VERSION 5.8 ;
BUSBITCHARS "[]" ;
DIVIDERCHAR "/" ;
UNITS
    DATABASE MICRONS 1000 ;
END UNITS

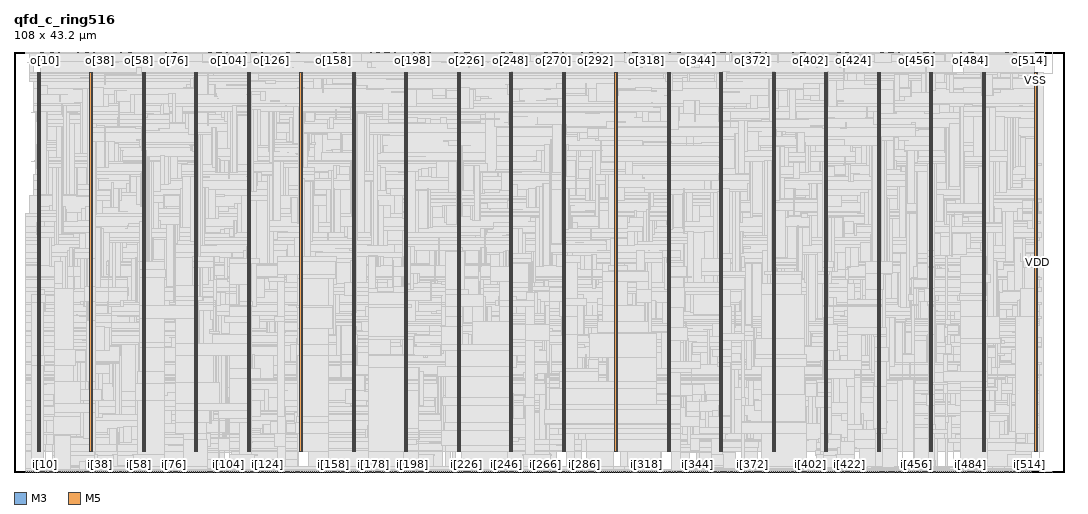
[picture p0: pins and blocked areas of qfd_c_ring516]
MACRO qfd_c_ring516
  FOREIGN qfd_c_ring516 0 0 ;
  CLASS BLOCK ;
  SIZE 108 BY 43.2 ;
  PIN ck_r
    DIRECTION INPUT ;
    USE SIGNAL ;
    PORT
      LAYER M3 ;
        RECT  105.984 43.162 106.002 43.2 ;
    END
  END ck_r
  PIN ck_w
    DIRECTION INPUT ;
    USE SIGNAL ;
    PORT
      LAYER M3 ;
        RECT  105.984 0 106.002 0.038 ;
    END
  END ck_w
  PIN i[0]
    DIRECTION INPUT ;
    USE SIGNAL ;
    PORT
      LAYER M3 ;
        RECT  1.188 0 1.206 0.038 ;
    END
  END i[0]
  PIN i[100]
    DIRECTION INPUT ;
    USE SIGNAL ;
    PORT
      LAYER M3 ;
        RECT  21.276 0 21.294 0.038 ;
    END
  END i[100]
  PIN i[101]
    DIRECTION INPUT ;
    USE SIGNAL ;
    PORT
      LAYER M5 ;
        RECT  21.456 0 21.48 0.084 ;
    END
  END i[101]
  PIN i[102]
    DIRECTION INPUT ;
    USE SIGNAL ;
    PORT
      LAYER M3 ;
        RECT  21.672 0 21.69 0.038 ;
    END
  END i[102]
  PIN i[103]
    DIRECTION INPUT ;
    USE SIGNAL ;
    PORT
      LAYER M5 ;
        RECT  21.888 0 21.912 0.084 ;
    END
  END i[103]
  PIN i[104]
    DIRECTION INPUT ;
    USE SIGNAL ;
    PORT
      LAYER M3 ;
        RECT  22.068 0 22.086 0.038 ;
    END
  END i[104]
  PIN i[105]
    DIRECTION INPUT ;
    USE SIGNAL ;
    PORT
      LAYER M5 ;
        RECT  22.272 0 22.296 0.084 ;
    END
  END i[105]
  PIN i[106]
    DIRECTION INPUT ;
    USE SIGNAL ;
    PORT
      LAYER M3 ;
        RECT  22.464 0 22.482 0.038 ;
    END
  END i[106]
  PIN i[107]
    DIRECTION INPUT ;
    USE SIGNAL ;
    PORT
      LAYER M5 ;
        RECT  22.656 0 22.68 0.084 ;
    END
  END i[107]
  PIN i[108]
    DIRECTION INPUT ;
    USE SIGNAL ;
    PORT
      LAYER M3 ;
        RECT  22.86 0 22.878 0.038 ;
    END
  END i[108]
  PIN i[109]
    DIRECTION INPUT ;
    USE SIGNAL ;
    PORT
      LAYER M5 ;
        RECT  23.088 0 23.112 0.084 ;
    END
  END i[109]
  PIN i[10]
    DIRECTION INPUT ;
    USE SIGNAL ;
    PORT
      LAYER M3 ;
        RECT  3.168 0 3.186 0.038 ;
    END
  END i[10]
  PIN i[110]
    DIRECTION INPUT ;
    USE SIGNAL ;
    PORT
      LAYER M3 ;
        RECT  23.292 0 23.31 0.038 ;
    END
  END i[110]
  PIN i[111]
    DIRECTION INPUT ;
    USE SIGNAL ;
    PORT
      LAYER M5 ;
        RECT  23.472 0 23.496 0.084 ;
    END
  END i[111]
  PIN i[112]
    DIRECTION INPUT ;
    USE SIGNAL ;
    PORT
      LAYER M3 ;
        RECT  23.688 0 23.706 0.038 ;
    END
  END i[112]
  PIN i[113]
    DIRECTION INPUT ;
    USE SIGNAL ;
    PORT
      LAYER M5 ;
        RECT  23.856 0 23.88 0.084 ;
    END
  END i[113]
  PIN i[114]
    DIRECTION INPUT ;
    USE SIGNAL ;
    PORT
      LAYER M3 ;
        RECT  24.084 0 24.102 0.038 ;
    END
  END i[114]
  PIN i[115]
    DIRECTION INPUT ;
    USE SIGNAL ;
    PORT
      LAYER M5 ;
        RECT  24.288 0 24.312 0.084 ;
    END
  END i[115]
  PIN i[116]
    DIRECTION INPUT ;
    USE SIGNAL ;
    PORT
      LAYER M3 ;
        RECT  24.48 0 24.498 0.038 ;
    END
  END i[116]
  PIN i[117]
    DIRECTION INPUT ;
    USE SIGNAL ;
    PORT
      LAYER M5 ;
        RECT  24.672 0 24.696 0.084 ;
    END
  END i[117]
  PIN i[118]
    DIRECTION INPUT ;
    USE SIGNAL ;
    PORT
      LAYER M3 ;
        RECT  24.876 0 24.894 0.038 ;
    END
  END i[118]
  PIN i[119]
    DIRECTION INPUT ;
    USE SIGNAL ;
    PORT
      LAYER M5 ;
        RECT  25.056 0 25.08 0.084 ;
    END
  END i[119]
  PIN i[11]
    DIRECTION INPUT ;
    USE SIGNAL ;
    PORT
      LAYER M5 ;
        RECT  3.36 0 3.384 0.084 ;
    END
  END i[11]
  PIN i[120]
    DIRECTION INPUT ;
    USE SIGNAL ;
    PORT
      LAYER M3 ;
        RECT  25.272 0 25.29 0.038 ;
    END
  END i[120]
  PIN i[121]
    DIRECTION INPUT ;
    USE SIGNAL ;
    PORT
      LAYER M5 ;
        RECT  25.488 0 25.512 0.084 ;
    END
  END i[121]
  PIN i[122]
    DIRECTION INPUT ;
    USE SIGNAL ;
    PORT
      LAYER M3 ;
        RECT  25.668 0 25.686 0.038 ;
    END
  END i[122]
  PIN i[123]
    DIRECTION INPUT ;
    USE SIGNAL ;
    PORT
      LAYER M5 ;
        RECT  25.872 0 25.896 0.084 ;
    END
  END i[123]
  PIN i[124]
    DIRECTION INPUT ;
    USE SIGNAL ;
    PORT
      LAYER M3 ;
        RECT  26.1 0 26.118 0.038 ;
    END
  END i[124]
  PIN i[125]
    DIRECTION INPUT ;
    USE SIGNAL ;
    PORT
      LAYER M5 ;
        RECT  26.304 0 26.328 0.084 ;
    END
  END i[125]
  PIN i[126]
    DIRECTION INPUT ;
    USE SIGNAL ;
    PORT
      LAYER M3 ;
        RECT  26.496 0 26.514 0.038 ;
    END
  END i[126]
  PIN i[127]
    DIRECTION INPUT ;
    USE SIGNAL ;
    PORT
      LAYER M5 ;
        RECT  26.688 0 26.712 0.084 ;
    END
  END i[127]
  PIN i[128]
    DIRECTION INPUT ;
    USE SIGNAL ;
    PORT
      LAYER M3 ;
        RECT  26.892 0 26.91 0.038 ;
    END
  END i[128]
  PIN i[129]
    DIRECTION INPUT ;
    USE SIGNAL ;
    PORT
      LAYER M5 ;
        RECT  27.072 0 27.096 0.084 ;
    END
  END i[129]
  PIN i[12]
    DIRECTION INPUT ;
    USE SIGNAL ;
    PORT
      LAYER M3 ;
        RECT  3.6 0 3.618 0.038 ;
    END
  END i[12]
  PIN i[130]
    DIRECTION INPUT ;
    USE SIGNAL ;
    PORT
      LAYER M3 ;
        RECT  27.288 0 27.306 0.038 ;
    END
  END i[130]
  PIN i[131]
    DIRECTION INPUT ;
    USE SIGNAL ;
    PORT
      LAYER M5 ;
        RECT  27.504 0 27.528 0.084 ;
    END
  END i[131]
  PIN i[132]
    DIRECTION INPUT ;
    USE SIGNAL ;
    PORT
      LAYER M3 ;
        RECT  27.684 0 27.702 0.038 ;
    END
  END i[132]
  PIN i[133]
    DIRECTION INPUT ;
    USE SIGNAL ;
    PORT
      LAYER M5 ;
        RECT  27.888 0 27.912 0.084 ;
    END
  END i[133]
  PIN i[134]
    DIRECTION INPUT ;
    USE SIGNAL ;
    PORT
      LAYER M3 ;
        RECT  28.08 0 28.098 0.038 ;
    END
  END i[134]
  PIN i[135]
    DIRECTION INPUT ;
    USE SIGNAL ;
    PORT
      LAYER M5 ;
        RECT  28.272 0 28.296 0.084 ;
    END
  END i[135]
  PIN i[136]
    DIRECTION INPUT ;
    USE SIGNAL ;
    PORT
      LAYER M3 ;
        RECT  28.512 0 28.53 0.038 ;
    END
  END i[136]
  PIN i[137]
    DIRECTION INPUT ;
    USE SIGNAL ;
    PORT
      LAYER M5 ;
        RECT  28.704 0 28.728 0.084 ;
    END
  END i[137]
  PIN i[138]
    DIRECTION INPUT ;
    USE SIGNAL ;
    PORT
      LAYER M3 ;
        RECT  28.908 0 28.926 0.038 ;
    END
  END i[138]
  PIN i[139]
    DIRECTION INPUT ;
    USE SIGNAL ;
    PORT
      LAYER M5 ;
        RECT  29.088 0 29.112 0.084 ;
    END
  END i[139]
  PIN i[13]
    DIRECTION INPUT ;
    USE SIGNAL ;
    PORT
      LAYER M5 ;
        RECT  3.792 0 3.816 0.084 ;
    END
  END i[13]
  PIN i[140]
    DIRECTION INPUT ;
    USE SIGNAL ;
    PORT
      LAYER M3 ;
        RECT  29.304 0 29.322 0.038 ;
    END
  END i[140]
  PIN i[141]
    DIRECTION INPUT ;
    USE SIGNAL ;
    PORT
      LAYER M5 ;
        RECT  29.52 0 29.544 0.084 ;
    END
  END i[141]
  PIN i[142]
    DIRECTION INPUT ;
    USE SIGNAL ;
    PORT
      LAYER M3 ;
        RECT  29.7 0 29.718 0.038 ;
    END
  END i[142]
  PIN i[143]
    DIRECTION INPUT ;
    USE SIGNAL ;
    PORT
      LAYER M5 ;
        RECT  29.904 0 29.928 0.084 ;
    END
  END i[143]
  PIN i[144]
    DIRECTION INPUT ;
    USE SIGNAL ;
    PORT
      LAYER M3 ;
        RECT  30.096 0 30.114 0.038 ;
    END
  END i[144]
  PIN i[145]
    DIRECTION INPUT ;
    USE SIGNAL ;
    PORT
      LAYER M5 ;
        RECT  30.288 0 30.312 0.084 ;
    END
  END i[145]
  PIN i[146]
    DIRECTION INPUT ;
    USE SIGNAL ;
    PORT
      LAYER M3 ;
        RECT  30.492 0 30.51 0.038 ;
    END
  END i[146]
  PIN i[147]
    DIRECTION INPUT ;
    USE SIGNAL ;
    PORT
      LAYER M5 ;
        RECT  30.72 0 30.744 0.084 ;
    END
  END i[147]
  PIN i[148]
    DIRECTION INPUT ;
    USE SIGNAL ;
    PORT
      LAYER M3 ;
        RECT  30.924 0 30.942 0.038 ;
    END
  END i[148]
  PIN i[149]
    DIRECTION INPUT ;
    USE SIGNAL ;
    PORT
      LAYER M5 ;
        RECT  31.104 0 31.128 0.084 ;
    END
  END i[149]
  PIN i[14]
    DIRECTION INPUT ;
    USE SIGNAL ;
    PORT
      LAYER M3 ;
        RECT  3.996 0 4.014 0.038 ;
    END
  END i[14]
  PIN i[150]
    DIRECTION INPUT ;
    USE SIGNAL ;
    PORT
      LAYER M3 ;
        RECT  31.32 0 31.338 0.038 ;
    END
  END i[150]
  PIN i[151]
    DIRECTION INPUT ;
    USE SIGNAL ;
    PORT
      LAYER M5 ;
        RECT  31.488 0 31.512 0.084 ;
    END
  END i[151]
  PIN i[152]
    DIRECTION INPUT ;
    USE SIGNAL ;
    PORT
      LAYER M3 ;
        RECT  31.716 0 31.734 0.038 ;
    END
  END i[152]
  PIN i[153]
    DIRECTION INPUT ;
    USE SIGNAL ;
    PORT
      LAYER M5 ;
        RECT  31.92 0 31.944 0.084 ;
    END
  END i[153]
  PIN i[154]
    DIRECTION INPUT ;
    USE SIGNAL ;
    PORT
      LAYER M3 ;
        RECT  32.112 0 32.13 0.038 ;
    END
  END i[154]
  PIN i[155]
    DIRECTION INPUT ;
    USE SIGNAL ;
    PORT
      LAYER M5 ;
        RECT  32.304 0 32.328 0.084 ;
    END
  END i[155]
  PIN i[156]
    DIRECTION INPUT ;
    USE SIGNAL ;
    PORT
      LAYER M3 ;
        RECT  32.508 0 32.526 0.038 ;
    END
  END i[156]
  PIN i[157]
    DIRECTION INPUT ;
    USE SIGNAL ;
    PORT
      LAYER M5 ;
        RECT  32.736 0 32.76 0.084 ;
    END
  END i[157]
  PIN i[158]
    DIRECTION INPUT ;
    USE SIGNAL ;
    PORT
      LAYER M3 ;
        RECT  32.904 0 32.922 0.038 ;
    END
  END i[158]
  PIN i[159]
    DIRECTION INPUT ;
    USE SIGNAL ;
    PORT
      LAYER M5 ;
        RECT  33.12 0 33.144 0.084 ;
    END
  END i[159]
  PIN i[15]
    DIRECTION INPUT ;
    USE SIGNAL ;
    PORT
      LAYER M5 ;
        RECT  4.176 0 4.2 0.084 ;
    END
  END i[15]
  PIN i[160]
    DIRECTION INPUT ;
    USE SIGNAL ;
    PORT
      LAYER M3 ;
        RECT  33.336 0 33.354 0.038 ;
    END
  END i[160]
  PIN i[161]
    DIRECTION INPUT ;
    USE SIGNAL ;
    PORT
      LAYER M5 ;
        RECT  33.504 0 33.528 0.084 ;
    END
  END i[161]
  PIN i[162]
    DIRECTION INPUT ;
    USE SIGNAL ;
    PORT
      LAYER M3 ;
        RECT  33.732 0 33.75 0.038 ;
    END
  END i[162]
  PIN i[163]
    DIRECTION INPUT ;
    USE SIGNAL ;
    PORT
      LAYER M5 ;
        RECT  33.936 0 33.96 0.084 ;
    END
  END i[163]
  PIN i[164]
    DIRECTION INPUT ;
    USE SIGNAL ;
    PORT
      LAYER M3 ;
        RECT  34.128 0 34.146 0.038 ;
    END
  END i[164]
  PIN i[165]
    DIRECTION INPUT ;
    USE SIGNAL ;
    PORT
      LAYER M5 ;
        RECT  34.32 0 34.344 0.084 ;
    END
  END i[165]
  PIN i[166]
    DIRECTION INPUT ;
    USE SIGNAL ;
    PORT
      LAYER M3 ;
        RECT  34.524 0 34.542 0.038 ;
    END
  END i[166]
  PIN i[167]
    DIRECTION INPUT ;
    USE SIGNAL ;
    PORT
      LAYER M5 ;
        RECT  34.704 0 34.728 0.084 ;
    END
  END i[167]
  PIN i[168]
    DIRECTION INPUT ;
    USE SIGNAL ;
    PORT
      LAYER M3 ;
        RECT  34.92 0 34.938 0.038 ;
    END
  END i[168]
  PIN i[169]
    DIRECTION INPUT ;
    USE SIGNAL ;
    PORT
      LAYER M5 ;
        RECT  35.136 0 35.16 0.084 ;
    END
  END i[169]
  PIN i[16]
    DIRECTION INPUT ;
    USE SIGNAL ;
    PORT
      LAYER M3 ;
        RECT  4.392 0 4.41 0.038 ;
    END
  END i[16]
  PIN i[170]
    DIRECTION INPUT ;
    USE SIGNAL ;
    PORT
      LAYER M3 ;
        RECT  35.316 0 35.334 0.038 ;
    END
  END i[170]
  PIN i[171]
    DIRECTION INPUT ;
    USE SIGNAL ;
    PORT
      LAYER M5 ;
        RECT  35.52 0 35.544 0.084 ;
    END
  END i[171]
  PIN i[172]
    DIRECTION INPUT ;
    USE SIGNAL ;
    PORT
      LAYER M3 ;
        RECT  35.748 0 35.766 0.038 ;
    END
  END i[172]
  PIN i[173]
    DIRECTION INPUT ;
    USE SIGNAL ;
    PORT
      LAYER M5 ;
        RECT  35.952 0 35.976 0.084 ;
    END
  END i[173]
  PIN i[174]
    DIRECTION INPUT ;
    USE SIGNAL ;
    PORT
      LAYER M3 ;
        RECT  36.144 0 36.162 0.038 ;
    END
  END i[174]
  PIN i[175]
    DIRECTION INPUT ;
    USE SIGNAL ;
    PORT
      LAYER M5 ;
        RECT  36.336 0 36.36 0.084 ;
    END
  END i[175]
  PIN i[176]
    DIRECTION INPUT ;
    USE SIGNAL ;
    PORT
      LAYER M3 ;
        RECT  36.54 0 36.558 0.038 ;
    END
  END i[176]
  PIN i[177]
    DIRECTION INPUT ;
    USE SIGNAL ;
    PORT
      LAYER M5 ;
        RECT  36.72 0 36.744 0.084 ;
    END
  END i[177]
  PIN i[178]
    DIRECTION INPUT ;
    USE SIGNAL ;
    PORT
      LAYER M3 ;
        RECT  36.936 0 36.954 0.038 ;
    END
  END i[178]
  PIN i[179]
    DIRECTION INPUT ;
    USE SIGNAL ;
    PORT
      LAYER M5 ;
        RECT  37.152 0 37.176 0.084 ;
    END
  END i[179]
  PIN i[17]
    DIRECTION INPUT ;
    USE SIGNAL ;
    PORT
      LAYER M5 ;
        RECT  4.608 0 4.632 0.084 ;
    END
  END i[17]
  PIN i[180]
    DIRECTION INPUT ;
    USE SIGNAL ;
    PORT
      LAYER M3 ;
        RECT  37.332 0 37.35 0.038 ;
    END
  END i[180]
  PIN i[181]
    DIRECTION INPUT ;
    USE SIGNAL ;
    PORT
      LAYER M5 ;
        RECT  37.536 0 37.56 0.084 ;
    END
  END i[181]
  PIN i[182]
    DIRECTION INPUT ;
    USE SIGNAL ;
    PORT
      LAYER M3 ;
        RECT  37.728 0 37.746 0.038 ;
    END
  END i[182]
  PIN i[183]
    DIRECTION INPUT ;
    USE SIGNAL ;
    PORT
      LAYER M5 ;
        RECT  37.92 0 37.944 0.084 ;
    END
  END i[183]
  PIN i[184]
    DIRECTION INPUT ;
    USE SIGNAL ;
    PORT
      LAYER M3 ;
        RECT  38.16 0 38.178 0.038 ;
    END
  END i[184]
  PIN i[185]
    DIRECTION INPUT ;
    USE SIGNAL ;
    PORT
      LAYER M5 ;
        RECT  38.352 0 38.376 0.084 ;
    END
  END i[185]
  PIN i[186]
    DIRECTION INPUT ;
    USE SIGNAL ;
    PORT
      LAYER M3 ;
        RECT  38.556 0 38.574 0.038 ;
    END
  END i[186]
  PIN i[187]
    DIRECTION INPUT ;
    USE SIGNAL ;
    PORT
      LAYER M5 ;
        RECT  38.736 0 38.76 0.084 ;
    END
  END i[187]
  PIN i[188]
    DIRECTION INPUT ;
    USE SIGNAL ;
    PORT
      LAYER M3 ;
        RECT  38.952 0 38.97 0.038 ;
    END
  END i[188]
  PIN i[189]
    DIRECTION INPUT ;
    USE SIGNAL ;
    PORT
      LAYER M5 ;
        RECT  39.168 0 39.192 0.084 ;
    END
  END i[189]
  PIN i[18]
    DIRECTION INPUT ;
    USE SIGNAL ;
    PORT
      LAYER M3 ;
        RECT  4.788 0 4.806 0.038 ;
    END
  END i[18]
  PIN i[190]
    DIRECTION INPUT ;
    USE SIGNAL ;
    PORT
      LAYER M3 ;
        RECT  39.348 0 39.366 0.038 ;
    END
  END i[190]
  PIN i[191]
    DIRECTION INPUT ;
    USE SIGNAL ;
    PORT
      LAYER M5 ;
        RECT  39.552 0 39.576 0.084 ;
    END
  END i[191]
  PIN i[192]
    DIRECTION INPUT ;
    USE SIGNAL ;
    PORT
      LAYER M3 ;
        RECT  39.744 0 39.762 0.038 ;
    END
  END i[192]
  PIN i[193]
    DIRECTION INPUT ;
    USE SIGNAL ;
    PORT
      LAYER M5 ;
        RECT  39.936 0 39.96 0.084 ;
    END
  END i[193]
  PIN i[194]
    DIRECTION INPUT ;
    USE SIGNAL ;
    PORT
      LAYER M3 ;
        RECT  40.14 0 40.158 0.038 ;
    END
  END i[194]
  PIN i[195]
    DIRECTION INPUT ;
    USE SIGNAL ;
    PORT
      LAYER M5 ;
        RECT  40.368 0 40.392 0.084 ;
    END
  END i[195]
  PIN i[196]
    DIRECTION INPUT ;
    USE SIGNAL ;
    PORT
      LAYER M3 ;
        RECT  40.572 0 40.59 0.038 ;
    END
  END i[196]
  PIN i[197]
    DIRECTION INPUT ;
    USE SIGNAL ;
    PORT
      LAYER M5 ;
        RECT  40.752 0 40.776 0.084 ;
    END
  END i[197]
  PIN i[198]
    DIRECTION INPUT ;
    USE SIGNAL ;
    PORT
      LAYER M3 ;
        RECT  40.968 0 40.986 0.038 ;
    END
  END i[198]
  PIN i[199]
    DIRECTION INPUT ;
    USE SIGNAL ;
    PORT
      LAYER M5 ;
        RECT  41.136 0 41.16 0.084 ;
    END
  END i[199]
  PIN i[19]
    DIRECTION INPUT ;
    USE SIGNAL ;
    PORT
      LAYER M5 ;
        RECT  4.992 0 5.016 0.084 ;
    END
  END i[19]
  PIN i[1]
    DIRECTION INPUT ;
    USE SIGNAL ;
    PORT
      LAYER M5 ;
        RECT  1.392 0 1.416 0.084 ;
    END
  END i[1]
  PIN i[200]
    DIRECTION INPUT ;
    USE SIGNAL ;
    PORT
      LAYER M3 ;
        RECT  41.364 0 41.382 0.038 ;
    END
  END i[200]
  PIN i[201]
    DIRECTION INPUT ;
    USE SIGNAL ;
    PORT
      LAYER M5 ;
        RECT  41.568 0 41.592 0.084 ;
    END
  END i[201]
  PIN i[202]
    DIRECTION INPUT ;
    USE SIGNAL ;
    PORT
      LAYER M3 ;
        RECT  41.76 0 41.778 0.038 ;
    END
  END i[202]
  PIN i[203]
    DIRECTION INPUT ;
    USE SIGNAL ;
    PORT
      LAYER M5 ;
        RECT  41.952 0 41.976 0.084 ;
    END
  END i[203]
  PIN i[204]
    DIRECTION INPUT ;
    USE SIGNAL ;
    PORT
      LAYER M3 ;
        RECT  42.156 0 42.174 0.038 ;
    END
  END i[204]
  PIN i[205]
    DIRECTION INPUT ;
    USE SIGNAL ;
    PORT
      LAYER M5 ;
        RECT  42.336 0 42.36 0.084 ;
    END
  END i[205]
  PIN i[206]
    DIRECTION INPUT ;
    USE SIGNAL ;
    PORT
      LAYER M3 ;
        RECT  42.552 0 42.57 0.038 ;
    END
  END i[206]
  PIN i[207]
    DIRECTION INPUT ;
    USE SIGNAL ;
    PORT
      LAYER M5 ;
        RECT  42.768 0 42.792 0.084 ;
    END
  END i[207]
  PIN i[208]
    DIRECTION INPUT ;
    USE SIGNAL ;
    PORT
      LAYER M3 ;
        RECT  42.948 0 42.966 0.038 ;
    END
  END i[208]
  PIN i[209]
    DIRECTION INPUT ;
    USE SIGNAL ;
    PORT
      LAYER M5 ;
        RECT  43.152 0 43.176 0.084 ;
    END
  END i[209]
  PIN i[20]
    DIRECTION INPUT ;
    USE SIGNAL ;
    PORT
      LAYER M3 ;
        RECT  5.184 0 5.202 0.038 ;
    END
  END i[20]
  PIN i[210]
    DIRECTION INPUT ;
    USE SIGNAL ;
    PORT
      LAYER M3 ;
        RECT  43.38 0 43.398 0.038 ;
    END
  END i[210]
  PIN i[211]
    DIRECTION INPUT ;
    USE SIGNAL ;
    PORT
      LAYER M5 ;
        RECT  43.584 0 43.608 0.084 ;
    END
  END i[211]
  PIN i[212]
    DIRECTION INPUT ;
    USE SIGNAL ;
    PORT
      LAYER M3 ;
        RECT  43.776 0 43.794 0.038 ;
    END
  END i[212]
  PIN i[213]
    DIRECTION INPUT ;
    USE SIGNAL ;
    PORT
      LAYER M5 ;
        RECT  43.968 0 43.992 0.084 ;
    END
  END i[213]
  PIN i[214]
    DIRECTION INPUT ;
    USE SIGNAL ;
    PORT
      LAYER M3 ;
        RECT  44.172 0 44.19 0.038 ;
    END
  END i[214]
  PIN i[215]
    DIRECTION INPUT ;
    USE SIGNAL ;
    PORT
      LAYER M5 ;
        RECT  44.352 0 44.376 0.084 ;
    END
  END i[215]
  PIN i[216]
    DIRECTION INPUT ;
    USE SIGNAL ;
    PORT
      LAYER M3 ;
        RECT  44.568 0 44.586 0.038 ;
    END
  END i[216]
  PIN i[217]
    DIRECTION INPUT ;
    USE SIGNAL ;
    PORT
      LAYER M5 ;
        RECT  44.784 0 44.808 0.084 ;
    END
  END i[217]
  PIN i[218]
    DIRECTION INPUT ;
    USE SIGNAL ;
    PORT
      LAYER M3 ;
        RECT  44.964 0 44.982 0.038 ;
    END
  END i[218]
  PIN i[219]
    DIRECTION INPUT ;
    USE SIGNAL ;
    PORT
      LAYER M5 ;
        RECT  45.168 0 45.192 0.084 ;
    END
  END i[219]
  PIN i[21]
    DIRECTION INPUT ;
    USE SIGNAL ;
    PORT
      LAYER M5 ;
        RECT  5.376 0 5.4 0.084 ;
    END
  END i[21]
  PIN i[220]
    DIRECTION INPUT ;
    USE SIGNAL ;
    PORT
      LAYER M3 ;
        RECT  45.36 0 45.378 0.038 ;
    END
  END i[220]
  PIN i[221]
    DIRECTION INPUT ;
    USE SIGNAL ;
    PORT
      LAYER M5 ;
        RECT  45.552 0 45.576 0.084 ;
    END
  END i[221]
  PIN i[222]
    DIRECTION INPUT ;
    USE SIGNAL ;
    PORT
      LAYER M3 ;
        RECT  45.792 0 45.81 0.038 ;
    END
  END i[222]
  PIN i[223]
    DIRECTION INPUT ;
    USE SIGNAL ;
    PORT
      LAYER M5 ;
        RECT  45.984 0 46.008 0.084 ;
    END
  END i[223]
  PIN i[224]
    DIRECTION INPUT ;
    USE SIGNAL ;
    PORT
      LAYER M3 ;
        RECT  46.188 0 46.206 0.038 ;
    END
  END i[224]
  PIN i[225]
    DIRECTION INPUT ;
    USE SIGNAL ;
    PORT
      LAYER M5 ;
        RECT  46.368 0 46.392 0.084 ;
    END
  END i[225]
  PIN i[226]
    DIRECTION INPUT ;
    USE SIGNAL ;
    PORT
      LAYER M3 ;
        RECT  46.584 0 46.602 0.038 ;
    END
  END i[226]
  PIN i[227]
    DIRECTION INPUT ;
    USE SIGNAL ;
    PORT
      LAYER M5 ;
        RECT  46.8 0 46.824 0.084 ;
    END
  END i[227]
  PIN i[228]
    DIRECTION INPUT ;
    USE SIGNAL ;
    PORT
      LAYER M3 ;
        RECT  46.98 0 46.998 0.038 ;
    END
  END i[228]
  PIN i[229]
    DIRECTION INPUT ;
    USE SIGNAL ;
    PORT
      LAYER M5 ;
        RECT  47.184 0 47.208 0.084 ;
    END
  END i[229]
  PIN i[22]
    DIRECTION INPUT ;
    USE SIGNAL ;
    PORT
      LAYER M3 ;
        RECT  5.58 0 5.598 0.038 ;
    END
  END i[22]
  PIN i[230]
    DIRECTION INPUT ;
    USE SIGNAL ;
    PORT
      LAYER M3 ;
        RECT  47.376 0 47.394 0.038 ;
    END
  END i[230]
  PIN i[231]
    DIRECTION INPUT ;
    USE SIGNAL ;
    PORT
      LAYER M5 ;
        RECT  47.568 0 47.592 0.084 ;
    END
  END i[231]
  PIN i[232]
    DIRECTION INPUT ;
    USE SIGNAL ;
    PORT
      LAYER M3 ;
        RECT  47.772 0 47.79 0.038 ;
    END
  END i[232]
  PIN i[233]
    DIRECTION INPUT ;
    USE SIGNAL ;
    PORT
      LAYER M5 ;
        RECT  48 0 48.024 0.084 ;
    END
  END i[233]
  PIN i[234]
    DIRECTION INPUT ;
    USE SIGNAL ;
    PORT
      LAYER M3 ;
        RECT  48.204 0 48.222 0.038 ;
    END
  END i[234]
  PIN i[235]
    DIRECTION INPUT ;
    USE SIGNAL ;
    PORT
      LAYER M5 ;
        RECT  48.384 0 48.408 0.084 ;
    END
  END i[235]
  PIN i[236]
    DIRECTION INPUT ;
    USE SIGNAL ;
    PORT
      LAYER M3 ;
        RECT  48.6 0 48.618 0.038 ;
    END
  END i[236]
  PIN i[237]
    DIRECTION INPUT ;
    USE SIGNAL ;
    PORT
      LAYER M5 ;
        RECT  48.768 0 48.792 0.084 ;
    END
  END i[237]
  PIN i[238]
    DIRECTION INPUT ;
    USE SIGNAL ;
    PORT
      LAYER M3 ;
        RECT  48.996 0 49.014 0.038 ;
    END
  END i[238]
  PIN i[239]
    DIRECTION INPUT ;
    USE SIGNAL ;
    PORT
      LAYER M5 ;
        RECT  49.2 0 49.224 0.084 ;
    END
  END i[239]
  PIN i[23]
    DIRECTION INPUT ;
    USE SIGNAL ;
    PORT
      LAYER M5 ;
        RECT  5.808 0 5.832 0.084 ;
    END
  END i[23]
  PIN i[240]
    DIRECTION INPUT ;
    USE SIGNAL ;
    PORT
      LAYER M3 ;
        RECT  49.392 0 49.41 0.038 ;
    END
  END i[240]
  PIN i[241]
    DIRECTION INPUT ;
    USE SIGNAL ;
    PORT
      LAYER M5 ;
        RECT  49.584 0 49.608 0.084 ;
    END
  END i[241]
  PIN i[242]
    DIRECTION INPUT ;
    USE SIGNAL ;
    PORT
      LAYER M3 ;
        RECT  49.788 0 49.806 0.038 ;
    END
  END i[242]
  PIN i[243]
    DIRECTION INPUT ;
    USE SIGNAL ;
    PORT
      LAYER M5 ;
        RECT  50.016 0 50.04 0.084 ;
    END
  END i[243]
  PIN i[244]
    DIRECTION INPUT ;
    USE SIGNAL ;
    PORT
      LAYER M3 ;
        RECT  50.184 0 50.202 0.038 ;
    END
  END i[244]
  PIN i[245]
    DIRECTION INPUT ;
    USE SIGNAL ;
    PORT
      LAYER M5 ;
        RECT  50.4 0 50.424 0.084 ;
    END
  END i[245]
  PIN i[246]
    DIRECTION INPUT ;
    USE SIGNAL ;
    PORT
      LAYER M3 ;
        RECT  50.616 0 50.634 0.038 ;
    END
  END i[246]
  PIN i[247]
    DIRECTION INPUT ;
    USE SIGNAL ;
    PORT
      LAYER M5 ;
        RECT  50.784 0 50.808 0.084 ;
    END
  END i[247]
  PIN i[248]
    DIRECTION INPUT ;
    USE SIGNAL ;
    PORT
      LAYER M3 ;
        RECT  51.012 0 51.03 0.038 ;
    END
  END i[248]
  PIN i[249]
    DIRECTION INPUT ;
    USE SIGNAL ;
    PORT
      LAYER M5 ;
        RECT  51.216 0 51.24 0.084 ;
    END
  END i[249]
  PIN i[24]
    DIRECTION INPUT ;
    USE SIGNAL ;
    PORT
      LAYER M3 ;
        RECT  6.012 0 6.03 0.038 ;
    END
  END i[24]
  PIN i[250]
    DIRECTION INPUT ;
    USE SIGNAL ;
    PORT
      LAYER M3 ;
        RECT  51.408 0 51.426 0.038 ;
    END
  END i[250]
  PIN i[251]
    DIRECTION INPUT ;
    USE SIGNAL ;
    PORT
      LAYER M5 ;
        RECT  51.6 0 51.624 0.084 ;
    END
  END i[251]
  PIN i[252]
    DIRECTION INPUT ;
    USE SIGNAL ;
    PORT
      LAYER M3 ;
        RECT  51.804 0 51.822 0.038 ;
    END
  END i[252]
  PIN i[253]
    DIRECTION INPUT ;
    USE SIGNAL ;
    PORT
      LAYER M5 ;
        RECT  51.984 0 52.008 0.084 ;
    END
  END i[253]
  PIN i[254]
    DIRECTION INPUT ;
    USE SIGNAL ;
    PORT
      LAYER M3 ;
        RECT  52.2 0 52.218 0.038 ;
    END
  END i[254]
  PIN i[255]
    DIRECTION INPUT ;
    USE SIGNAL ;
    PORT
      LAYER M5 ;
        RECT  52.416 0 52.44 0.084 ;
    END
  END i[255]
  PIN i[256]
    DIRECTION INPUT ;
    USE SIGNAL ;
    PORT
      LAYER M3 ;
        RECT  52.596 0 52.614 0.038 ;
    END
  END i[256]
  PIN i[257]
    DIRECTION INPUT ;
    USE SIGNAL ;
    PORT
      LAYER M5 ;
        RECT  52.8 0 52.824 0.084 ;
    END
  END i[257]
  PIN i[258]
    DIRECTION INPUT ;
    USE SIGNAL ;
    PORT
      LAYER M3 ;
        RECT  53.028 0 53.046 0.038 ;
    END
  END i[258]
  PIN i[259]
    DIRECTION INPUT ;
    USE SIGNAL ;
    PORT
      LAYER M5 ;
        RECT  53.232 0 53.256 0.084 ;
    END
  END i[259]
  PIN i[25]
    DIRECTION INPUT ;
    USE SIGNAL ;
    PORT
      LAYER M5 ;
        RECT  6.192 0 6.216 0.084 ;
    END
  END i[25]
  PIN i[260]
    DIRECTION INPUT ;
    USE SIGNAL ;
    PORT
      LAYER M3 ;
        RECT  53.424 0 53.442 0.038 ;
    END
  END i[260]
  PIN i[261]
    DIRECTION INPUT ;
    USE SIGNAL ;
    PORT
      LAYER M5 ;
        RECT  53.616 0 53.64 0.084 ;
    END
  END i[261]
  PIN i[262]
    DIRECTION INPUT ;
    USE SIGNAL ;
    PORT
      LAYER M3 ;
        RECT  53.82 0 53.838 0.038 ;
    END
  END i[262]
  PIN i[263]
    DIRECTION INPUT ;
    USE SIGNAL ;
    PORT
      LAYER M5 ;
        RECT  54 0 54.024 0.084 ;
    END
  END i[263]
  PIN i[264]
    DIRECTION INPUT ;
    USE SIGNAL ;
    PORT
      LAYER M3 ;
        RECT  54.216 0 54.234 0.038 ;
    END
  END i[264]
  PIN i[265]
    DIRECTION INPUT ;
    USE SIGNAL ;
    PORT
      LAYER M5 ;
        RECT  54.432 0 54.456 0.084 ;
    END
  END i[265]
  PIN i[266]
    DIRECTION INPUT ;
    USE SIGNAL ;
    PORT
      LAYER M3 ;
        RECT  54.612 0 54.63 0.038 ;
    END
  END i[266]
  PIN i[267]
    DIRECTION INPUT ;
    USE SIGNAL ;
    PORT
      LAYER M5 ;
        RECT  54.816 0 54.84 0.084 ;
    END
  END i[267]
  PIN i[268]
    DIRECTION INPUT ;
    USE SIGNAL ;
    PORT
      LAYER M3 ;
        RECT  55.008 0 55.026 0.038 ;
    END
  END i[268]
  PIN i[269]
    DIRECTION INPUT ;
    USE SIGNAL ;
    PORT
      LAYER M5 ;
        RECT  55.2 0 55.224 0.084 ;
    END
  END i[269]
  PIN i[26]
    DIRECTION INPUT ;
    USE SIGNAL ;
    PORT
      LAYER M3 ;
        RECT  6.408 0 6.426 0.038 ;
    END
  END i[26]
  PIN i[270]
    DIRECTION INPUT ;
    USE SIGNAL ;
    PORT
      LAYER M3 ;
        RECT  55.44 0 55.458 0.038 ;
    END
  END i[270]
  PIN i[271]
    DIRECTION INPUT ;
    USE SIGNAL ;
    PORT
      LAYER M5 ;
        RECT  55.632 0 55.656 0.084 ;
    END
  END i[271]
  PIN i[272]
    DIRECTION INPUT ;
    USE SIGNAL ;
    PORT
      LAYER M3 ;
        RECT  55.836 0 55.854 0.038 ;
    END
  END i[272]
  PIN i[273]
    DIRECTION INPUT ;
    USE SIGNAL ;
    PORT
      LAYER M5 ;
        RECT  56.016 0 56.04 0.084 ;
    END
  END i[273]
  PIN i[274]
    DIRECTION INPUT ;
    USE SIGNAL ;
    PORT
      LAYER M3 ;
        RECT  56.232 0 56.25 0.038 ;
    END
  END i[274]
  PIN i[275]
    DIRECTION INPUT ;
    USE SIGNAL ;
    PORT
      LAYER M5 ;
        RECT  56.448 0 56.472 0.084 ;
    END
  END i[275]
  PIN i[276]
    DIRECTION INPUT ;
    USE SIGNAL ;
    PORT
      LAYER M3 ;
        RECT  56.628 0 56.646 0.038 ;
    END
  END i[276]
  PIN i[277]
    DIRECTION INPUT ;
    USE SIGNAL ;
    PORT
      LAYER M5 ;
        RECT  56.832 0 56.856 0.084 ;
    END
  END i[277]
  PIN i[278]
    DIRECTION INPUT ;
    USE SIGNAL ;
    PORT
      LAYER M3 ;
        RECT  57.024 0 57.042 0.038 ;
    END
  END i[278]
  PIN i[279]
    DIRECTION INPUT ;
    USE SIGNAL ;
    PORT
      LAYER M5 ;
        RECT  57.216 0 57.24 0.084 ;
    END
  END i[279]
  PIN i[27]
    DIRECTION INPUT ;
    USE SIGNAL ;
    PORT
      LAYER M5 ;
        RECT  6.576 0 6.6 0.084 ;
    END
  END i[27]
  PIN i[280]
    DIRECTION INPUT ;
    USE SIGNAL ;
    PORT
      LAYER M3 ;
        RECT  57.42 0 57.438 0.038 ;
    END
  END i[280]
  PIN i[281]
    DIRECTION INPUT ;
    USE SIGNAL ;
    PORT
      LAYER M5 ;
        RECT  57.648 0 57.672 0.084 ;
    END
  END i[281]
  PIN i[282]
    DIRECTION INPUT ;
    USE SIGNAL ;
    PORT
      LAYER M3 ;
        RECT  57.852 0 57.87 0.038 ;
    END
  END i[282]
  PIN i[283]
    DIRECTION INPUT ;
    USE SIGNAL ;
    PORT
      LAYER M5 ;
        RECT  58.032 0 58.056 0.084 ;
    END
  END i[283]
  PIN i[284]
    DIRECTION INPUT ;
    USE SIGNAL ;
    PORT
      LAYER M3 ;
        RECT  58.248 0 58.266 0.038 ;
    END
  END i[284]
  PIN i[285]
    DIRECTION INPUT ;
    USE SIGNAL ;
    PORT
      LAYER M5 ;
        RECT  58.416 0 58.44 0.084 ;
    END
  END i[285]
  PIN i[286]
    DIRECTION INPUT ;
    USE SIGNAL ;
    PORT
      LAYER M3 ;
        RECT  58.644 0 58.662 0.038 ;
    END
  END i[286]
  PIN i[287]
    DIRECTION INPUT ;
    USE SIGNAL ;
    PORT
      LAYER M5 ;
        RECT  58.848 0 58.872 0.084 ;
    END
  END i[287]
  PIN i[288]
    DIRECTION INPUT ;
    USE SIGNAL ;
    PORT
      LAYER M3 ;
        RECT  59.04 0 59.058 0.038 ;
    END
  END i[288]
  PIN i[289]
    DIRECTION INPUT ;
    USE SIGNAL ;
    PORT
      LAYER M5 ;
        RECT  59.232 0 59.256 0.084 ;
    END
  END i[289]
  PIN i[28]
    DIRECTION INPUT ;
    USE SIGNAL ;
    PORT
      LAYER M3 ;
        RECT  6.804 0 6.822 0.038 ;
    END
  END i[28]
  PIN i[290]
    DIRECTION INPUT ;
    USE SIGNAL ;
    PORT
      LAYER M3 ;
        RECT  59.436 0 59.454 0.038 ;
    END
  END i[290]
  PIN i[291]
    DIRECTION INPUT ;
    USE SIGNAL ;
    PORT
      LAYER M5 ;
        RECT  59.616 0 59.64 0.084 ;
    END
  END i[291]
  PIN i[292]
    DIRECTION INPUT ;
    USE SIGNAL ;
    PORT
      LAYER M3 ;
        RECT  59.832 0 59.85 0.038 ;
    END
  END i[292]
  PIN i[293]
    DIRECTION INPUT ;
    USE SIGNAL ;
    PORT
      LAYER M5 ;
        RECT  60.048 0 60.072 0.084 ;
    END
  END i[293]
  PIN i[294]
    DIRECTION INPUT ;
    USE SIGNAL ;
    PORT
      LAYER M3 ;
        RECT  60.228 0 60.246 0.038 ;
    END
  END i[294]
  PIN i[295]
    DIRECTION INPUT ;
    USE SIGNAL ;
    PORT
      LAYER M5 ;
        RECT  60.432 0 60.456 0.084 ;
    END
  END i[295]
  PIN i[296]
    DIRECTION INPUT ;
    USE SIGNAL ;
    PORT
      LAYER M3 ;
        RECT  60.66 0 60.678 0.038 ;
    END
  END i[296]
  PIN i[297]
    DIRECTION INPUT ;
    USE SIGNAL ;
    PORT
      LAYER M5 ;
        RECT  60.864 0 60.888 0.084 ;
    END
  END i[297]
  PIN i[298]
    DIRECTION INPUT ;
    USE SIGNAL ;
    PORT
      LAYER M3 ;
        RECT  61.056 0 61.074 0.038 ;
    END
  END i[298]
  PIN i[299]
    DIRECTION INPUT ;
    USE SIGNAL ;
    PORT
      LAYER M5 ;
        RECT  61.248 0 61.272 0.084 ;
    END
  END i[299]
  PIN i[29]
    DIRECTION INPUT ;
    USE SIGNAL ;
    PORT
      LAYER M5 ;
        RECT  7.008 0 7.032 0.084 ;
    END
  END i[29]
  PIN i[2]
    DIRECTION INPUT ;
    USE SIGNAL ;
    PORT
      LAYER M3 ;
        RECT  1.584 0 1.602 0.038 ;
    END
  END i[2]
  PIN i[300]
    DIRECTION INPUT ;
    USE SIGNAL ;
    PORT
      LAYER M3 ;
        RECT  61.452 0 61.47 0.038 ;
    END
  END i[300]
  PIN i[301]
    DIRECTION INPUT ;
    USE SIGNAL ;
    PORT
      LAYER M5 ;
        RECT  61.632 0 61.656 0.084 ;
    END
  END i[301]
  PIN i[302]
    DIRECTION INPUT ;
    USE SIGNAL ;
    PORT
      LAYER M3 ;
        RECT  61.848 0 61.866 0.038 ;
    END
  END i[302]
  PIN i[303]
    DIRECTION INPUT ;
    USE SIGNAL ;
    PORT
      LAYER M5 ;
        RECT  62.064 0 62.088 0.084 ;
    END
  END i[303]
  PIN i[304]
    DIRECTION INPUT ;
    USE SIGNAL ;
    PORT
      LAYER M3 ;
        RECT  62.244 0 62.262 0.038 ;
    END
  END i[304]
  PIN i[305]
    DIRECTION INPUT ;
    USE SIGNAL ;
    PORT
      LAYER M5 ;
        RECT  62.448 0 62.472 0.084 ;
    END
  END i[305]
  PIN i[306]
    DIRECTION INPUT ;
    USE SIGNAL ;
    PORT
      LAYER M3 ;
        RECT  62.64 0 62.658 0.038 ;
    END
  END i[306]
  PIN i[307]
    DIRECTION INPUT ;
    USE SIGNAL ;
    PORT
      LAYER M5 ;
        RECT  62.832 0 62.856 0.084 ;
    END
  END i[307]
  PIN i[308]
    DIRECTION INPUT ;
    USE SIGNAL ;
    PORT
      LAYER M3 ;
        RECT  63.072 0 63.09 0.038 ;
    END
  END i[308]
  PIN i[309]
    DIRECTION INPUT ;
    USE SIGNAL ;
    PORT
      LAYER M5 ;
        RECT  63.264 0 63.288 0.084 ;
    END
  END i[309]
  PIN i[30]
    DIRECTION INPUT ;
    USE SIGNAL ;
    PORT
      LAYER M3 ;
        RECT  7.2 0 7.218 0.038 ;
    END
  END i[30]
  PIN i[310]
    DIRECTION INPUT ;
    USE SIGNAL ;
    PORT
      LAYER M3 ;
        RECT  63.468 0 63.486 0.038 ;
    END
  END i[310]
  PIN i[311]
    DIRECTION INPUT ;
    USE SIGNAL ;
    PORT
      LAYER M5 ;
        RECT  63.648 0 63.672 0.084 ;
    END
  END i[311]
  PIN i[312]
    DIRECTION INPUT ;
    USE SIGNAL ;
    PORT
      LAYER M3 ;
        RECT  63.864 0 63.882 0.038 ;
    END
  END i[312]
  PIN i[313]
    DIRECTION INPUT ;
    USE SIGNAL ;
    PORT
      LAYER M5 ;
        RECT  64.08 0 64.104 0.084 ;
    END
  END i[313]
  PIN i[314]
    DIRECTION INPUT ;
    USE SIGNAL ;
    PORT
      LAYER M3 ;
        RECT  64.26 0 64.278 0.038 ;
    END
  END i[314]
  PIN i[315]
    DIRECTION INPUT ;
    USE SIGNAL ;
    PORT
      LAYER M5 ;
        RECT  64.464 0 64.488 0.084 ;
    END
  END i[315]
  PIN i[316]
    DIRECTION INPUT ;
    USE SIGNAL ;
    PORT
      LAYER M3 ;
        RECT  64.656 0 64.674 0.038 ;
    END
  END i[316]
  PIN i[317]
    DIRECTION INPUT ;
    USE SIGNAL ;
    PORT
      LAYER M5 ;
        RECT  64.848 0 64.872 0.084 ;
    END
  END i[317]
  PIN i[318]
    DIRECTION INPUT ;
    USE SIGNAL ;
    PORT
      LAYER M3 ;
        RECT  65.052 0 65.07 0.038 ;
    END
  END i[318]
  PIN i[319]
    DIRECTION INPUT ;
    USE SIGNAL ;
    PORT
      LAYER M5 ;
        RECT  65.28 0 65.304 0.084 ;
    END
  END i[319]
  PIN i[31]
    DIRECTION INPUT ;
    USE SIGNAL ;
    PORT
      LAYER M5 ;
        RECT  7.392 0 7.416 0.084 ;
    END
  END i[31]
  PIN i[320]
    DIRECTION INPUT ;
    USE SIGNAL ;
    PORT
      LAYER M3 ;
        RECT  65.484 0 65.502 0.038 ;
    END
  END i[320]
  PIN i[321]
    DIRECTION INPUT ;
    USE SIGNAL ;
    PORT
      LAYER M5 ;
        RECT  65.664 0 65.688 0.084 ;
    END
  END i[321]
  PIN i[322]
    DIRECTION INPUT ;
    USE SIGNAL ;
    PORT
      LAYER M3 ;
        RECT  65.88 0 65.898 0.038 ;
    END
  END i[322]
  PIN i[323]
    DIRECTION INPUT ;
    USE SIGNAL ;
    PORT
      LAYER M5 ;
        RECT  66.048 0 66.072 0.084 ;
    END
  END i[323]
  PIN i[324]
    DIRECTION INPUT ;
    USE SIGNAL ;
    PORT
      LAYER M3 ;
        RECT  66.276 0 66.294 0.038 ;
    END
  END i[324]
  PIN i[325]
    DIRECTION INPUT ;
    USE SIGNAL ;
    PORT
      LAYER M5 ;
        RECT  66.48 0 66.504 0.084 ;
    END
  END i[325]
  PIN i[326]
    DIRECTION INPUT ;
    USE SIGNAL ;
    PORT
      LAYER M3 ;
        RECT  66.672 0 66.69 0.038 ;
    END
  END i[326]
  PIN i[327]
    DIRECTION INPUT ;
    USE SIGNAL ;
    PORT
      LAYER M5 ;
        RECT  66.864 0 66.888 0.084 ;
    END
  END i[327]
  PIN i[328]
    DIRECTION INPUT ;
    USE SIGNAL ;
    PORT
      LAYER M3 ;
        RECT  67.068 0 67.086 0.038 ;
    END
  END i[328]
  PIN i[329]
    DIRECTION INPUT ;
    USE SIGNAL ;
    PORT
      LAYER M5 ;
        RECT  67.296 0 67.32 0.084 ;
    END
  END i[329]
  PIN i[32]
    DIRECTION INPUT ;
    USE SIGNAL ;
    PORT
      LAYER M3 ;
        RECT  7.596 0 7.614 0.038 ;
    END
  END i[32]
  PIN i[330]
    DIRECTION INPUT ;
    USE SIGNAL ;
    PORT
      LAYER M3 ;
        RECT  67.464 0 67.482 0.038 ;
    END
  END i[330]
  PIN i[331]
    DIRECTION INPUT ;
    USE SIGNAL ;
    PORT
      LAYER M5 ;
        RECT  67.68 0 67.704 0.084 ;
    END
  END i[331]
  PIN i[332]
    DIRECTION INPUT ;
    USE SIGNAL ;
    PORT
      LAYER M3 ;
        RECT  67.896 0 67.914 0.038 ;
    END
  END i[332]
  PIN i[333]
    DIRECTION INPUT ;
    USE SIGNAL ;
    PORT
      LAYER M5 ;
        RECT  68.064 0 68.088 0.084 ;
    END
  END i[333]
  PIN i[334]
    DIRECTION INPUT ;
    USE SIGNAL ;
    PORT
      LAYER M3 ;
        RECT  68.292 0 68.31 0.038 ;
    END
  END i[334]
  PIN i[335]
    DIRECTION INPUT ;
    USE SIGNAL ;
    PORT
      LAYER M5 ;
        RECT  68.496 0 68.52 0.084 ;
    END
  END i[335]
  PIN i[336]
    DIRECTION INPUT ;
    USE SIGNAL ;
    PORT
      LAYER M3 ;
        RECT  68.688 0 68.706 0.038 ;
    END
  END i[336]
  PIN i[337]
    DIRECTION INPUT ;
    USE SIGNAL ;
    PORT
      LAYER M5 ;
        RECT  68.88 0 68.904 0.084 ;
    END
  END i[337]
  PIN i[338]
    DIRECTION INPUT ;
    USE SIGNAL ;
    PORT
      LAYER M3 ;
        RECT  69.084 0 69.102 0.038 ;
    END
  END i[338]
  PIN i[339]
    DIRECTION INPUT ;
    USE SIGNAL ;
    PORT
      LAYER M5 ;
        RECT  69.264 0 69.288 0.084 ;
    END
  END i[339]
  PIN i[33]
    DIRECTION INPUT ;
    USE SIGNAL ;
    PORT
      LAYER M5 ;
        RECT  7.776 0 7.8 0.084 ;
    END
  END i[33]
  PIN i[340]
    DIRECTION INPUT ;
    USE SIGNAL ;
    PORT
      LAYER M3 ;
        RECT  69.48 0 69.498 0.038 ;
    END
  END i[340]
  PIN i[341]
    DIRECTION INPUT ;
    USE SIGNAL ;
    PORT
      LAYER M5 ;
        RECT  69.696 0 69.72 0.084 ;
    END
  END i[341]
  PIN i[342]
    DIRECTION INPUT ;
    USE SIGNAL ;
    PORT
      LAYER M3 ;
        RECT  69.876 0 69.894 0.038 ;
    END
  END i[342]
  PIN i[343]
    DIRECTION INPUT ;
    USE SIGNAL ;
    PORT
      LAYER M5 ;
        RECT  70.08 0 70.104 0.084 ;
    END
  END i[343]
  PIN i[344]
    DIRECTION INPUT ;
    USE SIGNAL ;
    PORT
      LAYER M3 ;
        RECT  70.308 0 70.326 0.038 ;
    END
  END i[344]
  PIN i[345]
    DIRECTION INPUT ;
    USE SIGNAL ;
    PORT
      LAYER M5 ;
        RECT  70.512 0 70.536 0.084 ;
    END
  END i[345]
  PIN i[346]
    DIRECTION INPUT ;
    USE SIGNAL ;
    PORT
      LAYER M3 ;
        RECT  70.704 0 70.722 0.038 ;
    END
  END i[346]
  PIN i[347]
    DIRECTION INPUT ;
    USE SIGNAL ;
    PORT
      LAYER M5 ;
        RECT  70.896 0 70.92 0.084 ;
    END
  END i[347]
  PIN i[348]
    DIRECTION INPUT ;
    USE SIGNAL ;
    PORT
      LAYER M3 ;
        RECT  71.1 0 71.118 0.038 ;
    END
  END i[348]
  PIN i[349]
    DIRECTION INPUT ;
    USE SIGNAL ;
    PORT
      LAYER M5 ;
        RECT  71.28 0 71.304 0.084 ;
    END
  END i[349]
  PIN i[34]
    DIRECTION INPUT ;
    USE SIGNAL ;
    PORT
      LAYER M3 ;
        RECT  7.992 0 8.01 0.038 ;
    END
  END i[34]
  PIN i[350]
    DIRECTION INPUT ;
    USE SIGNAL ;
    PORT
      LAYER M3 ;
        RECT  71.496 0 71.514 0.038 ;
    END
  END i[350]
  PIN i[351]
    DIRECTION INPUT ;
    USE SIGNAL ;
    PORT
      LAYER M5 ;
        RECT  71.712 0 71.736 0.084 ;
    END
  END i[351]
  PIN i[352]
    DIRECTION INPUT ;
    USE SIGNAL ;
    PORT
      LAYER M3 ;
        RECT  71.892 0 71.91 0.038 ;
    END
  END i[352]
  PIN i[353]
    DIRECTION INPUT ;
    USE SIGNAL ;
    PORT
      LAYER M5 ;
        RECT  72.096 0 72.12 0.084 ;
    END
  END i[353]
  PIN i[354]
    DIRECTION INPUT ;
    USE SIGNAL ;
    PORT
      LAYER M3 ;
        RECT  72.288 0 72.306 0.038 ;
    END
  END i[354]
  PIN i[355]
    DIRECTION INPUT ;
    USE SIGNAL ;
    PORT
      LAYER M5 ;
        RECT  72.48 0 72.504 0.084 ;
    END
  END i[355]
  PIN i[356]
    DIRECTION INPUT ;
    USE SIGNAL ;
    PORT
      LAYER M3 ;
        RECT  72.72 0 72.738 0.038 ;
    END
  END i[356]
  PIN i[357]
    DIRECTION INPUT ;
    USE SIGNAL ;
    PORT
      LAYER M5 ;
        RECT  72.912 0 72.936 0.084 ;
    END
  END i[357]
  PIN i[358]
    DIRECTION INPUT ;
    USE SIGNAL ;
    PORT
      LAYER M3 ;
        RECT  73.116 0 73.134 0.038 ;
    END
  END i[358]
  PIN i[359]
    DIRECTION INPUT ;
    USE SIGNAL ;
    PORT
      LAYER M5 ;
        RECT  73.296 0 73.32 0.084 ;
    END
  END i[359]
  PIN i[35]
    DIRECTION INPUT ;
    USE SIGNAL ;
    PORT
      LAYER M5 ;
        RECT  8.208 0 8.232 0.084 ;
    END
  END i[35]
  PIN i[360]
    DIRECTION INPUT ;
    USE SIGNAL ;
    PORT
      LAYER M3 ;
        RECT  73.512 0 73.53 0.038 ;
    END
  END i[360]
  PIN i[361]
    DIRECTION INPUT ;
    USE SIGNAL ;
    PORT
      LAYER M5 ;
        RECT  73.728 0 73.752 0.084 ;
    END
  END i[361]
  PIN i[362]
    DIRECTION INPUT ;
    USE SIGNAL ;
    PORT
      LAYER M3 ;
        RECT  73.908 0 73.926 0.038 ;
    END
  END i[362]
  PIN i[363]
    DIRECTION INPUT ;
    USE SIGNAL ;
    PORT
      LAYER M5 ;
        RECT  74.112 0 74.136 0.084 ;
    END
  END i[363]
  PIN i[364]
    DIRECTION INPUT ;
    USE SIGNAL ;
    PORT
      LAYER M3 ;
        RECT  74.304 0 74.322 0.038 ;
    END
  END i[364]
  PIN i[365]
    DIRECTION INPUT ;
    USE SIGNAL ;
    PORT
      LAYER M5 ;
        RECT  74.496 0 74.52 0.084 ;
    END
  END i[365]
  PIN i[366]
    DIRECTION INPUT ;
    USE SIGNAL ;
    PORT
      LAYER M3 ;
        RECT  74.7 0 74.718 0.038 ;
    END
  END i[366]
  PIN i[367]
    DIRECTION INPUT ;
    USE SIGNAL ;
    PORT
      LAYER M5 ;
        RECT  74.928 0 74.952 0.084 ;
    END
  END i[367]
  PIN i[368]
    DIRECTION INPUT ;
    USE SIGNAL ;
    PORT
      LAYER M3 ;
        RECT  75.132 0 75.15 0.038 ;
    END
  END i[368]
  PIN i[369]
    DIRECTION INPUT ;
    USE SIGNAL ;
    PORT
      LAYER M5 ;
        RECT  75.312 0 75.336 0.084 ;
    END
  END i[369]
  PIN i[36]
    DIRECTION INPUT ;
    USE SIGNAL ;
    PORT
      LAYER M3 ;
        RECT  8.388 0 8.406 0.038 ;
    END
  END i[36]
  PIN i[370]
    DIRECTION INPUT ;
    USE SIGNAL ;
    PORT
      LAYER M3 ;
        RECT  75.528 0 75.546 0.038 ;
    END
  END i[370]
  PIN i[371]
    DIRECTION INPUT ;
    USE SIGNAL ;
    PORT
      LAYER M5 ;
        RECT  75.696 0 75.72 0.084 ;
    END
  END i[371]
  PIN i[372]
    DIRECTION INPUT ;
    USE SIGNAL ;
    PORT
      LAYER M3 ;
        RECT  75.924 0 75.942 0.038 ;
    END
  END i[372]
  PIN i[373]
    DIRECTION INPUT ;
    USE SIGNAL ;
    PORT
      LAYER M5 ;
        RECT  76.128 0 76.152 0.084 ;
    END
  END i[373]
  PIN i[374]
    DIRECTION INPUT ;
    USE SIGNAL ;
    PORT
      LAYER M3 ;
        RECT  76.32 0 76.338 0.038 ;
    END
  END i[374]
  PIN i[375]
    DIRECTION INPUT ;
    USE SIGNAL ;
    PORT
      LAYER M5 ;
        RECT  76.512 0 76.536 0.084 ;
    END
  END i[375]
  PIN i[376]
    DIRECTION INPUT ;
    USE SIGNAL ;
    PORT
      LAYER M3 ;
        RECT  76.716 0 76.734 0.038 ;
    END
  END i[376]
  PIN i[377]
    DIRECTION INPUT ;
    USE SIGNAL ;
    PORT
      LAYER M5 ;
        RECT  76.896 0 76.92 0.084 ;
    END
  END i[377]
  PIN i[378]
    DIRECTION INPUT ;
    USE SIGNAL ;
    PORT
      LAYER M3 ;
        RECT  77.112 0 77.13 0.038 ;
    END
  END i[378]
  PIN i[379]
    DIRECTION INPUT ;
    USE SIGNAL ;
    PORT
      LAYER M5 ;
        RECT  77.328 0 77.352 0.084 ;
    END
  END i[379]
  PIN i[37]
    DIRECTION INPUT ;
    USE SIGNAL ;
    PORT
      LAYER M5 ;
        RECT  8.592 0 8.616 0.084 ;
    END
  END i[37]
  PIN i[380]
    DIRECTION INPUT ;
    USE SIGNAL ;
    PORT
      LAYER M3 ;
        RECT  77.508 0 77.526 0.038 ;
    END
  END i[380]
  PIN i[381]
    DIRECTION INPUT ;
    USE SIGNAL ;
    PORT
      LAYER M5 ;
        RECT  77.712 0 77.736 0.084 ;
    END
  END i[381]
  PIN i[382]
    DIRECTION INPUT ;
    USE SIGNAL ;
    PORT
      LAYER M3 ;
        RECT  77.94 0 77.958 0.038 ;
    END
  END i[382]
  PIN i[383]
    DIRECTION INPUT ;
    USE SIGNAL ;
    PORT
      LAYER M5 ;
        RECT  78.144 0 78.168 0.084 ;
    END
  END i[383]
  PIN i[384]
    DIRECTION INPUT ;
    USE SIGNAL ;
    PORT
      LAYER M3 ;
        RECT  78.336 0 78.354 0.038 ;
    END
  END i[384]
  PIN i[385]
    DIRECTION INPUT ;
    USE SIGNAL ;
    PORT
      LAYER M5 ;
        RECT  78.528 0 78.552 0.084 ;
    END
  END i[385]
  PIN i[386]
    DIRECTION INPUT ;
    USE SIGNAL ;
    PORT
      LAYER M3 ;
        RECT  78.732 0 78.75 0.038 ;
    END
  END i[386]
  PIN i[387]
    DIRECTION INPUT ;
    USE SIGNAL ;
    PORT
      LAYER M5 ;
        RECT  78.912 0 78.936 0.084 ;
    END
  END i[387]
  PIN i[388]
    DIRECTION INPUT ;
    USE SIGNAL ;
    PORT
      LAYER M3 ;
        RECT  79.128 0 79.146 0.038 ;
    END
  END i[388]
  PIN i[389]
    DIRECTION INPUT ;
    USE SIGNAL ;
    PORT
      LAYER M5 ;
        RECT  79.344 0 79.368 0.084 ;
    END
  END i[389]
  PIN i[38]
    DIRECTION INPUT ;
    USE SIGNAL ;
    PORT
      LAYER M3 ;
        RECT  8.82 0 8.838 0.038 ;
    END
  END i[38]
  PIN i[390]
    DIRECTION INPUT ;
    USE SIGNAL ;
    PORT
      LAYER M3 ;
        RECT  79.524 0 79.542 0.038 ;
    END
  END i[390]
  PIN i[391]
    DIRECTION INPUT ;
    USE SIGNAL ;
    PORT
      LAYER M5 ;
        RECT  79.728 0 79.752 0.084 ;
    END
  END i[391]
  PIN i[392]
    DIRECTION INPUT ;
    USE SIGNAL ;
    PORT
      LAYER M3 ;
        RECT  79.92 0 79.938 0.038 ;
    END
  END i[392]
  PIN i[393]
    DIRECTION INPUT ;
    USE SIGNAL ;
    PORT
      LAYER M5 ;
        RECT  80.112 0 80.136 0.084 ;
    END
  END i[393]
  PIN i[394]
    DIRECTION INPUT ;
    USE SIGNAL ;
    PORT
      LAYER M3 ;
        RECT  80.352 0 80.37 0.038 ;
    END
  END i[394]
  PIN i[395]
    DIRECTION INPUT ;
    USE SIGNAL ;
    PORT
      LAYER M5 ;
        RECT  80.544 0 80.568 0.084 ;
    END
  END i[395]
  PIN i[396]
    DIRECTION INPUT ;
    USE SIGNAL ;
    PORT
      LAYER M3 ;
        RECT  80.748 0 80.766 0.038 ;
    END
  END i[396]
  PIN i[397]
    DIRECTION INPUT ;
    USE SIGNAL ;
    PORT
      LAYER M5 ;
        RECT  80.928 0 80.952 0.084 ;
    END
  END i[397]
  PIN i[398]
    DIRECTION INPUT ;
    USE SIGNAL ;
    PORT
      LAYER M3 ;
        RECT  81.144 0 81.162 0.038 ;
    END
  END i[398]
  PIN i[399]
    DIRECTION INPUT ;
    USE SIGNAL ;
    PORT
      LAYER M5 ;
        RECT  81.36 0 81.384 0.084 ;
    END
  END i[399]
  PIN i[39]
    DIRECTION INPUT ;
    USE SIGNAL ;
    PORT
      LAYER M5 ;
        RECT  9.024 0 9.048 0.084 ;
    END
  END i[39]
  PIN i[3]
    DIRECTION INPUT ;
    USE SIGNAL ;
    PORT
      LAYER M5 ;
        RECT  1.776 0 1.8 0.084 ;
    END
  END i[3]
  PIN i[400]
    DIRECTION INPUT ;
    USE SIGNAL ;
    PORT
      LAYER M3 ;
        RECT  81.54 0 81.558 0.038 ;
    END
  END i[400]
  PIN i[401]
    DIRECTION INPUT ;
    USE SIGNAL ;
    PORT
      LAYER M5 ;
        RECT  81.744 0 81.768 0.084 ;
    END
  END i[401]
  PIN i[402]
    DIRECTION INPUT ;
    USE SIGNAL ;
    PORT
      LAYER M3 ;
        RECT  81.936 0 81.954 0.038 ;
    END
  END i[402]
  PIN i[403]
    DIRECTION INPUT ;
    USE SIGNAL ;
    PORT
      LAYER M5 ;
        RECT  82.128 0 82.152 0.084 ;
    END
  END i[403]
  PIN i[404]
    DIRECTION INPUT ;
    USE SIGNAL ;
    PORT
      LAYER M3 ;
        RECT  82.332 0 82.35 0.038 ;
    END
  END i[404]
  PIN i[405]
    DIRECTION INPUT ;
    USE SIGNAL ;
    PORT
      LAYER M5 ;
        RECT  82.56 0 82.584 0.084 ;
    END
  END i[405]
  PIN i[406]
    DIRECTION INPUT ;
    USE SIGNAL ;
    PORT
      LAYER M3 ;
        RECT  82.764 0 82.782 0.038 ;
    END
  END i[406]
  PIN i[407]
    DIRECTION INPUT ;
    USE SIGNAL ;
    PORT
      LAYER M5 ;
        RECT  82.944 0 82.968 0.084 ;
    END
  END i[407]
  PIN i[408]
    DIRECTION INPUT ;
    USE SIGNAL ;
    PORT
      LAYER M3 ;
        RECT  83.16 0 83.178 0.038 ;
    END
  END i[408]
  PIN i[409]
    DIRECTION INPUT ;
    USE SIGNAL ;
    PORT
      LAYER M5 ;
        RECT  83.328 0 83.352 0.084 ;
    END
  END i[409]
  PIN i[40]
    DIRECTION INPUT ;
    USE SIGNAL ;
    PORT
      LAYER M3 ;
        RECT  9.216 0 9.234 0.038 ;
    END
  END i[40]
  PIN i[410]
    DIRECTION INPUT ;
    USE SIGNAL ;
    PORT
      LAYER M3 ;
        RECT  83.556 0 83.574 0.038 ;
    END
  END i[410]
  PIN i[411]
    DIRECTION INPUT ;
    USE SIGNAL ;
    PORT
      LAYER M5 ;
        RECT  83.76 0 83.784 0.084 ;
    END
  END i[411]
  PIN i[412]
    DIRECTION INPUT ;
    USE SIGNAL ;
    PORT
      LAYER M3 ;
        RECT  83.952 0 83.97 0.038 ;
    END
  END i[412]
  PIN i[413]
    DIRECTION INPUT ;
    USE SIGNAL ;
    PORT
      LAYER M5 ;
        RECT  84.144 0 84.168 0.084 ;
    END
  END i[413]
  PIN i[414]
    DIRECTION INPUT ;
    USE SIGNAL ;
    PORT
      LAYER M3 ;
        RECT  84.348 0 84.366 0.038 ;
    END
  END i[414]
  PIN i[415]
    DIRECTION INPUT ;
    USE SIGNAL ;
    PORT
      LAYER M5 ;
        RECT  84.576 0 84.6 0.084 ;
    END
  END i[415]
  PIN i[416]
    DIRECTION INPUT ;
    USE SIGNAL ;
    PORT
      LAYER M3 ;
        RECT  84.744 0 84.762 0.038 ;
    END
  END i[416]
  PIN i[417]
    DIRECTION INPUT ;
    USE SIGNAL ;
    PORT
      LAYER M5 ;
        RECT  84.96 0 84.984 0.084 ;
    END
  END i[417]
  PIN i[418]
    DIRECTION INPUT ;
    USE SIGNAL ;
    PORT
      LAYER M3 ;
        RECT  85.176 0 85.194 0.038 ;
    END
  END i[418]
  PIN i[419]
    DIRECTION INPUT ;
    USE SIGNAL ;
    PORT
      LAYER M5 ;
        RECT  85.344 0 85.368 0.084 ;
    END
  END i[419]
  PIN i[41]
    DIRECTION INPUT ;
    USE SIGNAL ;
    PORT
      LAYER M5 ;
        RECT  9.408 0 9.432 0.084 ;
    END
  END i[41]
  PIN i[420]
    DIRECTION INPUT ;
    USE SIGNAL ;
    PORT
      LAYER M3 ;
        RECT  85.572 0 85.59 0.038 ;
    END
  END i[420]
  PIN i[421]
    DIRECTION INPUT ;
    USE SIGNAL ;
    PORT
      LAYER M5 ;
        RECT  85.776 0 85.8 0.084 ;
    END
  END i[421]
  PIN i[422]
    DIRECTION INPUT ;
    USE SIGNAL ;
    PORT
      LAYER M3 ;
        RECT  85.968 0 85.986 0.038 ;
    END
  END i[422]
  PIN i[423]
    DIRECTION INPUT ;
    USE SIGNAL ;
    PORT
      LAYER M5 ;
        RECT  86.16 0 86.184 0.084 ;
    END
  END i[423]
  PIN i[424]
    DIRECTION INPUT ;
    USE SIGNAL ;
    PORT
      LAYER M3 ;
        RECT  86.364 0 86.382 0.038 ;
    END
  END i[424]
  PIN i[425]
    DIRECTION INPUT ;
    USE SIGNAL ;
    PORT
      LAYER M5 ;
        RECT  86.544 0 86.568 0.084 ;
    END
  END i[425]
  PIN i[426]
    DIRECTION INPUT ;
    USE SIGNAL ;
    PORT
      LAYER M3 ;
        RECT  86.76 0 86.778 0.038 ;
    END
  END i[426]
  PIN i[427]
    DIRECTION INPUT ;
    USE SIGNAL ;
    PORT
      LAYER M5 ;
        RECT  86.976 0 87 0.084 ;
    END
  END i[427]
  PIN i[428]
    DIRECTION INPUT ;
    USE SIGNAL ;
    PORT
      LAYER M3 ;
        RECT  87.156 0 87.174 0.038 ;
    END
  END i[428]
  PIN i[429]
    DIRECTION INPUT ;
    USE SIGNAL ;
    PORT
      LAYER M5 ;
        RECT  87.36 0 87.384 0.084 ;
    END
  END i[429]
  PIN i[42]
    DIRECTION INPUT ;
    USE SIGNAL ;
    PORT
      LAYER M3 ;
        RECT  9.612 0 9.63 0.038 ;
    END
  END i[42]
  PIN i[430]
    DIRECTION INPUT ;
    USE SIGNAL ;
    PORT
      LAYER M3 ;
        RECT  87.588 0 87.606 0.038 ;
    END
  END i[430]
  PIN i[431]
    DIRECTION INPUT ;
    USE SIGNAL ;
    PORT
      LAYER M5 ;
        RECT  87.792 0 87.816 0.084 ;
    END
  END i[431]
  PIN i[432]
    DIRECTION INPUT ;
    USE SIGNAL ;
    PORT
      LAYER M3 ;
        RECT  87.984 0 88.002 0.038 ;
    END
  END i[432]
  PIN i[433]
    DIRECTION INPUT ;
    USE SIGNAL ;
    PORT
      LAYER M5 ;
        RECT  88.176 0 88.2 0.084 ;
    END
  END i[433]
  PIN i[434]
    DIRECTION INPUT ;
    USE SIGNAL ;
    PORT
      LAYER M3 ;
        RECT  88.38 0 88.398 0.038 ;
    END
  END i[434]
  PIN i[435]
    DIRECTION INPUT ;
    USE SIGNAL ;
    PORT
      LAYER M5 ;
        RECT  88.56 0 88.584 0.084 ;
    END
  END i[435]
  PIN i[436]
    DIRECTION INPUT ;
    USE SIGNAL ;
    PORT
      LAYER M3 ;
        RECT  88.776 0 88.794 0.038 ;
    END
  END i[436]
  PIN i[437]
    DIRECTION INPUT ;
    USE SIGNAL ;
    PORT
      LAYER M5 ;
        RECT  88.992 0 89.016 0.084 ;
    END
  END i[437]
  PIN i[438]
    DIRECTION INPUT ;
    USE SIGNAL ;
    PORT
      LAYER M3 ;
        RECT  89.172 0 89.19 0.038 ;
    END
  END i[438]
  PIN i[439]
    DIRECTION INPUT ;
    USE SIGNAL ;
    PORT
      LAYER M5 ;
        RECT  89.376 0 89.4 0.084 ;
    END
  END i[439]
  PIN i[43]
    DIRECTION INPUT ;
    USE SIGNAL ;
    PORT
      LAYER M5 ;
        RECT  9.792 0 9.816 0.084 ;
    END
  END i[43]
  PIN i[440]
    DIRECTION INPUT ;
    USE SIGNAL ;
    PORT
      LAYER M3 ;
        RECT  89.568 0 89.586 0.038 ;
    END
  END i[440]
  PIN i[441]
    DIRECTION INPUT ;
    USE SIGNAL ;
    PORT
      LAYER M5 ;
        RECT  89.76 0 89.784 0.084 ;
    END
  END i[441]
  PIN i[442]
    DIRECTION INPUT ;
    USE SIGNAL ;
    PORT
      LAYER M3 ;
        RECT  90 0 90.018 0.038 ;
    END
  END i[442]
  PIN i[443]
    DIRECTION INPUT ;
    USE SIGNAL ;
    PORT
      LAYER M5 ;
        RECT  90.192 0 90.216 0.084 ;
    END
  END i[443]
  PIN i[444]
    DIRECTION INPUT ;
    USE SIGNAL ;
    PORT
      LAYER M3 ;
        RECT  90.396 0 90.414 0.038 ;
    END
  END i[444]
  PIN i[445]
    DIRECTION INPUT ;
    USE SIGNAL ;
    PORT
      LAYER M5 ;
        RECT  90.576 0 90.6 0.084 ;
    END
  END i[445]
  PIN i[446]
    DIRECTION INPUT ;
    USE SIGNAL ;
    PORT
      LAYER M3 ;
        RECT  90.792 0 90.81 0.038 ;
    END
  END i[446]
  PIN i[447]
    DIRECTION INPUT ;
    USE SIGNAL ;
    PORT
      LAYER M5 ;
        RECT  91.008 0 91.032 0.084 ;
    END
  END i[447]
  PIN i[448]
    DIRECTION INPUT ;
    USE SIGNAL ;
    PORT
      LAYER M3 ;
        RECT  91.188 0 91.206 0.038 ;
    END
  END i[448]
  PIN i[449]
    DIRECTION INPUT ;
    USE SIGNAL ;
    PORT
      LAYER M5 ;
        RECT  91.392 0 91.416 0.084 ;
    END
  END i[449]
  PIN i[44]
    DIRECTION INPUT ;
    USE SIGNAL ;
    PORT
      LAYER M3 ;
        RECT  10.008 0 10.026 0.038 ;
    END
  END i[44]
  PIN i[450]
    DIRECTION INPUT ;
    USE SIGNAL ;
    PORT
      LAYER M3 ;
        RECT  91.584 0 91.602 0.038 ;
    END
  END i[450]
  PIN i[451]
    DIRECTION INPUT ;
    USE SIGNAL ;
    PORT
      LAYER M5 ;
        RECT  91.776 0 91.8 0.084 ;
    END
  END i[451]
  PIN i[452]
    DIRECTION INPUT ;
    USE SIGNAL ;
    PORT
      LAYER M3 ;
        RECT  91.98 0 91.998 0.038 ;
    END
  END i[452]
  PIN i[453]
    DIRECTION INPUT ;
    USE SIGNAL ;
    PORT
      LAYER M5 ;
        RECT  92.208 0 92.232 0.084 ;
    END
  END i[453]
  PIN i[454]
    DIRECTION INPUT ;
    USE SIGNAL ;
    PORT
      LAYER M3 ;
        RECT  92.412 0 92.43 0.038 ;
    END
  END i[454]
  PIN i[455]
    DIRECTION INPUT ;
    USE SIGNAL ;
    PORT
      LAYER M5 ;
        RECT  92.592 0 92.616 0.084 ;
    END
  END i[455]
  PIN i[456]
    DIRECTION INPUT ;
    USE SIGNAL ;
    PORT
      LAYER M3 ;
        RECT  92.808 0 92.826 0.038 ;
    END
  END i[456]
  PIN i[457]
    DIRECTION INPUT ;
    USE SIGNAL ;
    PORT
      LAYER M5 ;
        RECT  92.976 0 93 0.084 ;
    END
  END i[457]
  PIN i[458]
    DIRECTION INPUT ;
    USE SIGNAL ;
    PORT
      LAYER M3 ;
        RECT  93.204 0 93.222 0.038 ;
    END
  END i[458]
  PIN i[459]
    DIRECTION INPUT ;
    USE SIGNAL ;
    PORT
      LAYER M5 ;
        RECT  93.408 0 93.432 0.084 ;
    END
  END i[459]
  PIN i[45]
    DIRECTION INPUT ;
    USE SIGNAL ;
    PORT
      LAYER M5 ;
        RECT  10.224 0 10.248 0.084 ;
    END
  END i[45]
  PIN i[460]
    DIRECTION INPUT ;
    USE SIGNAL ;
    PORT
      LAYER M3 ;
        RECT  93.6 0 93.618 0.038 ;
    END
  END i[460]
  PIN i[461]
    DIRECTION INPUT ;
    USE SIGNAL ;
    PORT
      LAYER M5 ;
        RECT  93.792 0 93.816 0.084 ;
    END
  END i[461]
  PIN i[462]
    DIRECTION INPUT ;
    USE SIGNAL ;
    PORT
      LAYER M3 ;
        RECT  93.996 0 94.014 0.038 ;
    END
  END i[462]
  PIN i[463]
    DIRECTION INPUT ;
    USE SIGNAL ;
    PORT
      LAYER M5 ;
        RECT  94.176 0 94.2 0.084 ;
    END
  END i[463]
  PIN i[464]
    DIRECTION INPUT ;
    USE SIGNAL ;
    PORT
      LAYER M3 ;
        RECT  94.392 0 94.41 0.038 ;
    END
  END i[464]
  PIN i[465]
    DIRECTION INPUT ;
    USE SIGNAL ;
    PORT
      LAYER M5 ;
        RECT  94.608 0 94.632 0.084 ;
    END
  END i[465]
  PIN i[466]
    DIRECTION INPUT ;
    USE SIGNAL ;
    PORT
      LAYER M3 ;
        RECT  94.788 0 94.806 0.038 ;
    END
  END i[466]
  PIN i[467]
    DIRECTION INPUT ;
    USE SIGNAL ;
    PORT
      LAYER M5 ;
        RECT  94.992 0 95.016 0.084 ;
    END
  END i[467]
  PIN i[468]
    DIRECTION INPUT ;
    USE SIGNAL ;
    PORT
      LAYER M3 ;
        RECT  95.22 0 95.238 0.038 ;
    END
  END i[468]
  PIN i[469]
    DIRECTION INPUT ;
    USE SIGNAL ;
    PORT
      LAYER M5 ;
        RECT  95.424 0 95.448 0.084 ;
    END
  END i[469]
  PIN i[46]
    DIRECTION INPUT ;
    USE SIGNAL ;
    PORT
      LAYER M3 ;
        RECT  10.404 0 10.422 0.038 ;
    END
  END i[46]
  PIN i[470]
    DIRECTION INPUT ;
    USE SIGNAL ;
    PORT
      LAYER M3 ;
        RECT  95.616 0 95.634 0.038 ;
    END
  END i[470]
  PIN i[471]
    DIRECTION INPUT ;
    USE SIGNAL ;
    PORT
      LAYER M5 ;
        RECT  95.808 0 95.832 0.084 ;
    END
  END i[471]
  PIN i[472]
    DIRECTION INPUT ;
    USE SIGNAL ;
    PORT
      LAYER M3 ;
        RECT  96.012 0 96.03 0.038 ;
    END
  END i[472]
  PIN i[473]
    DIRECTION INPUT ;
    USE SIGNAL ;
    PORT
      LAYER M5 ;
        RECT  96.192 0 96.216 0.084 ;
    END
  END i[473]
  PIN i[474]
    DIRECTION INPUT ;
    USE SIGNAL ;
    PORT
      LAYER M3 ;
        RECT  96.408 0 96.426 0.038 ;
    END
  END i[474]
  PIN i[475]
    DIRECTION INPUT ;
    USE SIGNAL ;
    PORT
      LAYER M5 ;
        RECT  96.624 0 96.648 0.084 ;
    END
  END i[475]
  PIN i[476]
    DIRECTION INPUT ;
    USE SIGNAL ;
    PORT
      LAYER M3 ;
        RECT  96.804 0 96.822 0.038 ;
    END
  END i[476]
  PIN i[477]
    DIRECTION INPUT ;
    USE SIGNAL ;
    PORT
      LAYER M5 ;
        RECT  97.008 0 97.032 0.084 ;
    END
  END i[477]
  PIN i[478]
    DIRECTION INPUT ;
    USE SIGNAL ;
    PORT
      LAYER M3 ;
        RECT  97.2 0 97.218 0.038 ;
    END
  END i[478]
  PIN i[479]
    DIRECTION INPUT ;
    USE SIGNAL ;
    PORT
      LAYER M5 ;
        RECT  97.392 0 97.416 0.084 ;
    END
  END i[479]
  PIN i[47]
    DIRECTION INPUT ;
    USE SIGNAL ;
    PORT
      LAYER M5 ;
        RECT  10.608 0 10.632 0.084 ;
    END
  END i[47]
  PIN i[480]
    DIRECTION INPUT ;
    USE SIGNAL ;
    PORT
      LAYER M3 ;
        RECT  97.632 0 97.65 0.038 ;
    END
  END i[480]
  PIN i[481]
    DIRECTION INPUT ;
    USE SIGNAL ;
    PORT
      LAYER M5 ;
        RECT  97.824 0 97.848 0.084 ;
    END
  END i[481]
  PIN i[482]
    DIRECTION INPUT ;
    USE SIGNAL ;
    PORT
      LAYER M3 ;
        RECT  98.028 0 98.046 0.038 ;
    END
  END i[482]
  PIN i[483]
    DIRECTION INPUT ;
    USE SIGNAL ;
    PORT
      LAYER M5 ;
        RECT  98.208 0 98.232 0.084 ;
    END
  END i[483]
  PIN i[484]
    DIRECTION INPUT ;
    USE SIGNAL ;
    PORT
      LAYER M3 ;
        RECT  98.424 0 98.442 0.038 ;
    END
  END i[484]
  PIN i[485]
    DIRECTION INPUT ;
    USE SIGNAL ;
    PORT
      LAYER M5 ;
        RECT  98.64 0 98.664 0.084 ;
    END
  END i[485]
  PIN i[486]
    DIRECTION INPUT ;
    USE SIGNAL ;
    PORT
      LAYER M3 ;
        RECT  98.82 0 98.838 0.038 ;
    END
  END i[486]
  PIN i[487]
    DIRECTION INPUT ;
    USE SIGNAL ;
    PORT
      LAYER M5 ;
        RECT  99.024 0 99.048 0.084 ;
    END
  END i[487]
  PIN i[488]
    DIRECTION INPUT ;
    USE SIGNAL ;
    PORT
      LAYER M3 ;
        RECT  99.216 0 99.234 0.038 ;
    END
  END i[488]
  PIN i[489]
    DIRECTION INPUT ;
    USE SIGNAL ;
    PORT
      LAYER M5 ;
        RECT  99.408 0 99.432 0.084 ;
    END
  END i[489]
  PIN i[48]
    DIRECTION INPUT ;
    USE SIGNAL ;
    PORT
      LAYER M3 ;
        RECT  10.8 0 10.818 0.038 ;
    END
  END i[48]
  PIN i[490]
    DIRECTION INPUT ;
    USE SIGNAL ;
    PORT
      LAYER M3 ;
        RECT  99.612 0 99.63 0.038 ;
    END
  END i[490]
  PIN i[491]
    DIRECTION INPUT ;
    USE SIGNAL ;
    PORT
      LAYER M5 ;
        RECT  99.84 0 99.864 0.084 ;
    END
  END i[491]
  PIN i[492]
    DIRECTION INPUT ;
    USE SIGNAL ;
    PORT
      LAYER M3 ;
        RECT  100.044 0 100.062 0.038 ;
    END
  END i[492]
  PIN i[493]
    DIRECTION INPUT ;
    USE SIGNAL ;
    PORT
      LAYER M5 ;
        RECT  100.224 0 100.248 0.084 ;
    END
  END i[493]
  PIN i[494]
    DIRECTION INPUT ;
    USE SIGNAL ;
    PORT
      LAYER M3 ;
        RECT  100.44 0 100.458 0.038 ;
    END
  END i[494]
  PIN i[495]
    DIRECTION INPUT ;
    USE SIGNAL ;
    PORT
      LAYER M5 ;
        RECT  100.608 0 100.632 0.084 ;
    END
  END i[495]
  PIN i[496]
    DIRECTION INPUT ;
    USE SIGNAL ;
    PORT
      LAYER M3 ;
        RECT  100.836 0 100.854 0.038 ;
    END
  END i[496]
  PIN i[497]
    DIRECTION INPUT ;
    USE SIGNAL ;
    PORT
      LAYER M5 ;
        RECT  101.04 0 101.064 0.084 ;
    END
  END i[497]
  PIN i[498]
    DIRECTION INPUT ;
    USE SIGNAL ;
    PORT
      LAYER M3 ;
        RECT  101.232 0 101.25 0.038 ;
    END
  END i[498]
  PIN i[499]
    DIRECTION INPUT ;
    USE SIGNAL ;
    PORT
      LAYER M5 ;
        RECT  101.424 0 101.448 0.084 ;
    END
  END i[499]
  PIN i[49]
    DIRECTION INPUT ;
    USE SIGNAL ;
    PORT
      LAYER M5 ;
        RECT  10.992 0 11.016 0.084 ;
    END
  END i[49]
  PIN i[4]
    DIRECTION INPUT ;
    USE SIGNAL ;
    PORT
      LAYER M3 ;
        RECT  1.98 0 1.998 0.038 ;
    END
  END i[4]
  PIN i[500]
    DIRECTION INPUT ;
    USE SIGNAL ;
    PORT
      LAYER M3 ;
        RECT  101.628 0 101.646 0.038 ;
    END
  END i[500]
  PIN i[501]
    DIRECTION INPUT ;
    USE SIGNAL ;
    PORT
      LAYER M5 ;
        RECT  101.856 0 101.88 0.084 ;
    END
  END i[501]
  PIN i[502]
    DIRECTION INPUT ;
    USE SIGNAL ;
    PORT
      LAYER M3 ;
        RECT  102.024 0 102.042 0.038 ;
    END
  END i[502]
  PIN i[503]
    DIRECTION INPUT ;
    USE SIGNAL ;
    PORT
      LAYER M5 ;
        RECT  102.24 0 102.264 0.084 ;
    END
  END i[503]
  PIN i[504]
    DIRECTION INPUT ;
    USE SIGNAL ;
    PORT
      LAYER M3 ;
        RECT  102.456 0 102.474 0.038 ;
    END
  END i[504]
  PIN i[505]
    DIRECTION INPUT ;
    USE SIGNAL ;
    PORT
      LAYER M5 ;
        RECT  102.624 0 102.648 0.084 ;
    END
  END i[505]
  PIN i[506]
    DIRECTION INPUT ;
    USE SIGNAL ;
    PORT
      LAYER M3 ;
        RECT  102.852 0 102.87 0.038 ;
    END
  END i[506]
  PIN i[507]
    DIRECTION INPUT ;
    USE SIGNAL ;
    PORT
      LAYER M5 ;
        RECT  103.056 0 103.08 0.084 ;
    END
  END i[507]
  PIN i[508]
    DIRECTION INPUT ;
    USE SIGNAL ;
    PORT
      LAYER M3 ;
        RECT  103.248 0 103.266 0.038 ;
    END
  END i[508]
  PIN i[509]
    DIRECTION INPUT ;
    USE SIGNAL ;
    PORT
      LAYER M5 ;
        RECT  103.44 0 103.464 0.084 ;
    END
  END i[509]
  PIN i[50]
    DIRECTION INPUT ;
    USE SIGNAL ;
    PORT
      LAYER M3 ;
        RECT  11.232 0 11.25 0.038 ;
    END
  END i[50]
  PIN i[510]
    DIRECTION INPUT ;
    USE SIGNAL ;
    PORT
      LAYER M3 ;
        RECT  103.644 0 103.662 0.038 ;
    END
  END i[510]
  PIN i[511]
    DIRECTION INPUT ;
    USE SIGNAL ;
    PORT
      LAYER M5 ;
        RECT  103.824 0 103.848 0.084 ;
    END
  END i[511]
  PIN i[512]
    DIRECTION INPUT ;
    USE SIGNAL ;
    PORT
      LAYER M3 ;
        RECT  104.04 0 104.058 0.038 ;
    END
  END i[512]
  PIN i[513]
    DIRECTION INPUT ;
    USE SIGNAL ;
    PORT
      LAYER M5 ;
        RECT  104.256 0 104.28 0.084 ;
    END
  END i[513]
  PIN i[514]
    DIRECTION INPUT ;
    USE SIGNAL ;
    PORT
      LAYER M3 ;
        RECT  104.436 0 104.454 0.038 ;
    END
  END i[514]
  PIN i[515]
    DIRECTION INPUT ;
    USE SIGNAL ;
    PORT
      LAYER M5 ;
        RECT  104.64 0 104.664 0.084 ;
    END
  END i[515]
  PIN i[51]
    DIRECTION INPUT ;
    USE SIGNAL ;
    PORT
      LAYER M5 ;
        RECT  11.424 0 11.448 0.084 ;
    END
  END i[51]
  PIN i[52]
    DIRECTION INPUT ;
    USE SIGNAL ;
    PORT
      LAYER M3 ;
        RECT  11.628 0 11.646 0.038 ;
    END
  END i[52]
  PIN i[53]
    DIRECTION INPUT ;
    USE SIGNAL ;
    PORT
      LAYER M5 ;
        RECT  11.808 0 11.832 0.084 ;
    END
  END i[53]
  PIN i[54]
    DIRECTION INPUT ;
    USE SIGNAL ;
    PORT
      LAYER M3 ;
        RECT  12.024 0 12.042 0.038 ;
    END
  END i[54]
  PIN i[55]
    DIRECTION INPUT ;
    USE SIGNAL ;
    PORT
      LAYER M5 ;
        RECT  12.24 0 12.264 0.084 ;
    END
  END i[55]
  PIN i[56]
    DIRECTION INPUT ;
    USE SIGNAL ;
    PORT
      LAYER M3 ;
        RECT  12.42 0 12.438 0.038 ;
    END
  END i[56]
  PIN i[57]
    DIRECTION INPUT ;
    USE SIGNAL ;
    PORT
      LAYER M5 ;
        RECT  12.624 0 12.648 0.084 ;
    END
  END i[57]
  PIN i[58]
    DIRECTION INPUT ;
    USE SIGNAL ;
    PORT
      LAYER M3 ;
        RECT  12.816 0 12.834 0.038 ;
    END
  END i[58]
  PIN i[59]
    DIRECTION INPUT ;
    USE SIGNAL ;
    PORT
      LAYER M5 ;
        RECT  13.008 0 13.032 0.084 ;
    END
  END i[59]
  PIN i[5]
    DIRECTION INPUT ;
    USE SIGNAL ;
    PORT
      LAYER M5 ;
        RECT  2.16 0 2.184 0.084 ;
    END
  END i[5]
  PIN i[60]
    DIRECTION INPUT ;
    USE SIGNAL ;
    PORT
      LAYER M3 ;
        RECT  13.212 0 13.23 0.038 ;
    END
  END i[60]
  PIN i[61]
    DIRECTION INPUT ;
    USE SIGNAL ;
    PORT
      LAYER M5 ;
        RECT  13.44 0 13.464 0.084 ;
    END
  END i[61]
  PIN i[62]
    DIRECTION INPUT ;
    USE SIGNAL ;
    PORT
      LAYER M3 ;
        RECT  13.644 0 13.662 0.038 ;
    END
  END i[62]
  PIN i[63]
    DIRECTION INPUT ;
    USE SIGNAL ;
    PORT
      LAYER M5 ;
        RECT  13.824 0 13.848 0.084 ;
    END
  END i[63]
  PIN i[64]
    DIRECTION INPUT ;
    USE SIGNAL ;
    PORT
      LAYER M3 ;
        RECT  14.04 0 14.058 0.038 ;
    END
  END i[64]
  PIN i[65]
    DIRECTION INPUT ;
    USE SIGNAL ;
    PORT
      LAYER M5 ;
        RECT  14.208 0 14.232 0.084 ;
    END
  END i[65]
  PIN i[66]
    DIRECTION INPUT ;
    USE SIGNAL ;
    PORT
      LAYER M3 ;
        RECT  14.436 0 14.454 0.038 ;
    END
  END i[66]
  PIN i[67]
    DIRECTION INPUT ;
    USE SIGNAL ;
    PORT
      LAYER M5 ;
        RECT  14.64 0 14.664 0.084 ;
    END
  END i[67]
  PIN i[68]
    DIRECTION INPUT ;
    USE SIGNAL ;
    PORT
      LAYER M3 ;
        RECT  14.832 0 14.85 0.038 ;
    END
  END i[68]
  PIN i[69]
    DIRECTION INPUT ;
    USE SIGNAL ;
    PORT
      LAYER M5 ;
        RECT  15.024 0 15.048 0.084 ;
    END
  END i[69]
  PIN i[6]
    DIRECTION INPUT ;
    USE SIGNAL ;
    PORT
      LAYER M3 ;
        RECT  2.376 0 2.394 0.038 ;
    END
  END i[6]
  PIN i[70]
    DIRECTION INPUT ;
    USE SIGNAL ;
    PORT
      LAYER M3 ;
        RECT  15.228 0 15.246 0.038 ;
    END
  END i[70]
  PIN i[71]
    DIRECTION INPUT ;
    USE SIGNAL ;
    PORT
      LAYER M5 ;
        RECT  15.456 0 15.48 0.084 ;
    END
  END i[71]
  PIN i[72]
    DIRECTION INPUT ;
    USE SIGNAL ;
    PORT
      LAYER M3 ;
        RECT  15.624 0 15.642 0.038 ;
    END
  END i[72]
  PIN i[73]
    DIRECTION INPUT ;
    USE SIGNAL ;
    PORT
      LAYER M5 ;
        RECT  15.84 0 15.864 0.084 ;
    END
  END i[73]
  PIN i[74]
    DIRECTION INPUT ;
    USE SIGNAL ;
    PORT
      LAYER M3 ;
        RECT  16.056 0 16.074 0.038 ;
    END
  END i[74]
  PIN i[75]
    DIRECTION INPUT ;
    USE SIGNAL ;
    PORT
      LAYER M5 ;
        RECT  16.224 0 16.248 0.084 ;
    END
  END i[75]
  PIN i[76]
    DIRECTION INPUT ;
    USE SIGNAL ;
    PORT
      LAYER M3 ;
        RECT  16.452 0 16.47 0.038 ;
    END
  END i[76]
  PIN i[77]
    DIRECTION INPUT ;
    USE SIGNAL ;
    PORT
      LAYER M5 ;
        RECT  16.656 0 16.68 0.084 ;
    END
  END i[77]
  PIN i[78]
    DIRECTION INPUT ;
    USE SIGNAL ;
    PORT
      LAYER M3 ;
        RECT  16.848 0 16.866 0.038 ;
    END
  END i[78]
  PIN i[79]
    DIRECTION INPUT ;
    USE SIGNAL ;
    PORT
      LAYER M5 ;
        RECT  17.04 0 17.064 0.084 ;
    END
  END i[79]
  PIN i[7]
    DIRECTION INPUT ;
    USE SIGNAL ;
    PORT
      LAYER M5 ;
        RECT  2.592 0 2.616 0.084 ;
    END
  END i[7]
  PIN i[80]
    DIRECTION INPUT ;
    USE SIGNAL ;
    PORT
      LAYER M3 ;
        RECT  17.244 0 17.262 0.038 ;
    END
  END i[80]
  PIN i[81]
    DIRECTION INPUT ;
    USE SIGNAL ;
    PORT
      LAYER M5 ;
        RECT  17.424 0 17.448 0.084 ;
    END
  END i[81]
  PIN i[82]
    DIRECTION INPUT ;
    USE SIGNAL ;
    PORT
      LAYER M3 ;
        RECT  17.64 0 17.658 0.038 ;
    END
  END i[82]
  PIN i[83]
    DIRECTION INPUT ;
    USE SIGNAL ;
    PORT
      LAYER M5 ;
        RECT  17.856 0 17.88 0.084 ;
    END
  END i[83]
  PIN i[84]
    DIRECTION INPUT ;
    USE SIGNAL ;
    PORT
      LAYER M3 ;
        RECT  18.036 0 18.054 0.038 ;
    END
  END i[84]
  PIN i[85]
    DIRECTION INPUT ;
    USE SIGNAL ;
    PORT
      LAYER M5 ;
        RECT  18.24 0 18.264 0.084 ;
    END
  END i[85]
  PIN i[86]
    DIRECTION INPUT ;
    USE SIGNAL ;
    PORT
      LAYER M3 ;
        RECT  18.468 0 18.486 0.038 ;
    END
  END i[86]
  PIN i[87]
    DIRECTION INPUT ;
    USE SIGNAL ;
    PORT
      LAYER M5 ;
        RECT  18.672 0 18.696 0.084 ;
    END
  END i[87]
  PIN i[88]
    DIRECTION INPUT ;
    USE SIGNAL ;
    PORT
      LAYER M3 ;
        RECT  18.864 0 18.882 0.038 ;
    END
  END i[88]
  PIN i[89]
    DIRECTION INPUT ;
    USE SIGNAL ;
    PORT
      LAYER M5 ;
        RECT  19.056 0 19.08 0.084 ;
    END
  END i[89]
  PIN i[8]
    DIRECTION INPUT ;
    USE SIGNAL ;
    PORT
      LAYER M3 ;
        RECT  2.772 0 2.79 0.038 ;
    END
  END i[8]
  PIN i[90]
    DIRECTION INPUT ;
    USE SIGNAL ;
    PORT
      LAYER M3 ;
        RECT  19.26 0 19.278 0.038 ;
    END
  END i[90]
  PIN i[91]
    DIRECTION INPUT ;
    USE SIGNAL ;
    PORT
      LAYER M5 ;
        RECT  19.44 0 19.464 0.084 ;
    END
  END i[91]
  PIN i[92]
    DIRECTION INPUT ;
    USE SIGNAL ;
    PORT
      LAYER M3 ;
        RECT  19.656 0 19.674 0.038 ;
    END
  END i[92]
  PIN i[93]
    DIRECTION INPUT ;
    USE SIGNAL ;
    PORT
      LAYER M5 ;
        RECT  19.872 0 19.896 0.084 ;
    END
  END i[93]
  PIN i[94]
    DIRECTION INPUT ;
    USE SIGNAL ;
    PORT
      LAYER M3 ;
        RECT  20.052 0 20.07 0.038 ;
    END
  END i[94]
  PIN i[95]
    DIRECTION INPUT ;
    USE SIGNAL ;
    PORT
      LAYER M5 ;
        RECT  20.256 0 20.28 0.084 ;
    END
  END i[95]
  PIN i[96]
    DIRECTION INPUT ;
    USE SIGNAL ;
    PORT
      LAYER M3 ;
        RECT  20.448 0 20.466 0.038 ;
    END
  END i[96]
  PIN i[97]
    DIRECTION INPUT ;
    USE SIGNAL ;
    PORT
      LAYER M5 ;
        RECT  20.64 0 20.664 0.084 ;
    END
  END i[97]
  PIN i[98]
    DIRECTION INPUT ;
    USE SIGNAL ;
    PORT
      LAYER M3 ;
        RECT  20.88 0 20.898 0.038 ;
    END
  END i[98]
  PIN i[99]
    DIRECTION INPUT ;
    USE SIGNAL ;
    PORT
      LAYER M5 ;
        RECT  21.072 0 21.096 0.084 ;
    END
  END i[99]
  PIN i[9]
    DIRECTION INPUT ;
    USE SIGNAL ;
    PORT
      LAYER M5 ;
        RECT  2.976 0 3 0.084 ;
    END
  END i[9]
  PIN o[0]
    DIRECTION OUTPUT ;
    USE SIGNAL ;
    PORT
      LAYER M3 ;
        RECT  1.188 43.162 1.206 43.2 ;
    END
  END o[0]
  PIN o[100]
    DIRECTION OUTPUT ;
    USE SIGNAL ;
    PORT
      LAYER M3 ;
        RECT  21.276 43.162 21.294 43.2 ;
    END
  END o[100]
  PIN o[101]
    DIRECTION OUTPUT ;
    USE SIGNAL ;
    PORT
      LAYER M5 ;
        RECT  21.456 43.116 21.48 43.2 ;
    END
  END o[101]
  PIN o[102]
    DIRECTION OUTPUT ;
    USE SIGNAL ;
    PORT
      LAYER M3 ;
        RECT  21.672 43.162 21.69 43.2 ;
    END
  END o[102]
  PIN o[103]
    DIRECTION OUTPUT ;
    USE SIGNAL ;
    PORT
      LAYER M5 ;
        RECT  21.888 43.116 21.912 43.2 ;
    END
  END o[103]
  PIN o[104]
    DIRECTION OUTPUT ;
    USE SIGNAL ;
    PORT
      LAYER M3 ;
        RECT  22.068 43.162 22.086 43.2 ;
    END
  END o[104]
  PIN o[105]
    DIRECTION OUTPUT ;
    USE SIGNAL ;
    PORT
      LAYER M5 ;
        RECT  22.272 43.116 22.296 43.2 ;
    END
  END o[105]
  PIN o[106]
    DIRECTION OUTPUT ;
    USE SIGNAL ;
    PORT
      LAYER M3 ;
        RECT  22.464 43.162 22.482 43.2 ;
    END
  END o[106]
  PIN o[107]
    DIRECTION OUTPUT ;
    USE SIGNAL ;
    PORT
      LAYER M5 ;
        RECT  22.656 43.116 22.68 43.2 ;
    END
  END o[107]
  PIN o[108]
    DIRECTION OUTPUT ;
    USE SIGNAL ;
    PORT
      LAYER M3 ;
        RECT  22.86 43.162 22.878 43.2 ;
    END
  END o[108]
  PIN o[109]
    DIRECTION OUTPUT ;
    USE SIGNAL ;
    PORT
      LAYER M5 ;
        RECT  23.088 43.116 23.112 43.2 ;
    END
  END o[109]
  PIN o[10]
    DIRECTION OUTPUT ;
    USE SIGNAL ;
    PORT
      LAYER M3 ;
        RECT  3.168 43.162 3.186 43.2 ;
    END
  END o[10]
  PIN o[110]
    DIRECTION OUTPUT ;
    USE SIGNAL ;
    PORT
      LAYER M3 ;
        RECT  23.292 43.162 23.31 43.2 ;
    END
  END o[110]
  PIN o[111]
    DIRECTION OUTPUT ;
    USE SIGNAL ;
    PORT
      LAYER M5 ;
        RECT  23.472 43.116 23.496 43.2 ;
    END
  END o[111]
  PIN o[112]
    DIRECTION OUTPUT ;
    USE SIGNAL ;
    PORT
      LAYER M3 ;
        RECT  23.688 43.162 23.706 43.2 ;
    END
  END o[112]
  PIN o[113]
    DIRECTION OUTPUT ;
    USE SIGNAL ;
    PORT
      LAYER M5 ;
        RECT  23.856 43.116 23.88 43.2 ;
    END
  END o[113]
  PIN o[114]
    DIRECTION OUTPUT ;
    USE SIGNAL ;
    PORT
      LAYER M3 ;
        RECT  24.084 43.162 24.102 43.2 ;
    END
  END o[114]
  PIN o[115]
    DIRECTION OUTPUT ;
    USE SIGNAL ;
    PORT
      LAYER M5 ;
        RECT  24.288 43.116 24.312 43.2 ;
    END
  END o[115]
  PIN o[116]
    DIRECTION OUTPUT ;
    USE SIGNAL ;
    PORT
      LAYER M3 ;
        RECT  24.48 43.162 24.498 43.2 ;
    END
  END o[116]
  PIN o[117]
    DIRECTION OUTPUT ;
    USE SIGNAL ;
    PORT
      LAYER M5 ;
        RECT  24.672 43.116 24.696 43.2 ;
    END
  END o[117]
  PIN o[118]
    DIRECTION OUTPUT ;
    USE SIGNAL ;
    PORT
      LAYER M3 ;
        RECT  24.876 43.162 24.894 43.2 ;
    END
  END o[118]
  PIN o[119]
    DIRECTION OUTPUT ;
    USE SIGNAL ;
    PORT
      LAYER M5 ;
        RECT  25.056 43.116 25.08 43.2 ;
    END
  END o[119]
  PIN o[11]
    DIRECTION OUTPUT ;
    USE SIGNAL ;
    PORT
      LAYER M5 ;
        RECT  3.36 43.116 3.384 43.2 ;
    END
  END o[11]
  PIN o[120]
    DIRECTION OUTPUT ;
    USE SIGNAL ;
    PORT
      LAYER M3 ;
        RECT  25.272 43.162 25.29 43.2 ;
    END
  END o[120]
  PIN o[121]
    DIRECTION OUTPUT ;
    USE SIGNAL ;
    PORT
      LAYER M5 ;
        RECT  25.488 43.116 25.512 43.2 ;
    END
  END o[121]
  PIN o[122]
    DIRECTION OUTPUT ;
    USE SIGNAL ;
    PORT
      LAYER M3 ;
        RECT  25.668 43.162 25.686 43.2 ;
    END
  END o[122]
  PIN o[123]
    DIRECTION OUTPUT ;
    USE SIGNAL ;
    PORT
      LAYER M5 ;
        RECT  25.872 43.116 25.896 43.2 ;
    END
  END o[123]
  PIN o[124]
    DIRECTION OUTPUT ;
    USE SIGNAL ;
    PORT
      LAYER M3 ;
        RECT  26.1 43.162 26.118 43.2 ;
    END
  END o[124]
  PIN o[125]
    DIRECTION OUTPUT ;
    USE SIGNAL ;
    PORT
      LAYER M5 ;
        RECT  26.304 43.116 26.328 43.2 ;
    END
  END o[125]
  PIN o[126]
    DIRECTION OUTPUT ;
    USE SIGNAL ;
    PORT
      LAYER M3 ;
        RECT  26.496 43.162 26.514 43.2 ;
    END
  END o[126]
  PIN o[127]
    DIRECTION OUTPUT ;
    USE SIGNAL ;
    PORT
      LAYER M5 ;
        RECT  26.688 43.116 26.712 43.2 ;
    END
  END o[127]
  PIN o[128]
    DIRECTION OUTPUT ;
    USE SIGNAL ;
    PORT
      LAYER M3 ;
        RECT  26.892 43.162 26.91 43.2 ;
    END
  END o[128]
  PIN o[129]
    DIRECTION OUTPUT ;
    USE SIGNAL ;
    PORT
      LAYER M5 ;
        RECT  27.072 43.116 27.096 43.2 ;
    END
  END o[129]
  PIN o[12]
    DIRECTION OUTPUT ;
    USE SIGNAL ;
    PORT
      LAYER M3 ;
        RECT  3.6 43.162 3.618 43.2 ;
    END
  END o[12]
  PIN o[130]
    DIRECTION OUTPUT ;
    USE SIGNAL ;
    PORT
      LAYER M3 ;
        RECT  27.288 43.162 27.306 43.2 ;
    END
  END o[130]
  PIN o[131]
    DIRECTION OUTPUT ;
    USE SIGNAL ;
    PORT
      LAYER M5 ;
        RECT  27.504 43.116 27.528 43.2 ;
    END
  END o[131]
  PIN o[132]
    DIRECTION OUTPUT ;
    USE SIGNAL ;
    PORT
      LAYER M3 ;
        RECT  27.684 43.162 27.702 43.2 ;
    END
  END o[132]
  PIN o[133]
    DIRECTION OUTPUT ;
    USE SIGNAL ;
    PORT
      LAYER M5 ;
        RECT  27.888 43.116 27.912 43.2 ;
    END
  END o[133]
  PIN o[134]
    DIRECTION OUTPUT ;
    USE SIGNAL ;
    PORT
      LAYER M3 ;
        RECT  28.08 43.162 28.098 43.2 ;
    END
  END o[134]
  PIN o[135]
    DIRECTION OUTPUT ;
    USE SIGNAL ;
    PORT
      LAYER M5 ;
        RECT  28.272 43.116 28.296 43.2 ;
    END
  END o[135]
  PIN o[136]
    DIRECTION OUTPUT ;
    USE SIGNAL ;
    PORT
      LAYER M3 ;
        RECT  28.512 43.162 28.53 43.2 ;
    END
  END o[136]
  PIN o[137]
    DIRECTION OUTPUT ;
    USE SIGNAL ;
    PORT
      LAYER M5 ;
        RECT  28.704 43.116 28.728 43.2 ;
    END
  END o[137]
  PIN o[138]
    DIRECTION OUTPUT ;
    USE SIGNAL ;
    PORT
      LAYER M3 ;
        RECT  28.908 43.162 28.926 43.2 ;
    END
  END o[138]
  PIN o[139]
    DIRECTION OUTPUT ;
    USE SIGNAL ;
    PORT
      LAYER M5 ;
        RECT  29.088 43.116 29.112 43.2 ;
    END
  END o[139]
  PIN o[13]
    DIRECTION OUTPUT ;
    USE SIGNAL ;
    PORT
      LAYER M5 ;
        RECT  3.792 43.116 3.816 43.2 ;
    END
  END o[13]
  PIN o[140]
    DIRECTION OUTPUT ;
    USE SIGNAL ;
    PORT
      LAYER M3 ;
        RECT  29.304 43.162 29.322 43.2 ;
    END
  END o[140]
  PIN o[141]
    DIRECTION OUTPUT ;
    USE SIGNAL ;
    PORT
      LAYER M5 ;
        RECT  29.52 43.116 29.544 43.2 ;
    END
  END o[141]
  PIN o[142]
    DIRECTION OUTPUT ;
    USE SIGNAL ;
    PORT
      LAYER M3 ;
        RECT  29.7 43.162 29.718 43.2 ;
    END
  END o[142]
  PIN o[143]
    DIRECTION OUTPUT ;
    USE SIGNAL ;
    PORT
      LAYER M5 ;
        RECT  29.904 43.116 29.928 43.2 ;
    END
  END o[143]
  PIN o[144]
    DIRECTION OUTPUT ;
    USE SIGNAL ;
    PORT
      LAYER M3 ;
        RECT  30.096 43.162 30.114 43.2 ;
    END
  END o[144]
  PIN o[145]
    DIRECTION OUTPUT ;
    USE SIGNAL ;
    PORT
      LAYER M5 ;
        RECT  30.288 43.116 30.312 43.2 ;
    END
  END o[145]
  PIN o[146]
    DIRECTION OUTPUT ;
    USE SIGNAL ;
    PORT
      LAYER M3 ;
        RECT  30.492 43.162 30.51 43.2 ;
    END
  END o[146]
  PIN o[147]
    DIRECTION OUTPUT ;
    USE SIGNAL ;
    PORT
      LAYER M5 ;
        RECT  30.72 43.116 30.744 43.2 ;
    END
  END o[147]
  PIN o[148]
    DIRECTION OUTPUT ;
    USE SIGNAL ;
    PORT
      LAYER M3 ;
        RECT  30.924 43.162 30.942 43.2 ;
    END
  END o[148]
  PIN o[149]
    DIRECTION OUTPUT ;
    USE SIGNAL ;
    PORT
      LAYER M5 ;
        RECT  31.104 43.116 31.128 43.2 ;
    END
  END o[149]
  PIN o[14]
    DIRECTION OUTPUT ;
    USE SIGNAL ;
    PORT
      LAYER M3 ;
        RECT  3.996 43.162 4.014 43.2 ;
    END
  END o[14]
  PIN o[150]
    DIRECTION OUTPUT ;
    USE SIGNAL ;
    PORT
      LAYER M3 ;
        RECT  31.32 43.162 31.338 43.2 ;
    END
  END o[150]
  PIN o[151]
    DIRECTION OUTPUT ;
    USE SIGNAL ;
    PORT
      LAYER M5 ;
        RECT  31.488 43.116 31.512 43.2 ;
    END
  END o[151]
  PIN o[152]
    DIRECTION OUTPUT ;
    USE SIGNAL ;
    PORT
      LAYER M3 ;
        RECT  31.716 43.162 31.734 43.2 ;
    END
  END o[152]
  PIN o[153]
    DIRECTION OUTPUT ;
    USE SIGNAL ;
    PORT
      LAYER M5 ;
        RECT  31.92 43.116 31.944 43.2 ;
    END
  END o[153]
  PIN o[154]
    DIRECTION OUTPUT ;
    USE SIGNAL ;
    PORT
      LAYER M3 ;
        RECT  32.112 43.162 32.13 43.2 ;
    END
  END o[154]
  PIN o[155]
    DIRECTION OUTPUT ;
    USE SIGNAL ;
    PORT
      LAYER M5 ;
        RECT  32.304 43.116 32.328 43.2 ;
    END
  END o[155]
  PIN o[156]
    DIRECTION OUTPUT ;
    USE SIGNAL ;
    PORT
      LAYER M3 ;
        RECT  32.508 43.162 32.526 43.2 ;
    END
  END o[156]
  PIN o[157]
    DIRECTION OUTPUT ;
    USE SIGNAL ;
    PORT
      LAYER M5 ;
        RECT  32.736 43.116 32.76 43.2 ;
    END
  END o[157]
  PIN o[158]
    DIRECTION OUTPUT ;
    USE SIGNAL ;
    PORT
      LAYER M3 ;
        RECT  32.904 43.162 32.922 43.2 ;
    END
  END o[158]
  PIN o[159]
    DIRECTION OUTPUT ;
    USE SIGNAL ;
    PORT
      LAYER M5 ;
        RECT  33.12 43.116 33.144 43.2 ;
    END
  END o[159]
  PIN o[15]
    DIRECTION OUTPUT ;
    USE SIGNAL ;
    PORT
      LAYER M5 ;
        RECT  4.176 43.116 4.2 43.2 ;
    END
  END o[15]
  PIN o[160]
    DIRECTION OUTPUT ;
    USE SIGNAL ;
    PORT
      LAYER M3 ;
        RECT  33.336 43.162 33.354 43.2 ;
    END
  END o[160]
  PIN o[161]
    DIRECTION OUTPUT ;
    USE SIGNAL ;
    PORT
      LAYER M5 ;
        RECT  33.504 43.116 33.528 43.2 ;
    END
  END o[161]
  PIN o[162]
    DIRECTION OUTPUT ;
    USE SIGNAL ;
    PORT
      LAYER M3 ;
        RECT  33.732 43.162 33.75 43.2 ;
    END
  END o[162]
  PIN o[163]
    DIRECTION OUTPUT ;
    USE SIGNAL ;
    PORT
      LAYER M5 ;
        RECT  33.936 43.116 33.96 43.2 ;
    END
  END o[163]
  PIN o[164]
    DIRECTION OUTPUT ;
    USE SIGNAL ;
    PORT
      LAYER M3 ;
        RECT  34.128 43.162 34.146 43.2 ;
    END
  END o[164]
  PIN o[165]
    DIRECTION OUTPUT ;
    USE SIGNAL ;
    PORT
      LAYER M5 ;
        RECT  34.32 43.116 34.344 43.2 ;
    END
  END o[165]
  PIN o[166]
    DIRECTION OUTPUT ;
    USE SIGNAL ;
    PORT
      LAYER M3 ;
        RECT  34.524 43.162 34.542 43.2 ;
    END
  END o[166]
  PIN o[167]
    DIRECTION OUTPUT ;
    USE SIGNAL ;
    PORT
      LAYER M5 ;
        RECT  34.704 43.116 34.728 43.2 ;
    END
  END o[167]
  PIN o[168]
    DIRECTION OUTPUT ;
    USE SIGNAL ;
    PORT
      LAYER M3 ;
        RECT  34.92 43.162 34.938 43.2 ;
    END
  END o[168]
  PIN o[169]
    DIRECTION OUTPUT ;
    USE SIGNAL ;
    PORT
      LAYER M5 ;
        RECT  35.136 43.116 35.16 43.2 ;
    END
  END o[169]
  PIN o[16]
    DIRECTION OUTPUT ;
    USE SIGNAL ;
    PORT
      LAYER M3 ;
        RECT  4.392 43.162 4.41 43.2 ;
    END
  END o[16]
  PIN o[170]
    DIRECTION OUTPUT ;
    USE SIGNAL ;
    PORT
      LAYER M3 ;
        RECT  35.316 43.162 35.334 43.2 ;
    END
  END o[170]
  PIN o[171]
    DIRECTION OUTPUT ;
    USE SIGNAL ;
    PORT
      LAYER M5 ;
        RECT  35.52 43.116 35.544 43.2 ;
    END
  END o[171]
  PIN o[172]
    DIRECTION OUTPUT ;
    USE SIGNAL ;
    PORT
      LAYER M3 ;
        RECT  35.748 43.162 35.766 43.2 ;
    END
  END o[172]
  PIN o[173]
    DIRECTION OUTPUT ;
    USE SIGNAL ;
    PORT
      LAYER M5 ;
        RECT  35.952 43.116 35.976 43.2 ;
    END
  END o[173]
  PIN o[174]
    DIRECTION OUTPUT ;
    USE SIGNAL ;
    PORT
      LAYER M3 ;
        RECT  36.144 43.162 36.162 43.2 ;
    END
  END o[174]
  PIN o[175]
    DIRECTION OUTPUT ;
    USE SIGNAL ;
    PORT
      LAYER M5 ;
        RECT  36.336 43.116 36.36 43.2 ;
    END
  END o[175]
  PIN o[176]
    DIRECTION OUTPUT ;
    USE SIGNAL ;
    PORT
      LAYER M3 ;
        RECT  36.54 43.162 36.558 43.2 ;
    END
  END o[176]
  PIN o[177]
    DIRECTION OUTPUT ;
    USE SIGNAL ;
    PORT
      LAYER M5 ;
        RECT  36.72 43.116 36.744 43.2 ;
    END
  END o[177]
  PIN o[178]
    DIRECTION OUTPUT ;
    USE SIGNAL ;
    PORT
      LAYER M3 ;
        RECT  36.936 43.162 36.954 43.2 ;
    END
  END o[178]
  PIN o[179]
    DIRECTION OUTPUT ;
    USE SIGNAL ;
    PORT
      LAYER M5 ;
        RECT  37.152 43.116 37.176 43.2 ;
    END
  END o[179]
  PIN o[17]
    DIRECTION OUTPUT ;
    USE SIGNAL ;
    PORT
      LAYER M5 ;
        RECT  4.608 43.116 4.632 43.2 ;
    END
  END o[17]
  PIN o[180]
    DIRECTION OUTPUT ;
    USE SIGNAL ;
    PORT
      LAYER M3 ;
        RECT  37.332 43.162 37.35 43.2 ;
    END
  END o[180]
  PIN o[181]
    DIRECTION OUTPUT ;
    USE SIGNAL ;
    PORT
      LAYER M5 ;
        RECT  37.536 43.116 37.56 43.2 ;
    END
  END o[181]
  PIN o[182]
    DIRECTION OUTPUT ;
    USE SIGNAL ;
    PORT
      LAYER M3 ;
        RECT  37.728 43.162 37.746 43.2 ;
    END
  END o[182]
  PIN o[183]
    DIRECTION OUTPUT ;
    USE SIGNAL ;
    PORT
      LAYER M5 ;
        RECT  37.92 43.116 37.944 43.2 ;
    END
  END o[183]
  PIN o[184]
    DIRECTION OUTPUT ;
    USE SIGNAL ;
    PORT
      LAYER M3 ;
        RECT  38.16 43.162 38.178 43.2 ;
    END
  END o[184]
  PIN o[185]
    DIRECTION OUTPUT ;
    USE SIGNAL ;
    PORT
      LAYER M5 ;
        RECT  38.352 43.116 38.376 43.2 ;
    END
  END o[185]
  PIN o[186]
    DIRECTION OUTPUT ;
    USE SIGNAL ;
    PORT
      LAYER M3 ;
        RECT  38.556 43.162 38.574 43.2 ;
    END
  END o[186]
  PIN o[187]
    DIRECTION OUTPUT ;
    USE SIGNAL ;
    PORT
      LAYER M5 ;
        RECT  38.736 43.116 38.76 43.2 ;
    END
  END o[187]
  PIN o[188]
    DIRECTION OUTPUT ;
    USE SIGNAL ;
    PORT
      LAYER M3 ;
        RECT  38.952 43.162 38.97 43.2 ;
    END
  END o[188]
  PIN o[189]
    DIRECTION OUTPUT ;
    USE SIGNAL ;
    PORT
      LAYER M5 ;
        RECT  39.168 43.116 39.192 43.2 ;
    END
  END o[189]
  PIN o[18]
    DIRECTION OUTPUT ;
    USE SIGNAL ;
    PORT
      LAYER M3 ;
        RECT  4.788 43.162 4.806 43.2 ;
    END
  END o[18]
  PIN o[190]
    DIRECTION OUTPUT ;
    USE SIGNAL ;
    PORT
      LAYER M3 ;
        RECT  39.348 43.162 39.366 43.2 ;
    END
  END o[190]
  PIN o[191]
    DIRECTION OUTPUT ;
    USE SIGNAL ;
    PORT
      LAYER M5 ;
        RECT  39.552 43.116 39.576 43.2 ;
    END
  END o[191]
  PIN o[192]
    DIRECTION OUTPUT ;
    USE SIGNAL ;
    PORT
      LAYER M3 ;
        RECT  39.744 43.162 39.762 43.2 ;
    END
  END o[192]
  PIN o[193]
    DIRECTION OUTPUT ;
    USE SIGNAL ;
    PORT
      LAYER M5 ;
        RECT  39.936 43.116 39.96 43.2 ;
    END
  END o[193]
  PIN o[194]
    DIRECTION OUTPUT ;
    USE SIGNAL ;
    PORT
      LAYER M3 ;
        RECT  40.14 43.162 40.158 43.2 ;
    END
  END o[194]
  PIN o[195]
    DIRECTION OUTPUT ;
    USE SIGNAL ;
    PORT
      LAYER M5 ;
        RECT  40.368 43.116 40.392 43.2 ;
    END
  END o[195]
  PIN o[196]
    DIRECTION OUTPUT ;
    USE SIGNAL ;
    PORT
      LAYER M3 ;
        RECT  40.572 43.162 40.59 43.2 ;
    END
  END o[196]
  PIN o[197]
    DIRECTION OUTPUT ;
    USE SIGNAL ;
    PORT
      LAYER M5 ;
        RECT  40.752 43.116 40.776 43.2 ;
    END
  END o[197]
  PIN o[198]
    DIRECTION OUTPUT ;
    USE SIGNAL ;
    PORT
      LAYER M3 ;
        RECT  40.968 43.162 40.986 43.2 ;
    END
  END o[198]
  PIN o[199]
    DIRECTION OUTPUT ;
    USE SIGNAL ;
    PORT
      LAYER M5 ;
        RECT  41.136 43.116 41.16 43.2 ;
    END
  END o[199]
  PIN o[19]
    DIRECTION OUTPUT ;
    USE SIGNAL ;
    PORT
      LAYER M5 ;
        RECT  4.992 43.116 5.016 43.2 ;
    END
  END o[19]
  PIN o[1]
    DIRECTION OUTPUT ;
    USE SIGNAL ;
    PORT
      LAYER M5 ;
        RECT  1.392 43.116 1.416 43.2 ;
    END
  END o[1]
  PIN o[200]
    DIRECTION OUTPUT ;
    USE SIGNAL ;
    PORT
      LAYER M3 ;
        RECT  41.364 43.162 41.382 43.2 ;
    END
  END o[200]
  PIN o[201]
    DIRECTION OUTPUT ;
    USE SIGNAL ;
    PORT
      LAYER M5 ;
        RECT  41.568 43.116 41.592 43.2 ;
    END
  END o[201]
  PIN o[202]
    DIRECTION OUTPUT ;
    USE SIGNAL ;
    PORT
      LAYER M3 ;
        RECT  41.76 43.162 41.778 43.2 ;
    END
  END o[202]
  PIN o[203]
    DIRECTION OUTPUT ;
    USE SIGNAL ;
    PORT
      LAYER M5 ;
        RECT  41.952 43.116 41.976 43.2 ;
    END
  END o[203]
  PIN o[204]
    DIRECTION OUTPUT ;
    USE SIGNAL ;
    PORT
      LAYER M3 ;
        RECT  42.156 43.162 42.174 43.2 ;
    END
  END o[204]
  PIN o[205]
    DIRECTION OUTPUT ;
    USE SIGNAL ;
    PORT
      LAYER M5 ;
        RECT  42.336 43.116 42.36 43.2 ;
    END
  END o[205]
  PIN o[206]
    DIRECTION OUTPUT ;
    USE SIGNAL ;
    PORT
      LAYER M3 ;
        RECT  42.552 43.162 42.57 43.2 ;
    END
  END o[206]
  PIN o[207]
    DIRECTION OUTPUT ;
    USE SIGNAL ;
    PORT
      LAYER M5 ;
        RECT  42.768 43.116 42.792 43.2 ;
    END
  END o[207]
  PIN o[208]
    DIRECTION OUTPUT ;
    USE SIGNAL ;
    PORT
      LAYER M3 ;
        RECT  42.948 43.162 42.966 43.2 ;
    END
  END o[208]
  PIN o[209]
    DIRECTION OUTPUT ;
    USE SIGNAL ;
    PORT
      LAYER M5 ;
        RECT  43.152 43.116 43.176 43.2 ;
    END
  END o[209]
  PIN o[20]
    DIRECTION OUTPUT ;
    USE SIGNAL ;
    PORT
      LAYER M3 ;
        RECT  5.184 43.162 5.202 43.2 ;
    END
  END o[20]
  PIN o[210]
    DIRECTION OUTPUT ;
    USE SIGNAL ;
    PORT
      LAYER M3 ;
        RECT  43.38 43.162 43.398 43.2 ;
    END
  END o[210]
  PIN o[211]
    DIRECTION OUTPUT ;
    USE SIGNAL ;
    PORT
      LAYER M5 ;
        RECT  43.584 43.116 43.608 43.2 ;
    END
  END o[211]
  PIN o[212]
    DIRECTION OUTPUT ;
    USE SIGNAL ;
    PORT
      LAYER M3 ;
        RECT  43.776 43.162 43.794 43.2 ;
    END
  END o[212]
  PIN o[213]
    DIRECTION OUTPUT ;
    USE SIGNAL ;
    PORT
      LAYER M5 ;
        RECT  43.968 43.116 43.992 43.2 ;
    END
  END o[213]
  PIN o[214]
    DIRECTION OUTPUT ;
    USE SIGNAL ;
    PORT
      LAYER M3 ;
        RECT  44.172 43.162 44.19 43.2 ;
    END
  END o[214]
  PIN o[215]
    DIRECTION OUTPUT ;
    USE SIGNAL ;
    PORT
      LAYER M5 ;
        RECT  44.352 43.116 44.376 43.2 ;
    END
  END o[215]
  PIN o[216]
    DIRECTION OUTPUT ;
    USE SIGNAL ;
    PORT
      LAYER M3 ;
        RECT  44.568 43.162 44.586 43.2 ;
    END
  END o[216]
  PIN o[217]
    DIRECTION OUTPUT ;
    USE SIGNAL ;
    PORT
      LAYER M5 ;
        RECT  44.784 43.116 44.808 43.2 ;
    END
  END o[217]
  PIN o[218]
    DIRECTION OUTPUT ;
    USE SIGNAL ;
    PORT
      LAYER M3 ;
        RECT  44.964 43.162 44.982 43.2 ;
    END
  END o[218]
  PIN o[219]
    DIRECTION OUTPUT ;
    USE SIGNAL ;
    PORT
      LAYER M5 ;
        RECT  45.168 43.116 45.192 43.2 ;
    END
  END o[219]
  PIN o[21]
    DIRECTION OUTPUT ;
    USE SIGNAL ;
    PORT
      LAYER M5 ;
        RECT  5.376 43.116 5.4 43.2 ;
    END
  END o[21]
  PIN o[220]
    DIRECTION OUTPUT ;
    USE SIGNAL ;
    PORT
      LAYER M3 ;
        RECT  45.36 43.162 45.378 43.2 ;
    END
  END o[220]
  PIN o[221]
    DIRECTION OUTPUT ;
    USE SIGNAL ;
    PORT
      LAYER M5 ;
        RECT  45.552 43.116 45.576 43.2 ;
    END
  END o[221]
  PIN o[222]
    DIRECTION OUTPUT ;
    USE SIGNAL ;
    PORT
      LAYER M3 ;
        RECT  45.792 43.162 45.81 43.2 ;
    END
  END o[222]
  PIN o[223]
    DIRECTION OUTPUT ;
    USE SIGNAL ;
    PORT
      LAYER M5 ;
        RECT  45.984 43.116 46.008 43.2 ;
    END
  END o[223]
  PIN o[224]
    DIRECTION OUTPUT ;
    USE SIGNAL ;
    PORT
      LAYER M3 ;
        RECT  46.188 43.162 46.206 43.2 ;
    END
  END o[224]
  PIN o[225]
    DIRECTION OUTPUT ;
    USE SIGNAL ;
    PORT
      LAYER M5 ;
        RECT  46.368 43.116 46.392 43.2 ;
    END
  END o[225]
  PIN o[226]
    DIRECTION OUTPUT ;
    USE SIGNAL ;
    PORT
      LAYER M3 ;
        RECT  46.584 43.162 46.602 43.2 ;
    END
  END o[226]
  PIN o[227]
    DIRECTION OUTPUT ;
    USE SIGNAL ;
    PORT
      LAYER M5 ;
        RECT  46.8 43.116 46.824 43.2 ;
    END
  END o[227]
  PIN o[228]
    DIRECTION OUTPUT ;
    USE SIGNAL ;
    PORT
      LAYER M3 ;
        RECT  46.98 43.162 46.998 43.2 ;
    END
  END o[228]
  PIN o[229]
    DIRECTION OUTPUT ;
    USE SIGNAL ;
    PORT
      LAYER M5 ;
        RECT  47.184 43.116 47.208 43.2 ;
    END
  END o[229]
  PIN o[22]
    DIRECTION OUTPUT ;
    USE SIGNAL ;
    PORT
      LAYER M3 ;
        RECT  5.58 43.162 5.598 43.2 ;
    END
  END o[22]
  PIN o[230]
    DIRECTION OUTPUT ;
    USE SIGNAL ;
    PORT
      LAYER M3 ;
        RECT  47.376 43.162 47.394 43.2 ;
    END
  END o[230]
  PIN o[231]
    DIRECTION OUTPUT ;
    USE SIGNAL ;
    PORT
      LAYER M5 ;
        RECT  47.568 43.116 47.592 43.2 ;
    END
  END o[231]
  PIN o[232]
    DIRECTION OUTPUT ;
    USE SIGNAL ;
    PORT
      LAYER M3 ;
        RECT  47.772 43.162 47.79 43.2 ;
    END
  END o[232]
  PIN o[233]
    DIRECTION OUTPUT ;
    USE SIGNAL ;
    PORT
      LAYER M5 ;
        RECT  48 43.116 48.024 43.2 ;
    END
  END o[233]
  PIN o[234]
    DIRECTION OUTPUT ;
    USE SIGNAL ;
    PORT
      LAYER M3 ;
        RECT  48.204 43.162 48.222 43.2 ;
    END
  END o[234]
  PIN o[235]
    DIRECTION OUTPUT ;
    USE SIGNAL ;
    PORT
      LAYER M5 ;
        RECT  48.384 43.116 48.408 43.2 ;
    END
  END o[235]
  PIN o[236]
    DIRECTION OUTPUT ;
    USE SIGNAL ;
    PORT
      LAYER M3 ;
        RECT  48.6 43.162 48.618 43.2 ;
    END
  END o[236]
  PIN o[237]
    DIRECTION OUTPUT ;
    USE SIGNAL ;
    PORT
      LAYER M5 ;
        RECT  48.768 43.116 48.792 43.2 ;
    END
  END o[237]
  PIN o[238]
    DIRECTION OUTPUT ;
    USE SIGNAL ;
    PORT
      LAYER M3 ;
        RECT  48.996 43.162 49.014 43.2 ;
    END
  END o[238]
  PIN o[239]
    DIRECTION OUTPUT ;
    USE SIGNAL ;
    PORT
      LAYER M5 ;
        RECT  49.2 43.116 49.224 43.2 ;
    END
  END o[239]
  PIN o[23]
    DIRECTION OUTPUT ;
    USE SIGNAL ;
    PORT
      LAYER M5 ;
        RECT  5.808 43.116 5.832 43.2 ;
    END
  END o[23]
  PIN o[240]
    DIRECTION OUTPUT ;
    USE SIGNAL ;
    PORT
      LAYER M3 ;
        RECT  49.392 43.162 49.41 43.2 ;
    END
  END o[240]
  PIN o[241]
    DIRECTION OUTPUT ;
    USE SIGNAL ;
    PORT
      LAYER M5 ;
        RECT  49.584 43.116 49.608 43.2 ;
    END
  END o[241]
  PIN o[242]
    DIRECTION OUTPUT ;
    USE SIGNAL ;
    PORT
      LAYER M3 ;
        RECT  49.788 43.162 49.806 43.2 ;
    END
  END o[242]
  PIN o[243]
    DIRECTION OUTPUT ;
    USE SIGNAL ;
    PORT
      LAYER M5 ;
        RECT  50.016 43.116 50.04 43.2 ;
    END
  END o[243]
  PIN o[244]
    DIRECTION OUTPUT ;
    USE SIGNAL ;
    PORT
      LAYER M3 ;
        RECT  50.184 43.162 50.202 43.2 ;
    END
  END o[244]
  PIN o[245]
    DIRECTION OUTPUT ;
    USE SIGNAL ;
    PORT
      LAYER M5 ;
        RECT  50.4 43.116 50.424 43.2 ;
    END
  END o[245]
  PIN o[246]
    DIRECTION OUTPUT ;
    USE SIGNAL ;
    PORT
      LAYER M3 ;
        RECT  50.616 43.162 50.634 43.2 ;
    END
  END o[246]
  PIN o[247]
    DIRECTION OUTPUT ;
    USE SIGNAL ;
    PORT
      LAYER M5 ;
        RECT  50.784 43.116 50.808 43.2 ;
    END
  END o[247]
  PIN o[248]
    DIRECTION OUTPUT ;
    USE SIGNAL ;
    PORT
      LAYER M3 ;
        RECT  51.012 43.162 51.03 43.2 ;
    END
  END o[248]
  PIN o[249]
    DIRECTION OUTPUT ;
    USE SIGNAL ;
    PORT
      LAYER M5 ;
        RECT  51.216 43.116 51.24 43.2 ;
    END
  END o[249]
  PIN o[24]
    DIRECTION OUTPUT ;
    USE SIGNAL ;
    PORT
      LAYER M3 ;
        RECT  6.012 43.162 6.03 43.2 ;
    END
  END o[24]
  PIN o[250]
    DIRECTION OUTPUT ;
    USE SIGNAL ;
    PORT
      LAYER M3 ;
        RECT  51.408 43.162 51.426 43.2 ;
    END
  END o[250]
  PIN o[251]
    DIRECTION OUTPUT ;
    USE SIGNAL ;
    PORT
      LAYER M5 ;
        RECT  51.6 43.116 51.624 43.2 ;
    END
  END o[251]
  PIN o[252]
    DIRECTION OUTPUT ;
    USE SIGNAL ;
    PORT
      LAYER M3 ;
        RECT  51.804 43.162 51.822 43.2 ;
    END
  END o[252]
  PIN o[253]
    DIRECTION OUTPUT ;
    USE SIGNAL ;
    PORT
      LAYER M5 ;
        RECT  51.984 43.116 52.008 43.2 ;
    END
  END o[253]
  PIN o[254]
    DIRECTION OUTPUT ;
    USE SIGNAL ;
    PORT
      LAYER M3 ;
        RECT  52.2 43.162 52.218 43.2 ;
    END
  END o[254]
  PIN o[255]
    DIRECTION OUTPUT ;
    USE SIGNAL ;
    PORT
      LAYER M5 ;
        RECT  52.416 43.116 52.44 43.2 ;
    END
  END o[255]
  PIN o[256]
    DIRECTION OUTPUT ;
    USE SIGNAL ;
    PORT
      LAYER M3 ;
        RECT  52.596 43.162 52.614 43.2 ;
    END
  END o[256]
  PIN o[257]
    DIRECTION OUTPUT ;
    USE SIGNAL ;
    PORT
      LAYER M5 ;
        RECT  52.8 43.116 52.824 43.2 ;
    END
  END o[257]
  PIN o[258]
    DIRECTION OUTPUT ;
    USE SIGNAL ;
    PORT
      LAYER M3 ;
        RECT  53.028 43.162 53.046 43.2 ;
    END
  END o[258]
  PIN o[259]
    DIRECTION OUTPUT ;
    USE SIGNAL ;
    PORT
      LAYER M5 ;
        RECT  53.232 43.116 53.256 43.2 ;
    END
  END o[259]
  PIN o[25]
    DIRECTION OUTPUT ;
    USE SIGNAL ;
    PORT
      LAYER M5 ;
        RECT  6.192 43.116 6.216 43.2 ;
    END
  END o[25]
  PIN o[260]
    DIRECTION OUTPUT ;
    USE SIGNAL ;
    PORT
      LAYER M3 ;
        RECT  53.424 43.162 53.442 43.2 ;
    END
  END o[260]
  PIN o[261]
    DIRECTION OUTPUT ;
    USE SIGNAL ;
    PORT
      LAYER M5 ;
        RECT  53.616 43.116 53.64 43.2 ;
    END
  END o[261]
  PIN o[262]
    DIRECTION OUTPUT ;
    USE SIGNAL ;
    PORT
      LAYER M3 ;
        RECT  53.82 43.162 53.838 43.2 ;
    END
  END o[262]
  PIN o[263]
    DIRECTION OUTPUT ;
    USE SIGNAL ;
    PORT
      LAYER M5 ;
        RECT  54 43.116 54.024 43.2 ;
    END
  END o[263]
  PIN o[264]
    DIRECTION OUTPUT ;
    USE SIGNAL ;
    PORT
      LAYER M3 ;
        RECT  54.216 43.162 54.234 43.2 ;
    END
  END o[264]
  PIN o[265]
    DIRECTION OUTPUT ;
    USE SIGNAL ;
    PORT
      LAYER M5 ;
        RECT  54.432 43.116 54.456 43.2 ;
    END
  END o[265]
  PIN o[266]
    DIRECTION OUTPUT ;
    USE SIGNAL ;
    PORT
      LAYER M3 ;
        RECT  54.612 43.162 54.63 43.2 ;
    END
  END o[266]
  PIN o[267]
    DIRECTION OUTPUT ;
    USE SIGNAL ;
    PORT
      LAYER M5 ;
        RECT  54.816 43.116 54.84 43.2 ;
    END
  END o[267]
  PIN o[268]
    DIRECTION OUTPUT ;
    USE SIGNAL ;
    PORT
      LAYER M3 ;
        RECT  55.008 43.162 55.026 43.2 ;
    END
  END o[268]
  PIN o[269]
    DIRECTION OUTPUT ;
    USE SIGNAL ;
    PORT
      LAYER M5 ;
        RECT  55.2 43.116 55.224 43.2 ;
    END
  END o[269]
  PIN o[26]
    DIRECTION OUTPUT ;
    USE SIGNAL ;
    PORT
      LAYER M3 ;
        RECT  6.408 43.162 6.426 43.2 ;
    END
  END o[26]
  PIN o[270]
    DIRECTION OUTPUT ;
    USE SIGNAL ;
    PORT
      LAYER M3 ;
        RECT  55.44 43.162 55.458 43.2 ;
    END
  END o[270]
  PIN o[271]
    DIRECTION OUTPUT ;
    USE SIGNAL ;
    PORT
      LAYER M5 ;
        RECT  55.632 43.116 55.656 43.2 ;
    END
  END o[271]
  PIN o[272]
    DIRECTION OUTPUT ;
    USE SIGNAL ;
    PORT
      LAYER M3 ;
        RECT  55.836 43.162 55.854 43.2 ;
    END
  END o[272]
  PIN o[273]
    DIRECTION OUTPUT ;
    USE SIGNAL ;
    PORT
      LAYER M5 ;
        RECT  56.016 43.116 56.04 43.2 ;
    END
  END o[273]
  PIN o[274]
    DIRECTION OUTPUT ;
    USE SIGNAL ;
    PORT
      LAYER M3 ;
        RECT  56.232 43.162 56.25 43.2 ;
    END
  END o[274]
  PIN o[275]
    DIRECTION OUTPUT ;
    USE SIGNAL ;
    PORT
      LAYER M5 ;
        RECT  56.448 43.116 56.472 43.2 ;
    END
  END o[275]
  PIN o[276]
    DIRECTION OUTPUT ;
    USE SIGNAL ;
    PORT
      LAYER M3 ;
        RECT  56.628 43.162 56.646 43.2 ;
    END
  END o[276]
  PIN o[277]
    DIRECTION OUTPUT ;
    USE SIGNAL ;
    PORT
      LAYER M5 ;
        RECT  56.832 43.116 56.856 43.2 ;
    END
  END o[277]
  PIN o[278]
    DIRECTION OUTPUT ;
    USE SIGNAL ;
    PORT
      LAYER M3 ;
        RECT  57.024 43.162 57.042 43.2 ;
    END
  END o[278]
  PIN o[279]
    DIRECTION OUTPUT ;
    USE SIGNAL ;
    PORT
      LAYER M5 ;
        RECT  57.216 43.116 57.24 43.2 ;
    END
  END o[279]
  PIN o[27]
    DIRECTION OUTPUT ;
    USE SIGNAL ;
    PORT
      LAYER M5 ;
        RECT  6.576 43.116 6.6 43.2 ;
    END
  END o[27]
  PIN o[280]
    DIRECTION OUTPUT ;
    USE SIGNAL ;
    PORT
      LAYER M3 ;
        RECT  57.42 43.162 57.438 43.2 ;
    END
  END o[280]
  PIN o[281]
    DIRECTION OUTPUT ;
    USE SIGNAL ;
    PORT
      LAYER M5 ;
        RECT  57.648 43.116 57.672 43.2 ;
    END
  END o[281]
  PIN o[282]
    DIRECTION OUTPUT ;
    USE SIGNAL ;
    PORT
      LAYER M3 ;
        RECT  57.852 43.162 57.87 43.2 ;
    END
  END o[282]
  PIN o[283]
    DIRECTION OUTPUT ;
    USE SIGNAL ;
    PORT
      LAYER M5 ;
        RECT  58.032 43.116 58.056 43.2 ;
    END
  END o[283]
  PIN o[284]
    DIRECTION OUTPUT ;
    USE SIGNAL ;
    PORT
      LAYER M3 ;
        RECT  58.248 43.162 58.266 43.2 ;
    END
  END o[284]
  PIN o[285]
    DIRECTION OUTPUT ;
    USE SIGNAL ;
    PORT
      LAYER M5 ;
        RECT  58.416 43.116 58.44 43.2 ;
    END
  END o[285]
  PIN o[286]
    DIRECTION OUTPUT ;
    USE SIGNAL ;
    PORT
      LAYER M3 ;
        RECT  58.644 43.162 58.662 43.2 ;
    END
  END o[286]
  PIN o[287]
    DIRECTION OUTPUT ;
    USE SIGNAL ;
    PORT
      LAYER M5 ;
        RECT  58.848 43.116 58.872 43.2 ;
    END
  END o[287]
  PIN o[288]
    DIRECTION OUTPUT ;
    USE SIGNAL ;
    PORT
      LAYER M3 ;
        RECT  59.04 43.162 59.058 43.2 ;
    END
  END o[288]
  PIN o[289]
    DIRECTION OUTPUT ;
    USE SIGNAL ;
    PORT
      LAYER M5 ;
        RECT  59.232 43.116 59.256 43.2 ;
    END
  END o[289]
  PIN o[28]
    DIRECTION OUTPUT ;
    USE SIGNAL ;
    PORT
      LAYER M3 ;
        RECT  6.804 43.162 6.822 43.2 ;
    END
  END o[28]
  PIN o[290]
    DIRECTION OUTPUT ;
    USE SIGNAL ;
    PORT
      LAYER M3 ;
        RECT  59.436 43.162 59.454 43.2 ;
    END
  END o[290]
  PIN o[291]
    DIRECTION OUTPUT ;
    USE SIGNAL ;
    PORT
      LAYER M5 ;
        RECT  59.616 43.116 59.64 43.2 ;
    END
  END o[291]
  PIN o[292]
    DIRECTION OUTPUT ;
    USE SIGNAL ;
    PORT
      LAYER M3 ;
        RECT  59.832 43.162 59.85 43.2 ;
    END
  END o[292]
  PIN o[293]
    DIRECTION OUTPUT ;
    USE SIGNAL ;
    PORT
      LAYER M5 ;
        RECT  60.048 43.116 60.072 43.2 ;
    END
  END o[293]
  PIN o[294]
    DIRECTION OUTPUT ;
    USE SIGNAL ;
    PORT
      LAYER M3 ;
        RECT  60.228 43.162 60.246 43.2 ;
    END
  END o[294]
  PIN o[295]
    DIRECTION OUTPUT ;
    USE SIGNAL ;
    PORT
      LAYER M5 ;
        RECT  60.432 43.116 60.456 43.2 ;
    END
  END o[295]
  PIN o[296]
    DIRECTION OUTPUT ;
    USE SIGNAL ;
    PORT
      LAYER M3 ;
        RECT  60.66 43.162 60.678 43.2 ;
    END
  END o[296]
  PIN o[297]
    DIRECTION OUTPUT ;
    USE SIGNAL ;
    PORT
      LAYER M5 ;
        RECT  60.864 43.116 60.888 43.2 ;
    END
  END o[297]
  PIN o[298]
    DIRECTION OUTPUT ;
    USE SIGNAL ;
    PORT
      LAYER M3 ;
        RECT  61.056 43.162 61.074 43.2 ;
    END
  END o[298]
  PIN o[299]
    DIRECTION OUTPUT ;
    USE SIGNAL ;
    PORT
      LAYER M5 ;
        RECT  61.248 43.116 61.272 43.2 ;
    END
  END o[299]
  PIN o[29]
    DIRECTION OUTPUT ;
    USE SIGNAL ;
    PORT
      LAYER M5 ;
        RECT  7.008 43.116 7.032 43.2 ;
    END
  END o[29]
  PIN o[2]
    DIRECTION OUTPUT ;
    USE SIGNAL ;
    PORT
      LAYER M3 ;
        RECT  1.584 43.162 1.602 43.2 ;
    END
  END o[2]
  PIN o[300]
    DIRECTION OUTPUT ;
    USE SIGNAL ;
    PORT
      LAYER M3 ;
        RECT  61.452 43.162 61.47 43.2 ;
    END
  END o[300]
  PIN o[301]
    DIRECTION OUTPUT ;
    USE SIGNAL ;
    PORT
      LAYER M5 ;
        RECT  61.632 43.116 61.656 43.2 ;
    END
  END o[301]
  PIN o[302]
    DIRECTION OUTPUT ;
    USE SIGNAL ;
    PORT
      LAYER M3 ;
        RECT  61.848 43.162 61.866 43.2 ;
    END
  END o[302]
  PIN o[303]
    DIRECTION OUTPUT ;
    USE SIGNAL ;
    PORT
      LAYER M5 ;
        RECT  62.064 43.116 62.088 43.2 ;
    END
  END o[303]
  PIN o[304]
    DIRECTION OUTPUT ;
    USE SIGNAL ;
    PORT
      LAYER M3 ;
        RECT  62.244 43.162 62.262 43.2 ;
    END
  END o[304]
  PIN o[305]
    DIRECTION OUTPUT ;
    USE SIGNAL ;
    PORT
      LAYER M5 ;
        RECT  62.448 43.116 62.472 43.2 ;
    END
  END o[305]
  PIN o[306]
    DIRECTION OUTPUT ;
    USE SIGNAL ;
    PORT
      LAYER M3 ;
        RECT  62.64 43.162 62.658 43.2 ;
    END
  END o[306]
  PIN o[307]
    DIRECTION OUTPUT ;
    USE SIGNAL ;
    PORT
      LAYER M5 ;
        RECT  62.832 43.116 62.856 43.2 ;
    END
  END o[307]
  PIN o[308]
    DIRECTION OUTPUT ;
    USE SIGNAL ;
    PORT
      LAYER M3 ;
        RECT  63.072 43.162 63.09 43.2 ;
    END
  END o[308]
  PIN o[309]
    DIRECTION OUTPUT ;
    USE SIGNAL ;
    PORT
      LAYER M5 ;
        RECT  63.264 43.116 63.288 43.2 ;
    END
  END o[309]
  PIN o[30]
    DIRECTION OUTPUT ;
    USE SIGNAL ;
    PORT
      LAYER M3 ;
        RECT  7.2 43.162 7.218 43.2 ;
    END
  END o[30]
  PIN o[310]
    DIRECTION OUTPUT ;
    USE SIGNAL ;
    PORT
      LAYER M3 ;
        RECT  63.468 43.162 63.486 43.2 ;
    END
  END o[310]
  PIN o[311]
    DIRECTION OUTPUT ;
    USE SIGNAL ;
    PORT
      LAYER M5 ;
        RECT  63.648 43.116 63.672 43.2 ;
    END
  END o[311]
  PIN o[312]
    DIRECTION OUTPUT ;
    USE SIGNAL ;
    PORT
      LAYER M3 ;
        RECT  63.864 43.162 63.882 43.2 ;
    END
  END o[312]
  PIN o[313]
    DIRECTION OUTPUT ;
    USE SIGNAL ;
    PORT
      LAYER M5 ;
        RECT  64.08 43.116 64.104 43.2 ;
    END
  END o[313]
  PIN o[314]
    DIRECTION OUTPUT ;
    USE SIGNAL ;
    PORT
      LAYER M3 ;
        RECT  64.26 43.162 64.278 43.2 ;
    END
  END o[314]
  PIN o[315]
    DIRECTION OUTPUT ;
    USE SIGNAL ;
    PORT
      LAYER M5 ;
        RECT  64.464 43.116 64.488 43.2 ;
    END
  END o[315]
  PIN o[316]
    DIRECTION OUTPUT ;
    USE SIGNAL ;
    PORT
      LAYER M3 ;
        RECT  64.656 43.162 64.674 43.2 ;
    END
  END o[316]
  PIN o[317]
    DIRECTION OUTPUT ;
    USE SIGNAL ;
    PORT
      LAYER M5 ;
        RECT  64.848 43.116 64.872 43.2 ;
    END
  END o[317]
  PIN o[318]
    DIRECTION OUTPUT ;
    USE SIGNAL ;
    PORT
      LAYER M3 ;
        RECT  65.052 43.162 65.07 43.2 ;
    END
  END o[318]
  PIN o[319]
    DIRECTION OUTPUT ;
    USE SIGNAL ;
    PORT
      LAYER M5 ;
        RECT  65.28 43.116 65.304 43.2 ;
    END
  END o[319]
  PIN o[31]
    DIRECTION OUTPUT ;
    USE SIGNAL ;
    PORT
      LAYER M5 ;
        RECT  7.392 43.116 7.416 43.2 ;
    END
  END o[31]
  PIN o[320]
    DIRECTION OUTPUT ;
    USE SIGNAL ;
    PORT
      LAYER M3 ;
        RECT  65.484 43.162 65.502 43.2 ;
    END
  END o[320]
  PIN o[321]
    DIRECTION OUTPUT ;
    USE SIGNAL ;
    PORT
      LAYER M5 ;
        RECT  65.664 43.116 65.688 43.2 ;
    END
  END o[321]
  PIN o[322]
    DIRECTION OUTPUT ;
    USE SIGNAL ;
    PORT
      LAYER M3 ;
        RECT  65.88 43.162 65.898 43.2 ;
    END
  END o[322]
  PIN o[323]
    DIRECTION OUTPUT ;
    USE SIGNAL ;
    PORT
      LAYER M5 ;
        RECT  66.048 43.116 66.072 43.2 ;
    END
  END o[323]
  PIN o[324]
    DIRECTION OUTPUT ;
    USE SIGNAL ;
    PORT
      LAYER M3 ;
        RECT  66.276 43.162 66.294 43.2 ;
    END
  END o[324]
  PIN o[325]
    DIRECTION OUTPUT ;
    USE SIGNAL ;
    PORT
      LAYER M5 ;
        RECT  66.48 43.116 66.504 43.2 ;
    END
  END o[325]
  PIN o[326]
    DIRECTION OUTPUT ;
    USE SIGNAL ;
    PORT
      LAYER M3 ;
        RECT  66.672 43.162 66.69 43.2 ;
    END
  END o[326]
  PIN o[327]
    DIRECTION OUTPUT ;
    USE SIGNAL ;
    PORT
      LAYER M5 ;
        RECT  66.864 43.116 66.888 43.2 ;
    END
  END o[327]
  PIN o[328]
    DIRECTION OUTPUT ;
    USE SIGNAL ;
    PORT
      LAYER M3 ;
        RECT  67.068 43.162 67.086 43.2 ;
    END
  END o[328]
  PIN o[329]
    DIRECTION OUTPUT ;
    USE SIGNAL ;
    PORT
      LAYER M5 ;
        RECT  67.296 43.116 67.32 43.2 ;
    END
  END o[329]
  PIN o[32]
    DIRECTION OUTPUT ;
    USE SIGNAL ;
    PORT
      LAYER M3 ;
        RECT  7.596 43.162 7.614 43.2 ;
    END
  END o[32]
  PIN o[330]
    DIRECTION OUTPUT ;
    USE SIGNAL ;
    PORT
      LAYER M3 ;
        RECT  67.464 43.162 67.482 43.2 ;
    END
  END o[330]
  PIN o[331]
    DIRECTION OUTPUT ;
    USE SIGNAL ;
    PORT
      LAYER M5 ;
        RECT  67.68 43.116 67.704 43.2 ;
    END
  END o[331]
  PIN o[332]
    DIRECTION OUTPUT ;
    USE SIGNAL ;
    PORT
      LAYER M3 ;
        RECT  67.896 43.162 67.914 43.2 ;
    END
  END o[332]
  PIN o[333]
    DIRECTION OUTPUT ;
    USE SIGNAL ;
    PORT
      LAYER M5 ;
        RECT  68.064 43.116 68.088 43.2 ;
    END
  END o[333]
  PIN o[334]
    DIRECTION OUTPUT ;
    USE SIGNAL ;
    PORT
      LAYER M3 ;
        RECT  68.292 43.162 68.31 43.2 ;
    END
  END o[334]
  PIN o[335]
    DIRECTION OUTPUT ;
    USE SIGNAL ;
    PORT
      LAYER M5 ;
        RECT  68.496 43.116 68.52 43.2 ;
    END
  END o[335]
  PIN o[336]
    DIRECTION OUTPUT ;
    USE SIGNAL ;
    PORT
      LAYER M3 ;
        RECT  68.688 43.162 68.706 43.2 ;
    END
  END o[336]
  PIN o[337]
    DIRECTION OUTPUT ;
    USE SIGNAL ;
    PORT
      LAYER M5 ;
        RECT  68.88 43.116 68.904 43.2 ;
    END
  END o[337]
  PIN o[338]
    DIRECTION OUTPUT ;
    USE SIGNAL ;
    PORT
      LAYER M3 ;
        RECT  69.084 43.162 69.102 43.2 ;
    END
  END o[338]
  PIN o[339]
    DIRECTION OUTPUT ;
    USE SIGNAL ;
    PORT
      LAYER M5 ;
        RECT  69.264 43.116 69.288 43.2 ;
    END
  END o[339]
  PIN o[33]
    DIRECTION OUTPUT ;
    USE SIGNAL ;
    PORT
      LAYER M5 ;
        RECT  7.776 43.116 7.8 43.2 ;
    END
  END o[33]
  PIN o[340]
    DIRECTION OUTPUT ;
    USE SIGNAL ;
    PORT
      LAYER M3 ;
        RECT  69.48 43.162 69.498 43.2 ;
    END
  END o[340]
  PIN o[341]
    DIRECTION OUTPUT ;
    USE SIGNAL ;
    PORT
      LAYER M5 ;
        RECT  69.696 43.116 69.72 43.2 ;
    END
  END o[341]
  PIN o[342]
    DIRECTION OUTPUT ;
    USE SIGNAL ;
    PORT
      LAYER M3 ;
        RECT  69.876 43.162 69.894 43.2 ;
    END
  END o[342]
  PIN o[343]
    DIRECTION OUTPUT ;
    USE SIGNAL ;
    PORT
      LAYER M5 ;
        RECT  70.08 43.116 70.104 43.2 ;
    END
  END o[343]
  PIN o[344]
    DIRECTION OUTPUT ;
    USE SIGNAL ;
    PORT
      LAYER M3 ;
        RECT  70.308 43.162 70.326 43.2 ;
    END
  END o[344]
  PIN o[345]
    DIRECTION OUTPUT ;
    USE SIGNAL ;
    PORT
      LAYER M5 ;
        RECT  70.512 43.116 70.536 43.2 ;
    END
  END o[345]
  PIN o[346]
    DIRECTION OUTPUT ;
    USE SIGNAL ;
    PORT
      LAYER M3 ;
        RECT  70.704 43.162 70.722 43.2 ;
    END
  END o[346]
  PIN o[347]
    DIRECTION OUTPUT ;
    USE SIGNAL ;
    PORT
      LAYER M5 ;
        RECT  70.896 43.116 70.92 43.2 ;
    END
  END o[347]
  PIN o[348]
    DIRECTION OUTPUT ;
    USE SIGNAL ;
    PORT
      LAYER M3 ;
        RECT  71.1 43.162 71.118 43.2 ;
    END
  END o[348]
  PIN o[349]
    DIRECTION OUTPUT ;
    USE SIGNAL ;
    PORT
      LAYER M5 ;
        RECT  71.28 43.116 71.304 43.2 ;
    END
  END o[349]
  PIN o[34]
    DIRECTION OUTPUT ;
    USE SIGNAL ;
    PORT
      LAYER M3 ;
        RECT  7.992 43.162 8.01 43.2 ;
    END
  END o[34]
  PIN o[350]
    DIRECTION OUTPUT ;
    USE SIGNAL ;
    PORT
      LAYER M3 ;
        RECT  71.496 43.162 71.514 43.2 ;
    END
  END o[350]
  PIN o[351]
    DIRECTION OUTPUT ;
    USE SIGNAL ;
    PORT
      LAYER M5 ;
        RECT  71.712 43.116 71.736 43.2 ;
    END
  END o[351]
  PIN o[352]
    DIRECTION OUTPUT ;
    USE SIGNAL ;
    PORT
      LAYER M3 ;
        RECT  71.892 43.162 71.91 43.2 ;
    END
  END o[352]
  PIN o[353]
    DIRECTION OUTPUT ;
    USE SIGNAL ;
    PORT
      LAYER M5 ;
        RECT  72.096 43.116 72.12 43.2 ;
    END
  END o[353]
  PIN o[354]
    DIRECTION OUTPUT ;
    USE SIGNAL ;
    PORT
      LAYER M3 ;
        RECT  72.288 43.162 72.306 43.2 ;
    END
  END o[354]
  PIN o[355]
    DIRECTION OUTPUT ;
    USE SIGNAL ;
    PORT
      LAYER M5 ;
        RECT  72.48 43.116 72.504 43.2 ;
    END
  END o[355]
  PIN o[356]
    DIRECTION OUTPUT ;
    USE SIGNAL ;
    PORT
      LAYER M3 ;
        RECT  72.72 43.162 72.738 43.2 ;
    END
  END o[356]
  PIN o[357]
    DIRECTION OUTPUT ;
    USE SIGNAL ;
    PORT
      LAYER M5 ;
        RECT  72.912 43.116 72.936 43.2 ;
    END
  END o[357]
  PIN o[358]
    DIRECTION OUTPUT ;
    USE SIGNAL ;
    PORT
      LAYER M3 ;
        RECT  73.116 43.162 73.134 43.2 ;
    END
  END o[358]
  PIN o[359]
    DIRECTION OUTPUT ;
    USE SIGNAL ;
    PORT
      LAYER M5 ;
        RECT  73.296 43.116 73.32 43.2 ;
    END
  END o[359]
  PIN o[35]
    DIRECTION OUTPUT ;
    USE SIGNAL ;
    PORT
      LAYER M5 ;
        RECT  8.208 43.116 8.232 43.2 ;
    END
  END o[35]
  PIN o[360]
    DIRECTION OUTPUT ;
    USE SIGNAL ;
    PORT
      LAYER M3 ;
        RECT  73.512 43.162 73.53 43.2 ;
    END
  END o[360]
  PIN o[361]
    DIRECTION OUTPUT ;
    USE SIGNAL ;
    PORT
      LAYER M5 ;
        RECT  73.728 43.116 73.752 43.2 ;
    END
  END o[361]
  PIN o[362]
    DIRECTION OUTPUT ;
    USE SIGNAL ;
    PORT
      LAYER M3 ;
        RECT  73.908 43.162 73.926 43.2 ;
    END
  END o[362]
  PIN o[363]
    DIRECTION OUTPUT ;
    USE SIGNAL ;
    PORT
      LAYER M5 ;
        RECT  74.112 43.116 74.136 43.2 ;
    END
  END o[363]
  PIN o[364]
    DIRECTION OUTPUT ;
    USE SIGNAL ;
    PORT
      LAYER M3 ;
        RECT  74.304 43.162 74.322 43.2 ;
    END
  END o[364]
  PIN o[365]
    DIRECTION OUTPUT ;
    USE SIGNAL ;
    PORT
      LAYER M5 ;
        RECT  74.496 43.116 74.52 43.2 ;
    END
  END o[365]
  PIN o[366]
    DIRECTION OUTPUT ;
    USE SIGNAL ;
    PORT
      LAYER M3 ;
        RECT  74.7 43.162 74.718 43.2 ;
    END
  END o[366]
  PIN o[367]
    DIRECTION OUTPUT ;
    USE SIGNAL ;
    PORT
      LAYER M5 ;
        RECT  74.928 43.116 74.952 43.2 ;
    END
  END o[367]
  PIN o[368]
    DIRECTION OUTPUT ;
    USE SIGNAL ;
    PORT
      LAYER M3 ;
        RECT  75.132 43.162 75.15 43.2 ;
    END
  END o[368]
  PIN o[369]
    DIRECTION OUTPUT ;
    USE SIGNAL ;
    PORT
      LAYER M5 ;
        RECT  75.312 43.116 75.336 43.2 ;
    END
  END o[369]
  PIN o[36]
    DIRECTION OUTPUT ;
    USE SIGNAL ;
    PORT
      LAYER M3 ;
        RECT  8.388 43.162 8.406 43.2 ;
    END
  END o[36]
  PIN o[370]
    DIRECTION OUTPUT ;
    USE SIGNAL ;
    PORT
      LAYER M3 ;
        RECT  75.528 43.162 75.546 43.2 ;
    END
  END o[370]
  PIN o[371]
    DIRECTION OUTPUT ;
    USE SIGNAL ;
    PORT
      LAYER M5 ;
        RECT  75.696 43.116 75.72 43.2 ;
    END
  END o[371]
  PIN o[372]
    DIRECTION OUTPUT ;
    USE SIGNAL ;
    PORT
      LAYER M3 ;
        RECT  75.924 43.162 75.942 43.2 ;
    END
  END o[372]
  PIN o[373]
    DIRECTION OUTPUT ;
    USE SIGNAL ;
    PORT
      LAYER M5 ;
        RECT  76.128 43.116 76.152 43.2 ;
    END
  END o[373]
  PIN o[374]
    DIRECTION OUTPUT ;
    USE SIGNAL ;
    PORT
      LAYER M3 ;
        RECT  76.32 43.162 76.338 43.2 ;
    END
  END o[374]
  PIN o[375]
    DIRECTION OUTPUT ;
    USE SIGNAL ;
    PORT
      LAYER M5 ;
        RECT  76.512 43.116 76.536 43.2 ;
    END
  END o[375]
  PIN o[376]
    DIRECTION OUTPUT ;
    USE SIGNAL ;
    PORT
      LAYER M3 ;
        RECT  76.716 43.162 76.734 43.2 ;
    END
  END o[376]
  PIN o[377]
    DIRECTION OUTPUT ;
    USE SIGNAL ;
    PORT
      LAYER M5 ;
        RECT  76.896 43.116 76.92 43.2 ;
    END
  END o[377]
  PIN o[378]
    DIRECTION OUTPUT ;
    USE SIGNAL ;
    PORT
      LAYER M3 ;
        RECT  77.112 43.162 77.13 43.2 ;
    END
  END o[378]
  PIN o[379]
    DIRECTION OUTPUT ;
    USE SIGNAL ;
    PORT
      LAYER M5 ;
        RECT  77.328 43.116 77.352 43.2 ;
    END
  END o[379]
  PIN o[37]
    DIRECTION OUTPUT ;
    USE SIGNAL ;
    PORT
      LAYER M5 ;
        RECT  8.592 43.116 8.616 43.2 ;
    END
  END o[37]
  PIN o[380]
    DIRECTION OUTPUT ;
    USE SIGNAL ;
    PORT
      LAYER M3 ;
        RECT  77.508 43.162 77.526 43.2 ;
    END
  END o[380]
  PIN o[381]
    DIRECTION OUTPUT ;
    USE SIGNAL ;
    PORT
      LAYER M5 ;
        RECT  77.712 43.116 77.736 43.2 ;
    END
  END o[381]
  PIN o[382]
    DIRECTION OUTPUT ;
    USE SIGNAL ;
    PORT
      LAYER M3 ;
        RECT  77.94 43.162 77.958 43.2 ;
    END
  END o[382]
  PIN o[383]
    DIRECTION OUTPUT ;
    USE SIGNAL ;
    PORT
      LAYER M5 ;
        RECT  78.144 43.116 78.168 43.2 ;
    END
  END o[383]
  PIN o[384]
    DIRECTION OUTPUT ;
    USE SIGNAL ;
    PORT
      LAYER M3 ;
        RECT  78.336 43.162 78.354 43.2 ;
    END
  END o[384]
  PIN o[385]
    DIRECTION OUTPUT ;
    USE SIGNAL ;
    PORT
      LAYER M5 ;
        RECT  78.528 43.116 78.552 43.2 ;
    END
  END o[385]
  PIN o[386]
    DIRECTION OUTPUT ;
    USE SIGNAL ;
    PORT
      LAYER M3 ;
        RECT  78.732 43.162 78.75 43.2 ;
    END
  END o[386]
  PIN o[387]
    DIRECTION OUTPUT ;
    USE SIGNAL ;
    PORT
      LAYER M5 ;
        RECT  78.912 43.116 78.936 43.2 ;
    END
  END o[387]
  PIN o[388]
    DIRECTION OUTPUT ;
    USE SIGNAL ;
    PORT
      LAYER M3 ;
        RECT  79.128 43.162 79.146 43.2 ;
    END
  END o[388]
  PIN o[389]
    DIRECTION OUTPUT ;
    USE SIGNAL ;
    PORT
      LAYER M5 ;
        RECT  79.344 43.116 79.368 43.2 ;
    END
  END o[389]
  PIN o[38]
    DIRECTION OUTPUT ;
    USE SIGNAL ;
    PORT
      LAYER M3 ;
        RECT  8.82 43.162 8.838 43.2 ;
    END
  END o[38]
  PIN o[390]
    DIRECTION OUTPUT ;
    USE SIGNAL ;
    PORT
      LAYER M3 ;
        RECT  79.524 43.162 79.542 43.2 ;
    END
  END o[390]
  PIN o[391]
    DIRECTION OUTPUT ;
    USE SIGNAL ;
    PORT
      LAYER M5 ;
        RECT  79.728 43.116 79.752 43.2 ;
    END
  END o[391]
  PIN o[392]
    DIRECTION OUTPUT ;
    USE SIGNAL ;
    PORT
      LAYER M3 ;
        RECT  79.92 43.162 79.938 43.2 ;
    END
  END o[392]
  PIN o[393]
    DIRECTION OUTPUT ;
    USE SIGNAL ;
    PORT
      LAYER M5 ;
        RECT  80.112 43.116 80.136 43.2 ;
    END
  END o[393]
  PIN o[394]
    DIRECTION OUTPUT ;
    USE SIGNAL ;
    PORT
      LAYER M3 ;
        RECT  80.352 43.162 80.37 43.2 ;
    END
  END o[394]
  PIN o[395]
    DIRECTION OUTPUT ;
    USE SIGNAL ;
    PORT
      LAYER M5 ;
        RECT  80.544 43.116 80.568 43.2 ;
    END
  END o[395]
  PIN o[396]
    DIRECTION OUTPUT ;
    USE SIGNAL ;
    PORT
      LAYER M3 ;
        RECT  80.748 43.162 80.766 43.2 ;
    END
  END o[396]
  PIN o[397]
    DIRECTION OUTPUT ;
    USE SIGNAL ;
    PORT
      LAYER M5 ;
        RECT  80.928 43.116 80.952 43.2 ;
    END
  END o[397]
  PIN o[398]
    DIRECTION OUTPUT ;
    USE SIGNAL ;
    PORT
      LAYER M3 ;
        RECT  81.144 43.162 81.162 43.2 ;
    END
  END o[398]
  PIN o[399]
    DIRECTION OUTPUT ;
    USE SIGNAL ;
    PORT
      LAYER M5 ;
        RECT  81.36 43.116 81.384 43.2 ;
    END
  END o[399]
  PIN o[39]
    DIRECTION OUTPUT ;
    USE SIGNAL ;
    PORT
      LAYER M5 ;
        RECT  9.024 43.116 9.048 43.2 ;
    END
  END o[39]
  PIN o[3]
    DIRECTION OUTPUT ;
    USE SIGNAL ;
    PORT
      LAYER M5 ;
        RECT  1.776 43.116 1.8 43.2 ;
    END
  END o[3]
  PIN o[400]
    DIRECTION OUTPUT ;
    USE SIGNAL ;
    PORT
      LAYER M3 ;
        RECT  81.54 43.162 81.558 43.2 ;
    END
  END o[400]
  PIN o[401]
    DIRECTION OUTPUT ;
    USE SIGNAL ;
    PORT
      LAYER M5 ;
        RECT  81.744 43.116 81.768 43.2 ;
    END
  END o[401]
  PIN o[402]
    DIRECTION OUTPUT ;
    USE SIGNAL ;
    PORT
      LAYER M3 ;
        RECT  81.936 43.162 81.954 43.2 ;
    END
  END o[402]
  PIN o[403]
    DIRECTION OUTPUT ;
    USE SIGNAL ;
    PORT
      LAYER M5 ;
        RECT  82.128 43.116 82.152 43.2 ;
    END
  END o[403]
  PIN o[404]
    DIRECTION OUTPUT ;
    USE SIGNAL ;
    PORT
      LAYER M3 ;
        RECT  82.332 43.162 82.35 43.2 ;
    END
  END o[404]
  PIN o[405]
    DIRECTION OUTPUT ;
    USE SIGNAL ;
    PORT
      LAYER M5 ;
        RECT  82.56 43.116 82.584 43.2 ;
    END
  END o[405]
  PIN o[406]
    DIRECTION OUTPUT ;
    USE SIGNAL ;
    PORT
      LAYER M3 ;
        RECT  82.764 43.162 82.782 43.2 ;
    END
  END o[406]
  PIN o[407]
    DIRECTION OUTPUT ;
    USE SIGNAL ;
    PORT
      LAYER M5 ;
        RECT  82.944 43.116 82.968 43.2 ;
    END
  END o[407]
  PIN o[408]
    DIRECTION OUTPUT ;
    USE SIGNAL ;
    PORT
      LAYER M3 ;
        RECT  83.16 43.162 83.178 43.2 ;
    END
  END o[408]
  PIN o[409]
    DIRECTION OUTPUT ;
    USE SIGNAL ;
    PORT
      LAYER M5 ;
        RECT  83.328 43.116 83.352 43.2 ;
    END
  END o[409]
  PIN o[40]
    DIRECTION OUTPUT ;
    USE SIGNAL ;
    PORT
      LAYER M3 ;
        RECT  9.216 43.162 9.234 43.2 ;
    END
  END o[40]
  PIN o[410]
    DIRECTION OUTPUT ;
    USE SIGNAL ;
    PORT
      LAYER M3 ;
        RECT  83.556 43.162 83.574 43.2 ;
    END
  END o[410]
  PIN o[411]
    DIRECTION OUTPUT ;
    USE SIGNAL ;
    PORT
      LAYER M5 ;
        RECT  83.76 43.116 83.784 43.2 ;
    END
  END o[411]
  PIN o[412]
    DIRECTION OUTPUT ;
    USE SIGNAL ;
    PORT
      LAYER M3 ;
        RECT  83.952 43.162 83.97 43.2 ;
    END
  END o[412]
  PIN o[413]
    DIRECTION OUTPUT ;
    USE SIGNAL ;
    PORT
      LAYER M5 ;
        RECT  84.144 43.116 84.168 43.2 ;
    END
  END o[413]
  PIN o[414]
    DIRECTION OUTPUT ;
    USE SIGNAL ;
    PORT
      LAYER M3 ;
        RECT  84.348 43.162 84.366 43.2 ;
    END
  END o[414]
  PIN o[415]
    DIRECTION OUTPUT ;
    USE SIGNAL ;
    PORT
      LAYER M5 ;
        RECT  84.576 43.116 84.6 43.2 ;
    END
  END o[415]
  PIN o[416]
    DIRECTION OUTPUT ;
    USE SIGNAL ;
    PORT
      LAYER M3 ;
        RECT  84.744 43.162 84.762 43.2 ;
    END
  END o[416]
  PIN o[417]
    DIRECTION OUTPUT ;
    USE SIGNAL ;
    PORT
      LAYER M5 ;
        RECT  84.96 43.116 84.984 43.2 ;
    END
  END o[417]
  PIN o[418]
    DIRECTION OUTPUT ;
    USE SIGNAL ;
    PORT
      LAYER M3 ;
        RECT  85.176 43.162 85.194 43.2 ;
    END
  END o[418]
  PIN o[419]
    DIRECTION OUTPUT ;
    USE SIGNAL ;
    PORT
      LAYER M5 ;
        RECT  85.344 43.116 85.368 43.2 ;
    END
  END o[419]
  PIN o[41]
    DIRECTION OUTPUT ;
    USE SIGNAL ;
    PORT
      LAYER M5 ;
        RECT  9.408 43.116 9.432 43.2 ;
    END
  END o[41]
  PIN o[420]
    DIRECTION OUTPUT ;
    USE SIGNAL ;
    PORT
      LAYER M3 ;
        RECT  85.572 43.162 85.59 43.2 ;
    END
  END o[420]
  PIN o[421]
    DIRECTION OUTPUT ;
    USE SIGNAL ;
    PORT
      LAYER M5 ;
        RECT  85.776 43.116 85.8 43.2 ;
    END
  END o[421]
  PIN o[422]
    DIRECTION OUTPUT ;
    USE SIGNAL ;
    PORT
      LAYER M3 ;
        RECT  85.968 43.162 85.986 43.2 ;
    END
  END o[422]
  PIN o[423]
    DIRECTION OUTPUT ;
    USE SIGNAL ;
    PORT
      LAYER M5 ;
        RECT  86.16 43.116 86.184 43.2 ;
    END
  END o[423]
  PIN o[424]
    DIRECTION OUTPUT ;
    USE SIGNAL ;
    PORT
      LAYER M3 ;
        RECT  86.364 43.162 86.382 43.2 ;
    END
  END o[424]
  PIN o[425]
    DIRECTION OUTPUT ;
    USE SIGNAL ;
    PORT
      LAYER M5 ;
        RECT  86.544 43.116 86.568 43.2 ;
    END
  END o[425]
  PIN o[426]
    DIRECTION OUTPUT ;
    USE SIGNAL ;
    PORT
      LAYER M3 ;
        RECT  86.76 43.162 86.778 43.2 ;
    END
  END o[426]
  PIN o[427]
    DIRECTION OUTPUT ;
    USE SIGNAL ;
    PORT
      LAYER M5 ;
        RECT  86.976 43.116 87 43.2 ;
    END
  END o[427]
  PIN o[428]
    DIRECTION OUTPUT ;
    USE SIGNAL ;
    PORT
      LAYER M3 ;
        RECT  87.156 43.162 87.174 43.2 ;
    END
  END o[428]
  PIN o[429]
    DIRECTION OUTPUT ;
    USE SIGNAL ;
    PORT
      LAYER M5 ;
        RECT  87.36 43.116 87.384 43.2 ;
    END
  END o[429]
  PIN o[42]
    DIRECTION OUTPUT ;
    USE SIGNAL ;
    PORT
      LAYER M3 ;
        RECT  9.612 43.162 9.63 43.2 ;
    END
  END o[42]
  PIN o[430]
    DIRECTION OUTPUT ;
    USE SIGNAL ;
    PORT
      LAYER M3 ;
        RECT  87.588 43.162 87.606 43.2 ;
    END
  END o[430]
  PIN o[431]
    DIRECTION OUTPUT ;
    USE SIGNAL ;
    PORT
      LAYER M5 ;
        RECT  87.792 43.116 87.816 43.2 ;
    END
  END o[431]
  PIN o[432]
    DIRECTION OUTPUT ;
    USE SIGNAL ;
    PORT
      LAYER M3 ;
        RECT  87.984 43.162 88.002 43.2 ;
    END
  END o[432]
  PIN o[433]
    DIRECTION OUTPUT ;
    USE SIGNAL ;
    PORT
      LAYER M5 ;
        RECT  88.176 43.116 88.2 43.2 ;
    END
  END o[433]
  PIN o[434]
    DIRECTION OUTPUT ;
    USE SIGNAL ;
    PORT
      LAYER M3 ;
        RECT  88.38 43.162 88.398 43.2 ;
    END
  END o[434]
  PIN o[435]
    DIRECTION OUTPUT ;
    USE SIGNAL ;
    PORT
      LAYER M5 ;
        RECT  88.56 43.116 88.584 43.2 ;
    END
  END o[435]
  PIN o[436]
    DIRECTION OUTPUT ;
    USE SIGNAL ;
    PORT
      LAYER M3 ;
        RECT  88.776 43.162 88.794 43.2 ;
    END
  END o[436]
  PIN o[437]
    DIRECTION OUTPUT ;
    USE SIGNAL ;
    PORT
      LAYER M5 ;
        RECT  88.992 43.116 89.016 43.2 ;
    END
  END o[437]
  PIN o[438]
    DIRECTION OUTPUT ;
    USE SIGNAL ;
    PORT
      LAYER M3 ;
        RECT  89.172 43.162 89.19 43.2 ;
    END
  END o[438]
  PIN o[439]
    DIRECTION OUTPUT ;
    USE SIGNAL ;
    PORT
      LAYER M5 ;
        RECT  89.376 43.116 89.4 43.2 ;
    END
  END o[439]
  PIN o[43]
    DIRECTION OUTPUT ;
    USE SIGNAL ;
    PORT
      LAYER M5 ;
        RECT  9.792 43.116 9.816 43.2 ;
    END
  END o[43]
  PIN o[440]
    DIRECTION OUTPUT ;
    USE SIGNAL ;
    PORT
      LAYER M3 ;
        RECT  89.568 43.162 89.586 43.2 ;
    END
  END o[440]
  PIN o[441]
    DIRECTION OUTPUT ;
    USE SIGNAL ;
    PORT
      LAYER M5 ;
        RECT  89.76 43.116 89.784 43.2 ;
    END
  END o[441]
  PIN o[442]
    DIRECTION OUTPUT ;
    USE SIGNAL ;
    PORT
      LAYER M3 ;
        RECT  90 43.162 90.018 43.2 ;
    END
  END o[442]
  PIN o[443]
    DIRECTION OUTPUT ;
    USE SIGNAL ;
    PORT
      LAYER M5 ;
        RECT  90.192 43.116 90.216 43.2 ;
    END
  END o[443]
  PIN o[444]
    DIRECTION OUTPUT ;
    USE SIGNAL ;
    PORT
      LAYER M3 ;
        RECT  90.396 43.162 90.414 43.2 ;
    END
  END o[444]
  PIN o[445]
    DIRECTION OUTPUT ;
    USE SIGNAL ;
    PORT
      LAYER M5 ;
        RECT  90.576 43.116 90.6 43.2 ;
    END
  END o[445]
  PIN o[446]
    DIRECTION OUTPUT ;
    USE SIGNAL ;
    PORT
      LAYER M3 ;
        RECT  90.792 43.162 90.81 43.2 ;
    END
  END o[446]
  PIN o[447]
    DIRECTION OUTPUT ;
    USE SIGNAL ;
    PORT
      LAYER M5 ;
        RECT  91.008 43.116 91.032 43.2 ;
    END
  END o[447]
  PIN o[448]
    DIRECTION OUTPUT ;
    USE SIGNAL ;
    PORT
      LAYER M3 ;
        RECT  91.188 43.162 91.206 43.2 ;
    END
  END o[448]
  PIN o[449]
    DIRECTION OUTPUT ;
    USE SIGNAL ;
    PORT
      LAYER M5 ;
        RECT  91.392 43.116 91.416 43.2 ;
    END
  END o[449]
  PIN o[44]
    DIRECTION OUTPUT ;
    USE SIGNAL ;
    PORT
      LAYER M3 ;
        RECT  10.008 43.162 10.026 43.2 ;
    END
  END o[44]
  PIN o[450]
    DIRECTION OUTPUT ;
    USE SIGNAL ;
    PORT
      LAYER M3 ;
        RECT  91.584 43.162 91.602 43.2 ;
    END
  END o[450]
  PIN o[451]
    DIRECTION OUTPUT ;
    USE SIGNAL ;
    PORT
      LAYER M5 ;
        RECT  91.776 43.116 91.8 43.2 ;
    END
  END o[451]
  PIN o[452]
    DIRECTION OUTPUT ;
    USE SIGNAL ;
    PORT
      LAYER M3 ;
        RECT  91.98 43.162 91.998 43.2 ;
    END
  END o[452]
  PIN o[453]
    DIRECTION OUTPUT ;
    USE SIGNAL ;
    PORT
      LAYER M5 ;
        RECT  92.208 43.116 92.232 43.2 ;
    END
  END o[453]
  PIN o[454]
    DIRECTION OUTPUT ;
    USE SIGNAL ;
    PORT
      LAYER M3 ;
        RECT  92.412 43.162 92.43 43.2 ;
    END
  END o[454]
  PIN o[455]
    DIRECTION OUTPUT ;
    USE SIGNAL ;
    PORT
      LAYER M5 ;
        RECT  92.592 43.116 92.616 43.2 ;
    END
  END o[455]
  PIN o[456]
    DIRECTION OUTPUT ;
    USE SIGNAL ;
    PORT
      LAYER M3 ;
        RECT  92.808 43.162 92.826 43.2 ;
    END
  END o[456]
  PIN o[457]
    DIRECTION OUTPUT ;
    USE SIGNAL ;
    PORT
      LAYER M5 ;
        RECT  92.976 43.116 93 43.2 ;
    END
  END o[457]
  PIN o[458]
    DIRECTION OUTPUT ;
    USE SIGNAL ;
    PORT
      LAYER M3 ;
        RECT  93.204 43.162 93.222 43.2 ;
    END
  END o[458]
  PIN o[459]
    DIRECTION OUTPUT ;
    USE SIGNAL ;
    PORT
      LAYER M5 ;
        RECT  93.408 43.116 93.432 43.2 ;
    END
  END o[459]
  PIN o[45]
    DIRECTION OUTPUT ;
    USE SIGNAL ;
    PORT
      LAYER M5 ;
        RECT  10.224 43.116 10.248 43.2 ;
    END
  END o[45]
  PIN o[460]
    DIRECTION OUTPUT ;
    USE SIGNAL ;
    PORT
      LAYER M3 ;
        RECT  93.6 43.162 93.618 43.2 ;
    END
  END o[460]
  PIN o[461]
    DIRECTION OUTPUT ;
    USE SIGNAL ;
    PORT
      LAYER M5 ;
        RECT  93.792 43.116 93.816 43.2 ;
    END
  END o[461]
  PIN o[462]
    DIRECTION OUTPUT ;
    USE SIGNAL ;
    PORT
      LAYER M3 ;
        RECT  93.996 43.162 94.014 43.2 ;
    END
  END o[462]
  PIN o[463]
    DIRECTION OUTPUT ;
    USE SIGNAL ;
    PORT
      LAYER M5 ;
        RECT  94.176 43.116 94.2 43.2 ;
    END
  END o[463]
  PIN o[464]
    DIRECTION OUTPUT ;
    USE SIGNAL ;
    PORT
      LAYER M3 ;
        RECT  94.392 43.162 94.41 43.2 ;
    END
  END o[464]
  PIN o[465]
    DIRECTION OUTPUT ;
    USE SIGNAL ;
    PORT
      LAYER M5 ;
        RECT  94.608 43.116 94.632 43.2 ;
    END
  END o[465]
  PIN o[466]
    DIRECTION OUTPUT ;
    USE SIGNAL ;
    PORT
      LAYER M3 ;
        RECT  94.788 43.162 94.806 43.2 ;
    END
  END o[466]
  PIN o[467]
    DIRECTION OUTPUT ;
    USE SIGNAL ;
    PORT
      LAYER M5 ;
        RECT  94.992 43.116 95.016 43.2 ;
    END
  END o[467]
  PIN o[468]
    DIRECTION OUTPUT ;
    USE SIGNAL ;
    PORT
      LAYER M3 ;
        RECT  95.22 43.162 95.238 43.2 ;
    END
  END o[468]
  PIN o[469]
    DIRECTION OUTPUT ;
    USE SIGNAL ;
    PORT
      LAYER M5 ;
        RECT  95.424 43.116 95.448 43.2 ;
    END
  END o[469]
  PIN o[46]
    DIRECTION OUTPUT ;
    USE SIGNAL ;
    PORT
      LAYER M3 ;
        RECT  10.404 43.162 10.422 43.2 ;
    END
  END o[46]
  PIN o[470]
    DIRECTION OUTPUT ;
    USE SIGNAL ;
    PORT
      LAYER M3 ;
        RECT  95.616 43.162 95.634 43.2 ;
    END
  END o[470]
  PIN o[471]
    DIRECTION OUTPUT ;
    USE SIGNAL ;
    PORT
      LAYER M5 ;
        RECT  95.808 43.116 95.832 43.2 ;
    END
  END o[471]
  PIN o[472]
    DIRECTION OUTPUT ;
    USE SIGNAL ;
    PORT
      LAYER M3 ;
        RECT  96.012 43.162 96.03 43.2 ;
    END
  END o[472]
  PIN o[473]
    DIRECTION OUTPUT ;
    USE SIGNAL ;
    PORT
      LAYER M5 ;
        RECT  96.192 43.116 96.216 43.2 ;
    END
  END o[473]
  PIN o[474]
    DIRECTION OUTPUT ;
    USE SIGNAL ;
    PORT
      LAYER M3 ;
        RECT  96.408 43.162 96.426 43.2 ;
    END
  END o[474]
  PIN o[475]
    DIRECTION OUTPUT ;
    USE SIGNAL ;
    PORT
      LAYER M5 ;
        RECT  96.624 43.116 96.648 43.2 ;
    END
  END o[475]
  PIN o[476]
    DIRECTION OUTPUT ;
    USE SIGNAL ;
    PORT
      LAYER M3 ;
        RECT  96.804 43.162 96.822 43.2 ;
    END
  END o[476]
  PIN o[477]
    DIRECTION OUTPUT ;
    USE SIGNAL ;
    PORT
      LAYER M5 ;
        RECT  97.008 43.116 97.032 43.2 ;
    END
  END o[477]
  PIN o[478]
    DIRECTION OUTPUT ;
    USE SIGNAL ;
    PORT
      LAYER M3 ;
        RECT  97.2 43.162 97.218 43.2 ;
    END
  END o[478]
  PIN o[479]
    DIRECTION OUTPUT ;
    USE SIGNAL ;
    PORT
      LAYER M5 ;
        RECT  97.392 43.116 97.416 43.2 ;
    END
  END o[479]
  PIN o[47]
    DIRECTION OUTPUT ;
    USE SIGNAL ;
    PORT
      LAYER M5 ;
        RECT  10.608 43.116 10.632 43.2 ;
    END
  END o[47]
  PIN o[480]
    DIRECTION OUTPUT ;
    USE SIGNAL ;
    PORT
      LAYER M3 ;
        RECT  97.632 43.162 97.65 43.2 ;
    END
  END o[480]
  PIN o[481]
    DIRECTION OUTPUT ;
    USE SIGNAL ;
    PORT
      LAYER M5 ;
        RECT  97.824 43.116 97.848 43.2 ;
    END
  END o[481]
  PIN o[482]
    DIRECTION OUTPUT ;
    USE SIGNAL ;
    PORT
      LAYER M3 ;
        RECT  98.028 43.162 98.046 43.2 ;
    END
  END o[482]
  PIN o[483]
    DIRECTION OUTPUT ;
    USE SIGNAL ;
    PORT
      LAYER M5 ;
        RECT  98.208 43.116 98.232 43.2 ;
    END
  END o[483]
  PIN o[484]
    DIRECTION OUTPUT ;
    USE SIGNAL ;
    PORT
      LAYER M3 ;
        RECT  98.424 43.162 98.442 43.2 ;
    END
  END o[484]
  PIN o[485]
    DIRECTION OUTPUT ;
    USE SIGNAL ;
    PORT
      LAYER M5 ;
        RECT  98.64 43.116 98.664 43.2 ;
    END
  END o[485]
  PIN o[486]
    DIRECTION OUTPUT ;
    USE SIGNAL ;
    PORT
      LAYER M3 ;
        RECT  98.82 43.162 98.838 43.2 ;
    END
  END o[486]
  PIN o[487]
    DIRECTION OUTPUT ;
    USE SIGNAL ;
    PORT
      LAYER M5 ;
        RECT  99.024 43.116 99.048 43.2 ;
    END
  END o[487]
  PIN o[488]
    DIRECTION OUTPUT ;
    USE SIGNAL ;
    PORT
      LAYER M3 ;
        RECT  99.216 43.162 99.234 43.2 ;
    END
  END o[488]
  PIN o[489]
    DIRECTION OUTPUT ;
    USE SIGNAL ;
    PORT
      LAYER M5 ;
        RECT  99.408 43.116 99.432 43.2 ;
    END
  END o[489]
  PIN o[48]
    DIRECTION OUTPUT ;
    USE SIGNAL ;
    PORT
      LAYER M3 ;
        RECT  10.8 43.162 10.818 43.2 ;
    END
  END o[48]
  PIN o[490]
    DIRECTION OUTPUT ;
    USE SIGNAL ;
    PORT
      LAYER M3 ;
        RECT  99.612 43.162 99.63 43.2 ;
    END
  END o[490]
  PIN o[491]
    DIRECTION OUTPUT ;
    USE SIGNAL ;
    PORT
      LAYER M5 ;
        RECT  99.84 43.116 99.864 43.2 ;
    END
  END o[491]
  PIN o[492]
    DIRECTION OUTPUT ;
    USE SIGNAL ;
    PORT
      LAYER M3 ;
        RECT  100.044 43.162 100.062 43.2 ;
    END
  END o[492]
  PIN o[493]
    DIRECTION OUTPUT ;
    USE SIGNAL ;
    PORT
      LAYER M5 ;
        RECT  100.224 43.116 100.248 43.2 ;
    END
  END o[493]
  PIN o[494]
    DIRECTION OUTPUT ;
    USE SIGNAL ;
    PORT
      LAYER M3 ;
        RECT  100.44 43.162 100.458 43.2 ;
    END
  END o[494]
  PIN o[495]
    DIRECTION OUTPUT ;
    USE SIGNAL ;
    PORT
      LAYER M5 ;
        RECT  100.608 43.116 100.632 43.2 ;
    END
  END o[495]
  PIN o[496]
    DIRECTION OUTPUT ;
    USE SIGNAL ;
    PORT
      LAYER M3 ;
        RECT  100.836 43.162 100.854 43.2 ;
    END
  END o[496]
  PIN o[497]
    DIRECTION OUTPUT ;
    USE SIGNAL ;
    PORT
      LAYER M5 ;
        RECT  101.04 43.116 101.064 43.2 ;
    END
  END o[497]
  PIN o[498]
    DIRECTION OUTPUT ;
    USE SIGNAL ;
    PORT
      LAYER M3 ;
        RECT  101.232 43.162 101.25 43.2 ;
    END
  END o[498]
  PIN o[499]
    DIRECTION OUTPUT ;
    USE SIGNAL ;
    PORT
      LAYER M5 ;
        RECT  101.424 43.116 101.448 43.2 ;
    END
  END o[499]
  PIN o[49]
    DIRECTION OUTPUT ;
    USE SIGNAL ;
    PORT
      LAYER M5 ;
        RECT  10.992 43.116 11.016 43.2 ;
    END
  END o[49]
  PIN o[4]
    DIRECTION OUTPUT ;
    USE SIGNAL ;
    PORT
      LAYER M3 ;
        RECT  1.98 43.162 1.998 43.2 ;
    END
  END o[4]
  PIN o[500]
    DIRECTION OUTPUT ;
    USE SIGNAL ;
    PORT
      LAYER M3 ;
        RECT  101.628 43.162 101.646 43.2 ;
    END
  END o[500]
  PIN o[501]
    DIRECTION OUTPUT ;
    USE SIGNAL ;
    PORT
      LAYER M5 ;
        RECT  101.856 43.116 101.88 43.2 ;
    END
  END o[501]
  PIN o[502]
    DIRECTION OUTPUT ;
    USE SIGNAL ;
    PORT
      LAYER M3 ;
        RECT  102.024 43.162 102.042 43.2 ;
    END
  END o[502]
  PIN o[503]
    DIRECTION OUTPUT ;
    USE SIGNAL ;
    PORT
      LAYER M5 ;
        RECT  102.24 43.116 102.264 43.2 ;
    END
  END o[503]
  PIN o[504]
    DIRECTION OUTPUT ;
    USE SIGNAL ;
    PORT
      LAYER M3 ;
        RECT  102.456 43.162 102.474 43.2 ;
    END
  END o[504]
  PIN o[505]
    DIRECTION OUTPUT ;
    USE SIGNAL ;
    PORT
      LAYER M5 ;
        RECT  102.624 43.116 102.648 43.2 ;
    END
  END o[505]
  PIN o[506]
    DIRECTION OUTPUT ;
    USE SIGNAL ;
    PORT
      LAYER M3 ;
        RECT  102.852 43.162 102.87 43.2 ;
    END
  END o[506]
  PIN o[507]
    DIRECTION OUTPUT ;
    USE SIGNAL ;
    PORT
      LAYER M5 ;
        RECT  103.056 43.116 103.08 43.2 ;
    END
  END o[507]
  PIN o[508]
    DIRECTION OUTPUT ;
    USE SIGNAL ;
    PORT
      LAYER M3 ;
        RECT  103.248 43.162 103.266 43.2 ;
    END
  END o[508]
  PIN o[509]
    DIRECTION OUTPUT ;
    USE SIGNAL ;
    PORT
      LAYER M5 ;
        RECT  103.44 43.116 103.464 43.2 ;
    END
  END o[509]
  PIN o[50]
    DIRECTION OUTPUT ;
    USE SIGNAL ;
    PORT
      LAYER M3 ;
        RECT  11.232 43.162 11.25 43.2 ;
    END
  END o[50]
  PIN o[510]
    DIRECTION OUTPUT ;
    USE SIGNAL ;
    PORT
      LAYER M3 ;
        RECT  103.644 43.162 103.662 43.2 ;
    END
  END o[510]
  PIN o[511]
    DIRECTION OUTPUT ;
    USE SIGNAL ;
    PORT
      LAYER M5 ;
        RECT  103.824 43.116 103.848 43.2 ;
    END
  END o[511]
  PIN o[512]
    DIRECTION OUTPUT ;
    USE SIGNAL ;
    PORT
      LAYER M3 ;
        RECT  104.04 43.162 104.058 43.2 ;
    END
  END o[512]
  PIN o[513]
    DIRECTION OUTPUT ;
    USE SIGNAL ;
    PORT
      LAYER M5 ;
        RECT  104.256 43.116 104.28 43.2 ;
    END
  END o[513]
  PIN o[514]
    DIRECTION OUTPUT ;
    USE SIGNAL ;
    PORT
      LAYER M3 ;
        RECT  104.436 43.162 104.454 43.2 ;
    END
  END o[514]
  PIN o[515]
    DIRECTION OUTPUT ;
    USE SIGNAL ;
    PORT
      LAYER M5 ;
        RECT  104.64 43.116 104.664 43.2 ;
    END
  END o[515]
  PIN o[51]
    DIRECTION OUTPUT ;
    USE SIGNAL ;
    PORT
      LAYER M5 ;
        RECT  11.424 43.116 11.448 43.2 ;
    END
  END o[51]
  PIN o[52]
    DIRECTION OUTPUT ;
    USE SIGNAL ;
    PORT
      LAYER M3 ;
        RECT  11.628 43.162 11.646 43.2 ;
    END
  END o[52]
  PIN o[53]
    DIRECTION OUTPUT ;
    USE SIGNAL ;
    PORT
      LAYER M5 ;
        RECT  11.808 43.116 11.832 43.2 ;
    END
  END o[53]
  PIN o[54]
    DIRECTION OUTPUT ;
    USE SIGNAL ;
    PORT
      LAYER M3 ;
        RECT  12.024 43.162 12.042 43.2 ;
    END
  END o[54]
  PIN o[55]
    DIRECTION OUTPUT ;
    USE SIGNAL ;
    PORT
      LAYER M5 ;
        RECT  12.24 43.116 12.264 43.2 ;
    END
  END o[55]
  PIN o[56]
    DIRECTION OUTPUT ;
    USE SIGNAL ;
    PORT
      LAYER M3 ;
        RECT  12.42 43.162 12.438 43.2 ;
    END
  END o[56]
  PIN o[57]
    DIRECTION OUTPUT ;
    USE SIGNAL ;
    PORT
      LAYER M5 ;
        RECT  12.624 43.116 12.648 43.2 ;
    END
  END o[57]
  PIN o[58]
    DIRECTION OUTPUT ;
    USE SIGNAL ;
    PORT
      LAYER M3 ;
        RECT  12.816 43.162 12.834 43.2 ;
    END
  END o[58]
  PIN o[59]
    DIRECTION OUTPUT ;
    USE SIGNAL ;
    PORT
      LAYER M5 ;
        RECT  13.008 43.116 13.032 43.2 ;
    END
  END o[59]
  PIN o[5]
    DIRECTION OUTPUT ;
    USE SIGNAL ;
    PORT
      LAYER M5 ;
        RECT  2.16 43.116 2.184 43.2 ;
    END
  END o[5]
  PIN o[60]
    DIRECTION OUTPUT ;
    USE SIGNAL ;
    PORT
      LAYER M3 ;
        RECT  13.212 43.162 13.23 43.2 ;
    END
  END o[60]
  PIN o[61]
    DIRECTION OUTPUT ;
    USE SIGNAL ;
    PORT
      LAYER M5 ;
        RECT  13.44 43.116 13.464 43.2 ;
    END
  END o[61]
  PIN o[62]
    DIRECTION OUTPUT ;
    USE SIGNAL ;
    PORT
      LAYER M3 ;
        RECT  13.644 43.162 13.662 43.2 ;
    END
  END o[62]
  PIN o[63]
    DIRECTION OUTPUT ;
    USE SIGNAL ;
    PORT
      LAYER M5 ;
        RECT  13.824 43.116 13.848 43.2 ;
    END
  END o[63]
  PIN o[64]
    DIRECTION OUTPUT ;
    USE SIGNAL ;
    PORT
      LAYER M3 ;
        RECT  14.04 43.162 14.058 43.2 ;
    END
  END o[64]
  PIN o[65]
    DIRECTION OUTPUT ;
    USE SIGNAL ;
    PORT
      LAYER M5 ;
        RECT  14.208 43.116 14.232 43.2 ;
    END
  END o[65]
  PIN o[66]
    DIRECTION OUTPUT ;
    USE SIGNAL ;
    PORT
      LAYER M3 ;
        RECT  14.436 43.162 14.454 43.2 ;
    END
  END o[66]
  PIN o[67]
    DIRECTION OUTPUT ;
    USE SIGNAL ;
    PORT
      LAYER M5 ;
        RECT  14.64 43.116 14.664 43.2 ;
    END
  END o[67]
  PIN o[68]
    DIRECTION OUTPUT ;
    USE SIGNAL ;
    PORT
      LAYER M3 ;
        RECT  14.832 43.162 14.85 43.2 ;
    END
  END o[68]
  PIN o[69]
    DIRECTION OUTPUT ;
    USE SIGNAL ;
    PORT
      LAYER M5 ;
        RECT  15.024 43.116 15.048 43.2 ;
    END
  END o[69]
  PIN o[6]
    DIRECTION OUTPUT ;
    USE SIGNAL ;
    PORT
      LAYER M3 ;
        RECT  2.376 43.162 2.394 43.2 ;
    END
  END o[6]
  PIN o[70]
    DIRECTION OUTPUT ;
    USE SIGNAL ;
    PORT
      LAYER M3 ;
        RECT  15.228 43.162 15.246 43.2 ;
    END
  END o[70]
  PIN o[71]
    DIRECTION OUTPUT ;
    USE SIGNAL ;
    PORT
      LAYER M5 ;
        RECT  15.456 43.116 15.48 43.2 ;
    END
  END o[71]
  PIN o[72]
    DIRECTION OUTPUT ;
    USE SIGNAL ;
    PORT
      LAYER M3 ;
        RECT  15.624 43.162 15.642 43.2 ;
    END
  END o[72]
  PIN o[73]
    DIRECTION OUTPUT ;
    USE SIGNAL ;
    PORT
      LAYER M5 ;
        RECT  15.84 43.116 15.864 43.2 ;
    END
  END o[73]
  PIN o[74]
    DIRECTION OUTPUT ;
    USE SIGNAL ;
    PORT
      LAYER M3 ;
        RECT  16.056 43.162 16.074 43.2 ;
    END
  END o[74]
  PIN o[75]
    DIRECTION OUTPUT ;
    USE SIGNAL ;
    PORT
      LAYER M5 ;
        RECT  16.224 43.116 16.248 43.2 ;
    END
  END o[75]
  PIN o[76]
    DIRECTION OUTPUT ;
    USE SIGNAL ;
    PORT
      LAYER M3 ;
        RECT  16.452 43.162 16.47 43.2 ;
    END
  END o[76]
  PIN o[77]
    DIRECTION OUTPUT ;
    USE SIGNAL ;
    PORT
      LAYER M5 ;
        RECT  16.656 43.116 16.68 43.2 ;
    END
  END o[77]
  PIN o[78]
    DIRECTION OUTPUT ;
    USE SIGNAL ;
    PORT
      LAYER M3 ;
        RECT  16.848 43.162 16.866 43.2 ;
    END
  END o[78]
  PIN o[79]
    DIRECTION OUTPUT ;
    USE SIGNAL ;
    PORT
      LAYER M5 ;
        RECT  17.04 43.116 17.064 43.2 ;
    END
  END o[79]
  PIN o[7]
    DIRECTION OUTPUT ;
    USE SIGNAL ;
    PORT
      LAYER M5 ;
        RECT  2.592 43.116 2.616 43.2 ;
    END
  END o[7]
  PIN o[80]
    DIRECTION OUTPUT ;
    USE SIGNAL ;
    PORT
      LAYER M3 ;
        RECT  17.244 43.162 17.262 43.2 ;
    END
  END o[80]
  PIN o[81]
    DIRECTION OUTPUT ;
    USE SIGNAL ;
    PORT
      LAYER M5 ;
        RECT  17.424 43.116 17.448 43.2 ;
    END
  END o[81]
  PIN o[82]
    DIRECTION OUTPUT ;
    USE SIGNAL ;
    PORT
      LAYER M3 ;
        RECT  17.64 43.162 17.658 43.2 ;
    END
  END o[82]
  PIN o[83]
    DIRECTION OUTPUT ;
    USE SIGNAL ;
    PORT
      LAYER M5 ;
        RECT  17.856 43.116 17.88 43.2 ;
    END
  END o[83]
  PIN o[84]
    DIRECTION OUTPUT ;
    USE SIGNAL ;
    PORT
      LAYER M3 ;
        RECT  18.036 43.162 18.054 43.2 ;
    END
  END o[84]
  PIN o[85]
    DIRECTION OUTPUT ;
    USE SIGNAL ;
    PORT
      LAYER M5 ;
        RECT  18.24 43.116 18.264 43.2 ;
    END
  END o[85]
  PIN o[86]
    DIRECTION OUTPUT ;
    USE SIGNAL ;
    PORT
      LAYER M3 ;
        RECT  18.468 43.162 18.486 43.2 ;
    END
  END o[86]
  PIN o[87]
    DIRECTION OUTPUT ;
    USE SIGNAL ;
    PORT
      LAYER M5 ;
        RECT  18.672 43.116 18.696 43.2 ;
    END
  END o[87]
  PIN o[88]
    DIRECTION OUTPUT ;
    USE SIGNAL ;
    PORT
      LAYER M3 ;
        RECT  18.864 43.162 18.882 43.2 ;
    END
  END o[88]
  PIN o[89]
    DIRECTION OUTPUT ;
    USE SIGNAL ;
    PORT
      LAYER M5 ;
        RECT  19.056 43.116 19.08 43.2 ;
    END
  END o[89]
  PIN o[8]
    DIRECTION OUTPUT ;
    USE SIGNAL ;
    PORT
      LAYER M3 ;
        RECT  2.772 43.162 2.79 43.2 ;
    END
  END o[8]
  PIN o[90]
    DIRECTION OUTPUT ;
    USE SIGNAL ;
    PORT
      LAYER M3 ;
        RECT  19.26 43.162 19.278 43.2 ;
    END
  END o[90]
  PIN o[91]
    DIRECTION OUTPUT ;
    USE SIGNAL ;
    PORT
      LAYER M5 ;
        RECT  19.44 43.116 19.464 43.2 ;
    END
  END o[91]
  PIN o[92]
    DIRECTION OUTPUT ;
    USE SIGNAL ;
    PORT
      LAYER M3 ;
        RECT  19.656 43.162 19.674 43.2 ;
    END
  END o[92]
  PIN o[93]
    DIRECTION OUTPUT ;
    USE SIGNAL ;
    PORT
      LAYER M5 ;
        RECT  19.872 43.116 19.896 43.2 ;
    END
  END o[93]
  PIN o[94]
    DIRECTION OUTPUT ;
    USE SIGNAL ;
    PORT
      LAYER M3 ;
        RECT  20.052 43.162 20.07 43.2 ;
    END
  END o[94]
  PIN o[95]
    DIRECTION OUTPUT ;
    USE SIGNAL ;
    PORT
      LAYER M5 ;
        RECT  20.256 43.116 20.28 43.2 ;
    END
  END o[95]
  PIN o[96]
    DIRECTION OUTPUT ;
    USE SIGNAL ;
    PORT
      LAYER M3 ;
        RECT  20.448 43.162 20.466 43.2 ;
    END
  END o[96]
  PIN o[97]
    DIRECTION OUTPUT ;
    USE SIGNAL ;
    PORT
      LAYER M5 ;
        RECT  20.64 43.116 20.664 43.2 ;
    END
  END o[97]
  PIN o[98]
    DIRECTION OUTPUT ;
    USE SIGNAL ;
    PORT
      LAYER M3 ;
        RECT  20.88 43.162 20.898 43.2 ;
    END
  END o[98]
  PIN o[99]
    DIRECTION OUTPUT ;
    USE SIGNAL ;
    PORT
      LAYER M5 ;
        RECT  21.072 43.116 21.096 43.2 ;
    END
  END o[99]
  PIN o[9]
    DIRECTION OUTPUT ;
    USE SIGNAL ;
    PORT
      LAYER M5 ;
        RECT  2.976 43.116 3 43.2 ;
    END
  END o[9]
  PIN rsi_r
    DIRECTION INPUT ;
    USE SIGNAL ;
    PORT
      LAYER M3 ;
        RECT  106.812 43.162 106.83 43.2 ;
    END
  END rsi_r
  PIN rsi_w
    DIRECTION INPUT ;
    USE SIGNAL ;
    PORT
      LAYER M3 ;
        RECT  106.812 0 106.83 0.038 ;
    END
  END rsi_w
  PIN VSS
    DIRECTION INOUT ;
    USE GROUND ;
    PORT
      LAYER M5 ;
        RECT  105 2.137 105.12 41.063 ;
        RECT  99.6 2.137 99.72 41.063 ;
        RECT  94.2 2.137 94.32 41.063 ;
        RECT  88.8 2.137 88.92 41.063 ;
        RECT  83.4 2.137 83.52 41.063 ;
        RECT  78 2.137 78.12 41.063 ;
        RECT  72.6 2.137 72.72 41.063 ;
        RECT  67.2 2.137 67.32 41.063 ;
        RECT  61.8 2.137 61.92 41.063 ;
        RECT  56.4 2.137 56.52 41.063 ;
        RECT  51 2.137 51.12 41.063 ;
        RECT  45.6 2.137 45.72 41.063 ;
        RECT  40.2 2.137 40.32 41.063 ;
        RECT  34.8 2.137 34.92 41.063 ;
        RECT  29.4 2.137 29.52 41.063 ;
        RECT  24 2.137 24.12 41.063 ;
        RECT  18.6 2.137 18.72 41.063 ;
        RECT  13.2 2.137 13.32 41.063 ;
        RECT  7.8 2.137 7.92 41.063 ;
        RECT  2.4 2.137 2.52 41.063 ;
    END
  END VSS
  PIN VDD
    DIRECTION INOUT ;
    USE POWER ;
    PORT
      LAYER M5 ;
        RECT  105.192 2.151 105.312 41.049 ;
        RECT  99.792 2.151 99.912 41.049 ;
        RECT  94.392 2.151 94.512 41.049 ;
        RECT  88.992 2.151 89.112 41.049 ;
        RECT  83.592 2.151 83.712 41.049 ;
        RECT  78.192 2.151 78.312 41.049 ;
        RECT  72.792 2.151 72.912 41.049 ;
        RECT  67.392 2.151 67.512 41.049 ;
        RECT  61.992 2.151 62.112 41.049 ;
        RECT  56.592 2.151 56.712 41.049 ;
        RECT  51.192 2.151 51.312 41.049 ;
        RECT  45.792 2.151 45.912 41.049 ;
        RECT  40.392 2.151 40.512 41.049 ;
        RECT  34.992 2.151 35.112 41.049 ;
        RECT  29.592 2.151 29.712 41.049 ;
        RECT  24.192 2.151 24.312 41.049 ;
        RECT  18.792 2.151 18.912 41.049 ;
        RECT  13.392 2.151 13.512 41.049 ;
        RECT  7.992 2.151 8.112 41.049 ;
        RECT  2.592 2.151 2.712 41.049 ;
    END
  END VDD
  OBS
    LAYER RVTN ;
     RECT  2.16 2.16 105.84 2.295 ;
     RECT  2.16 2.565 105.84 2.835 ;
     RECT  2.16 3.105 105.84 3.375 ;
     RECT  2.16 3.645 105.84 3.915 ;
     RECT  2.16 4.185 105.84 4.455 ;
     RECT  2.16 4.725 105.84 4.995 ;
     RECT  2.16 5.265 105.84 5.535 ;
     RECT  2.16 5.805 105.84 6.075 ;
     RECT  2.16 6.345 105.84 6.615 ;
     RECT  2.16 6.885 105.84 7.155 ;
     RECT  2.16 7.425 105.84 7.695 ;
     RECT  2.16 7.965 105.84 8.235 ;
     RECT  2.16 8.505 105.84 8.775 ;
     RECT  2.16 9.045 105.84 9.315 ;
     RECT  2.16 9.585 105.84 9.855 ;
     RECT  2.16 10.125 105.84 10.395 ;
     RECT  2.16 10.665 105.84 10.935 ;
     RECT  2.16 11.205 105.84 11.475 ;
     RECT  2.16 11.745 105.84 12.015 ;
     RECT  2.16 12.285 105.84 12.555 ;
     RECT  2.16 12.825 105.84 13.095 ;
     RECT  2.16 13.365 105.84 13.635 ;
     RECT  2.16 13.905 105.84 14.175 ;
     RECT  2.16 14.445 105.84 14.715 ;
     RECT  2.16 14.985 105.84 15.255 ;
     RECT  2.16 15.525 105.84 15.795 ;
     RECT  2.16 16.065 105.84 16.335 ;
     RECT  2.16 16.605 105.84 16.875 ;
     RECT  2.16 17.145 105.84 17.415 ;
     RECT  2.16 17.685 105.84 17.955 ;
     RECT  2.16 18.225 105.84 18.495 ;
     RECT  2.16 18.765 105.84 19.035 ;
     RECT  2.16 19.305 105.84 19.575 ;
     RECT  2.16 19.845 105.84 20.115 ;
     RECT  2.16 20.385 105.84 20.655 ;
     RECT  2.16 20.925 105.84 21.195 ;
     RECT  2.16 21.465 105.84 21.735 ;
     RECT  2.16 22.005 105.84 22.275 ;
     RECT  2.16 22.545 105.84 22.815 ;
     RECT  2.16 23.085 105.84 23.355 ;
     RECT  2.16 23.625 105.84 23.895 ;
     RECT  2.16 24.165 105.84 24.435 ;
     RECT  2.16 24.705 105.84 24.975 ;
     RECT  2.16 25.245 105.84 25.515 ;
     RECT  2.16 25.785 105.84 26.055 ;
     RECT  2.16 26.325 105.84 26.595 ;
     RECT  2.16 26.865 105.84 27.135 ;
     RECT  2.16 27.405 105.84 27.675 ;
     RECT  2.16 27.945 105.84 28.215 ;
     RECT  2.16 28.485 105.84 28.755 ;
     RECT  2.16 29.025 105.84 29.295 ;
     RECT  2.16 29.565 105.84 29.835 ;
     RECT  2.16 30.105 105.84 30.375 ;
     RECT  2.16 30.645 105.84 30.915 ;
     RECT  2.16 31.185 105.84 31.455 ;
     RECT  2.16 31.725 105.84 31.995 ;
     RECT  2.16 32.265 105.84 32.535 ;
     RECT  2.16 32.805 105.84 33.075 ;
     RECT  2.16 33.345 105.84 33.615 ;
     RECT  2.16 33.885 105.84 34.155 ;
     RECT  2.16 34.425 105.84 34.695 ;
     RECT  2.16 34.965 105.84 35.235 ;
     RECT  2.16 35.505 105.84 35.775 ;
     RECT  2.16 36.045 105.84 36.315 ;
     RECT  2.16 36.585 105.84 36.855 ;
     RECT  2.16 37.125 105.84 37.395 ;
     RECT  2.16 37.665 105.84 37.935 ;
     RECT  2.16 38.205 105.84 38.475 ;
     RECT  2.16 38.745 105.84 39.015 ;
     RECT  2.16 39.285 105.84 39.555 ;
     RECT  2.16 39.825 105.84 40.095 ;
     RECT  2.16 40.365 105.84 40.635 ;
     RECT  2.16 40.905 105.84 41.04 ;
    LAYER RVTP ;
     RECT  2.16 2.295 105.84 2.565 ;
     RECT  2.16 2.835 105.84 3.105 ;
     RECT  2.16 3.375 105.84 3.645 ;
     RECT  2.16 3.915 105.84 4.185 ;
     RECT  2.16 4.455 105.84 4.725 ;
     RECT  2.16 4.995 105.84 5.265 ;
     RECT  2.16 5.535 105.84 5.805 ;
     RECT  2.16 6.075 105.84 6.345 ;
     RECT  2.16 6.615 105.84 6.885 ;
     RECT  2.16 7.155 105.84 7.425 ;
     RECT  2.16 7.695 105.84 7.965 ;
     RECT  2.16 8.235 105.84 8.505 ;
     RECT  2.16 8.775 105.84 9.045 ;
     RECT  2.16 9.315 105.84 9.585 ;
     RECT  2.16 9.855 105.84 10.125 ;
     RECT  2.16 10.395 105.84 10.665 ;
     RECT  2.16 10.935 105.84 11.205 ;
     RECT  2.16 11.475 105.84 11.745 ;
     RECT  2.16 12.015 105.84 12.285 ;
     RECT  2.16 12.555 105.84 12.825 ;
     RECT  2.16 13.095 105.84 13.365 ;
     RECT  2.16 13.635 105.84 13.905 ;
     RECT  2.16 14.175 105.84 14.445 ;
     RECT  2.16 14.715 105.84 14.985 ;
     RECT  2.16 15.255 105.84 15.525 ;
     RECT  2.16 15.795 105.84 16.065 ;
     RECT  2.16 16.335 105.84 16.605 ;
     RECT  2.16 16.875 105.84 17.145 ;
     RECT  2.16 17.415 105.84 17.685 ;
     RECT  2.16 17.955 105.84 18.225 ;
     RECT  2.16 18.495 105.84 18.765 ;
     RECT  2.16 19.035 105.84 19.305 ;
     RECT  2.16 19.575 105.84 19.845 ;
     RECT  2.16 20.115 105.84 20.385 ;
     RECT  2.16 20.655 105.84 20.925 ;
     RECT  2.16 21.195 105.84 21.465 ;
     RECT  2.16 21.735 105.84 22.005 ;
     RECT  2.16 22.275 105.84 22.545 ;
     RECT  2.16 22.815 105.84 23.085 ;
     RECT  2.16 23.355 105.84 23.625 ;
     RECT  2.16 23.895 105.84 24.165 ;
     RECT  2.16 24.435 105.84 24.705 ;
     RECT  2.16 24.975 105.84 25.245 ;
     RECT  2.16 25.515 105.84 25.785 ;
     RECT  2.16 26.055 105.84 26.325 ;
     RECT  2.16 26.595 105.84 26.865 ;
     RECT  2.16 27.135 105.84 27.405 ;
     RECT  2.16 27.675 105.84 27.945 ;
     RECT  2.16 28.215 105.84 28.485 ;
     RECT  2.16 28.755 105.84 29.025 ;
     RECT  2.16 29.295 105.84 29.565 ;
     RECT  2.16 29.835 105.84 30.105 ;
     RECT  2.16 30.375 105.84 30.645 ;
     RECT  2.16 30.915 105.84 31.185 ;
     RECT  2.16 31.455 105.84 31.725 ;
     RECT  2.16 31.995 105.84 32.265 ;
     RECT  2.16 32.535 105.84 32.805 ;
     RECT  2.16 33.075 105.84 33.345 ;
     RECT  2.16 33.615 105.84 33.885 ;
     RECT  2.16 34.155 105.84 34.425 ;
     RECT  2.16 34.695 105.84 34.965 ;
     RECT  2.16 35.235 105.84 35.505 ;
     RECT  2.16 35.775 105.84 36.045 ;
     RECT  2.16 36.315 105.84 36.585 ;
     RECT  2.16 36.855 105.84 37.125 ;
     RECT  2.16 37.395 105.84 37.665 ;
     RECT  2.16 37.935 105.84 38.205 ;
     RECT  2.16 38.475 105.84 38.745 ;
     RECT  2.16 39.015 105.84 39.285 ;
     RECT  2.16 39.555 105.84 39.825 ;
     RECT  2.16 40.095 105.84 40.365 ;
     RECT  2.16 40.635 105.84 40.905 ;
    LAYER M1 ;
     RECT  2.16 2.151 105.84 41.049 ;
    LAYER M2 ;
     RECT  1.183 26.532 2.16 26.55 ;
     RECT  1.579 28.422 2.16 28.44 ;
     RECT  2.011 30.582 2.16 30.6 ;
     RECT  1.975 37.134 2.16 37.152 ;
     RECT  1.579 40.176 2.16 40.194 ;
     RECT  2.335 0.036 2.399 0.054 ;
     RECT  2.767 0.108 2.875 0.126 ;
     RECT  2.371 42.192 3.119 42.21 ;
     RECT  2.875 0.108 3.163 0.324 ;
     RECT  1.183 43.038 4.055 43.056 ;
     RECT  4.387 43.146 4.487 43.164 ;
     RECT  2.16 2.151 4.855 41.049 ;
     RECT  4.855 2.034 5.251 41.049 ;
     RECT  3.163 0.036 6.071 0.324 ;
     RECT  5.251 1.962 6.863 41.049 ;
     RECT  6.071 0.036 8.303 0.279 ;
     RECT  8.303 0.108 8.843 0.279 ;
     RECT  8.843 0.108 9.095 0.126 ;
     RECT  6.799 43.146 9.707 43.164 ;
     RECT  9.607 42.192 9.779 42.21 ;
     RECT  6.863 2.034 10.031 41.049 ;
     RECT  10.031 2.151 10.831 41.049 ;
     RECT  10.831 1.728 11.255 41.049 ;
     RECT  11.255 2.151 12.415 41.049 ;
     RECT  10.795 0.036 12.803 0.054 ;
     RECT  12.415 2.106 12.811 41.049 ;
     RECT  12.811 1.728 13.019 41.049 ;
     RECT  11.623 43.146 13.379 43.164 ;
     RECT  13.019 2.106 13.819 41.049 ;
     RECT  13.639 42.192 13.919 42.21 ;
     RECT  14.431 0.108 14.575 0.126 ;
     RECT  14.575 0.108 14.791 0.279 ;
     RECT  13.819 2.034 15.359 41.049 ;
     RECT  14.827 43.146 15.359 43.164 ;
     RECT  14.791 0.036 17.267 0.279 ;
     RECT  17.267 0.036 17.519 0.126 ;
     RECT  17.519 0.108 17.663 0.126 ;
     RECT  18.031 0.144 18.463 0.162 ;
     RECT  18.463 0.144 18.859 0.279 ;
     RECT  15.359 2.151 18.931 41.049 ;
     RECT  18.859 0.144 19.291 0.396 ;
     RECT  18.031 42.192 19.859 42.21 ;
     RECT  18.931 1.962 20.083 41.049 ;
     RECT  20.083 1.962 20.471 41.094 ;
     RECT  19.291 0.036 20.975 0.396 ;
     RECT  20.471 1.962 21.119 41.049 ;
     RECT  21.271 1.152 21.407 1.17 ;
     RECT  21.451 1.224 21.659 1.242 ;
     RECT  22.063 43.146 22.163 43.164 ;
     RECT  20.975 0.072 22.667 0.396 ;
     RECT  22.639 1.152 22.811 1.17 ;
     RECT  21.119 2.034 23.035 41.049 ;
     RECT  23.035 1.728 23.315 41.049 ;
     RECT  23.215 43.146 23.315 43.164 ;
     RECT  22.667 0.072 23.647 0.279 ;
     RECT  23.315 2.151 24.079 41.049 ;
     RECT  24.079 43.146 24.179 43.164 ;
     RECT  23.647 0.072 24.331 0.549 ;
     RECT  24.079 1.728 24.331 41.049 ;
     RECT  24.331 0.072 24.395 41.049 ;
     RECT  24.395 0.072 24.431 1.17 ;
     RECT  24.431 0.072 25.447 0.549 ;
     RECT  25.447 0.036 26.303 0.549 ;
     RECT  24.395 2.106 26.627 41.049 ;
     RECT  26.627 2.151 27.463 41.049 ;
     RECT  26.303 0.036 27.535 0.162 ;
     RECT  27.535 0.036 27.787 0.198 ;
     RECT  27.463 2.106 27.887 41.049 ;
     RECT  27.787 0.036 28.355 0.279 ;
     RECT  28.355 0.108 28.427 0.279 ;
     RECT  27.679 42.192 28.571 42.21 ;
     RECT  28.075 43.146 28.751 43.164 ;
     RECT  28.427 0.18 29.191 0.279 ;
     RECT  29.191 0.108 29.263 0.279 ;
     RECT  29.263 0.036 29.327 0.279 ;
     RECT  29.327 0.036 29.723 0.126 ;
     RECT  29.695 43.146 29.795 43.164 ;
     RECT  29.723 0.108 30.379 0.126 ;
     RECT  30.091 42.192 30.443 42.21 ;
     RECT  30.379 0.108 30.919 0.198 ;
     RECT  30.919 0.036 31.531 0.198 ;
     RECT  31.315 42.192 31.667 42.21 ;
     RECT  31.531 0.036 31.927 0.324 ;
     RECT  31.927 0.036 34.511 0.504 ;
     RECT  34.511 0.036 34.619 0.432 ;
     RECT  33.331 43.146 34.943 43.164 ;
     RECT  34.619 0.144 35.339 0.432 ;
     RECT  35.339 0.144 36.319 0.36 ;
     RECT  36.319 0.036 37.067 0.36 ;
     RECT  27.887 2.151 37.543 41.049 ;
     RECT  37.067 0.036 37.751 0.054 ;
     RECT  37.543 2.07 38.731 41.049 ;
     RECT  39.343 0.036 39.631 0.054 ;
     RECT  39.631 0.036 39.767 0.09 ;
     RECT  39.767 0.036 40.019 0.054 ;
     RECT  38.731 2.034 40.603 41.049 ;
     RECT  39.739 42.192 40.811 42.21 ;
     RECT  40.603 1.728 40.991 41.049 ;
     RECT  40.991 2.151 42.043 41.049 ;
     RECT  42.043 1.728 42.179 41.049 ;
     RECT  42.151 42.192 42.359 42.21 ;
     RECT  42.115 0.108 42.439 0.126 ;
     RECT  42.259 1.152 43.043 1.17 ;
     RECT  42.943 43.146 43.079 43.164 ;
     RECT  42.179 2.106 43.691 41.049 ;
     RECT  42.439 0.108 43.735 0.198 ;
     RECT  43.735 0.036 43.799 0.198 ;
     RECT  43.799 0.036 44.195 0.126 ;
     RECT  44.195 0.108 44.591 0.126 ;
     RECT  45.139 0.144 45.787 0.162 ;
     RECT  46.183 43.146 46.427 43.164 ;
     RECT  45.787 0.036 46.435 0.162 ;
     RECT  46.435 0.036 47.399 0.234 ;
     RECT  49.027 1.152 49.163 1.17 ;
     RECT  47.399 0.036 49.487 0.054 ;
     RECT  43.691 2.151 50.899 41.049 ;
     RECT  49.387 42.192 50.927 42.21 ;
     RECT  50.899 1.881 51.331 41.049 ;
     RECT  51.007 43.146 52.079 43.164 ;
     RECT  51.331 1.152 52.151 41.049 ;
     RECT  52.195 43.074 53.023 43.092 ;
     RECT  53.023 43.074 53.051 43.164 ;
     RECT  53.051 43.146 53.123 43.164 ;
     RECT  52.151 1.836 53.519 41.049 ;
     RECT  50.611 0.036 53.807 0.054 ;
     RECT  53.519 2.106 54.239 41.049 ;
     RECT  55.039 1.152 55.139 1.17 ;
     RECT  54.679 0.108 55.183 0.126 ;
     RECT  55.183 0.036 55.859 0.126 ;
     RECT  55.859 0.108 56.255 0.126 ;
     RECT  56.623 43.146 56.759 43.164 ;
     RECT  56.623 0.036 56.867 0.054 ;
     RECT  56.839 1.152 56.939 1.17 ;
     RECT  57.595 0.108 57.775 0.126 ;
     RECT  57.775 1.152 58.379 1.17 ;
     RECT  57.775 0.036 58.667 0.126 ;
     RECT  57.847 43.038 58.883 43.056 ;
     RECT  58.667 0.108 59.063 0.126 ;
     RECT  58.243 42.192 59.063 42.21 ;
     RECT  59.035 43.146 59.135 43.164 ;
     RECT  59.431 1.152 59.531 1.17 ;
     RECT  59.611 0.036 60.287 0.054 ;
     RECT  60.655 43.146 60.755 43.164 ;
     RECT  54.239 2.151 61.591 41.049 ;
     RECT  61.591 2.151 61.871 41.13 ;
     RECT  62.743 0.036 64.319 0.054 ;
     RECT  64.327 0.108 64.679 0.126 ;
     RECT  65.875 42.192 66.515 42.21 ;
     RECT  66.595 0.036 67.459 0.054 ;
     RECT  67.459 0.036 67.819 0.09 ;
     RECT  67.819 0.036 67.883 0.126 ;
     RECT  67.883 0.108 67.919 0.126 ;
     RECT  67.459 42.192 67.955 42.21 ;
     RECT  67.891 43.146 68.459 43.164 ;
     RECT  61.871 2.151 68.647 41.049 ;
     RECT  68.683 0.036 69.367 0.054 ;
     RECT  69.475 42.192 69.755 42.21 ;
     RECT  68.647 2.106 70.123 41.049 ;
     RECT  69.367 0.036 70.727 0.198 ;
     RECT  70.123 2.034 71.627 41.049 ;
     RECT  70.727 0.036 71.735 0.126 ;
     RECT  71.735 0.072 72.283 0.126 ;
     RECT  72.283 0.072 72.491 0.198 ;
     RECT  71.627 2.106 72.715 41.049 ;
     RECT  69.871 43.146 72.715 43.164 ;
     RECT  72.715 43.074 72.779 43.164 ;
     RECT  72.779 43.074 72.815 43.092 ;
     RECT  72.491 0.18 73.255 0.198 ;
     RECT  72.715 2.034 73.751 41.049 ;
     RECT  73.507 43.146 74.219 43.164 ;
     RECT  73.111 42.192 74.299 42.21 ;
     RECT  73.255 0.036 74.327 0.198 ;
     RECT  73.751 2.106 74.471 41.049 ;
     RECT  74.299 42.192 74.759 42.318 ;
     RECT  74.327 0.18 75.011 0.198 ;
     RECT  74.759 42.192 75.263 42.21 ;
     RECT  75.883 1.152 75.983 1.17 ;
     RECT  75.523 0.036 76.315 0.126 ;
     RECT  76.315 0.036 76.351 0.198 ;
     RECT  76.351 0.036 76.739 0.279 ;
     RECT  75.127 43.146 76.991 43.164 ;
     RECT  76.739 0.036 77.135 0.162 ;
     RECT  77.503 42.192 77.639 42.21 ;
     RECT  78.727 43.146 78.827 43.164 ;
     RECT  77.135 0.036 79.015 0.126 ;
     RECT  79.015 1.152 79.115 1.17 ;
     RECT  79.015 0.036 79.547 0.234 ;
     RECT  79.547 0.036 80.411 0.162 ;
     RECT  80.347 42.192 80.447 42.21 ;
     RECT  80.411 0.072 80.915 0.162 ;
     RECT  80.915 0.072 81.139 0.126 ;
     RECT  81.103 1.152 81.203 1.17 ;
     RECT  81.139 0.036 81.563 0.126 ;
     RECT  81.563 0.036 82.327 0.054 ;
     RECT  81.931 42.192 82.327 42.21 ;
     RECT  82.327 42.192 82.355 42.282 ;
     RECT  82.355 42.264 82.427 42.282 ;
     RECT  82.327 0.036 82.535 0.09 ;
     RECT  82.535 0.036 82.823 0.054 ;
     RECT  84.271 0.036 84.371 0.054 ;
     RECT  85.171 0.036 85.235 0.054 ;
     RECT  85.963 43.074 86.359 43.092 ;
     RECT  86.359 43.074 86.387 43.164 ;
     RECT  86.387 43.146 86.495 43.164 ;
     RECT  86.755 0.036 86.899 0.054 ;
     RECT  86.899 0.036 87.107 0.279 ;
     RECT  86.755 42.192 87.431 42.21 ;
     RECT  87.107 0.036 88.375 0.234 ;
     RECT  88.375 0.036 88.735 0.279 ;
     RECT  88.735 0.036 88.771 0.396 ;
     RECT  88.771 0.036 88.871 0.549 ;
     RECT  88.871 0.036 90.463 0.504 ;
     RECT  91.183 43.146 91.507 43.164 ;
     RECT  90.463 0.036 91.787 0.549 ;
     RECT  91.507 43.11 92.075 43.164 ;
     RECT  92.075 43.146 92.939 43.164 ;
     RECT  91.787 0.036 93.011 0.504 ;
     RECT  94.531 1.152 94.631 1.17 ;
     RECT  93.011 0.036 94.847 0.09 ;
     RECT  94.847 0.036 94.955 0.054 ;
     RECT  95.215 43.074 96.403 43.092 ;
     RECT  96.403 43.074 96.431 43.164 ;
     RECT  96.007 42.192 96.467 42.21 ;
     RECT  96.403 0.036 96.727 0.054 ;
     RECT  96.727 0.036 97.195 0.126 ;
     RECT  96.431 43.146 97.195 43.164 ;
     RECT  97.195 0.036 97.547 0.162 ;
     RECT  97.195 43.074 98.015 43.164 ;
     RECT  98.015 43.146 98.627 43.164 ;
     RECT  98.779 1.152 98.915 1.17 ;
     RECT  74.471 2.151 99.535 41.049 ;
     RECT  99.535 1.728 99.635 41.049 ;
     RECT  99.535 43.146 99.635 43.164 ;
     RECT  97.547 0.036 100.039 0.126 ;
     RECT  100.039 0.036 102.227 0.198 ;
     RECT  102.227 0.036 103.675 0.09 ;
     RECT  103.675 0.036 104.063 0.126 ;
     RECT  104.063 0.036 104.459 0.054 ;
     RECT  102.019 43.146 104.999 43.164 ;
     RECT  99.635 2.151 105.84 41.049 ;
     RECT  105.475 0.036 106.835 0.054 ;
     RECT  105.84 40.95 106.835 40.968 ;
    LAYER M3 ;
     RECT  105.984 0.012 106.002 0.031 ;
     RECT  1.188 0.012 104.454 0.059 ;
     RECT  106.812 0.012 106.83 0.059 ;
     RECT  30.096 0.059 37.35 0.077 ;
     RECT  46.188 0.059 63.414 0.077 ;
     RECT  67.464 0.059 81.558 0.077 ;
     RECT  82.332 0.059 104.058 0.077 ;
     RECT  46.188 0.077 47.898 0.095 ;
     RECT  67.464 0.077 74.25 0.095 ;
     RECT  82.332 0.077 85.986 0.095 ;
     RECT  1.188 0.059 29.322 0.131 ;
     RECT  38.16 0.059 45.378 0.131 ;
     RECT  50.688 0.077 63.414 0.131 ;
     RECT  74.988 0.077 81.558 0.131 ;
     RECT  86.904 0.077 104.058 0.131 ;
     RECT  3.996 0.131 29.322 0.167 ;
     RECT  74.988 0.131 81.342 0.167 ;
     RECT  30.096 0.077 37.278 0.173 ;
     RECT  105.48 0.031 106.002 0.173 ;
     RECT  64.26 0.059 66.618 0.269 ;
     RECT  18.468 0.167 29.322 0.284 ;
     RECT  74.988 0.167 76.734 0.284 ;
     RECT  86.904 0.131 104.022 0.317 ;
     RECT  1.188 0.131 3.258 0.329 ;
     RECT  86.976 0.317 96.678 0.329 ;
     RECT  91.764 0.329 96.678 0.365 ;
     RECT  18.468 0.284 29.286 0.401 ;
     RECT  30.384 0.173 37.278 0.413 ;
     RECT  56.844 0.131 58.338 0.413 ;
     RECT  86.976 0.329 90.882 0.437 ;
     RECT  3.996 0.167 17.514 0.509 ;
     RECT  59.436 0.131 63.414 0.509 ;
     RECT  3.996 0.509 13.23 0.557 ;
     RECT  14.04 0.509 17.514 0.557 ;
     RECT  44.964 0.131 45.378 0.557 ;
     RECT  59.436 0.509 61.47 0.557 ;
     RECT  91.764 0.365 94.95 0.557 ;
     RECT  96.012 0.365 96.678 0.557 ;
     RECT  3.996 0.557 13.014 0.653 ;
     RECT  56.844 0.413 56.862 1.147 ;
     RECT  57.6 0.413 58.338 1.147 ;
     RECT  56.844 1.147 58.374 1.175 ;
     RECT  59.436 0.557 61.074 1.175 ;
     RECT  19.296 0.401 29.286 1.247 ;
     RECT  3.996 0.653 12.834 1.723 ;
     RECT  82.512 0.095 85.986 1.723 ;
     RECT  18.468 0.401 18.486 1.957 ;
     RECT  19.296 1.247 21.618 1.957 ;
     RECT  67.716 0.095 69.498 2.029 ;
     RECT  70.236 0.095 74.25 2.029 ;
     RECT  37.26 0.413 37.278 2.065 ;
     RECT  38.16 0.131 44.082 2.065 ;
     RECT  13.824 2.029 13.842 2.101 ;
     RECT  14.58 0.557 17.514 2.101 ;
     RECT  67.716 2.029 74.25 2.101 ;
     RECT  74.988 0.284 76.518 2.101 ;
     RECT  1.188 0.329 2.358 2.143 ;
     RECT  3.996 1.723 13.014 2.143 ;
     RECT  13.824 2.101 17.514 2.143 ;
     RECT  22.356 1.247 29.286 2.143 ;
     RECT  45.144 0.557 45.378 2.143 ;
     RECT  50.688 0.131 55.818 2.143 ;
     RECT  56.916 1.175 58.374 2.143 ;
     RECT  62.424 0.509 63.414 2.143 ;
     RECT  64.296 0.269 66.618 2.143 ;
     RECT  67.716 2.101 76.518 2.143 ;
     RECT  105.48 0.173 105.498 2.143 ;
     RECT  1.188 2.143 2.505 2.191 ;
     RECT  3.24 0.329 3.258 2.191 ;
     RECT  18.468 1.957 21.618 2.191 ;
     RECT  22.356 2.143 29.505 2.191 ;
     RECT  30.384 0.413 36.45 2.191 ;
     RECT  37.26 2.065 44.082 2.191 ;
     RECT  96.66 0.557 96.678 2.191 ;
     RECT  97.524 0.317 104.022 2.191 ;
     RECT  48.816 0.077 49.806 2.203 ;
     RECT  50.688 2.143 58.374 2.203 ;
     RECT  30.384 2.191 44.118 2.255 ;
     RECT  82.476 1.723 85.986 2.255 ;
     RECT  77.508 0.167 81.342 2.263 ;
     RECT  82.512 2.255 85.986 2.263 ;
     RECT  18.468 2.191 29.505 2.413 ;
     RECT  30.384 2.255 37.278 2.413 ;
     RECT  45.144 2.143 45.705 2.413 ;
     RECT  46.44 0.095 47.898 2.413 ;
     RECT  82.512 2.263 86.022 2.461 ;
     RECT  86.976 0.437 90.846 2.461 ;
     RECT  64.296 2.143 76.518 2.497 ;
     RECT  77.508 2.263 81.486 2.497 ;
     RECT  45.144 2.413 47.898 2.731 ;
     RECT  1.188 2.191 3.258 2.839 ;
     RECT  3.996 2.143 17.514 2.839 ;
     RECT  48.816 2.203 58.374 2.839 ;
     RECT  1.188 2.839 17.586 2.867 ;
     RECT  38.16 2.255 44.118 2.911 ;
     RECT  44.892 2.731 47.898 2.911 ;
     RECT  96.66 2.191 104.022 3.073 ;
     RECT  18.468 2.413 37.278 3.109 ;
     RECT  38.16 2.911 47.898 3.109 ;
     RECT  64.296 2.497 76.59 3.145 ;
     RECT  77.508 2.497 81.558 3.145 ;
     RECT  64.296 3.145 81.558 3.271 ;
     RECT  48.744 2.839 58.374 3.307 ;
     RECT  59.508 1.175 61.074 3.307 ;
     RECT  48.636 3.307 58.374 3.343 ;
     RECT  59.436 3.307 61.074 3.343 ;
     RECT  64.296 3.271 81.702 3.379 ;
     RECT  82.512 2.461 90.846 3.379 ;
     RECT  92.592 0.557 94.95 3.403 ;
     RECT  92.592 3.403 95.31 3.451 ;
     RECT  96.156 3.073 104.022 3.451 ;
     RECT  4.068 2.867 17.586 3.547 ;
     RECT  18.468 3.109 47.898 3.547 ;
     RECT  1.188 2.867 3.33 3.811 ;
     RECT  4.068 3.547 47.898 3.811 ;
     RECT  1.188 3.811 47.898 4.109 ;
     RECT  92.592 3.451 104.022 4.621 ;
     RECT  105.015 2.143 105.498 4.621 ;
     RECT  48.636 3.343 61.074 4.891 ;
     RECT  61.815 2.143 63.414 4.891 ;
     RECT  92.592 4.621 105.498 4.919 ;
     RECT  1.188 4.109 3.33 5.269 ;
     RECT  4.068 4.109 47.898 5.269 ;
     RECT  48.636 4.891 63.414 5.495 ;
     RECT  92.592 4.919 104.094 5.845 ;
     RECT  105.015 4.919 105.498 5.845 ;
     RECT  1.188 5.269 47.898 5.873 ;
     RECT  18.468 5.873 47.898 5.971 ;
     RECT  48.636 5.495 60.462 5.971 ;
     RECT  92.592 5.845 105.498 5.999 ;
     RECT  18.468 5.971 60.462 6.269 ;
     RECT  48.672 6.269 60.462 6.313 ;
     RECT  48.672 6.313 60.498 6.511 ;
     RECT  61.236 5.495 63.414 6.511 ;
     RECT  1.188 5.873 17.586 6.763 ;
     RECT  18.468 6.269 47.898 6.763 ;
     RECT  48.672 6.511 63.414 6.859 ;
     RECT  92.592 5.999 104.238 6.961 ;
     RECT  105.015 5.999 105.498 6.961 ;
     RECT  92.592 6.961 105.498 7.115 ;
     RECT  48.672 6.859 63.558 7.195 ;
     RECT  48.636 7.195 63.558 7.321 ;
     RECT  64.296 3.379 90.846 7.321 ;
     RECT  1.188 6.763 47.898 7.357 ;
     RECT  48.636 7.321 90.846 7.357 ;
     RECT  92.592 7.115 104.202 8.041 ;
     RECT  105.015 7.115 105.498 8.041 ;
     RECT  92.592 8.041 105.498 8.339 ;
     RECT  1.188 7.357 90.846 9.121 ;
     RECT  92.592 8.339 104.13 9.121 ;
     RECT  1.188 9.121 90.918 9.391 ;
     RECT  1.188 9.391 91.35 9.481 ;
     RECT  1.188 9.481 91.494 9.661 ;
     RECT  92.592 9.121 104.238 9.661 ;
     RECT  1.188 9.661 104.238 9.691 ;
     RECT  105.015 8.339 105.498 9.691 ;
     RECT  1.188 9.691 105.498 9.895 ;
     RECT  1.188 9.895 105.714 10.049 ;
     RECT  1.188 10.049 105.498 11.011 ;
     RECT  1.188 11.011 105.642 11.237 ;
     RECT  1.188 11.237 105.297 11.399 ;
     RECT  97.452 11.399 105.297 12.757 ;
     RECT  1.188 11.399 96.678 12.865 ;
     RECT  97.452 12.757 105.642 12.865 ;
     RECT  1.188 12.865 105.642 13.289 ;
     RECT  97.524 13.289 105.642 13.829 ;
     RECT  1.188 13.289 96.714 14.071 ;
     RECT  97.524 13.829 105.297 14.071 ;
     RECT  1.188 14.071 105.297 14.477 ;
     RECT  1.188 14.477 35.802 14.549 ;
     RECT  36.576 14.477 105.297 15.061 ;
     RECT  36.576 15.061 105.498 15.259 ;
     RECT  36.54 15.259 105.498 15.295 ;
     RECT  1.188 14.549 35.73 15.359 ;
     RECT  12.636 15.359 35.73 15.493 ;
     RECT  36.504 15.295 105.498 15.493 ;
     RECT  12.636 15.493 105.498 15.719 ;
     RECT  97.524 15.719 105.498 15.763 ;
     RECT  97.524 15.763 105.642 15.989 ;
     RECT  1.188 15.359 11.898 16.141 ;
     RECT  12.636 15.719 96.786 16.141 ;
     RECT  1.188 16.141 96.786 16.537 ;
     RECT  97.524 15.989 105.498 16.537 ;
     RECT  1.188 16.537 105.498 17.221 ;
     RECT  1.188 17.221 105.642 17.483 ;
     RECT  1.188 17.483 105.297 18.535 ;
     RECT  1.188 18.535 105.714 18.959 ;
     RECT  1.188 18.959 105.498 19.849 ;
     RECT  1.188 19.849 105.642 20.039 ;
     RECT  1.188 20.039 105.498 20.075 ;
     RECT  1.188 20.075 105.297 21.235 ;
     RECT  1.188 21.235 105.354 21.361 ;
     RECT  1.188 21.361 105.57 21.505 ;
     RECT  1.188 21.505 105.714 21.929 ;
     RECT  1.188 21.929 105.297 22.541 ;
     RECT  1.188 22.541 39.15 23.431 ;
     RECT  39.924 22.541 105.297 23.431 ;
     RECT  1.188 23.431 105.297 23.827 ;
     RECT  1.188 23.827 105.498 24.097 ;
     RECT  1.188 24.097 105.642 24.629 ;
     RECT  1.188 24.629 105.498 24.665 ;
     RECT  1.188 24.665 105.297 25.205 ;
     RECT  97.524 25.205 105.297 25.591 ;
     RECT  97.524 25.591 105.534 25.745 ;
     RECT  1.188 25.205 96.786 26.321 ;
     RECT  39.924 26.321 96.786 26.393 ;
     RECT  1.188 26.321 39.15 26.555 ;
     RECT  97.524 25.745 105.297 26.635 ;
     RECT  39.996 26.393 96.786 26.671 ;
     RECT  97.524 26.635 105.714 26.671 ;
     RECT  39.996 26.671 105.714 26.789 ;
     RECT  39.996 26.789 105.354 27.715 ;
     RECT  39.996 27.715 105.642 27.985 ;
     RECT  39.996 27.985 105.714 28.139 ;
     RECT  1.584 26.555 39.15 28.411 ;
     RECT  39.996 28.139 105.297 28.411 ;
     RECT  1.584 28.411 105.297 28.445 ;
     RECT  2.016 28.445 105.297 29.021 ;
     RECT  2.016 29.021 71.01 30.001 ;
     RECT  71.784 29.021 105.297 30.001 ;
     RECT  2.016 30.001 105.297 30.605 ;
     RECT  2.376 30.605 62.91 30.947 ;
     RECT  49.572 30.947 62.91 31.109 ;
     RECT  63.648 30.605 105.297 31.531 ;
     RECT  2.376 30.947 48.69 31.721 ;
     RECT  63.648 31.531 105.714 31.721 ;
     RECT  49.608 31.109 62.91 31.891 ;
     RECT  63.648 31.721 105.297 31.891 ;
     RECT  2.376 31.721 48.474 31.915 ;
     RECT  2.304 31.915 48.474 31.991 ;
     RECT  2.304 31.991 30.87 32.495 ;
     RECT  49.608 31.891 105.297 32.495 ;
     RECT  31.644 31.991 48.474 32.873 ;
     RECT  2.34 32.495 30.87 33.421 ;
     RECT  49.644 32.495 105.297 33.575 ;
     RECT  2.34 33.421 30.906 33.691 ;
     RECT  2.34 33.691 30.978 33.719 ;
     RECT  2.415 33.719 30.978 33.845 ;
     RECT  49.644 33.575 69.174 34.501 ;
     RECT  69.912 33.575 105.297 34.501 ;
     RECT  2.415 33.845 30.942 34.933 ;
     RECT  31.716 32.873 48.474 34.933 ;
     RECT  49.644 34.501 105.297 35.465 ;
     RECT  49.644 35.465 72.897 35.581 ;
     RECT  2.415 34.933 48.474 35.815 ;
     RECT  2.376 35.815 48.474 36.275 ;
     RECT  73.692 35.465 105.297 36.391 ;
     RECT  2.415 36.275 48.474 36.815 ;
     RECT  15.948 36.815 48.474 36.931 ;
     RECT  49.392 35.581 72.897 36.931 ;
     RECT  15.948 36.931 72.897 37.057 ;
     RECT  73.656 36.391 105.297 37.057 ;
     RECT  2.415 36.815 15.102 37.129 ;
     RECT  15.948 37.057 105.297 37.561 ;
     RECT  1.98 37.129 15.102 37.741 ;
     RECT  1.98 37.741 15.138 37.867 ;
     RECT  15.876 37.561 105.297 37.867 ;
     RECT  1.98 37.867 105.297 39.479 ;
     RECT  1.98 39.479 30.798 40.171 ;
     RECT  1.584 40.171 30.798 40.441 ;
     RECT  31.608 39.479 105.297 40.441 ;
     RECT  1.584 40.441 105.297 40.787 ;
     RECT  1.584 40.787 105.105 40.829 ;
     RECT  1.584 40.829 96.894 41.009 ;
     RECT  1.584 41.009 96.498 41.057 ;
     RECT  97.632 40.829 105.105 41.057 ;
     RECT  1.584 41.057 1.998 42.187 ;
     RECT  2.772 41.057 96.498 42.187 ;
     RECT  1.584 42.187 96.498 42.215 ;
     RECT  70.308 42.215 96.498 42.221 ;
     RECT  1.584 42.215 69.498 43.033 ;
     RECT  73.908 42.221 96.498 43.069 ;
     RECT  97.632 41.057 104.994 43.069 ;
     RECT  1.188 43.033 69.498 43.141 ;
     RECT  70.308 42.221 73.134 43.141 ;
     RECT  73.908 43.069 104.994 43.141 ;
     RECT  1.188 43.141 104.994 43.169 ;
     RECT  1.188 43.169 104.454 43.181 ;
     RECT  105.984 43.051 106.002 43.181 ;
     RECT  106.812 40.945 106.83 43.181 ;
    LAYER M4 ;
     RECT  1.381 0.096 1.969 0.12 ;
     RECT  1.765 31.92 2.149 31.944 ;
     RECT  2.149 31.92 2.365 31.992 ;
     RECT  1.765 36.96 2.365 36.984 ;
     RECT  2.365 11.232 2.408 11.256 ;
     RECT  2.365 23.376 2.408 23.4 ;
     RECT  2.293 24.48 2.408 25.704 ;
     RECT  2.365 31.2 2.408 32.808 ;
     RECT  2.365 36.096 2.408 36.984 ;
     RECT  2.141 40.992 2.408 41.016 ;
     RECT  2.408 2.148 2.512 41.052 ;
     RECT  1.381 42.144 2.581 42.168 ;
     RECT  2.512 2.418 2.704 41.016 ;
     RECT  2.704 6.816 2.819 9.192 ;
     RECT  1.969 0.096 2.833 0.216 ;
     RECT  2.704 4.896 2.873 5.736 ;
     RECT  2.581 42.144 2.873 43.08 ;
     RECT  2.819 7.968 2.963 9.192 ;
     RECT  2.873 42.144 2.965 42.168 ;
     RECT  2.704 16.56 3.089 18.744 ;
     RECT  2.965 42.096 3.089 42.168 ;
     RECT  2.704 10.32 3.155 11.976 ;
     RECT  2.704 25.248 3.161 25.752 ;
     RECT  3.089 16.56 3.203 18.264 ;
     RECT  3.089 42.144 3.233 42.168 ;
     RECT  2.704 28.512 3.341 37.08 ;
     RECT  2.963 8.976 3.377 9.096 ;
     RECT  3.341 34.128 3.449 37.08 ;
     RECT  2.704 38.784 3.491 39.72 ;
     RECT  3.341 28.512 3.557 33.048 ;
     RECT  2.704 21.264 3.697 24.12 ;
     RECT  2.704 26.928 3.697 27.336 ;
     RECT  3.377 9.072 3.737 9.096 ;
     RECT  3.697 21.168 3.845 24.12 ;
     RECT  2.833 0.096 3.877 0.312 ;
     RECT  3.697 26.928 3.913 27.432 ;
     RECT  3.557 28.512 3.913 31.32 ;
     RECT  2.704 3.84 4.069 3.864 ;
     RECT  2.819 6.816 4.093 6.84 ;
     RECT  2.963 7.968 4.093 7.992 ;
     RECT  4.069 3.744 4.156 3.864 ;
     RECT  2.873 5.712 4.165 5.736 ;
     RECT  3.845 23.328 4.165 24.12 ;
     RECT  3.161 25.728 4.165 25.752 ;
     RECT  3.877 0.048 4.201 0.312 ;
     RECT  2.704 14.832 4.201 14.856 ;
     RECT  4.165 23.328 4.211 25.752 ;
     RECT  3.155 11.952 4.237 11.976 ;
     RECT  4.211 23.376 4.345 25.752 ;
     RECT  3.913 26.928 4.345 31.32 ;
     RECT  3.557 32.352 4.345 33.048 ;
     RECT  3.449 34.128 4.345 35.496 ;
     RECT  4.165 5.52 4.381 5.736 ;
     RECT  4.093 6.816 4.381 7.992 ;
     RECT  4.093 20.112 4.417 20.136 ;
     RECT  3.203 16.56 4.457 16.824 ;
     RECT  4.201 14.784 4.489 14.856 ;
     RECT  4.381 5.52 4.525 7.992 ;
     RECT  3.155 10.32 4.561 10.92 ;
     RECT  4.237 11.952 4.561 12.216 ;
     RECT  4.345 23.376 4.565 31.32 ;
     RECT  4.525 4.944 4.601 7.992 ;
     RECT  4.565 24.096 4.601 31.32 ;
     RECT  4.561 10.32 4.633 12.216 ;
     RECT  4.489 14.64 4.633 14.856 ;
     RECT  4.417 20.016 4.633 20.136 ;
     RECT  4.165 43.056 4.643 43.08 ;
     RECT  4.457 16.8 4.645 16.824 ;
     RECT  4.309 9.312 4.673 9.336 ;
     RECT  4.633 10.32 4.673 12.552 ;
     RECT  3.491 38.784 4.7 38.808 ;
     RECT  4.601 7.152 4.705 7.992 ;
     RECT  4.645 16.8 4.705 17.16 ;
     RECT  3.203 18.144 4.705 18.264 ;
     RECT  4.633 19.392 4.705 20.136 ;
     RECT  4.705 16.8 4.741 20.136 ;
     RECT  3.845 21.168 4.741 22.152 ;
     RECT  4.601 4.944 4.777 6.168 ;
     RECT  4.777 4.896 4.781 6.168 ;
     RECT  4.7 38.16 4.787 38.808 ;
     RECT  4.201 0.048 4.817 0.552 ;
     RECT  3.449 37.056 4.849 37.08 ;
     RECT  4.705 7.152 4.925 8.712 ;
     RECT  4.601 24.48 4.933 31.32 ;
     RECT  4.345 32.352 4.933 35.496 ;
     RECT  4.849 36.912 4.979 37.752 ;
     RECT  4.979 36.912 4.981 37.656 ;
     RECT  4.633 14.256 4.988 14.856 ;
     RECT  4.933 24.48 5.033 35.496 ;
     RECT  5.033 28.512 5.065 35.496 ;
     RECT  4.981 36.528 5.065 37.656 ;
     RECT  4.988 14.256 5.075 15.72 ;
     RECT  5.075 14.256 5.101 14.856 ;
     RECT  4.925 7.44 5.141 8.712 ;
     RECT  5.033 24.48 5.141 27.336 ;
     RECT  4.673 12.096 5.173 12.552 ;
     RECT  5.101 13.584 5.173 14.856 ;
     RECT  5.141 7.44 5.219 7.8 ;
     RECT  5.141 25.728 5.249 27.336 ;
     RECT  4.741 16.8 5.321 22.152 ;
     RECT  5.065 28.512 5.357 37.656 ;
     RECT  4.817 0.048 5.411 0.504 ;
     RECT  5.324 42.192 5.411 42.216 ;
     RECT  4.156 3.84 5.413 3.864 ;
     RECT  4.781 4.896 5.413 4.968 ;
     RECT  5.173 12.096 5.429 14.856 ;
     RECT  5.249 25.728 5.429 26.952 ;
     RECT  5.413 3.84 5.5 4.968 ;
     RECT  5.321 18.096 5.501 22.152 ;
     RECT  4.787 38.784 5.501 38.808 ;
     RECT  5.501 21.168 5.533 22.152 ;
     RECT  5.501 18.096 5.537 20.088 ;
     RECT  4.673 10.32 5.641 11.016 ;
     RECT  5.429 12.096 5.641 12.552 ;
     RECT  5.321 16.8 5.645 16.824 ;
     RECT  5.5 3.84 5.677 3.96 ;
     RECT  5.641 10.32 5.681 12.552 ;
     RECT  5.429 13.584 5.681 14.856 ;
     RECT  5.533 21.168 5.713 22.776 ;
     RECT  5.357 28.512 5.753 36.936 ;
     RECT  5.713 9.216 5.821 9.24 ;
     RECT  5.681 10.32 5.821 11.256 ;
     RECT  5.5 4.944 5.929 4.968 ;
     RECT  4.781 6.144 5.929 6.168 ;
     RECT  5.681 13.584 6.005 13.704 ;
     RECT  5.713 21.168 6.037 23.064 ;
     RECT  5.141 24.48 6.073 24.504 ;
     RECT  2.704 40.992 6.149 41.016 ;
     RECT  5.219 7.44 6.217 7.464 ;
     RECT  5.537 18.816 6.221 20.088 ;
     RECT  6.037 21.168 6.221 23.112 ;
     RECT  5.753 28.512 6.221 35.88 ;
     RECT  6.109 39.36 6.361 39.384 ;
     RECT  6.221 28.512 6.433 31.32 ;
     RECT  5.677 3.696 6.469 3.96 ;
     RECT  5.929 4.944 6.469 6.168 ;
     RECT  6.217 7.44 6.505 8.232 ;
     RECT  5.821 9.216 6.505 11.256 ;
     RECT  6.397 16.128 6.509 16.152 ;
     RECT  5.429 25.728 6.509 26.712 ;
     RECT  6.433 28.32 6.509 31.32 ;
     RECT  5.753 36.912 6.565 36.936 ;
     RECT  6.221 21.168 6.577 21.96 ;
     RECT  6.509 28.32 6.617 28.488 ;
     RECT  5.681 14.736 6.689 14.856 ;
     RECT  5.411 0.048 6.721 0.216 ;
     RECT  6.221 23.04 6.757 23.112 ;
     RECT  6.073 24.144 6.757 24.504 ;
     RECT  6.541 17.184 6.793 17.208 ;
     RECT  6.221 18.912 6.793 20.088 ;
     RECT  6.577 21.12 6.793 21.96 ;
     RECT  6.505 7.344 6.803 11.256 ;
     RECT  6.565 36.912 6.829 37.032 ;
     RECT  6.229 38.016 6.829 38.04 ;
     RECT  6.469 3.696 6.853 6.168 ;
     RECT  6.803 7.344 6.853 7.368 ;
     RECT  6.221 32.736 6.853 35.88 ;
     RECT  6.829 36.912 6.853 38.04 ;
     RECT  6.509 25.92 6.901 26.712 ;
     RECT  6.853 32.736 6.997 38.04 ;
     RECT  6.361 39.36 6.997 39.48 ;
     RECT  6.005 13.584 7.009 13.608 ;
     RECT  6.181 43.056 7.013 43.08 ;
     RECT  6.853 3.696 7.117 7.368 ;
     RECT  6.793 17.184 7.189 17.544 ;
     RECT  7.189 17.04 7.237 17.544 ;
     RECT  6.793 18.912 7.237 21.96 ;
     RECT  6.757 23.04 7.333 24.504 ;
     RECT  5.681 12.528 7.369 12.552 ;
     RECT  6.901 25.92 7.369 27.096 ;
     RECT  6.803 8.496 7.388 11.256 ;
     RECT  7.369 12.24 7.388 12.552 ;
     RECT  6.689 14.784 7.429 14.856 ;
     RECT  6.757 16.032 7.429 16.056 ;
     RECT  7.429 14.784 7.477 16.056 ;
     RECT  7.237 17.04 7.477 21.96 ;
     RECT  6.509 29.568 7.505 31.32 ;
     RECT  7.477 14.784 7.513 21.96 ;
     RECT  7.505 29.568 7.573 31.368 ;
     RECT  6.997 32.736 7.573 39.48 ;
     RECT  7.388 8.496 7.669 12.552 ;
     RECT  7.009 13.536 7.669 13.608 ;
     RECT  7.117 3.408 7.765 7.368 ;
     RECT  7.669 8.496 7.765 13.608 ;
     RECT  7.765 3.408 7.808 13.608 ;
     RECT  7.513 14.784 7.808 22.008 ;
     RECT  7.333 23.04 7.808 24.648 ;
     RECT  7.369 25.92 7.808 27.336 ;
     RECT  6.617 28.368 7.808 28.488 ;
     RECT  7.573 29.568 7.808 39.48 ;
     RECT  6.829 40.56 7.808 40.584 ;
     RECT  7.808 2.148 7.912 41.052 ;
     RECT  7.912 2.148 8.104 40.782 ;
     RECT  8.104 5.376 8.309 10.104 ;
     RECT  8.104 16.272 8.339 33.96 ;
     RECT  8.309 5.52 8.345 10.104 ;
     RECT  8.104 11.136 8.345 11.256 ;
     RECT  8.339 16.272 8.381 25.176 ;
     RECT  8.339 26.448 8.435 33.96 ;
     RECT  8.104 35.472 8.453 35.832 ;
     RECT  8.435 26.448 8.524 30.216 ;
     RECT  8.524 26.592 8.525 30.216 ;
     RECT  6.721 0.048 8.549 1.128 ;
     RECT  7.081 42.192 8.581 42.216 ;
     RECT  8.549 0.048 8.633 1.752 ;
     RECT  8.581 42.192 8.669 43.08 ;
     RECT  8.345 5.568 8.705 10.104 ;
     RECT  8.525 28.944 8.705 30.216 ;
     RECT  8.633 0.048 8.777 1.128 ;
     RECT  8.381 18.96 8.849 25.176 ;
     RECT  8.849 20.16 9.029 25.176 ;
     RECT  8.777 0.528 9.059 1.128 ;
     RECT  8.705 7.344 9.059 10.104 ;
     RECT  9.059 9.072 9.097 10.104 ;
     RECT  8.705 5.568 9.137 5.976 ;
     RECT  8.525 26.592 9.137 27.912 ;
     RECT  9.059 7.344 9.173 7.416 ;
     RECT  9.029 20.16 9.209 25.08 ;
     RECT  8.104 37.584 9.245 39.528 ;
     RECT  8.435 31.296 9.277 33.96 ;
     RECT  8.453 35.472 9.277 35.592 ;
     RECT  8.104 12.528 9.281 15 ;
     RECT  9.277 31.296 9.281 35.592 ;
     RECT  9.308 39.888 9.349 39.912 ;
     RECT  9.349 39.888 9.395 40.872 ;
     RECT  9.281 31.296 9.425 35.496 ;
     RECT  9.059 0.528 9.443 0.6 ;
     RECT  8.104 3.84 9.601 3.864 ;
     RECT  8.381 16.272 9.637 17.16 ;
     RECT  9.637 16.272 9.673 17.544 ;
     RECT  8.705 30.192 9.749 30.216 ;
     RECT  9.425 31.296 9.749 34.008 ;
     RECT  9.245 37.584 9.749 38.808 ;
     RECT  9.673 16.272 9.757 17.64 ;
     RECT  9.281 12.528 9.785 14.904 ;
     RECT  8.104 2.832 9.817 2.856 ;
     RECT  9.601 3.84 9.817 4.44 ;
     RECT  9.097 9.072 9.817 10.152 ;
     RECT  8.345 11.136 9.817 11.16 ;
     RECT  9.209 20.16 9.821 24.648 ;
     RECT  8.669 42.192 9.827 42.216 ;
     RECT  9.443 0.576 9.865 0.6 ;
     RECT  9.137 27.168 9.925 27.912 ;
     RECT  8.705 28.944 9.925 28.968 ;
     RECT  9.757 16.272 10.019 17.064 ;
     RECT  9.925 27.168 10.033 28.968 ;
     RECT  9.785 13.056 10.037 14.904 ;
     RECT  10.037 14.784 10.06 14.904 ;
     RECT  9.817 9.072 10.141 11.16 ;
     RECT  8.849 18.96 10.177 18.984 ;
     RECT  9.821 20.16 10.177 23.592 ;
     RECT  9.925 30.912 10.181 30.936 ;
     RECT  9.173 7.344 10.249 7.368 ;
     RECT  10.141 8.832 10.249 11.16 ;
     RECT  10.033 27.168 10.259 29.736 ;
     RECT  10.177 1.728 10.261 1.752 ;
     RECT  9.749 31.92 10.289 34.008 ;
     RECT  9.749 37.872 10.321 38.808 ;
     RECT  9.137 5.952 10.393 5.976 ;
     RECT  10.249 7.344 10.393 11.16 ;
     RECT  10.177 18.96 10.397 23.592 ;
     RECT  9.817 2.832 10.501 4.44 ;
     RECT  10.321 37.872 10.541 39.24 ;
     RECT  9.821 24.624 10.547 24.648 ;
     RECT  10.501 2.256 10.609 4.44 ;
     RECT  9.425 35.472 10.609 35.496 ;
     RECT  10.609 2.256 10.643 4.536 ;
     RECT  10.259 27.168 10.789 29.208 ;
     RECT  10.609 35.472 10.789 36.456 ;
     RECT  10.541 37.872 10.789 38.088 ;
     RECT  10.289 31.92 10.793 33.816 ;
     RECT  10.213 42.144 10.793 42.168 ;
     RECT  10.643 2.832 10.821 4.536 ;
     RECT  10.789 26.784 10.829 29.208 ;
     RECT  10.789 35.472 10.835 38.088 ;
     RECT  10.393 5.952 10.885 11.16 ;
     RECT  10.037 13.056 10.885 13.08 ;
     RECT  10.793 31.92 10.937 33.384 ;
     RECT  10.397 20.112 10.973 23.592 ;
     RECT  10.019 17.04 11.005 17.064 ;
     RECT  10.885 5.952 11.009 13.08 ;
     RECT  10.829 27.888 11.045 29.208 ;
     RECT  10.937 31.92 11.153 33.048 ;
     RECT  10.973 21.648 11.171 23.592 ;
     RECT  11.153 33.024 11.261 33.048 ;
     RECT  10.821 3.072 11.293 4.536 ;
     RECT  11.005 17.04 11.297 17.64 ;
     RECT  10.609 16.032 11.401 16.056 ;
     RECT  10.06 14.784 11.405 14.808 ;
     RECT  10.861 0.576 11.485 0.6 ;
     RECT  11.171 23.136 11.549 23.592 ;
     RECT  10.541 39.216 11.549 39.24 ;
     RECT  11.045 28.704 11.581 29.208 ;
     RECT  11.437 25.056 11.653 25.08 ;
     RECT  10.981 43.056 11.657 43.08 ;
     RECT  11.297 17.616 11.66 17.64 ;
     RECT  10.397 18.96 11.66 18.984 ;
     RECT  11.66 17.616 11.689 18.984 ;
     RECT  10.973 20.112 11.689 20.136 ;
     RECT  11.653 25.056 11.699 25.32 ;
     RECT  10.829 26.784 11.699 26.808 ;
     RECT  11.699 25.296 11.797 25.32 ;
     RECT  11.401 16.032 11.873 16.104 ;
     RECT  11.581 28.704 11.893 29.688 ;
     RECT  11.893 28.704 11.98 30.6 ;
     RECT  11.797 42.144 11.981 42.168 ;
     RECT  10.835 37.008 12.013 38.088 ;
     RECT  11.689 17.616 12.049 20.136 ;
     RECT  11.171 21.648 12.049 22.008 ;
     RECT  11.293 3.072 12.089 4.68 ;
     RECT  9.395 40.848 12.229 40.872 ;
     RECT  12.013 37.008 12.409 38.808 ;
     RECT  11.009 5.952 12.469 6.696 ;
     RECT  11.009 8.304 12.469 13.08 ;
     RECT  12.049 17.616 12.481 22.008 ;
     RECT  10.835 35.472 12.481 35.496 ;
     RECT  12.481 17.52 12.517 22.008 ;
     RECT  12.517 17.52 12.553 22.056 ;
     RECT  11.98 28.704 12.553 30.36 ;
     RECT  12.229 40.848 12.581 41.016 ;
     RECT  12.089 3.312 12.661 4.68 ;
     RECT  11.473 14.736 12.661 14.76 ;
     RECT  12.553 17.472 12.661 22.056 ;
     RECT  11.549 23.568 12.661 23.592 ;
     RECT  12.221 1.728 12.737 1.752 ;
     RECT  12.661 3.312 12.769 4.968 ;
     RECT  12.469 5.952 12.769 13.08 ;
     RECT  12.769 3.312 12.853 13.08 ;
     RECT  11.873 16.032 12.877 16.056 ;
     RECT  12.661 17.424 12.877 23.592 ;
     RECT  11.797 0.144 12.901 0.168 ;
     RECT  11.797 25.296 12.901 25.56 ;
     RECT  12.589 34.128 12.908 34.152 ;
     RECT  12.877 16.032 12.913 23.592 ;
     RECT  12.901 25.104 12.913 25.56 ;
     RECT  12.901 0.144 12.949 0.552 ;
     RECT  12.913 16.032 12.949 25.56 ;
     RECT  12.553 27.552 13.021 30.36 ;
     RECT  12.949 0.144 13.036 0.648 ;
     RECT  13.021 27.312 13.057 30.36 ;
     RECT  12.581 40.848 13.069 41.592 ;
     RECT  13.057 27.312 13.093 30.696 ;
     RECT  12.908 33.456 13.093 34.152 ;
     RECT  12.481 35.328 13.093 35.496 ;
     RECT  12.661 14.736 13.165 14.808 ;
     RECT  13.093 33.456 13.165 35.496 ;
     RECT  13.093 27.312 13.201 30.888 ;
     RECT  12.853 3.312 13.208 13.32 ;
     RECT  13.165 14.688 13.208 14.808 ;
     RECT  12.949 16.032 13.208 25.8 ;
     RECT  13.201 26.832 13.208 30.888 ;
     RECT  11.221 31.872 13.208 31.896 ;
     RECT  13.165 33.024 13.208 35.496 ;
     RECT  12.409 36.816 13.208 38.808 ;
     RECT  13.069 40.848 13.208 41.052 ;
     RECT  13.208 2.148 13.312 41.052 ;
     RECT  13.036 0.144 13.429 0.552 ;
     RECT  13.312 2.418 13.504 40.782 ;
     RECT  13.504 2.784 13.601 9.336 ;
     RECT  13.504 18.72 13.619 33.048 ;
     RECT  13.504 10.368 13.645 13.656 ;
     RECT  13.601 8.592 13.673 9.336 ;
     RECT  13.619 18.72 13.709 32.424 ;
     RECT  13.504 36.432 13.709 36.84 ;
     RECT  13.709 18.72 13.745 32.328 ;
     RECT  13.601 2.784 13.781 7.512 ;
     RECT  13.645 10.368 13.811 13.56 ;
     RECT  13.745 19.248 13.811 32.328 ;
     RECT  13.781 2.784 13.817 6.696 ;
     RECT  13.811 19.248 13.817 20.472 ;
     RECT  13.811 21.648 13.961 32.328 ;
     RECT  13.429 0.096 14.069 0.552 ;
     RECT  13.817 2.784 14.105 6.408 ;
     RECT  13.961 21.648 14.177 31.944 ;
     RECT  13.429 43.056 14.197 43.08 ;
     RECT  14.177 21.648 14.249 24.072 ;
     RECT  14.249 21.888 14.357 24.072 ;
     RECT  14.177 25.056 14.357 31.944 ;
     RECT  13.709 36.816 14.357 36.84 ;
     RECT  13.673 9.024 14.501 9.336 ;
     RECT  14.197 43.008 14.501 43.08 ;
     RECT  13.504 16.032 14.537 17.688 ;
     RECT  14.105 2.784 14.645 3.384 ;
     RECT  13.811 10.368 14.681 12.792 ;
     RECT  14.357 25.056 14.825 27.768 ;
     RECT  14.681 12 14.857 12.792 ;
     RECT  14.681 10.368 14.861 11.016 ;
     RECT  13.504 35.136 14.893 35.16 ;
     RECT  14.105 4.368 14.933 6.408 ;
     RECT  14.893 35.136 14.933 35.352 ;
     RECT  14.857 12 14.969 13.08 ;
     RECT  14.357 28.848 15.037 31.944 ;
     RECT  14.825 25.056 15.077 25.848 ;
     RECT  14.501 9.216 15.113 9.336 ;
     RECT  14.861 10.368 15.113 10.392 ;
     RECT  15.077 25.056 15.113 25.56 ;
     RECT  15.037 28.848 15.113 32.52 ;
     RECT  14.645 3.12 15.149 3.384 ;
     RECT  13.817 19.968 15.289 20.472 ;
     RECT  14.933 4.512 15.293 6.408 ;
     RECT  14.825 27.072 15.361 27.768 ;
     RECT  15.149 3.12 15.437 3.144 ;
     RECT  15.113 29.616 15.437 32.52 ;
     RECT  15.289 19.968 15.445 20.712 ;
     RECT  14.357 21.888 15.445 23.928 ;
     RECT  15.293 4.944 15.473 6.408 ;
     RECT  15.361 27.072 15.473 28.536 ;
     RECT  14.969 12 15.509 12.792 ;
     RECT  13.504 14.688 15.509 14.712 ;
     RECT  15.445 19.968 15.649 23.928 ;
     RECT  15.473 27.072 15.653 27.336 ;
     RECT  15.649 19.056 15.685 23.928 ;
     RECT  15.113 25.056 15.685 25.464 ;
     RECT  14.677 7.872 15.793 7.896 ;
     RECT  14.069 0.096 15.829 0.12 ;
     RECT  15.793 7.872 15.833 8.184 ;
     RECT  15.793 2.784 15.865 2.808 ;
     RECT  15.865 2.688 15.905 2.808 ;
     RECT  15.821 40.992 15.905 41.016 ;
     RECT  13.504 37.872 15.937 38.808 ;
     RECT  14.501 43.056 15.937 43.08 ;
     RECT  15.437 29.616 15.941 32.424 ;
     RECT  14.537 16.032 15.973 17.592 ;
     RECT  14.933 35.328 15.973 35.352 ;
     RECT  15.349 36.864 15.973 36.888 ;
     RECT  15.973 15.84 16.019 17.592 ;
     RECT  15.973 35.328 16.019 36.888 ;
     RECT  15.829 0.096 16.081 0.168 ;
     RECT  15.941 29.664 16.121 32.424 ;
     RECT  15.509 12.768 16.153 12.792 ;
     RECT  16.009 13.824 16.153 13.848 ;
     RECT  16.019 15.84 16.193 16.392 ;
     RECT  15.473 4.944 16.229 6.312 ;
     RECT  16.019 35.904 16.297 36.888 ;
     RECT  15.937 37.872 16.297 38.952 ;
     RECT  16.019 17.472 16.369 17.592 ;
     RECT  15.685 19.056 16.369 25.464 ;
     RECT  16.193 15.84 16.549 16.056 ;
     RECT  16.369 17.472 16.553 25.464 ;
     RECT  16.553 18.816 16.589 25.464 ;
     RECT  16.297 35.904 16.625 38.952 ;
     RECT  16.597 3.936 16.684 3.96 ;
     RECT  15.937 43.008 16.691 43.08 ;
     RECT  16.081 0.096 16.705 0.552 ;
     RECT  16.589 23.52 16.805 25.464 ;
     RECT  16.121 30.144 16.805 32.424 ;
     RECT  16.229 4.944 16.837 4.968 ;
     RECT  16.837 4.08 16.877 4.968 ;
     RECT  16.153 12.768 16.945 13.848 ;
     RECT  15.833 8.16 16.981 8.184 ;
     RECT  15.113 9.216 16.981 9.24 ;
     RECT  16.805 23.808 16.981 25.464 ;
     RECT  15.653 27.12 16.981 27.336 ;
     RECT  15.473 28.416 16.981 28.536 ;
     RECT  16.981 23.808 16.985 28.536 ;
     RECT  16.945 12.576 17.017 13.848 ;
     RECT  17.017 12.336 17.056 13.848 ;
     RECT  16.985 25.2 17.077 28.536 ;
     RECT  16.549 15.408 17.089 16.056 ;
     RECT  15.973 11.28 17.129 11.304 ;
     RECT  16.805 30.144 17.201 31.752 ;
     RECT  17.077 25.2 17.305 29.112 ;
     RECT  17.201 30.144 17.305 30.36 ;
     RECT  17.056 12.336 17.345 13.896 ;
     RECT  16.625 35.904 17.381 37.608 ;
     RECT  16.229 6.288 17.485 6.312 ;
     RECT  16.981 8.16 17.485 9.24 ;
     RECT  17.413 10.272 17.485 10.296 ;
     RECT  16.691 43.056 17.489 43.08 ;
     RECT  17.017 40.992 17.497 41.016 ;
     RECT  17.485 6.288 17.525 6.792 ;
     RECT  17.381 35.904 17.629 36.888 ;
     RECT  17.485 8.16 17.665 10.296 ;
     RECT  17.413 39.504 17.737 39.528 ;
     RECT  15.905 2.688 17.797 2.712 ;
     RECT  16.877 4.08 17.797 4.104 ;
     RECT  17.201 31.632 17.809 31.752 ;
     RECT  16.705 0.144 17.891 0.552 ;
     RECT  17.665 42.192 17.891 42.216 ;
     RECT  17.665 7.92 17.989 10.296 ;
     RECT  17.089 14.928 17.989 16.056 ;
     RECT  17.629 35.328 17.996 36.888 ;
     RECT  17.053 17.424 18.097 17.448 ;
     RECT  17.989 14.928 18.133 16.392 ;
     RECT  18.097 17.424 18.133 17.688 ;
     RECT  16.985 23.808 18.133 24.216 ;
     RECT  17.305 25.2 18.133 30.36 ;
     RECT  18.025 33.6 18.169 33.624 ;
     RECT  17.989 7.92 18.181 10.68 ;
     RECT  17.345 12.336 18.181 13.512 ;
     RECT  17.737 39.504 18.197 39.816 ;
     RECT  17.891 0.144 18.229 0.168 ;
     RECT  18.169 33.12 18.241 33.624 ;
     RECT  18.241 33.072 18.313 33.624 ;
     RECT  18.133 14.928 18.421 17.688 ;
     RECT  16.589 18.816 18.421 22.056 ;
     RECT  18.197 39.504 18.469 40.44 ;
     RECT  17.797 2.688 18.608 4.104 ;
     RECT  18.373 5.136 18.608 5.16 ;
     RECT  17.525 6.768 18.608 6.792 ;
     RECT  18.181 7.92 18.608 13.512 ;
     RECT  18.421 14.928 18.608 22.056 ;
     RECT  18.133 23.664 18.608 30.36 ;
     RECT  17.809 31.632 18.608 31.8 ;
     RECT  18.313 32.928 18.608 33.624 ;
     RECT  17.996 34.752 18.608 36.888 ;
     RECT  18.469 39.504 18.608 40.584 ;
     RECT  18.608 2.148 18.712 41.052 ;
     RECT  18.712 2.418 18.904 40.782 ;
     RECT  18.904 9.072 18.965 34.68 ;
     RECT  18.965 9.072 19.109 16.632 ;
     RECT  18.965 17.616 19.181 34.68 ;
     RECT  19.181 23.328 19.427 34.68 ;
     RECT  18.469 43.056 19.429 43.08 ;
     RECT  19.181 17.616 19.433 22.2 ;
     RECT  19.427 23.328 19.433 30.36 ;
     RECT  19.429 42.144 19.433 43.08 ;
     RECT  18.229 0.096 19.469 0.168 ;
     RECT  18.904 7.92 19.477 7.992 ;
     RECT  19.109 9.072 19.505 16.584 ;
     RECT  19.433 17.616 19.541 18.024 ;
     RECT  19.433 23.328 19.619 29.256 ;
     RECT  19.619 24.576 19.649 29.256 ;
     RECT  19.649 24.576 19.721 25.032 ;
     RECT  18.904 38.784 19.853 40.782 ;
     RECT  18.904 35.808 19.909 36.936 ;
     RECT  19.909 35.664 19.955 36.936 ;
     RECT  19.853 38.784 19.973 41.016 ;
     RECT  19.721 24.576 20.009 24.648 ;
     RECT  19.649 26.112 20.009 29.256 ;
     RECT  19.955 35.664 20.009 35.688 ;
     RECT  19.433 19.248 20.045 22.2 ;
     RECT  20.005 5.088 20.077 5.112 ;
     RECT  19.433 30.336 20.153 30.36 ;
     RECT  18.904 2.592 20.189 3.96 ;
     RECT  20.077 4.944 20.257 5.112 ;
     RECT  18.904 6.24 20.257 6.936 ;
     RECT  20.189 2.592 20.261 3.432 ;
     RECT  20.045 19.728 20.261 22.2 ;
     RECT  19.427 31.632 20.293 34.68 ;
     RECT  19.433 42.144 20.297 42.168 ;
     RECT  20.257 4.944 20.333 6.936 ;
     RECT  20.293 31.632 20.437 35.4 ;
     RECT  20.333 5.328 20.477 6.936 ;
     RECT  19.973 40.8 20.483 41.016 ;
     RECT  19.505 9.12 20.545 16.584 ;
     RECT  20.477 5.472 20.549 6.936 ;
     RECT  19.541 18 20.581 18.024 ;
     RECT  19.973 38.784 20.581 39.816 ;
     RECT  19.469 0.096 20.629 0.12 ;
     RECT  20.629 0.096 20.657 0.216 ;
     RECT  20.261 19.728 20.657 22.152 ;
     RECT  20.437 31.344 20.689 35.4 ;
     RECT  20.009 26.112 20.693 29.064 ;
     RECT  20.581 38.64 20.693 39.816 ;
     RECT  20.693 26.112 20.729 28.536 ;
     RECT  19.955 36.768 20.761 36.936 ;
     RECT  20.545 9.12 20.773 17.016 ;
     RECT  20.581 18 20.773 18.504 ;
     RECT  20.693 38.64 20.801 38.952 ;
     RECT  20.657 19.728 20.837 20.232 ;
     RECT  19.619 23.328 20.837 23.352 ;
     RECT  20.689 30.816 20.837 35.4 ;
     RECT  20.773 9.12 20.873 18.504 ;
     RECT  20.801 38.64 20.963 38.664 ;
     RECT  20.837 30.816 20.981 35.016 ;
     RECT  19.477 7.92 21.013 7.944 ;
     RECT  20.873 9.12 21.013 16.056 ;
     RECT  20.965 38.4 21.052 38.424 ;
     RECT  20.729 26.112 21.053 27.336 ;
     RECT  20.549 6.816 21.085 6.936 ;
     RECT  21.013 7.92 21.085 16.056 ;
     RECT  20.657 21.552 21.089 22.152 ;
     RECT  20.981 30.816 21.125 32.232 ;
     RECT  20.483 40.992 21.133 41.016 ;
     RECT  20.009 24.576 21.229 24.6 ;
     RECT  20.873 17.088 21.233 18.504 ;
     RECT  21.125 30.816 21.233 32.136 ;
     RECT  20.761 36.768 21.301 37.08 ;
     RECT  20.657 0.144 21.337 0.216 ;
     RECT  21.085 6.816 21.36 16.056 ;
     RECT  20.261 2.928 21.409 3.432 ;
     RECT  21.337 0.144 21.485 1.176 ;
     RECT  21.409 2.928 21.553 4.008 ;
     RECT  21.229 24.576 21.637 24.936 ;
     RECT  21.233 30.816 21.637 32.04 ;
     RECT  21.553 2.544 21.665 4.008 ;
     RECT  20.729 28.32 21.665 28.536 ;
     RECT  21.665 28.32 21.683 28.344 ;
     RECT  20.837 19.92 21.697 20.232 ;
     RECT  21.089 21.552 21.697 22.056 ;
     RECT  21.301 36.48 21.697 37.08 ;
     RECT  20.549 5.472 21.733 5.496 ;
     RECT  21.36 6.816 21.733 13.128 ;
     RECT  21.233 17.184 21.737 18.504 ;
     RECT  21.665 3.408 21.805 4.008 ;
     RECT  21.733 5.472 21.805 13.128 ;
     RECT  21.485 0.144 21.877 0.552 ;
     RECT  21.445 43.056 21.877 43.08 ;
     RECT  21.805 3.408 21.881 13.128 ;
     RECT  21.697 19.92 21.913 22.056 ;
     RECT  21.829 2.256 21.916 2.28 ;
     RECT  20.981 33.264 21.949 35.016 ;
     RECT  21.697 36.048 21.949 37.08 ;
     RECT  21.913 19.632 21.953 22.056 ;
     RECT  21.881 3.984 21.989 13.128 ;
     RECT  21.877 42.144 22.025 43.08 ;
     RECT  21.989 3.984 22.061 7.704 ;
     RECT  21.053 26.784 22.061 27.336 ;
     RECT  21.637 30.768 22.093 32.04 ;
     RECT  21.637 24.576 22.201 25.08 ;
     RECT  22.093 30.192 22.211 32.04 ;
     RECT  22.211 30.768 22.261 32.04 ;
     RECT  21.949 33.264 22.261 37.08 ;
     RECT  21.877 0.096 22.385 0.552 ;
     RECT  21.953 21.12 22.412 22.056 ;
     RECT  22.261 30.768 22.489 37.08 ;
     RECT  22.412 21.12 22.499 22.44 ;
     RECT  22.201 24.192 22.561 25.08 ;
     RECT  22.561 24.192 22.637 25.848 ;
     RECT  22.061 27.072 22.645 27.336 ;
     RECT  21.953 19.632 22.669 19.896 ;
     RECT  22.385 0.096 22.813 0.264 ;
     RECT  22.637 24.576 22.853 25.848 ;
     RECT  22.489 30.768 22.853 37.704 ;
     RECT  21.989 8.736 22.921 13.128 ;
     RECT  21.36 14.256 22.921 16.056 ;
     RECT  21.737 17.184 22.921 18.408 ;
     RECT  22.669 19.584 22.921 19.896 ;
     RECT  22.499 21.12 22.957 22.104 ;
     RECT  22.921 8.736 22.961 16.056 ;
     RECT  22.853 30.768 22.961 36.648 ;
     RECT  22.853 24.624 23.029 25.848 ;
     RECT  22.645 27.072 23.029 27.624 ;
     RECT  22.921 17.184 23.077 19.896 ;
     RECT  22.957 21.072 23.077 22.104 ;
     RECT  22.061 3.984 23.317 7.272 ;
     RECT  22.961 8.736 23.317 14.568 ;
     RECT  23.029 24.624 23.425 27.624 ;
     RECT  22.025 43.056 23.461 43.08 ;
     RECT  22.645 1.728 23.569 1.752 ;
     RECT  23.557 2.784 23.569 2.808 ;
     RECT  23.077 17.136 23.641 22.104 ;
     RECT  22.813 0.048 23.749 0.264 ;
     RECT  23.641 17.136 23.929 22.824 ;
     RECT  23.317 3.984 23.965 14.568 ;
     RECT  22.961 15.936 23.965 16.056 ;
     RECT  23.569 1.728 24.008 2.808 ;
     RECT  23.965 3.984 24.008 16.056 ;
     RECT  23.929 17.136 24.008 23.16 ;
     RECT  23.425 24.624 24.008 28.44 ;
     RECT  23.929 30.384 24.008 30.408 ;
     RECT  22.961 31.632 24.008 36.648 ;
     RECT  22.853 37.68 24.008 37.704 ;
     RECT  23.893 38.784 24.008 38.808 ;
     RECT  21.877 39.792 24.008 39.816 ;
     RECT  24.008 1.728 24.112 41.052 ;
     RECT  24.112 1.728 24.304 41.016 ;
     RECT  23.461 42.144 24.365 43.08 ;
     RECT  24.304 8.496 24.401 12.072 ;
     RECT  24.304 28.896 24.419 39.096 ;
     RECT  24.304 4.128 24.437 4.44 ;
     RECT  24.401 9.552 24.509 12.072 ;
     RECT  24.304 3.024 24.545 3.048 ;
     RECT  24.419 28.896 24.653 37.32 ;
     RECT  24.509 9.648 24.761 12.072 ;
     RECT  24.653 28.896 24.892 30.84 ;
     RECT  24.304 17.04 24.905 27.912 ;
     RECT  24.905 17.04 24.941 20.184 ;
     RECT  24.941 18 24.977 20.184 ;
     RECT  24.892 29.52 24.995 30.84 ;
     RECT  24.304 1.728 25.049 1.752 ;
     RECT  24.653 31.92 25.049 37.32 ;
     RECT  24.304 40.272 25.129 41.016 ;
     RECT  23.749 0.048 25.189 0.456 ;
     RECT  24.304 14.784 25.265 16.056 ;
     RECT  25.265 14.784 25.297 15.48 ;
     RECT  25.049 33.552 25.337 37.32 ;
     RECT  24.304 5.712 25.373 7.368 ;
     RECT  24.437 4.32 25.405 4.44 ;
     RECT  24.419 38.784 25.405 39.096 ;
     RECT  24.365 43.056 25.477 43.08 ;
     RECT  24.995 29.856 25.481 30.84 ;
     RECT  25.405 3.936 25.58 4.44 ;
     RECT  25.189 0.048 25.697 0.552 ;
     RECT  24.977 18 25.769 19.944 ;
     RECT  25.373 6.288 25.801 7.368 ;
     RECT  24.401 8.496 25.801 8.52 ;
     RECT  25.477 43.008 25.801 43.08 ;
     RECT  25.405 38.208 25.841 39.096 ;
     RECT  25.129 40.272 25.873 40.296 ;
     RECT  25.297 14.736 25.981 15.48 ;
     RECT  25.981 14.352 26.053 15.48 ;
     RECT  24.905 21.408 26.053 27.912 ;
     RECT  26.053 21.408 26.125 28.872 ;
     RECT  25.481 29.856 26.125 30.456 ;
     RECT  25.337 33.552 26.161 37.032 ;
     RECT  25.801 6.288 26.165 8.52 ;
     RECT  26.125 21.408 26.237 30.456 ;
     RECT  25.769 18.768 26.243 19.944 ;
     RECT  25.049 31.92 26.269 31.944 ;
     RECT  26.161 32.928 26.269 37.032 ;
     RECT  26.053 14.304 26.273 15.48 ;
     RECT  26.237 25.776 26.309 30.456 ;
     RECT  25.801 42.192 26.339 43.08 ;
     RECT  25.58 3.936 26.341 4.92 ;
     RECT  26.309 25.824 26.629 30.456 ;
     RECT  26.269 31.872 26.629 37.032 ;
     RECT  25.697 0.144 26.677 0.552 ;
     RECT  24.761 9.648 26.741 11.976 ;
     RECT  26.237 21.408 26.741 24.696 ;
     RECT  26.629 25.824 26.741 37.032 ;
     RECT  26.741 32.928 26.779 37.032 ;
     RECT  26.273 14.352 26.809 15.48 ;
     RECT  26.779 32.976 26.819 37.032 ;
     RECT  25.873 39.984 26.849 40.296 ;
     RECT  26.78 2.64 26.867 2.664 ;
     RECT  26.809 14.352 26.893 16.008 ;
     RECT  26.849 40.272 26.921 40.296 ;
     RECT  26.677 0.096 27.029 0.552 ;
     RECT  26.819 34.224 27.029 37.032 ;
     RECT  26.741 23.952 27.101 24.696 ;
     RECT  26.341 3.936 27.133 5.208 ;
     RECT  27.133 3.936 27.205 5.256 ;
     RECT  26.165 6.288 27.205 7.656 ;
     RECT  27.205 3.936 27.349 7.656 ;
     RECT  26.741 10.992 27.349 11.976 ;
     RECT  24.304 13.056 27.349 13.08 ;
     RECT  26.819 32.976 27.353 33 ;
     RECT  27.029 35.952 27.353 37.032 ;
     RECT  26.377 38.16 27.353 38.184 ;
     RECT  26.243 18.768 27.389 19.656 ;
     RECT  26.741 25.824 27.389 31.944 ;
     RECT  27.349 10.992 27.395 13.08 ;
     RECT  27.349 3.936 27.425 8.424 ;
     RECT  27.389 25.824 27.425 27.096 ;
     RECT  27.425 8.4 27.445 8.424 ;
     RECT  26.741 9.648 27.445 9.72 ;
     RECT  27.389 19.536 27.457 19.656 ;
     RECT  27.425 3.936 27.491 7.416 ;
     RECT  27.491 3.936 27.493 6.696 ;
     RECT  27.493 3.408 27.605 6.696 ;
     RECT  27.445 8.4 27.635 9.72 ;
     RECT  26.893 14.352 27.635 15.48 ;
     RECT  27.389 28.416 27.713 31.944 ;
     RECT  27.395 10.992 27.724 13.032 ;
     RECT  27.635 14.352 27.857 15.336 ;
     RECT  27.605 3.792 27.923 6.696 ;
     RECT  27.923 3.792 27.929 5.208 ;
     RECT  27.923 6.672 27.929 6.696 ;
     RECT  27.713 28.416 27.929 31.368 ;
     RECT  27.857 14.352 27.965 14.376 ;
     RECT  27.457 19.536 27.997 19.848 ;
     RECT  26.339 43.008 28.001 43.08 ;
     RECT  27.877 37.584 28.037 37.656 ;
     RECT  26.741 21.408 28.069 22.776 ;
     RECT  27.029 34.224 28.069 34.92 ;
     RECT  27.929 3.936 28.073 5.208 ;
     RECT  28.069 21.408 28.105 22.92 ;
     RECT  27.101 24.672 28.109 24.696 ;
     RECT  27.635 8.4 28.145 8.424 ;
     RECT  28.117 32.832 28.204 32.856 ;
     RECT  27.929 28.416 28.217 31.272 ;
     RECT  28.069 33.984 28.316 34.92 ;
     RECT  27.353 35.952 28.316 36.264 ;
     RECT  28.249 42.144 28.333 42.168 ;
     RECT  28.316 33.984 28.357 36.264 ;
     RECT  27.724 11.376 28.393 13.032 ;
     RECT  27.425 26.544 28.465 27.096 ;
     RECT  28.465 26.544 28.501 28.248 ;
     RECT  28.357 33.984 28.645 36.504 ;
     RECT  28.645 33.84 28.717 36.504 ;
     RECT  28.037 37.584 28.717 37.608 ;
     RECT  28.645 41.568 28.739 41.592 ;
     RECT  28.073 5.04 28.897 5.208 ;
     RECT  28.105 21.408 28.897 23.352 ;
     RECT  27.635 9.696 29.077 9.72 ;
     RECT  28.393 11.376 29.077 13.08 ;
     RECT  28.249 17.088 29.077 17.112 ;
     RECT  28.933 32.736 29.077 32.76 ;
     RECT  27.029 0.192 29.125 0.552 ;
     RECT  28.501 25.68 29.149 28.248 ;
     RECT  27.997 19.536 29.185 20.328 ;
     RECT  28.217 29.52 29.221 31.272 ;
     RECT  29.077 32.688 29.221 32.76 ;
     RECT  29.149 25.536 29.269 28.248 ;
     RECT  29.221 29.232 29.269 32.76 ;
     RECT  28.717 33.84 29.269 37.608 ;
     RECT  29.221 18.24 29.401 18.264 ;
     RECT  29.185 19.248 29.401 20.328 ;
     RECT  28.073 3.936 29.408 3.96 ;
     RECT  28.897 5.04 29.408 6.12 ;
     RECT  29.293 8.208 29.408 8.232 ;
     RECT  29.077 9.696 29.408 13.704 ;
     RECT  29.077 16.896 29.408 17.112 ;
     RECT  29.401 18.24 29.408 20.328 ;
     RECT  28.897 21.408 29.408 24.168 ;
     RECT  29.269 25.536 29.408 37.608 ;
     RECT  29.149 39.552 29.408 39.576 ;
     RECT  29.408 2.148 29.512 41.052 ;
     RECT  29.041 43.056 29.585 43.08 ;
     RECT  29.512 2.418 29.704 40.782 ;
     RECT  29.704 6.096 29.765 11.304 ;
     RECT  29.704 31.296 29.765 37.032 ;
     RECT  29.704 14.88 29.837 30.168 ;
     RECT  29.765 36 29.837 37.032 ;
     RECT  29.765 6.096 29.843 9.144 ;
     RECT  29.837 14.88 29.843 29.928 ;
     RECT  29.704 39.456 29.873 39.576 ;
     RECT  29.843 7.056 29.884 9.144 ;
     RECT  29.125 0.144 29.939 0.552 ;
     RECT  29.837 36.048 29.945 37.032 ;
     RECT  29.765 31.296 30.197 34.776 ;
     RECT  29.884 7.344 30.227 9.144 ;
     RECT  30.227 8.688 30.305 8.712 ;
     RECT  29.939 0.144 30.323 0.504 ;
     RECT  30.197 32.496 30.333 34.776 ;
     RECT  30.323 0.144 30.371 0.456 ;
     RECT  30.333 33.024 30.377 34.776 ;
     RECT  29.843 22.176 30.449 29.928 ;
     RECT  30.377 33.84 30.593 34.776 ;
     RECT  30.449 23.76 30.665 29.928 ;
     RECT  30.668 40.992 30.755 41.016 ;
     RECT  30.665 24.624 30.803 29.928 ;
     RECT  29.765 10.704 30.809 11.304 ;
     RECT  29.945 36.048 30.881 36.936 ;
     RECT  30.803 28.512 30.913 29.928 ;
     RECT  30.197 31.296 30.913 31.32 ;
     RECT  30.913 28.512 30.953 31.32 ;
     RECT  30.449 22.176 31.043 22.728 ;
     RECT  30.881 36.24 31.061 36.936 ;
     RECT  29.843 14.88 31.133 21.144 ;
     RECT  31.133 15.072 31.273 21.144 ;
     RECT  30.803 24.624 31.331 27.432 ;
     RECT  30.809 10.944 31.345 11.304 ;
     RECT  29.704 12.288 31.345 13.704 ;
     RECT  30.953 30.144 31.385 30.84 ;
     RECT  29.869 42.144 31.477 42.168 ;
     RECT  29.873 39.456 31.669 39.48 ;
     RECT  31.273 15.072 31.709 21.672 ;
     RECT  31.043 22.704 31.715 22.728 ;
     RECT  31.669 39.456 31.765 40.488 ;
     RECT  31.345 10.944 31.817 13.704 ;
     RECT  31.765 39.072 31.852 40.488 ;
     RECT  30.371 0.432 31.877 0.456 ;
     RECT  31.093 9.696 31.921 9.72 ;
     RECT  31.817 10.944 31.921 10.968 ;
     RECT  31.877 0.096 31.957 0.456 ;
     RECT  31.477 42.144 31.997 43.08 ;
     RECT  31.957 0.096 32.065 0.504 ;
     RECT  31.817 11.952 32.101 13.704 ;
     RECT  31.709 15.072 32.101 19.944 ;
     RECT  31.331 25.632 32.101 27.432 ;
     RECT  30.953 28.512 32.101 29.016 ;
     RECT  31.852 39.84 32.105 40.488 ;
     RECT  32.101 11.952 32.147 19.944 ;
     RECT  30.227 7.344 32.149 7.368 ;
     RECT  30.593 34.752 32.245 34.776 ;
     RECT  32.149 7.248 32.249 7.368 ;
     RECT  32.245 34.224 32.249 34.776 ;
     RECT  31.331 24.624 32.281 24.648 ;
     RECT  31.061 36.24 32.281 36.264 ;
     RECT  31.385 30.24 32.341 30.84 ;
     RECT  32.281 23.952 32.365 24.648 ;
     RECT  31.997 43.056 32.365 43.08 ;
     RECT  32.281 35.328 32.425 36.264 ;
     RECT  32.365 24.624 32.569 24.648 ;
     RECT  32.101 25.632 32.569 29.016 ;
     RECT  32.569 24.624 32.641 29.016 ;
     RECT  32.173 33.072 32.641 33.096 ;
     RECT  32.641 24.624 32.677 29.112 ;
     RECT  32.341 30.24 32.677 31.032 ;
     RECT  32.641 33.072 32.713 33.192 ;
     RECT  32.105 39.84 32.797 40.44 ;
     RECT  32.677 24.624 32.821 31.032 ;
     RECT  32.821 24.624 32.825 31.512 ;
     RECT  32.147 14.112 32.861 19.944 ;
     RECT  32.425 35.328 32.897 36.504 ;
     RECT  32.825 24.624 32.969 29.208 ;
     RECT  32.897 36.24 33.068 36.504 ;
     RECT  32.861 14.112 33.077 18.264 ;
     RECT  32.147 11.952 33.145 13.128 ;
     RECT  33.077 14.112 33.145 15.096 ;
     RECT  32.861 19.248 33.145 19.944 ;
     RECT  31.709 21.072 33.145 21.672 ;
     RECT  32.825 30.24 33.155 31.512 ;
     RECT  33.145 19.248 33.177 21.672 ;
     RECT  33.177 19.248 33.185 21.528 ;
     RECT  33.068 36.24 33.221 37.272 ;
     RECT  33.109 42.144 33.365 42.168 ;
     RECT  33.077 16.272 33.437 18.264 ;
     RECT  33.155 30.576 33.473 31.512 ;
     RECT  32.969 24.624 33.539 29.016 ;
     RECT  32.713 32.88 33.577 33.192 ;
     RECT  32.249 34.224 33.577 34.248 ;
     RECT  33.539 26.496 33.581 29.016 ;
     RECT  31.921 9.696 33.589 10.968 ;
     RECT  33.145 11.952 33.589 15.096 ;
     RECT  33.577 32.88 33.589 34.248 ;
     RECT  33.589 9.696 33.635 15.096 ;
     RECT  33.589 32.88 33.725 34.872 ;
     RECT  33.725 32.88 33.761 34.728 ;
     RECT  33.539 24.624 34.009 25.272 ;
     RECT  34.009 24.24 34.297 25.272 ;
     RECT  33.473 30.576 34.513 31.416 ;
     RECT  33.109 22.944 34.549 22.968 ;
     RECT  34.513 30.096 34.585 31.416 ;
     RECT  32.461 7.104 34.621 7.128 ;
     RECT  33.185 19.44 34.621 21.528 ;
     RECT  33.581 26.544 34.645 29.016 ;
     RECT  34.585 30.096 34.645 32.04 ;
     RECT  33.221 36.24 34.645 36.456 ;
     RECT  33.577 37.488 34.645 37.512 ;
     RECT  34.645 26.544 34.729 32.04 ;
     RECT  34.297 41.568 34.739 41.592 ;
     RECT  33.437 16.272 34.765 16.296 ;
     RECT  34.621 6.816 34.808 7.128 ;
     RECT  34.076 8.4 34.808 8.424 ;
     RECT  33.635 9.696 34.808 11.016 ;
     RECT  33.635 12.048 34.808 15.096 ;
     RECT  34.765 16.08 34.808 16.296 ;
     RECT  33.437 17.424 34.808 18.264 ;
     RECT  34.621 19.44 34.808 21.72 ;
     RECT  34.549 22.8 34.808 22.968 ;
     RECT  34.297 24.048 34.808 25.272 ;
     RECT  34.729 26.256 34.808 32.04 ;
     RECT  33.761 33.024 34.808 34.728 ;
     RECT  34.645 36.24 34.808 37.512 ;
     RECT  32.797 39.84 34.808 39.912 ;
     RECT  34.808 2.148 34.912 41.052 ;
     RECT  34.912 2.418 35.104 40.782 ;
     RECT  35.104 10.944 35.201 15 ;
     RECT  35.104 39.744 35.219 40.536 ;
     RECT  35.104 19.536 35.237 36.84 ;
     RECT  35.219 39.744 35.237 39.864 ;
     RECT  35.237 19.536 35.273 22.824 ;
     RECT  35.201 10.944 35.315 14.136 ;
     RECT  35.237 23.952 35.363 36.84 ;
     RECT  35.315 10.944 35.381 13.704 ;
     RECT  33.493 43.056 35.701 43.08 ;
     RECT  35.701 42.192 35.705 43.08 ;
     RECT  35.705 42.192 35.987 42.216 ;
     RECT  35.363 24.624 36.029 36.84 ;
     RECT  35.104 8.4 36.097 9.96 ;
     RECT  35.104 4.368 36.133 4.392 ;
     RECT  36.097 8.304 36.137 9.96 ;
     RECT  36.133 3.648 36.205 4.392 ;
     RECT  35.104 15.984 36.205 16.584 ;
     RECT  35.273 19.536 36.209 22.2 ;
     RECT  36.029 30.864 36.245 36.84 ;
     RECT  35.104 6.816 36.277 6.84 ;
     RECT  35.237 39.744 36.277 39.768 ;
     RECT  36.277 39.36 36.317 39.768 ;
     RECT  36.205 3.6 36.385 4.392 ;
     RECT  36.313 41.568 36.397 42.168 ;
     RECT  36.137 9.648 36.421 9.96 ;
     RECT  35.381 10.944 36.421 12.312 ;
     RECT  36.209 21.36 36.469 22.2 ;
     RECT  36.421 9.648 36.517 12.312 ;
     RECT  35.381 13.68 36.517 13.704 ;
     RECT  36.205 15.984 36.517 17.016 ;
     RECT  36.385 3.6 36.529 4.776 ;
     RECT  36.245 30.864 36.605 36.552 ;
     RECT  36.029 24.624 36.637 29.88 ;
     RECT  36.529 3.312 36.641 4.776 ;
     RECT  36.313 23.328 36.745 23.352 ;
     RECT  36.637 24.336 36.745 29.88 ;
     RECT  32.065 0.096 36.755 0.552 ;
     RECT  36.397 41.616 36.793 42.168 ;
     RECT  36.641 4.368 36.899 4.776 ;
     RECT  36.899 4.704 36.961 4.776 ;
     RECT  36.277 6.816 36.961 7.224 ;
     RECT  36.137 8.304 36.961 8.52 ;
     RECT  36.745 23.328 36.997 29.88 ;
     RECT  36.605 30.864 36.997 34.728 ;
     RECT  36.469 21.36 37.033 22.248 ;
     RECT  37.033 21.36 37.117 22.296 ;
     RECT  36.517 15.072 37.177 17.016 ;
     RECT  36.755 0.096 37.187 0.408 ;
     RECT  36.793 41.616 37.187 41.64 ;
     RECT  37.177 14.832 37.217 17.016 ;
     RECT  36.961 6.816 37.253 8.52 ;
     RECT  37.117 21.36 37.321 22.2 ;
     RECT  35.104 18.144 37.349 18.168 ;
     RECT  36.209 19.536 37.349 19.848 ;
     RECT  37.321 21.12 37.379 22.2 ;
     RECT  36.517 9.648 37.397 13.704 ;
     RECT  36.997 23.328 37.397 34.728 ;
     RECT  37.321 0.048 37.427 0.072 ;
     RECT  37.253 8.304 37.429 8.52 ;
     RECT  37.397 9.648 37.429 9.96 ;
     RECT  37.217 16.512 37.432 17.016 ;
     RECT  37.349 18.144 37.433 19.848 ;
     RECT  37.397 28.992 37.433 34.728 ;
     RECT  37.397 10.944 37.469 13.704 ;
     RECT  36.961 4.704 37.501 5.496 ;
     RECT  37.397 23.328 37.505 27.96 ;
     RECT  37.429 8.304 37.541 9.96 ;
     RECT  37.379 21.12 37.541 22.152 ;
     RECT  37.217 14.832 37.571 15.432 ;
     RECT  37.501 4.704 37.573 5.736 ;
     RECT  37.253 6.816 37.573 7.224 ;
     RECT  37.541 8.304 37.577 8.52 ;
     RECT  37.469 11.136 37.577 13.704 ;
     RECT  37.541 9.504 37.619 9.96 ;
     RECT  37.541 21.168 37.649 22.152 ;
     RECT  37.433 32.784 37.649 34.728 ;
     RECT  37.577 11.424 37.667 13.704 ;
     RECT  37.667 12.768 37.681 13.704 ;
     RECT  37.573 4.704 37.721 7.224 ;
     RECT  37.433 28.992 37.721 31.512 ;
     RECT  37.525 43.056 37.793 43.08 ;
     RECT  37.649 32.832 37.901 34.728 ;
     RECT  37.432 16.512 37.909 17.064 ;
     RECT  36.605 36.24 37.909 36.552 ;
     RECT  37.717 37.872 37.909 37.896 ;
     RECT  36.641 3.312 37.933 3.336 ;
     RECT  37.909 16.512 37.933 17.16 ;
     RECT  37.433 18.144 37.933 18.408 ;
     RECT  37.933 3.312 37.973 3.912 ;
     RECT  37.649 21.264 37.973 22.152 ;
     RECT  36.317 39.36 37.973 39.384 ;
     RECT  37.897 40.992 37.981 41.016 ;
     RECT  37.505 23.328 38.009 27.384 ;
     RECT  37.901 32.832 38.045 33.624 ;
     RECT  37.721 28.992 38.195 31.368 ;
     RECT  38.195 31.344 38.225 31.368 ;
     RECT  38.195 28.992 38.261 30.072 ;
     RECT  37.681 12.768 38.333 13.992 ;
     RECT  38.261 28.992 38.333 30.024 ;
     RECT  38.333 28.992 38.365 29.208 ;
     RECT  38.009 23.328 38.405 24.792 ;
     RECT  38.045 33.6 38.405 33.624 ;
     RECT  37.933 16.512 38.413 18.408 ;
     RECT  37.433 19.536 38.437 19.848 ;
     RECT  37.909 36.24 38.513 37.896 ;
     RECT  38.513 36.24 38.52 36.264 ;
     RECT  37.571 15.36 38.545 15.432 ;
     RECT  38.413 16.512 38.545 17.64 ;
     RECT  37.901 34.608 38.627 34.728 ;
     RECT  37.577 8.304 38.689 8.424 ;
     RECT  37.619 9.504 38.689 9.528 ;
     RECT  37.667 11.424 38.725 11.448 ;
     RECT  38.365 28.656 38.725 29.208 ;
     RECT  38.333 13.104 38.771 13.992 ;
     RECT  38.009 26.208 38.771 27.384 ;
     RECT  38.684 41.616 38.771 41.64 ;
     RECT  37.721 5.328 38.773 7.224 ;
     RECT  38.689 8.304 38.773 9.528 ;
     RECT  38.771 13.632 38.773 13.992 ;
     RECT  38.545 15.36 38.773 17.64 ;
     RECT  38.773 13.632 38.801 17.64 ;
     RECT  38.773 5.328 38.819 9.528 ;
     RECT  38.801 16.56 38.873 17.64 ;
     RECT  38.437 18.96 38.941 19.848 ;
     RECT  37.973 21.264 38.941 22.056 ;
     RECT  37.973 3.888 39.233 3.912 ;
     RECT  38.801 13.632 39.769 13.656 ;
     RECT  38.819 5.328 39.805 7.752 ;
     RECT  38.801 14.784 39.805 15.432 ;
     RECT  38.873 16.56 39.805 17.16 ;
     RECT  38.513 37.872 39.841 37.896 ;
     RECT  38.941 18.96 39.877 22.056 ;
     RECT  39.805 14.784 39.913 17.16 ;
     RECT  39.877 18.24 39.913 22.056 ;
     RECT  39.913 14.784 39.925 22.776 ;
     RECT  38.405 23.808 39.925 24.792 ;
     RECT  38.771 26.208 39.925 26.616 ;
     RECT  39.157 43.056 39.925 43.08 ;
     RECT  39.157 0.096 39.949 0.12 ;
     RECT  39.925 26.208 39.949 26.712 ;
     RECT  39.769 3.408 39.985 3.432 ;
     RECT  39.553 30.768 40.201 30.792 ;
     RECT  39.985 3.024 40.208 3.432 ;
     RECT  39.805 4.512 40.208 7.752 ;
     RECT  38.819 9.024 40.208 9.528 ;
     RECT  38.725 11.424 40.208 12.024 ;
     RECT  39.769 13.056 40.208 13.656 ;
     RECT  39.925 14.784 40.208 24.792 ;
     RECT  39.949 26.112 40.208 26.712 ;
     RECT  38.725 28.416 40.208 29.208 ;
     RECT  40.201 30.768 40.208 30.888 ;
     RECT  40.021 31.92 40.208 31.944 ;
     RECT  38.627 34.608 40.208 34.632 ;
     RECT  38.52 36 40.208 36.264 ;
     RECT  39.841 37.584 40.208 37.896 ;
     RECT  38.797 39.072 40.208 39.096 ;
     RECT  38.329 40.416 40.208 40.44 ;
     RECT  40.208 2.148 40.312 41.052 ;
     RECT  39.925 43.008 40.316 43.08 ;
     RECT  39.949 0.096 40.403 0.6 ;
     RECT  40.312 2.418 40.504 40.782 ;
     RECT  40.504 18.816 40.745 23.16 ;
     RECT  40.403 0.096 40.787 0.552 ;
     RECT  40.316 42.192 40.993 43.08 ;
     RECT  40.745 18.816 41.105 20.376 ;
     RECT  41.105 19.248 41.141 20.376 ;
     RECT  40.787 0.528 41.171 0.552 ;
     RECT  40.993 42.144 41.171 43.08 ;
     RECT  40.504 13.056 41.184 14.28 ;
     RECT  40.504 11.952 41.213 12.072 ;
     RECT  40.745 21.456 41.213 23.16 ;
     RECT  40.504 24.624 41.293 30.888 ;
     RECT  40.504 15.456 41.321 17.688 ;
     RECT  41.184 13.056 41.357 13.128 ;
     RECT  40.504 2.88 41.393 3.336 ;
     RECT  40.504 37.584 41.393 39.384 ;
     RECT  41.357 13.056 41.429 13.08 ;
     RECT  41.184 14.112 41.429 14.28 ;
     RECT  41.213 21.456 41.429 22.824 ;
     RECT  41.393 37.584 41.429 37.608 ;
     RECT  40.504 36 41.452 36.504 ;
     RECT  41.141 19.44 41.537 20.376 ;
     RECT  41.293 24.624 41.555 28.92 ;
     RECT  41.293 30 41.555 30.888 ;
     RECT  41.555 30.384 41.557 30.888 ;
     RECT  40.504 4.512 41.603 8.424 ;
     RECT  41.171 42.192 41.603 43.08 ;
     RECT  41.393 3.312 41.605 3.336 ;
     RECT  41.603 4.512 41.605 5.352 ;
     RECT  41.603 6.816 41.605 8.424 ;
     RECT  40.504 9.504 41.605 10.728 ;
     RECT  41.321 16.512 41.609 17.688 ;
     RECT  41.605 3.312 41.651 5.352 ;
     RECT  41.651 3.312 41.717 4.296 ;
     RECT  41.605 6.816 41.717 10.728 ;
     RECT  41.537 19.536 41.717 20.376 ;
     RECT  41.609 17.616 41.753 17.688 ;
     RECT  41.321 15.456 41.861 15.48 ;
     RECT  41.557 30.384 41.893 31.08 ;
     RECT  41.941 40.992 42.041 41.016 ;
     RECT  41.213 11.952 42.073 12.024 ;
     RECT  41.717 6.816 42.113 10.296 ;
     RECT  42.113 6.816 42.149 8.424 ;
     RECT  40.504 32.448 42.293 32.472 ;
     RECT  41.452 36 42.361 36.312 ;
     RECT  41.941 0.096 42.365 0.12 ;
     RECT  42.073 11.808 42.365 12.024 ;
     RECT  41.555 25.008 42.524 28.92 ;
     RECT  42.109 23.808 42.545 23.832 ;
     RECT  42.365 11.808 42.581 11.976 ;
     RECT  42.524 25.008 42.611 29.208 ;
     RECT  42.611 25.008 42.617 29.016 ;
     RECT  41.893 30.384 42.649 31.224 ;
     RECT  41.429 14.112 42.721 14.136 ;
     RECT  42.721 14.112 42.725 15.048 ;
     RECT  41.429 21.456 42.757 22.776 ;
     RECT  41.603 43.056 42.757 43.08 ;
     RECT  42.757 43.008 42.761 43.08 ;
     RECT  42.757 3.072 42.829 3.096 ;
     RECT  42.617 25.2 42.833 29.016 ;
     RECT  41.753 17.616 42.853 17.64 ;
     RECT  41.717 19.536 42.853 19.656 ;
     RECT  42.361 35.856 42.869 36.312 ;
     RECT  42.853 17.616 42.899 19.656 ;
     RECT  41.609 16.512 42.901 16.536 ;
     RECT  42.649 30.384 42.901 31.272 ;
     RECT  42.761 43.008 42.905 43.032 ;
     RECT  42.899 18 42.941 19.656 ;
     RECT  41.393 39.36 43.045 39.384 ;
     RECT  42.833 25.2 43.049 27.336 ;
     RECT  43.045 38.4 43.049 39.384 ;
     RECT  43.049 25.2 43.091 25.224 ;
     RECT  42.829 3.024 43.117 3.096 ;
     RECT  43.109 40.992 43.193 41.016 ;
     RECT  42.149 7.392 43.225 7.656 ;
     RECT  42.289 1.728 43.228 1.752 ;
     RECT  42.941 19.392 43.237 19.656 ;
     RECT  42.757 21.216 43.237 22.776 ;
     RECT  43.237 19.392 43.324 22.776 ;
     RECT  43.225 6.864 43.333 7.656 ;
     RECT  43.117 3.024 43.373 3.144 ;
     RECT  42.113 9.504 43.441 9.816 ;
     RECT  42.901 16.272 43.441 16.536 ;
     RECT  43.324 21.216 43.441 22.776 ;
     RECT  42.901 30.288 43.441 31.272 ;
     RECT  43.373 3.024 43.481 3.096 ;
     RECT  43.333 6 43.513 7.656 ;
     RECT  43.441 9.072 43.513 9.816 ;
     RECT  43.324 19.392 43.517 19.656 ;
     RECT  43.513 6 43.525 9.816 ;
     RECT  43.525 6 43.612 10.872 ;
     RECT  43.333 42.192 43.619 42.216 ;
     RECT  43.441 21.216 43.628 22.824 ;
     RECT  43.333 24.144 43.628 24.168 ;
     RECT  43.628 21.216 43.715 24.168 ;
     RECT  42.869 35.856 43.861 36.264 ;
     RECT  43.612 6 43.873 10.152 ;
     RECT  42.581 11.952 43.909 11.976 ;
     RECT  42.793 13.104 43.909 13.128 ;
     RECT  42.725 15.024 43.916 15.048 ;
     RECT  41.717 4.272 43.945 4.296 ;
     RECT  43.873 5.28 43.945 10.152 ;
     RECT  43.441 16.272 43.945 16.584 ;
     RECT  42.941 18 43.945 18.168 ;
     RECT  43.517 19.392 43.945 19.56 ;
     RECT  43.481 3.024 43.957 3.048 ;
     RECT  43.916 14.928 43.981 15.048 ;
     RECT  43.945 16.272 43.981 18.168 ;
     RECT  43.909 11.952 43.985 13.128 ;
     RECT  43.981 14.928 43.985 18.168 ;
     RECT  43.985 14.928 44.003 17.064 ;
     RECT  43.957 2.784 44.044 3.048 ;
     RECT  43.985 18.144 44.057 18.168 ;
     RECT  43.049 26.208 44.125 27.336 ;
     RECT  43.985 12.24 44.129 13.128 ;
     RECT  43.945 4.272 44.147 10.152 ;
     RECT  44.125 26.208 44.269 27.384 ;
     RECT  44.003 15.024 44.345 17.064 ;
     RECT  43.049 38.4 44.377 38.76 ;
     RECT  44.129 12.48 44.417 13.128 ;
     RECT  44.147 4.272 44.453 6.888 ;
     RECT  43.861 35.856 44.453 36.456 ;
     RECT  44.269 25.68 44.485 27.384 ;
     RECT  44.453 4.272 44.489 6.84 ;
     RECT  44.147 7.872 44.489 10.152 ;
     RECT  44.377 38.4 44.525 39.384 ;
     RECT  44.489 8.256 44.561 8.28 ;
     RECT  44.453 35.856 44.637 35.88 ;
     RECT  44.161 34.032 44.677 34.056 ;
     RECT  42.833 28.8 44.737 29.016 ;
     RECT  43.441 30.288 44.737 31.944 ;
     RECT  44.044 2.976 44.953 3.048 ;
     RECT  43.715 21.216 44.965 22.776 ;
     RECT  43.189 0.528 44.993 0.552 ;
     RECT  44.489 9.504 45.097 10.152 ;
     RECT  44.965 21.072 45.205 22.776 ;
     RECT  43.945 42.144 45.245 42.168 ;
     RECT  44.345 15.024 45.349 16.584 ;
     RECT  45.061 17.856 45.349 17.976 ;
     RECT  44.737 28.8 45.493 31.944 ;
     RECT  43.945 19.296 45.529 19.56 ;
     RECT  44.485 25.488 45.529 27.384 ;
     RECT  45.493 28.464 45.529 31.944 ;
     RECT  45.097 9.504 45.565 10.2 ;
     RECT  44.417 12.48 45.565 12.84 ;
     RECT  44.953 2.976 45.608 3.912 ;
     RECT  44.489 5.04 45.608 6.84 ;
     RECT  45.565 9.504 45.608 11.016 ;
     RECT  45.565 12.48 45.608 13.128 ;
     RECT  45.349 15.024 45.608 17.976 ;
     RECT  45.529 19.248 45.608 19.56 ;
     RECT  45.205 21.072 45.608 22.824 ;
     RECT  43.715 24.144 45.608 24.168 ;
     RECT  45.529 25.488 45.608 31.944 ;
     RECT  44.677 33.6 45.608 34.056 ;
     RECT  44.637 35.328 45.608 35.88 ;
     RECT  44.525 38.4 45.608 39.24 ;
     RECT  44.773 40.992 45.608 41.016 ;
     RECT  45.608 2.148 45.712 41.052 ;
     RECT  45.712 2.418 45.904 40.782 ;
     RECT  45.157 0.096 45.973 0.168 ;
     RECT  45.904 5.04 46.001 7.896 ;
     RECT  45.904 26.256 46.067 33.624 ;
     RECT  45.973 0.096 46.069 0.216 ;
     RECT  46.067 28.992 46.115 33.624 ;
     RECT  45.904 12.384 46.145 19.944 ;
     RECT  46.067 26.256 46.145 27.672 ;
     RECT  45.904 21.168 46.181 23.064 ;
     RECT  46.001 6 46.209 7.896 ;
     RECT  46.115 28.992 46.217 31.944 ;
     RECT  46.145 15.312 46.253 19.944 ;
     RECT  46.181 21.168 46.325 22.824 ;
     RECT  45.541 43.008 46.357 43.08 ;
     RECT  46.209 6.624 46.397 7.896 ;
     RECT  46.325 21.216 46.469 22.824 ;
     RECT  46.357 42.144 46.577 43.08 ;
     RECT  46.069 0.096 46.649 0.264 ;
     RECT  46.649 0.144 46.681 0.264 ;
     RECT  46.397 6.816 46.721 7.896 ;
     RECT  46.145 12.384 46.757 14.232 ;
     RECT  46.577 42.144 46.789 42.216 ;
     RECT  45.904 37.44 46.829 39.528 ;
     RECT  46.789 41.568 46.873 42.216 ;
     RECT  46.145 26.256 46.933 27.384 ;
     RECT  46.115 33.6 46.973 33.624 ;
     RECT  46.757 12.384 47.041 14.136 ;
     RECT  46.681 0.144 47.117 0.552 ;
     RECT  46.933 25.968 47.149 27.384 ;
     RECT  46.829 37.44 47.225 39.384 ;
     RECT  46.873 42.144 47.225 42.216 ;
     RECT  46.217 28.992 47.257 31.56 ;
     RECT  47.149 25.872 47.365 27.384 ;
     RECT  47.257 28.608 47.365 31.56 ;
     RECT  47.225 38.208 47.441 39.384 ;
     RECT  45.904 24.144 47.512 24.36 ;
     RECT  47.117 0.528 47.603 0.552 ;
     RECT  47.225 42.192 47.603 42.216 ;
     RECT  46.253 15.408 47.756 19.944 ;
     RECT  46.469 21.456 47.756 22.824 ;
     RECT  47.756 15.408 47.843 22.824 ;
     RECT  47.041 12.144 47.869 14.136 ;
     RECT  47.843 15.408 47.869 19.8 ;
     RECT  47.365 25.872 47.891 31.56 ;
     RECT  47.843 21.12 47.941 22.824 ;
     RECT  45.904 36 47.941 36.024 ;
     RECT  47.891 25.872 47.945 30.84 ;
     RECT  47.945 25.872 47.981 25.896 ;
     RECT  47.441 38.208 47.981 38.664 ;
     RECT  47.941 36 47.987 36.792 ;
     RECT  47.512 24.096 48.013 24.36 ;
     RECT  45.904 9.504 48.017 11.016 ;
     RECT  47.945 27.072 48.017 30.84 ;
     RECT  47.987 36.288 48.028 36.792 ;
     RECT  47.969 43.056 48.053 43.08 ;
     RECT  47.941 21.12 48.061 23.112 ;
     RECT  48.017 28.608 48.161 30.84 ;
     RECT  48.188 0.048 48.275 0.072 ;
     RECT  47.869 12.144 48.275 19.8 ;
     RECT  48.161 28.608 48.377 29.016 ;
     RECT  48.061 21.456 48.409 23.112 ;
     RECT  48.013 24.096 48.409 25.08 ;
     RECT  48.332 41.616 48.419 41.64 ;
     RECT  46.721 7.872 48.469 7.896 ;
     RECT  48.275 12.144 48.485 18.024 ;
     RECT  48.409 21.456 48.493 25.08 ;
     RECT  45.904 3.888 48.517 3.912 ;
     RECT  48.469 7.776 48.517 7.896 ;
     RECT  48.485 12.144 48.593 17.064 ;
     RECT  48.517 7.44 48.601 7.896 ;
     RECT  48.601 7.872 48.625 7.896 ;
     RECT  48.493 21.456 48.629 23.112 ;
     RECT  48.493 24.48 48.629 25.08 ;
     RECT  48.517 3.744 48.665 3.912 ;
     RECT  48.017 27.072 48.665 27.624 ;
     RECT  48.593 12.912 48.737 17.064 ;
     RECT  48.629 24.624 48.737 25.08 ;
     RECT  48.737 12.912 48.809 14.232 ;
     RECT  48.725 42.144 48.809 42.168 ;
     RECT  47.981 38.4 48.845 38.664 ;
     RECT  48.665 3.744 48.877 3.768 ;
     RECT  48.665 27.072 48.913 27.096 ;
     RECT  48.625 7.872 48.953 8.472 ;
     RECT  48.877 11.568 48.989 11.592 ;
     RECT  48.877 3.264 48.995 3.768 ;
     RECT  48.625 6.24 49.045 6.264 ;
     RECT  48.275 19.296 49.045 19.8 ;
     RECT  48.629 21.456 49.045 22.344 ;
     RECT  48.017 9.504 49.057 10.056 ;
     RECT  48.809 14.016 49.061 14.232 ;
     RECT  48.913 26.976 49.061 27.096 ;
     RECT  48.949 2.256 49.097 2.28 ;
     RECT  49.057 9.504 49.097 10.2 ;
     RECT  48.737 15.408 49.097 17.064 ;
     RECT  48.845 38.4 49.133 38.424 ;
     RECT  48.737 24.912 49.241 25.08 ;
     RECT  49.241 25.056 49.273 25.08 ;
     RECT  49.273 25.056 49.313 25.704 ;
     RECT  49.021 4.992 49.381 5.016 ;
     RECT  49.045 6.24 49.381 6.36 ;
     RECT  48.953 8.448 49.381 8.472 ;
     RECT  49.097 10.176 49.381 10.2 ;
     RECT  49.34 11.424 49.381 11.448 ;
     RECT  49.381 10.176 49.427 11.448 ;
     RECT  49.129 0.528 49.619 0.552 ;
     RECT  49.189 43.056 49.637 43.08 ;
     RECT  49.381 4.8 49.705 6.36 ;
     RECT  48.161 30.432 49.741 30.84 ;
     RECT  49.045 19.296 49.777 19.944 ;
     RECT  49.741 30.384 49.853 30.84 ;
     RECT  49.489 17.136 49.885 17.64 ;
     RECT  49.061 14.016 49.889 14.04 ;
     RECT  48.377 28.8 49.889 29.016 ;
     RECT  48.028 36.288 49.889 36.312 ;
     RECT  48.809 12.912 49.921 12.936 ;
     RECT  49.045 21.12 49.921 22.344 ;
     RECT  48.995 3.744 49.957 3.768 ;
     RECT  49.705 4.8 49.957 6.888 ;
     RECT  49.957 3.744 49.993 6.888 ;
     RECT  49.921 12.912 49.993 13.944 ;
     RECT  49.885 17.136 49.993 18.024 ;
     RECT  49.777 19.248 49.993 19.944 ;
     RECT  49.993 3.648 50.029 6.888 ;
     RECT  49.381 8.448 50.029 9.096 ;
     RECT  50.029 3.648 50.063 9.096 ;
     RECT  49.889 28.992 50.101 29.016 ;
     RECT  49.853 30.384 50.101 30.792 ;
     RECT  49.097 15.408 50.137 16.008 ;
     RECT  50.156 0.048 50.243 0.312 ;
     RECT  49.921 21.12 50.317 22.584 ;
     RECT  49.993 17.136 50.389 19.944 ;
     RECT  50.317 21.12 50.389 22.68 ;
     RECT  50.063 3.648 50.569 9.624 ;
     RECT  49.427 10.704 50.569 10.728 ;
     RECT  50.389 17.136 50.605 22.68 ;
     RECT  50.605 17.136 50.629 22.776 ;
     RECT  50.281 24.336 50.677 24.36 ;
     RECT  50.605 39.84 50.713 39.864 ;
     RECT  50.569 3.648 50.749 10.728 ;
     RECT  49.061 27.072 50.785 27.096 ;
     RECT  50.713 39.312 50.785 39.864 ;
     RECT  50.137 14.976 50.813 16.008 ;
     RECT  50.629 16.992 50.813 22.776 ;
     RECT  50.243 0.096 50.819 0.312 ;
     RECT  50.389 42.144 50.825 42.168 ;
     RECT  50.497 35.904 50.869 35.928 ;
     RECT  49.993 37.008 50.869 37.032 ;
     RECT  50.785 38.832 50.929 39.864 ;
     RECT  49.345 2.208 51.008 2.232 ;
     RECT  50.749 3.312 51.008 10.728 ;
     RECT  49.993 12.768 51.008 13.944 ;
     RECT  50.813 14.976 51.008 22.776 ;
     RECT  50.677 24.336 51.008 24.408 ;
     RECT  49.313 25.68 51.008 25.704 ;
     RECT  50.785 27.072 51.008 27.96 ;
     RECT  50.101 28.992 51.008 30.792 ;
     RECT  50.869 35.712 51.008 37.032 ;
     RECT  50.929 38.16 51.008 39.864 ;
     RECT  50.005 40.992 51.008 41.016 ;
     RECT  51.008 2.148 51.112 41.052 ;
     RECT  51.112 2.418 51.173 41.052 ;
     RECT  51.173 2.418 51.257 41.16 ;
     RECT  51.257 2.418 51.304 40.782 ;
     RECT  51.304 5.52 51.329 8.04 ;
     RECT  51.329 5.52 51.401 7.944 ;
     RECT  51.304 16.272 51.653 18.024 ;
     RECT  51.304 10.704 51.689 11.976 ;
     RECT  51.689 11.232 51.761 11.976 ;
     RECT  51.304 28.32 51.779 29.592 ;
     RECT  50.819 0.096 51.793 0.168 ;
     RECT  51.793 0.048 51.797 0.168 ;
     RECT  51.589 43.056 51.833 43.08 ;
     RECT  51.304 22.464 51.869 25.08 ;
     RECT  51.304 3.12 51.941 3.576 ;
     RECT  51.941 3.312 51.977 3.576 ;
     RECT  51.304 38.16 52.013 39.384 ;
     RECT  51.304 30.768 52.157 30.792 ;
     RECT  51.869 22.512 52.265 25.08 ;
     RECT  51.304 26.976 52.301 27 ;
     RECT  52.013 39.36 52.301 39.384 ;
     RECT  51.401 5.52 52.405 6.888 ;
     RECT  51.401 7.92 52.405 7.944 ;
     RECT  51.304 9.6 52.405 9.624 ;
     RECT  52.405 5.52 52.441 7.944 ;
     RECT  52.297 1.728 52.451 1.752 ;
     RECT  52.013 38.16 52.481 38.184 ;
     RECT  52.405 40.992 52.489 41.016 ;
     RECT  52.441 5.472 52.549 7.944 ;
     RECT  52.405 9.6 52.589 10.248 ;
     RECT  52.265 22.512 52.625 24.504 ;
     RECT  51.797 0.048 52.691 0.12 ;
     RECT  51.304 13.68 52.693 15.192 ;
     RECT  51.761 11.376 52.739 11.976 ;
     RECT  51.653 16.272 52.741 17.736 ;
     RECT  51.779 28.32 52.765 29.016 ;
     RECT  52.693 13.008 52.78 15.192 ;
     RECT  51.977 3.36 52.801 3.576 ;
     RECT  51.304 36.528 52.805 36.552 ;
     RECT  52.739 11.376 52.841 11.4 ;
     RECT  52.757 41.568 52.841 41.592 ;
     RECT  52.801 3.36 52.909 4.392 ;
     RECT  52.549 5.472 52.909 7.992 ;
     RECT  52.741 16.272 52.909 18.408 ;
     RECT  51.304 19.536 52.909 21.48 ;
     RECT  52.765 27.168 52.945 29.016 ;
     RECT  52.909 3.36 52.953 7.992 ;
     RECT  52.953 2.688 52.981 7.992 ;
     RECT  52.78 13.632 52.981 15.192 ;
     RECT  52.909 16.272 52.981 21.48 ;
     RECT  52.981 2.688 52.985 8.04 ;
     RECT  52.981 13.632 53.027 21.48 ;
     RECT  52.985 2.688 53.057 6.072 ;
     RECT  53.027 13.68 53.057 21.48 ;
     RECT  53.057 13.776 53.093 21.48 ;
     RECT  52.945 25.728 53.125 25.752 ;
     RECT  51.973 42.96 53.161 42.984 ;
     RECT  53.093 16.272 53.269 21.48 ;
     RECT  52.625 22.512 53.269 22.632 ;
     RECT  53.093 13.776 53.309 14.808 ;
     RECT  52.985 7.392 53.345 8.04 ;
     RECT  53.345 7.392 53.417 7.992 ;
     RECT  53.269 16.272 53.459 22.632 ;
     RECT  52.691 0.096 53.509 0.12 ;
     RECT  52.748 1.104 53.509 1.128 ;
     RECT  53.509 0.096 53.593 1.128 ;
     RECT  53.459 19.488 53.593 22.632 ;
     RECT  52.625 24.048 53.593 24.504 ;
     RECT  53.125 25.728 53.593 26.136 ;
     RECT  53.593 19.488 53.633 26.136 ;
     RECT  52.945 27.168 53.665 29.16 ;
     RECT  53.633 20.928 53.669 26.136 ;
     RECT  53.593 0.096 53.677 1.176 ;
     RECT  53.161 42.192 53.701 42.984 ;
     RECT  53.665 27.168 53.737 29.256 ;
     RECT  53.701 42.192 53.747 43.08 ;
     RECT  53.449 31.92 53.773 32.088 ;
     RECT  53.593 35.712 53.797 35.736 ;
     RECT  53.459 16.272 53.813 18.504 ;
     RECT  53.341 9.552 53.845 9.576 ;
     RECT  53.797 35.712 53.884 36.504 ;
     RECT  53.057 3.312 54.097 6.072 ;
     RECT  53.417 7.392 54.097 7.944 ;
     RECT  53.669 21.12 54.097 26.136 ;
     RECT  53.737 27.168 54.097 29.352 ;
     RECT  53.813 16.272 54.173 17.736 ;
     RECT  54.169 30.816 54.285 30.84 ;
     RECT  53.773 31.92 54.285 33.096 ;
     RECT  53.747 42.96 54.317 43.08 ;
     RECT  53.309 14.448 54.349 14.808 ;
     RECT  54.349 14.256 54.38 14.808 ;
     RECT  54.025 12.528 54.383 12.552 ;
     RECT  54.38 14.256 54.383 15.144 ;
     RECT  54.097 21.12 54.385 29.352 ;
     RECT  53.633 19.488 54.428 19.656 ;
     RECT  54.385 21.12 54.497 29.64 ;
     RECT  54.428 18.72 54.515 19.656 ;
     RECT  54.383 12.528 54.529 15.144 ;
     RECT  54.173 16.272 54.529 17.544 ;
     RECT  54.285 30.816 54.565 33.096 ;
     RECT  54.529 12.528 54.569 17.544 ;
     RECT  53.845 9.552 54.601 10.152 ;
     RECT  54.097 3.312 54.673 7.944 ;
     RECT  54.601 9.072 54.673 10.152 ;
     RECT  53.773 38.208 54.745 38.232 ;
     RECT  54.673 3.312 54.755 10.152 ;
     RECT  54.745 38.208 54.785 38.376 ;
     RECT  54.421 40.992 54.857 41.016 ;
     RECT  54.755 9.696 54.917 10.152 ;
     RECT  54.529 11.376 54.917 11.4 ;
     RECT  54.917 9.696 54.949 11.4 ;
     RECT  54.569 12.528 54.949 14.808 ;
     RECT  54.949 9.696 54.995 14.808 ;
     RECT  54.995 9.696 55.001 13.128 ;
     RECT  54.515 19.056 55.001 19.656 ;
     RECT  54.755 3.312 55.037 8.712 ;
     RECT  54.569 15.984 55.037 17.544 ;
     RECT  54.497 21.264 55.045 29.64 ;
     RECT  54.565 30.768 55.045 33.72 ;
     RECT  53.677 0.096 55.105 0.408 ;
     RECT  54.995 14.256 55.109 14.808 ;
     RECT  53.981 1.728 55.169 1.752 ;
     RECT  55.045 21.264 55.181 33.72 ;
     RECT  55.181 23.52 55.213 33.72 ;
     RECT  54.529 39.36 55.217 39.384 ;
     RECT  55.169 1.728 55.253 1.848 ;
     RECT  55.213 23.52 55.276 34.152 ;
     RECT  55.253 1.728 55.289 1.752 ;
     RECT  55.001 10.128 55.289 13.128 ;
     RECT  55.276 23.52 55.289 29.832 ;
     RECT  55.289 23.52 55.297 29.736 ;
     RECT  55.181 21.264 55.325 22.536 ;
     RECT  55.325 21.264 55.397 22.488 ;
     RECT  55.276 30.816 55.429 34.152 ;
     RECT  53.884 35.712 55.429 35.736 ;
     RECT  55.109 14.496 55.433 14.808 ;
     RECT  54.317 43.056 55.609 43.08 ;
     RECT  55.105 0.096 55.667 0.552 ;
     RECT  55.397 21.264 55.753 22.392 ;
     RECT  55.285 39.408 55.753 39.432 ;
     RECT  54.785 38.352 55.861 38.376 ;
     RECT  55.037 3.84 56.005 7.656 ;
     RECT  55.037 8.688 56.005 8.712 ;
     RECT  55.667 0.096 56.051 0.504 ;
     RECT  55.037 16.8 56.077 17.544 ;
     RECT  55.609 42.144 56.089 43.08 ;
     RECT  55.433 14.496 56.293 14.52 ;
     RECT  55.297 23.52 56.293 29.016 ;
     RECT  56.293 23.52 56.329 29.64 ;
     RECT  55.429 30.816 56.329 35.736 ;
     RECT  55.753 2.736 56.408 2.76 ;
     RECT  56.005 3.84 56.408 8.712 ;
     RECT  55.289 10.128 56.408 10.296 ;
     RECT  55.289 11.376 56.408 13.128 ;
     RECT  56.293 14.112 56.408 14.52 ;
     RECT  56.077 15.984 56.408 17.544 ;
     RECT  55.001 19.056 56.408 19.56 ;
     RECT  55.753 21.12 56.408 22.392 ;
     RECT  56.329 23.52 56.408 35.736 ;
     RECT  55.861 37.584 56.408 38.376 ;
     RECT  55.753 39.408 56.408 39.912 ;
     RECT  55.189 40.944 56.408 40.968 ;
     RECT  56.408 2.148 56.512 41.052 ;
     RECT  56.512 2.418 56.585 40.968 ;
     RECT  56.585 2.418 56.704 40.782 ;
     RECT  56.704 23.568 56.837 23.592 ;
     RECT  56.704 34.752 56.867 35.736 ;
     RECT  56.704 30.432 56.873 33.672 ;
     RECT  56.704 20.976 56.909 22.584 ;
     RECT  56.051 0.096 57.013 0.408 ;
     RECT  56.704 24.912 57.017 29.16 ;
     RECT  56.873 33.024 57.017 33.672 ;
     RECT  57.013 0.048 57.053 0.408 ;
     RECT  57.017 25.008 57.125 29.16 ;
     RECT  56.704 10.032 57.155 19.8 ;
     RECT  56.704 5.04 57.197 7.416 ;
     RECT  57.125 25.008 57.197 27.432 ;
     RECT  57.197 25.008 57.233 26.28 ;
     RECT  57.233 25.008 57.305 26.232 ;
     RECT  57.155 12.768 57.413 19.8 ;
     RECT  57.197 5.04 57.449 6.84 ;
     RECT  56.909 22.272 57.485 22.584 ;
     RECT  57.053 0.048 57.491 0.168 ;
     RECT  57.305 25.056 57.493 26.232 ;
     RECT  57.413 12.768 57.557 18.216 ;
     RECT  57.197 27.408 57.665 27.432 ;
     RECT  57.125 28.416 57.788 29.16 ;
     RECT  56.873 30.432 57.788 31.992 ;
     RECT  57.788 28.416 57.841 31.992 ;
     RECT  57.017 33.024 57.841 33.048 ;
     RECT  57.449 5.184 57.845 6.84 ;
     RECT  57.841 28.416 57.875 33.048 ;
     RECT  56.909 20.976 57.877 21.144 ;
     RECT  57.485 22.272 57.877 22.296 ;
     RECT  57.845 6.624 57.881 6.84 ;
     RECT  57.493 25.056 57.923 25.704 ;
     RECT  56.867 34.752 57.985 34.92 ;
     RECT  57.491 0.144 58.021 0.168 ;
     RECT  56.704 3.36 58.061 3.96 ;
     RECT  57.875 30.144 58.097 33.048 ;
     RECT  58.021 0.144 58.129 0.264 ;
     RECT  57.985 34.128 58.133 34.92 ;
     RECT  56.704 8.832 58.165 8.856 ;
     RECT  58.129 0.144 58.201 0.504 ;
     RECT  57.845 5.184 58.205 5.592 ;
     RECT  58.097 32.496 58.241 33.048 ;
     RECT  57.877 20.976 58.309 22.296 ;
     RECT  56.089 42.912 58.373 43.08 ;
     RECT  58.201 0.144 58.451 0.552 ;
     RECT  58.165 8.592 58.453 8.856 ;
     RECT  57.155 10.032 58.453 11.784 ;
     RECT  57.557 14.112 58.529 18.216 ;
     RECT  57.777 23.616 58.547 23.64 ;
     RECT  57.557 12.768 58.637 13.08 ;
     RECT  58.453 8.592 58.669 11.784 ;
     RECT  58.309 20.88 58.705 22.296 ;
     RECT  58.529 14.112 58.709 17.88 ;
     RECT  57.875 28.416 58.777 29.16 ;
     RECT  58.637 12.768 58.781 12.792 ;
     RECT  58.061 3.36 58.787 3.384 ;
     RECT  56.704 38.736 58.789 38.952 ;
     RECT  58.748 39.984 58.789 40.008 ;
     RECT  58.669 8.448 58.813 11.784 ;
     RECT  58.789 38.736 58.835 40.008 ;
     RECT  58.709 16.08 58.883 17.88 ;
     RECT  58.813 8.448 58.897 12.072 ;
     RECT  58.897 10.992 58.925 12.072 ;
     RECT  58.133 34.32 58.957 34.92 ;
     RECT  58.957 34.32 58.997 35.352 ;
     RECT  58.373 42.144 58.997 43.08 ;
     RECT  58.835 38.736 59.065 39.432 ;
     RECT  58.709 14.112 59.137 14.904 ;
     RECT  58.777 27.888 59.209 29.16 ;
     RECT  58.097 30.144 59.209 31.128 ;
     RECT  58.925 10.992 59.249 11.784 ;
     RECT  58.205 5.184 59.285 5.208 ;
     RECT  59.209 40.992 59.293 41.016 ;
     RECT  59.209 27.888 59.309 31.128 ;
     RECT  57.923 25.056 59.317 25.08 ;
     RECT  58.705 20.832 59.353 22.296 ;
     RECT  59.137 13.824 59.357 14.904 ;
     RECT  59.317 23.904 59.401 25.08 ;
     RECT  57.413 19.248 59.413 19.8 ;
     RECT  59.353 20.832 59.413 22.344 ;
     RECT  59.413 19.248 59.461 22.344 ;
     RECT  59.309 27.888 59.461 31.368 ;
     RECT  59.461 27.888 59.497 31.8 ;
     RECT  58.241 33.024 59.497 33.048 ;
     RECT  59.461 18.912 59.5 22.344 ;
     RECT  58.451 0.144 59.651 0.504 ;
     RECT  58.777 26.832 59.736 26.856 ;
     RECT  59.756 5.088 59.785 5.112 ;
     RECT  58.997 34.32 59.785 34.344 ;
     RECT  59.736 26.256 59.797 26.856 ;
     RECT  59.497 27.888 59.797 33.048 ;
     RECT  58.897 8.448 59.825 9.672 ;
     RECT  59.785 4.896 59.843 5.112 ;
     RECT  59.785 34.128 59.845 34.344 ;
     RECT  59.825 8.592 59.861 9.672 ;
     RECT  59.5 18.912 59.861 19.8 ;
     RECT  59.797 26.256 59.861 33.048 ;
     RECT  59.861 19.008 59.897 19.8 ;
     RECT  59.5 20.784 59.897 22.344 ;
     RECT  59.065 38.112 59.965 39.432 ;
     RECT  58.883 16.08 60.005 17.448 ;
     RECT  59.357 14.112 60.037 14.904 ;
     RECT  60.005 16.08 60.037 16.152 ;
     RECT  60.005 17.184 60.037 17.448 ;
     RECT  59.401 25.056 60.073 25.08 ;
     RECT  59.861 26.256 60.073 29.544 ;
     RECT  59.845 34.08 60.073 34.344 ;
     RECT  58.997 35.328 60.073 35.352 ;
     RECT  60.037 14.112 60.149 16.152 ;
     RECT  59.897 19.248 60.149 19.8 ;
     RECT  60.073 34.08 60.157 35.352 ;
     RECT  58.777 36.912 60.181 36.936 ;
     RECT  60.073 25.056 60.185 29.544 ;
     RECT  60.181 36.912 60.221 37.08 ;
     RECT  59.861 30.576 60.293 33.048 ;
     RECT  60.293 31.872 60.325 33.048 ;
     RECT  60.325 31.872 60.373 33.096 ;
     RECT  60.157 34.08 60.373 34.104 ;
     RECT  57.881 6.624 60.397 6.648 ;
     RECT  58.997 42.96 60.397 43.08 ;
     RECT  60.373 31.872 60.409 34.104 ;
     RECT  60.409 33.072 60.46 34.104 ;
     RECT  59.249 11.376 60.505 11.784 ;
     RECT  60.149 19.536 60.517 19.8 ;
     RECT  59.897 20.784 60.517 21.432 ;
     RECT  60.46 33.072 60.545 33.096 ;
     RECT  60.149 14.112 60.577 14.952 ;
     RECT  60.577 13.632 60.613 14.952 ;
     RECT  60.221 37.056 60.653 37.08 ;
     RECT  60.397 42.912 60.821 43.08 ;
     RECT  60.185 28.224 60.829 29.544 ;
     RECT  60.293 30.576 60.829 30.6 ;
     RECT  59.401 23.904 60.865 23.928 ;
     RECT  59.861 8.736 60.937 9.672 ;
     RECT  60.505 11.376 60.937 11.976 ;
     RECT  60.001 22.752 60.937 22.776 ;
     RECT  60.865 23.76 60.937 23.928 ;
     RECT  60.157 35.328 60.937 35.352 ;
     RECT  60.937 8.736 61.052 11.976 ;
     RECT  60.613 13.056 61.052 14.952 ;
     RECT  59.651 0.144 61.141 0.264 ;
     RECT  60.397 6.624 61.153 6.792 ;
     RECT  60.185 25.056 61.153 26.856 ;
     RECT  60.829 28.224 61.153 30.6 ;
     RECT  60.149 16.08 61.333 16.152 ;
     RECT  60.937 22.752 61.361 23.928 ;
     RECT  60.037 17.184 61.369 17.88 ;
     RECT  61.141 0.144 61.397 0.504 ;
     RECT  60.517 19.536 61.405 21.432 ;
     RECT  61.361 22.752 61.405 23.976 ;
     RECT  60.821 42.144 61.445 43.08 ;
     RECT  61.369 17.184 61.549 18.024 ;
     RECT  61.052 8.736 61.585 14.952 ;
     RECT  61.333 15.984 61.585 16.152 ;
     RECT  61.585 8.736 61.649 16.152 ;
     RECT  61.549 17.184 61.649 18.216 ;
     RECT  59.843 4.896 61.808 4.92 ;
     RECT  61.153 6.624 61.808 6.888 ;
     RECT  61.649 8.736 61.808 18.216 ;
     RECT  61.405 19.536 61.808 23.976 ;
     RECT  61.153 25.056 61.808 30.6 ;
     RECT  60.409 31.872 61.808 31.896 ;
     RECT  60.46 34.08 61.808 34.104 ;
     RECT  60.937 35.328 61.808 36.024 ;
     RECT  59.965 38.112 61.808 39.912 ;
     RECT  61.808 2.148 61.912 41.052 ;
     RECT  61.912 2.418 62.104 40.782 ;
     RECT  62.104 38.736 62.165 39.336 ;
     RECT  62.104 14.112 62.387 14.136 ;
     RECT  62.104 6.624 62.435 6.888 ;
     RECT  62.104 27.888 62.777 29.256 ;
     RECT  62.104 9.792 62.813 13.08 ;
     RECT  62.104 17.232 62.813 21.432 ;
     RECT  61.445 42.192 62.821 43.08 ;
     RECT  62.104 8.496 62.849 8.52 ;
     RECT  62.813 9.792 62.849 11.976 ;
     RECT  62.104 36 62.849 36.024 ;
     RECT  62.813 13.056 63.097 13.08 ;
     RECT  62.104 15.264 63.097 16.008 ;
     RECT  62.104 25.056 63.101 26.28 ;
     RECT  62.104 23.328 63.133 24.024 ;
     RECT  63.101 25.68 63.281 26.28 ;
     RECT  62.821 42.144 63.281 43.08 ;
     RECT  61.397 0.144 63.299 0.552 ;
     RECT  63.253 40.416 63.389 40.44 ;
     RECT  62.435 6.864 63.569 6.888 ;
     RECT  62.813 17.232 63.637 18.408 ;
     RECT  63.629 40.992 63.713 41.016 ;
     RECT  63.281 26.16 63.781 26.28 ;
     RECT  62.849 10.128 63.817 11.976 ;
     RECT  63.097 13.056 63.817 13.128 ;
     RECT  63.097 14.4 63.817 16.008 ;
     RECT  63.781 26.16 63.853 26.616 ;
     RECT  63.133 23.328 63.857 24.696 ;
     RECT  63.817 10.128 63.925 16.008 ;
     RECT  63.637 17.04 63.925 18.408 ;
     RECT  62.165 39.216 63.961 39.336 ;
     RECT  63.853 26.16 64.001 26.904 ;
     RECT  63.817 36.432 64.069 36.456 ;
     RECT  63.857 23.376 64.145 24.696 ;
     RECT  63.529 9.072 64.421 9.096 ;
     RECT  63.925 10.128 64.421 18.408 ;
     RECT  64.421 9.072 64.429 18.408 ;
     RECT  62.813 19.536 64.429 21.432 ;
     RECT  64.145 23.76 64.609 24.696 ;
     RECT  64.069 36.432 64.609 37.032 ;
     RECT  64.453 41.568 64.613 41.592 ;
     RECT  64.609 23.76 64.645 24.984 ;
     RECT  62.104 30.576 64.645 30.6 ;
     RECT  62.104 34.08 64.645 34.104 ;
     RECT  64.645 33.648 64.685 34.104 ;
     RECT  64.645 30.24 64.691 30.6 ;
     RECT  64.685 33.648 64.729 33.96 ;
     RECT  64.645 23.76 64.799 25.176 ;
     RECT  64.001 26.16 64.799 26.808 ;
     RECT  64.691 30.24 64.883 30.264 ;
     RECT  62.777 28.704 64.901 29.256 ;
     RECT  64.837 40.992 64.937 41.016 ;
     RECT  64.429 9.072 64.969 21.432 ;
     RECT  63.299 0.144 65.009 0.264 ;
     RECT  64.799 23.76 65.077 26.808 ;
     RECT  63.281 43.056 65.113 43.08 ;
     RECT  64.969 9.072 65.123 21.528 ;
     RECT  64.609 36.048 65.225 37.032 ;
     RECT  65.077 23.76 65.257 27.048 ;
     RECT  65.123 9.072 65.267 17.64 ;
     RECT  65.257 23.76 65.293 27.336 ;
     RECT  64.901 28.704 65.293 28.728 ;
     RECT  65.113 42.192 65.315 43.08 ;
     RECT  65.267 9.072 65.333 12.312 ;
     RECT  65.293 23.76 65.333 28.728 ;
     RECT  65.257 22.752 65.363 22.776 ;
     RECT  65.333 9.6 65.369 12.312 ;
     RECT  65.333 27.024 65.441 28.728 ;
     RECT  63.961 39.216 65.557 39.528 ;
     RECT  65.267 13.584 65.585 17.64 ;
     RECT  65.123 18.768 65.603 21.528 ;
     RECT  65.557 39.168 65.603 39.528 ;
     RECT  62.104 4.896 65.621 4.92 ;
     RECT  65.585 15.36 65.621 17.64 ;
     RECT  65.603 19.44 65.621 21.528 ;
     RECT  65.557 38.016 65.644 38.04 ;
     RECT  65.333 23.76 65.657 25.896 ;
     RECT  65.441 27.312 65.801 28.728 ;
     RECT  65.603 39.168 65.829 39.24 ;
     RECT  65.657 24.384 65.837 25.896 ;
     RECT  65.315 42.96 65.873 43.08 ;
     RECT  65.621 15.792 65.945 17.64 ;
     RECT  65.369 10.032 66.017 12.312 ;
     RECT  65.945 15.792 66.053 17.496 ;
     RECT  65.837 25.008 66.053 25.896 ;
     RECT  65.829 39.168 66.089 39.192 ;
     RECT  66.044 5.088 66.131 5.736 ;
     RECT  65.225 36.048 66.481 36.072 ;
     RECT  65.749 37.536 66.481 37.608 ;
     RECT  66.017 10.608 66.589 12.312 ;
     RECT  65.585 13.584 66.589 14.328 ;
     RECT  66.053 15.792 66.661 17.448 ;
     RECT  65.621 19.488 66.661 21.528 ;
     RECT  66.409 22.8 66.661 22.824 ;
     RECT  66.469 40.464 66.833 40.488 ;
     RECT  65.009 0.24 66.853 0.264 ;
     RECT  66.661 19.488 66.949 22.824 ;
     RECT  66.833 40.464 67.057 41.016 ;
     RECT  66.053 25.872 67.093 25.896 ;
     RECT  67.093 25.488 67.201 25.896 ;
     RECT  66.956 3.936 67.208 3.96 ;
     RECT  66.131 5.088 67.208 5.112 ;
     RECT  66.445 6.864 67.208 6.888 ;
     RECT  65.149 8.016 67.208 8.04 ;
     RECT  66.481 9.6 67.208 9.624 ;
     RECT  66.589 10.608 67.208 14.328 ;
     RECT  66.661 15.312 67.208 17.448 ;
     RECT  66.949 18.816 67.208 22.824 ;
     RECT  67.201 24.912 67.208 25.896 ;
     RECT  65.801 27.312 67.208 27.336 ;
     RECT  65.801 28.704 67.208 28.728 ;
     RECT  64.729 33.936 67.208 33.96 ;
     RECT  66.481 36.048 67.208 37.608 ;
     RECT  66.913 38.688 67.208 38.712 ;
     RECT  67.057 40.128 67.208 41.016 ;
     RECT  65.873 43.056 67.285 43.08 ;
     RECT  67.208 2.148 67.312 41.052 ;
     RECT  67.312 2.418 67.504 41.016 ;
     RECT  67.504 33.792 67.601 33.96 ;
     RECT  67.504 10.608 67.66 14.328 ;
     RECT  67.66 10.608 67.667 13.464 ;
     RECT  67.504 39.216 67.745 41.016 ;
     RECT  67.504 24.912 67.781 28.584 ;
     RECT  67.781 25.008 67.811 28.584 ;
     RECT  67.504 31.92 67.825 31.944 ;
     RECT  67.504 15.312 68.105 17.448 ;
     RECT  67.504 8.976 68.141 9.624 ;
     RECT  67.504 35.28 68.332 37.608 ;
     RECT  67.504 3.936 68.429 5.112 ;
     RECT  68.332 36.144 68.429 37.608 ;
     RECT  67.504 6.672 68.677 7.416 ;
     RECT  67.811 25.104 68.713 28.584 ;
     RECT  67.745 39.216 68.78 40.152 ;
     RECT  68.429 3.936 68.785 4.632 ;
     RECT  68.713 25.104 68.785 28.68 ;
     RECT  68.78 39.216 68.789 40.584 ;
     RECT  67.667 10.608 68.821 13.368 ;
     RECT  67.504 18.912 68.821 23.544 ;
     RECT  68.677 6.672 68.857 7.896 ;
     RECT  68.785 25.056 68.857 28.68 ;
     RECT  68.429 36.864 68.869 37.608 ;
     RECT  68.857 24.528 68.876 28.68 ;
     RECT  68.105 16.512 68.917 17.448 ;
     RECT  68.821 18.432 68.917 23.544 ;
     RECT  67.285 42.96 68.933 43.08 ;
     RECT  68.917 16.512 68.963 23.544 ;
     RECT  68.876 24.528 68.963 29.208 ;
     RECT  68.821 10.608 69.061 14.232 ;
     RECT  69.061 10.224 69.077 14.232 ;
     RECT  68.857 6.624 69.109 7.896 ;
     RECT  68.105 15.312 69.109 15.336 ;
     RECT  68.963 16.512 69.113 18.456 ;
     RECT  69.109 5.76 69.149 7.896 ;
     RECT  69.077 10.224 69.149 13.704 ;
     RECT  69.109 14.784 69.149 15.336 ;
     RECT  68.963 25.728 69.185 28.776 ;
     RECT  68.789 40.128 69.253 40.584 ;
     RECT  67.504 2.832 69.289 2.856 ;
     RECT  68.785 3.84 69.289 4.632 ;
     RECT  68.963 19.536 69.325 23.544 ;
     RECT  68.963 24.528 69.325 24.696 ;
     RECT  69.149 10.608 69.401 13.704 ;
     RECT  69.253 40.128 69.509 41.016 ;
     RECT  69.289 2.832 69.541 4.632 ;
     RECT  69.113 16.512 69.577 18.216 ;
     RECT  69.541 2.256 69.587 4.632 ;
     RECT  66.853 0.096 69.685 0.264 ;
     RECT  68.141 8.976 69.685 9 ;
     RECT  69.685 8.976 69.769 9.096 ;
     RECT  69.149 7.296 69.781 7.896 ;
     RECT  69.185 25.728 69.797 28.728 ;
     RECT  69.587 2.256 69.833 2.28 ;
     RECT  69.587 3.36 69.833 4.632 ;
     RECT  69.401 10.608 69.833 13.416 ;
     RECT  69.149 14.784 69.833 14.808 ;
     RECT  69.577 16.368 69.937 18.216 ;
     RECT  69.833 3.792 69.938 4.632 ;
     RECT  69.325 19.536 69.941 24.696 ;
     RECT  68.869 36.864 69.98 38.184 ;
     RECT  69.685 41.568 70.037 41.592 ;
     RECT  68.933 43.056 70.037 43.08 ;
     RECT  69.98 36.096 70.067 38.184 ;
     RECT  69.685 0.096 70.069 0.36 ;
     RECT  69.833 13.344 70.229 13.416 ;
     RECT  70.069 0.096 70.477 0.408 ;
     RECT  70.067 36.768 70.517 38.184 ;
     RECT  69.797 25.728 70.553 27.384 ;
     RECT  70.037 41.568 70.553 43.08 ;
     RECT  69.938 3.84 70.621 4.632 ;
     RECT  69.149 5.76 70.621 6.264 ;
     RECT  69.833 10.608 70.643 12.264 ;
     RECT  69.781 7.296 70.693 7.944 ;
     RECT  67.601 33.792 70.693 33.816 ;
     RECT  70.693 33.792 70.733 33.912 ;
     RECT  70.477 0.096 70.931 0.552 ;
     RECT  70.553 42.144 70.957 43.08 ;
     RECT  70.693 7.296 70.981 7.992 ;
     RECT  69.769 8.976 70.981 9 ;
     RECT  70.981 7.296 71.021 9 ;
     RECT  69.941 19.536 71.053 24.648 ;
     RECT  70.621 3.84 71.077 6.264 ;
     RECT  71.021 7.296 71.129 8.232 ;
     RECT  70.931 0.144 71.233 0.552 ;
     RECT  71.129 7.296 71.273 7.992 ;
     RECT  71.233 0.144 71.317 0.648 ;
     RECT  70.643 11.088 71.341 12.264 ;
     RECT  70.229 13.344 71.341 13.368 ;
     RECT  71.341 11.088 71.377 13.368 ;
     RECT  70.909 14.64 71.377 14.664 ;
     RECT  71.077 3.408 71.453 6.264 ;
     RECT  71.377 11.088 71.489 14.664 ;
     RECT  70.553 26.304 71.593 27.384 ;
     RECT  71.489 11.088 71.597 12.888 ;
     RECT  71.593 26.256 71.629 27.384 ;
     RECT  69.797 28.704 71.629 28.728 ;
     RECT  71.453 5.76 71.809 6.264 ;
     RECT  71.489 13.92 71.809 14.664 ;
     RECT  71.053 19.536 71.953 24.744 ;
     RECT  71.629 26.256 71.953 28.728 ;
     RECT  69.509 40.128 72.085 40.152 ;
     RECT  71.453 3.408 72.097 4.584 ;
     RECT  72.085 40.128 72.236 40.968 ;
     RECT  71.597 11.088 72.373 12.552 ;
     RECT  71.953 19.536 72.385 28.728 ;
     RECT  72.097 3.312 72.421 4.584 ;
     RECT  72.38 30 72.449 30.024 ;
     RECT  71.809 5.76 72.469 6.36 ;
     RECT  70.517 36.768 72.469 37.608 ;
     RECT  72.469 5.712 72.493 6.36 ;
     RECT  72.421 2.88 72.529 4.584 ;
     RECT  72.493 5.712 72.529 6.84 ;
     RECT  72.053 1.728 72.608 1.752 ;
     RECT  72.529 2.88 72.608 6.84 ;
     RECT  71.273 7.968 72.608 7.992 ;
     RECT  71.053 9.504 72.608 9.528 ;
     RECT  72.373 10.848 72.608 12.552 ;
     RECT  71.809 13.92 72.608 15.24 ;
     RECT  69.937 16.224 72.608 18.216 ;
     RECT  72.385 19.536 72.608 28.824 ;
     RECT  72.449 30 72.608 30.744 ;
     RECT  72.469 32.304 72.608 32.328 ;
     RECT  70.733 33.888 72.608 33.912 ;
     RECT  72.469 36.096 72.608 37.608 ;
     RECT  72.236 39.408 72.608 40.968 ;
     RECT  72.608 1.728 72.901 41.052 ;
     RECT  72.901 1.728 72.904 41.16 ;
     RECT  72.904 1.728 72.947 1.752 ;
     RECT  71.317 0.144 73.001 0.552 ;
     RECT  72.904 18.192 73.037 21.432 ;
     RECT  72.904 3.312 73.181 15.24 ;
     RECT  73.181 3.84 73.289 15.24 ;
     RECT  72.904 40.128 73.325 41.16 ;
     RECT  73.289 3.84 73.361 12.216 ;
     RECT  72.904 22.464 73.577 29.112 ;
     RECT  73.325 41.136 73.577 41.16 ;
     RECT  70.957 42.96 73.645 43.08 ;
     RECT  73.037 18.192 73.685 19.56 ;
     RECT  73.289 13.392 73.708 15.24 ;
     RECT  73.708 13.488 73.721 15.24 ;
     RECT  73.361 3.936 73.756 12.216 ;
     RECT  73.756 3.984 73.763 12.216 ;
     RECT  73.645 42.192 73.763 43.08 ;
     RECT  73.037 20.544 73.897 21.432 ;
     RECT  73.577 22.464 73.897 28.824 ;
     RECT  73.763 3.984 74.081 10.536 ;
     RECT  73.685 18.768 74.081 19.56 ;
     RECT  72.904 31.248 74.101 34.2 ;
     RECT  72.904 37.44 74.101 37.608 ;
     RECT  73.721 13.536 74.113 15.24 ;
     RECT  72.904 16.56 74.113 17.208 ;
     RECT  74.113 13.536 74.125 17.208 ;
     RECT  74.081 3.984 74.153 7.656 ;
     RECT  74.081 18.816 74.185 19.56 ;
     RECT  73.897 20.544 74.185 28.824 ;
     RECT  74.101 31.248 74.221 34.824 ;
     RECT  74.125 14.88 74.225 17.208 ;
     RECT  74.225 14.88 74.261 15.24 ;
     RECT  73.001 0.144 74.485 0.312 ;
     RECT  74.221 30.72 74.509 34.824 ;
     RECT  72.904 36.096 74.509 36.12 ;
     RECT  74.081 8.736 74.549 10.536 ;
     RECT  74.125 13.536 74.585 13.608 ;
     RECT  74.225 16.56 74.617 17.208 ;
     RECT  72.904 39.072 74.621 39.096 ;
     RECT  74.185 18.816 74.657 28.824 ;
     RECT  74.485 0.144 74.689 0.408 ;
     RECT  74.657 25.68 74.693 28.824 ;
     RECT  74.657 18.816 74.723 24.696 ;
     RECT  73.763 12.192 74.761 12.216 ;
     RECT  74.617 16.56 74.761 17.496 ;
     RECT  74.761 11.616 74.833 12.216 ;
     RECT  74.585 13.536 74.833 13.56 ;
     RECT  74.693 25.68 74.909 26.664 ;
     RECT  73.325 40.128 74.909 40.152 ;
     RECT  74.689 0.048 74.917 0.408 ;
     RECT  74.723 22.464 74.963 24.696 ;
     RECT  74.153 3.984 74.981 7.416 ;
     RECT  74.963 22.464 75.017 23.16 ;
     RECT  74.963 24.144 75.017 24.696 ;
     RECT  74.509 30.72 75.169 36.12 ;
     RECT  74.261 15.216 75.193 15.24 ;
     RECT  74.761 16.56 75.193 17.64 ;
     RECT  74.981 6.816 75.253 7.416 ;
     RECT  75.193 15.216 75.265 17.64 ;
     RECT  74.723 18.816 75.265 21.432 ;
     RECT  75.017 24.144 75.269 24.36 ;
     RECT  74.101 37.344 75.301 37.608 ;
     RECT  74.549 8.736 75.305 9.528 ;
     RECT  74.981 3.984 75.337 5.832 ;
     RECT  74.549 10.512 75.337 10.536 ;
     RECT  74.833 11.616 75.337 13.56 ;
     RECT  75.337 3.408 75.413 5.832 ;
     RECT  75.169 32.976 75.413 36.12 ;
     RECT  74.693 27.888 75.445 28.824 ;
     RECT  75.413 32.976 75.485 35.064 ;
     RECT  75.253 6.816 75.553 7.608 ;
     RECT  75.305 8.736 75.553 9.432 ;
     RECT  75.553 6.816 75.557 9.432 ;
     RECT  75.445 27.888 75.625 29.64 ;
     RECT  75.169 30.72 75.625 31.896 ;
     RECT  74.909 26.208 75.733 26.664 ;
     RECT  75.625 27.888 75.733 31.896 ;
     RECT  75.413 3.408 75.737 5.256 ;
     RECT  75.017 23.04 75.737 23.16 ;
     RECT  74.917 40.944 75.737 41.016 ;
     RECT  75.301 37.344 75.769 37.896 ;
     RECT  75.737 40.992 75.845 41.016 ;
     RECT  74.917 0.048 75.877 0.456 ;
     RECT  75.265 15.216 75.877 21.432 ;
     RECT  75.337 10.512 75.881 13.56 ;
     RECT  75.733 26.208 75.953 31.896 ;
     RECT  75.877 14.832 75.989 21.432 ;
     RECT  75.737 3.408 76.025 5.208 ;
     RECT  75.557 6.816 76.025 9.384 ;
     RECT  75.881 10.848 76.057 13.56 ;
     RECT  75.989 14.832 76.057 14.856 ;
     RECT  76.025 3.936 76.067 5.208 ;
     RECT  76.057 10.848 76.133 14.856 ;
     RECT  76.025 6.816 76.165 7.416 ;
     RECT  76.165 6.288 76.169 7.416 ;
     RECT  73.763 42.96 76.273 43.08 ;
     RECT  76.133 10.848 76.307 12.744 ;
     RECT  76.133 13.728 76.321 14.856 ;
     RECT  76.169 7.344 76.349 7.416 ;
     RECT  75.769 37.344 76.493 38.712 ;
     RECT  76.349 7.392 76.529 7.416 ;
     RECT  75.877 0.048 76.547 0.552 ;
     RECT  75.485 33.072 76.547 35.064 ;
     RECT  76.273 42.144 76.547 43.08 ;
     RECT  76.547 33.072 76.817 33.624 ;
     RECT  75.413 36.096 76.885 36.12 ;
     RECT  75.989 15.984 76.925 21.432 ;
     RECT  76.547 35.04 76.931 35.064 ;
     RECT  75.953 26.592 76.94 31.896 ;
     RECT  75.269 24.336 76.957 24.36 ;
     RECT  76.94 25.68 76.957 31.896 ;
     RECT  76.025 8.496 76.961 9.384 ;
     RECT  76.925 16.08 76.981 21.432 ;
     RECT  76.067 4.368 76.997 4.536 ;
     RECT  76.981 16.08 77.029 22.056 ;
     RECT  76.547 42.912 77.033 43.08 ;
     RECT  76.957 24.336 77.173 31.896 ;
     RECT  76.547 0.048 77.363 0.456 ;
     RECT  77.317 41.568 77.401 41.592 ;
     RECT  76.307 10.848 77.461 12.552 ;
     RECT  77.029 16.08 77.489 22.776 ;
     RECT  77.173 24.336 77.489 31.992 ;
     RECT  77.461 10.848 77.509 12.744 ;
     RECT  76.321 14.304 77.509 14.856 ;
     RECT  76.169 6.288 77.533 6.312 ;
     RECT  76.493 37.536 77.557 38.712 ;
     RECT  77.245 40.464 77.557 40.488 ;
     RECT  77.509 10.848 77.641 14.856 ;
     RECT  76.997 4.512 77.701 4.536 ;
     RECT  76.961 8.496 77.701 8.52 ;
     RECT  76.885 36.096 77.701 36.264 ;
     RECT  77.557 37.536 77.701 40.488 ;
     RECT  77.363 0.048 77.891 0.36 ;
     RECT  77.641 9.984 77.893 14.856 ;
     RECT  77.489 16.08 77.893 31.992 ;
     RECT  77.701 4.512 78.008 5.16 ;
     RECT  77.533 6.288 78.008 6.84 ;
     RECT  77.701 8.4 78.008 8.52 ;
     RECT  77.893 9.984 78.008 31.992 ;
     RECT  76.817 33.072 78.008 33.384 ;
     RECT  77.701 36.096 78.008 40.488 ;
     RECT  78.008 2.148 78.112 41.208 ;
     RECT  78.112 2.418 78.22 41.208 ;
     RECT  78.22 2.418 78.304 41.016 ;
     RECT  78.304 34.512 78.401 35.208 ;
     RECT  78.304 15.984 78.473 21.048 ;
     RECT  77.033 42.96 78.505 43.08 ;
     RECT  78.473 15.984 78.509 20.952 ;
     RECT  78.304 9.504 78.563 12.312 ;
     RECT  78.505 42.144 78.589 43.08 ;
     RECT  78.304 37.44 78.617 39.288 ;
     RECT  78.304 27.888 78.689 33.432 ;
     RECT  78.689 28.128 78.797 33.432 ;
     RECT  78.304 4.512 78.905 4.536 ;
     RECT  78.401 34.512 78.941 35.064 ;
     RECT  78.509 15.984 78.947 20.904 ;
     RECT  78.947 15.984 79.049 18.024 ;
     RECT  78.941 34.656 79.085 35.064 ;
     RECT  78.304 36.24 79.121 36.312 ;
     RECT  77.891 0.144 79.141 0.36 ;
     RECT  79.049 16.896 79.157 18.024 ;
     RECT  78.797 31.44 79.229 33.432 ;
     RECT  78.797 28.128 79.235 30.264 ;
     RECT  78.947 19.968 79.265 20.904 ;
     RECT  78.304 14.4 79.297 14.52 ;
     RECT  78.304 13.296 79.333 13.32 ;
     RECT  79.297 14.4 79.333 15.432 ;
     RECT  78.304 22.032 79.337 26.856 ;
     RECT  79.085 34.704 79.337 35.064 ;
     RECT  78.304 40.992 79.409 41.016 ;
     RECT  79.388 7.776 79.429 7.8 ;
     RECT  79.429 7.776 79.475 8.568 ;
     RECT  79.337 22.032 79.513 25.224 ;
     RECT  79.337 26.208 79.513 26.856 ;
     RECT  79.333 13.296 79.553 15.432 ;
     RECT  78.617 37.584 79.585 39.288 ;
     RECT  79.513 26.208 79.619 26.904 ;
     RECT  78.563 10.176 79.661 12.312 ;
     RECT  79.229 31.44 79.697 33.336 ;
     RECT  79.121 36.288 79.717 36.312 ;
     RECT  79.585 37.584 79.717 39.384 ;
     RECT  79.661 10.848 79.765 12.312 ;
     RECT  79.765 10.848 79.811 13.08 ;
     RECT  79.157 17.088 79.945 18.024 ;
     RECT  78.589 43.056 80.101 43.08 ;
     RECT  79.657 3.936 80.125 3.96 ;
     RECT  79.553 14.256 80.125 15.432 ;
     RECT  79.945 17.088 80.125 18.792 ;
     RECT  79.619 26.4 80.161 26.904 ;
     RECT  79.235 28.128 80.161 29.112 ;
     RECT  79.235 30.144 80.197 30.264 ;
     RECT  79.697 31.44 80.197 31.8 ;
     RECT  79.475 8.4 80.269 8.568 ;
     RECT  79.265 20.304 80.3 20.904 ;
     RECT  80.161 26.4 80.309 29.112 ;
     RECT  79.337 34.704 80.341 34.968 ;
     RECT  79.717 36.288 80.345 39.384 ;
     RECT  80.125 3.936 80.377 4.68 ;
     RECT  79.141 0.048 80.381 0.36 ;
     RECT  80.309 28.128 80.417 29.112 ;
     RECT  80.345 36.288 80.435 37.032 ;
     RECT  80.381 0.144 80.485 0.36 ;
     RECT  80.269 8.4 80.485 9.528 ;
     RECT  80.3 19.92 80.485 20.904 ;
     RECT  79.513 21.936 80.485 25.224 ;
     RECT  79.697 32.832 80.521 33.336 ;
     RECT  80.341 34.32 80.521 34.968 ;
     RECT  80.125 14.256 80.561 18.792 ;
     RECT  80.492 2.832 80.579 2.856 ;
     RECT  80.485 0.144 80.605 0.456 ;
     RECT  80.377 3.936 80.633 5.016 ;
     RECT  80.521 32.832 80.633 34.968 ;
     RECT  80.485 19.92 80.636 25.224 ;
     RECT  79.811 12.288 80.701 13.08 ;
     RECT  80.561 14.256 80.701 18.264 ;
     RECT  80.636 19.92 80.723 25.368 ;
     RECT  80.197 30.144 80.813 31.8 ;
     RECT  80.633 4.944 80.821 5.016 ;
     RECT  79.811 10.848 80.849 11.304 ;
     RECT  80.701 12.288 80.885 18.264 ;
     RECT  80.101 42.96 80.909 43.08 ;
     RECT  80.309 26.4 80.921 26.808 ;
     RECT  80.849 10.848 80.965 10.968 ;
     RECT  80.821 4.944 81.013 5.16 ;
     RECT  79.621 6.24 81.013 6.264 ;
     RECT  80.921 26.4 81.025 26.568 ;
     RECT  80.965 10.56 81.052 10.968 ;
     RECT  80.485 8.16 81.061 9.528 ;
     RECT  80.723 19.92 81.1 25.128 ;
     RECT  80.345 38.304 81.205 39.384 ;
     RECT  81.205 38.304 81.245 39.96 ;
     RECT  80.633 32.832 81.281 34.92 ;
     RECT  81.1 19.92 81.313 22.344 ;
     RECT  81.281 32.832 81.317 34.344 ;
     RECT  80.909 42.912 81.349 43.08 ;
     RECT  81.061 7.776 81.389 9.528 ;
     RECT  81.317 32.832 81.389 33.912 ;
     RECT  80.633 3.936 81.395 3.96 ;
     RECT  81.389 7.776 81.395 7.992 ;
     RECT  80.417 28.128 81.457 28.2 ;
     RECT  80.813 30.768 81.457 31.8 ;
     RECT  81.389 32.832 81.457 33.576 ;
     RECT  80.876 1.152 81.491 1.176 ;
     RECT  81.421 12 81.505 12.024 ;
     RECT  81.013 4.944 81.529 6.264 ;
     RECT  80.885 13.008 81.565 18.264 ;
     RECT  81.313 19.488 81.565 22.344 ;
     RECT  81.025 26.208 81.605 26.568 ;
     RECT  81.349 42.192 81.641 43.08 ;
     RECT  81.529 4.944 81.709 6.696 ;
     RECT  81.395 7.776 81.709 7.8 ;
     RECT  81.565 13.008 81.713 22.344 ;
     RECT  80.435 36.288 81.713 36.312 ;
     RECT  81.457 30.768 81.731 33.576 ;
     RECT  80.605 0.144 81.733 0.168 ;
     RECT  81.1 23.328 81.781 25.128 ;
     RECT  81.605 26.208 81.781 26.424 ;
     RECT  81.457 28.128 81.781 28.44 ;
     RECT  81.685 29.616 81.781 29.64 ;
     RECT  81.245 38.304 81.889 38.712 ;
     RECT  81.713 13.008 81.893 14.472 ;
     RECT  81.731 30.96 81.929 33.576 ;
     RECT  81.893 13.008 82.001 14.28 ;
     RECT  81.781 28.128 82.021 29.64 ;
     RECT  81.781 23.328 82.073 26.424 ;
     RECT  82.001 13.968 82.109 14.28 ;
     RECT  81.709 4.944 82.145 7.8 ;
     RECT  81.713 15.456 82.433 22.344 ;
     RECT  81.929 32.928 82.465 33.576 ;
     RECT  81.389 9.12 82.501 9.384 ;
     RECT  81.733 0.144 82.537 0.312 ;
     RECT  82.021 28.128 82.537 29.688 ;
     RECT  82.145 4.992 82.565 7.8 ;
     RECT  82.501 9.12 82.565 9.48 ;
     RECT  82.465 1.728 82.595 1.752 ;
     RECT  82.565 4.992 82.597 9.48 ;
     RECT  82.537 41.568 82.621 41.592 ;
     RECT  82.433 15.744 82.645 22.344 ;
     RECT  82.073 24.096 82.645 26.424 ;
     RECT  82.537 27.984 82.645 29.688 ;
     RECT  82.609 3.024 82.717 3.048 ;
     RECT  81.889 38.256 82.861 38.712 ;
     RECT  81.245 39.936 82.861 39.96 ;
     RECT  81.929 30.96 82.897 31.896 ;
     RECT  81.641 42.912 82.933 43.08 ;
     RECT  81.052 10.848 82.969 10.968 ;
     RECT  82.897 30.912 83.005 31.896 ;
     RECT  82.933 42.144 83.017 43.08 ;
     RECT  81.889 35.568 83.113 35.592 ;
     RECT  82.645 24.096 83.149 29.688 ;
     RECT  82.645 15.744 83.173 22.536 ;
     RECT  83.149 24 83.173 29.688 ;
     RECT  82.597 4.992 83.185 9.528 ;
     RECT  82.969 10.848 83.185 11.448 ;
     RECT  83.173 15.744 83.185 29.688 ;
     RECT  83.005 30.864 83.185 31.896 ;
     RECT  82.109 13.968 83.269 14.232 ;
     RECT  82.717 3.024 83.293 3.432 ;
     RECT  82.537 0.144 83.363 0.552 ;
     RECT  83.017 42.912 83.369 43.08 ;
     RECT  83.293 3.024 83.408 3.864 ;
     RECT  83.185 4.992 83.408 11.448 ;
     RECT  83.269 13.92 83.408 14.232 ;
     RECT  83.185 15.744 83.408 31.896 ;
     RECT  82.465 32.928 83.408 33.624 ;
     RECT  83.113 35.328 83.408 35.592 ;
     RECT  82.861 38.256 83.408 39.96 ;
     RECT  83.408 2.148 83.512 41.052 ;
     RECT  83.512 2.418 83.704 41.052 ;
     RECT  83.704 37.584 83.717 41.052 ;
     RECT  83.704 3.024 83.765 4.152 ;
     RECT  83.704 16.56 83.765 26.136 ;
     RECT  83.363 0.144 83.795 0.408 ;
     RECT  83.717 37.584 83.801 41.16 ;
     RECT  83.765 3.84 83.837 4.152 ;
     RECT  83.704 5.808 83.873 13.08 ;
     RECT  83.765 19.392 84.053 26.136 ;
     RECT  83.837 3.84 84.131 3.96 ;
     RECT  83.873 7.2 84.275 13.08 ;
     RECT  83.765 16.56 84.341 17.928 ;
     RECT  83.704 30.432 84.371 31.416 ;
     RECT  84.053 20.592 84.385 26.136 ;
     RECT  83.704 36.432 84.413 36.456 ;
     RECT  83.801 37.584 84.563 40.248 ;
     RECT  83.369 42.96 84.565 43.08 ;
     RECT  83.704 14.208 84.593 15.192 ;
     RECT  84.341 16.992 84.629 17.928 ;
     RECT  84.563 37.584 84.652 38.184 ;
     RECT  84.385 20.592 84.665 22.584 ;
     RECT  84.565 42.144 84.665 43.08 ;
     RECT  84.545 1.728 84.697 1.752 ;
     RECT  84.593 14.4 84.707 15.192 ;
     RECT  84.053 19.392 84.773 19.416 ;
     RECT  84.275 7.2 84.947 12.552 ;
     RECT  84.629 16.992 84.947 17.208 ;
     RECT  84.947 10.8 84.953 12.552 ;
     RECT  84.697 1.728 84.997 2.52 ;
     RECT  84.131 3.84 84.997 3.864 ;
     RECT  84.953 10.8 85.025 11.976 ;
     RECT  84.947 16.992 85.025 17.112 ;
     RECT  83.873 5.808 85.093 6.024 ;
     RECT  84.997 1.728 85.097 3.864 ;
     RECT  83.704 27.36 85.097 28.44 ;
     RECT  84.385 24.144 85.237 26.136 ;
     RECT  84.652 38.16 85.277 38.184 ;
     RECT  84.563 39.312 85.313 40.248 ;
     RECT  85.237 24.144 85.324 26.424 ;
     RECT  85.313 40.224 85.333 40.248 ;
     RECT  84.949 41.568 85.333 41.592 ;
     RECT  85.097 1.728 85.385 3.576 ;
     RECT  85.324 24.144 85.385 25.752 ;
     RECT  83.704 33.6 85.385 34.248 ;
     RECT  85.309 31.632 85.409 31.656 ;
     RECT  84.985 15.984 85.417 16.008 ;
     RECT  85.333 40.224 85.421 41.592 ;
     RECT  85.409 31.632 85.493 32.472 ;
     RECT  84.665 20.784 85.525 22.584 ;
     RECT  84.371 30.432 85.561 30.456 ;
     RECT  85.493 31.632 85.561 31.656 ;
     RECT  85.525 20.784 85.564 23.064 ;
     RECT  84.985 35.328 85.573 35.352 ;
     RECT  85.573 35.328 85.619 35.976 ;
     RECT  85.619 35.952 85.66 35.976 ;
     RECT  85.421 40.224 85.745 41.016 ;
     RECT  84.665 43.056 85.765 43.08 ;
     RECT  85.385 2.496 85.853 3.576 ;
     RECT  85.093 5.28 85.885 6.024 ;
     RECT  85.561 30.432 85.885 31.656 ;
     RECT  85.853 3.552 85.889 3.576 ;
     RECT  85.385 33.6 86.005 33.624 ;
     RECT  85.564 21.024 86.051 23.064 ;
     RECT  85.885 29.856 86.051 31.656 ;
     RECT  85.025 10.944 86.137 11.976 ;
     RECT  86.005 32.976 86.213 33.624 ;
     RECT  86.137 10.944 86.293 12.264 ;
     RECT  85.417 19.776 86.317 19.8 ;
     RECT  83.795 0.144 86.348 0.264 ;
     RECT  85.885 4.896 86.353 6.024 ;
     RECT  84.947 7.2 86.353 9.72 ;
     RECT  85.385 24.576 86.393 25.752 ;
     RECT  86.051 29.856 86.393 30.744 ;
     RECT  86.348 0.048 86.435 0.264 ;
     RECT  86.393 24.576 86.461 25.512 ;
     RECT  85.417 15.984 86.497 16.584 ;
     RECT  86.435 0.144 86.533 0.264 ;
     RECT  86.213 32.976 86.533 33.336 ;
     RECT  85.853 2.496 86.609 2.52 ;
     RECT  85.745 40.272 86.617 41.016 ;
     RECT  86.461 24.336 86.645 25.512 ;
     RECT  86.497 15.984 86.677 16.968 ;
     RECT  86.645 25.104 86.681 25.512 ;
     RECT  85.097 27.888 86.713 28.44 ;
     RECT  86.681 25.44 86.753 25.512 ;
     RECT  86.677 15.984 86.785 17.688 ;
     RECT  86.051 21.12 86.825 23.064 ;
     RECT  86.393 30.576 86.897 30.744 ;
     RECT  86.785 15.984 86.929 17.832 ;
     RECT  86.533 0.144 86.932 0.312 ;
     RECT  86.293 10.896 86.933 12.264 ;
     RECT  86.749 26.592 86.965 26.616 ;
     RECT  85.765 42.96 86.965 43.08 ;
     RECT  86.933 11.952 87.001 12.264 ;
     RECT  86.677 13.968 87.001 13.992 ;
     RECT  86.897 30.72 87.005 30.744 ;
     RECT  86.825 21.648 87.037 23.064 ;
     RECT  86.713 27.744 87.037 28.44 ;
     RECT  86.965 42.144 87.049 43.08 ;
     RECT  86.965 26.592 87.068 26.664 ;
     RECT  87.037 27.744 87.068 28.728 ;
     RECT  86.929 15.408 87.073 17.832 ;
     RECT  86.317 19.392 87.073 19.8 ;
     RECT  86.353 4.896 87.113 9.72 ;
     RECT  87.113 7.2 87.116 9.72 ;
     RECT  86.933 10.896 87.116 10.968 ;
     RECT  87.116 7.2 87.149 10.968 ;
     RECT  87.149 8.784 87.185 10.968 ;
     RECT  87.113 4.896 87.205 6.024 ;
     RECT  86.533 31.728 87.217 33.336 ;
     RECT  87.073 15.408 87.229 19.8 ;
     RECT  87.205 4.416 87.365 6.024 ;
     RECT  86.753 25.488 87.469 25.512 ;
     RECT  87.068 26.592 87.469 28.728 ;
     RECT  86.617 40.272 87.473 40.968 ;
     RECT  87.473 40.272 87.505 40.296 ;
     RECT  87.001 11.952 87.541 13.992 ;
     RECT  86.932 0.144 87.685 0.36 ;
     RECT  87.365 4.416 87.721 5.304 ;
     RECT  87.217 31.728 87.721 33.624 ;
     RECT  87.577 36.432 87.733 36.456 ;
     RECT  85.849 37.584 87.733 37.608 ;
     RECT  87.685 0.144 87.757 0.504 ;
     RECT  87.541 11.952 87.793 14.136 ;
     RECT  87.229 15.408 87.793 16.968 ;
     RECT  87.733 36.432 87.833 37.608 ;
     RECT  87.469 25.488 87.865 28.728 ;
     RECT  87.973 30.384 88.009 30.408 ;
     RECT  87.721 31.536 88.009 33.624 ;
     RECT  87.185 10.512 88.045 10.968 ;
     RECT  87.793 11.952 88.045 16.968 ;
     RECT  87.037 21.648 88.117 23.592 ;
     RECT  88.045 10.512 88.153 16.968 ;
     RECT  87.865 25.488 88.153 29.064 ;
     RECT  88.009 30.384 88.153 33.624 ;
     RECT  88.117 21.648 88.225 24.456 ;
     RECT  88.153 25.488 88.225 33.624 ;
     RECT  88.225 21.648 88.333 33.624 ;
     RECT  87.721 4.368 88.357 5.304 ;
     RECT  87.149 7.2 88.357 7.656 ;
     RECT  87.185 8.784 88.357 9.24 ;
     RECT  87.833 36.432 88.369 37.032 ;
     RECT  87.049 42.912 88.549 43.08 ;
     RECT  87.757 0.144 88.595 0.552 ;
     RECT  88.357 4.368 88.657 9.24 ;
     RECT  88.153 10.224 88.657 16.968 ;
     RECT  87.229 18.144 88.657 19.8 ;
     RECT  88.657 4.368 88.801 19.8 ;
     RECT  88.801 4.368 88.808 20.328 ;
     RECT  88.333 21.504 88.808 33.624 ;
     RECT  88.369 35.712 88.808 37.032 ;
     RECT  87.505 39.84 88.808 40.296 ;
     RECT  88.808 2.148 88.912 41.052 ;
     RECT  88.595 0.144 89.027 0.504 ;
     RECT  88.912 2.418 89.104 40.782 ;
     RECT  89.104 8.832 89.165 34.392 ;
     RECT  89.165 9.504 89.201 34.392 ;
     RECT  89.104 3.936 89.219 5.208 ;
     RECT  89.104 6.288 89.273 6.408 ;
     RECT  89.201 9.504 89.273 34.104 ;
     RECT  89.219 5.136 89.381 5.208 ;
     RECT  89.273 6.384 89.489 6.408 ;
     RECT  89.273 21.504 89.561 34.104 ;
     RECT  89.273 9.504 89.597 20.328 ;
     RECT  89.597 17.424 89.633 20.328 ;
     RECT  89.561 21.648 89.705 34.104 ;
     RECT  89.219 3.936 89.788 3.96 ;
     RECT  89.381 5.136 89.849 5.16 ;
     RECT  89.705 21.648 89.885 28.248 ;
     RECT  89.597 9.504 90.101 15.864 ;
     RECT  89.885 21.648 90.101 28.152 ;
     RECT  88.549 42.144 90.281 43.08 ;
     RECT  89.633 17.856 90.284 20.328 ;
     RECT  90.101 21.648 90.389 26.04 ;
     RECT  89.705 31.104 90.421 34.104 ;
     RECT  89.104 36.912 90.493 37.896 ;
     RECT  89.104 39.312 90.493 40.296 ;
     RECT  89.027 0.144 90.565 0.456 ;
     RECT  90.493 36.912 90.565 40.296 ;
     RECT  90.421 31.104 90.569 34.44 ;
     RECT  90.565 36.912 90.569 40.872 ;
     RECT  90.101 10.896 90.605 15.864 ;
     RECT  90.605 11.232 90.677 15.864 ;
     RECT  90.569 31.104 90.821 32.04 ;
     RECT  90.569 36.912 90.821 36.936 ;
     RECT  90.284 17.856 90.889 20.472 ;
     RECT  90.101 27.024 90.889 28.152 ;
     RECT  89.705 29.376 90.889 29.4 ;
     RECT  90.889 17.376 90.961 20.472 ;
     RECT  90.569 33.216 91.001 34.44 ;
     RECT  90.569 38.208 91.037 40.872 ;
     RECT  90.389 24.096 91.069 26.04 ;
     RECT  90.889 27.024 91.069 29.4 ;
     RECT  90.961 17.04 91.141 20.472 ;
     RECT  91.141 16.896 91.177 20.472 ;
     RECT  90.389 21.648 91.177 22.488 ;
     RECT  90.821 31.104 91.213 31.416 ;
     RECT  91.213 30.912 91.321 31.416 ;
     RECT  90.281 42.96 91.381 43.08 ;
     RECT  90.677 11.232 91.433 15.384 ;
     RECT  91.381 42.144 91.577 43.08 ;
     RECT  91.001 33.216 91.613 34.104 ;
     RECT  91.037 38.208 91.613 38.616 ;
     RECT  91.433 12.24 91.645 15.384 ;
     RECT  91.645 12.24 91.681 15.48 ;
     RECT  91.069 24.096 91.681 29.4 ;
     RECT  91.321 30.864 91.681 31.416 ;
     RECT  91.681 12.24 91.685 15.768 ;
     RECT  90.565 0.144 91.753 0.504 ;
     RECT  91.681 24.096 91.753 31.416 ;
     RECT  91.177 16.896 91.789 22.488 ;
     RECT  91.753 23.664 91.789 31.416 ;
     RECT  91.645 32.928 91.789 33.096 ;
     RECT  91.685 15.456 91.793 15.768 ;
     RECT  91.789 16.896 91.801 33.096 ;
     RECT  91.801 27.6 91.865 33.096 ;
     RECT  91.613 34.08 92.009 34.104 ;
     RECT  91.037 39.6 92.009 40.872 ;
     RECT  90.101 9.504 92.113 9.528 ;
     RECT  91.433 11.232 92.113 11.256 ;
     RECT  91.801 16.896 92.153 26.616 ;
     RECT  91.793 15.696 92.221 15.768 ;
     RECT  92.153 16.896 92.221 18.888 ;
     RECT  92.113 9.504 92.225 11.256 ;
     RECT  91.613 38.592 92.255 38.616 ;
     RECT  92.009 39.6 92.255 40.296 ;
     RECT  92.255 38.592 92.339 40.296 ;
     RECT  89.104 35.712 92.365 35.736 ;
     RECT  92.221 15.696 92.477 18.888 ;
     RECT  92.225 9.504 92.533 9.528 ;
     RECT  91.685 12.24 92.585 14.376 ;
     RECT  91.865 27.6 92.593 33.048 ;
     RECT  92.225 11.232 92.617 11.256 ;
     RECT  92.585 12.24 92.617 13.56 ;
     RECT  92.533 9.12 92.675 9.528 ;
     RECT  92.365 35.712 92.677 35.928 ;
     RECT  92.677 34.512 92.723 35.928 ;
     RECT  92.723 34.512 92.765 35.304 ;
     RECT  92.153 19.872 92.833 26.616 ;
     RECT  92.593 27.6 92.833 30.888 ;
     RECT  92.477 15.744 92.873 18.888 ;
     RECT  92.593 31.872 92.915 33.048 ;
     RECT  92.833 19.872 92.945 30.888 ;
     RECT  92.873 15.744 93.017 18.84 ;
     RECT  92.765 35.088 93.017 35.304 ;
     RECT  91.577 42.192 93.052 43.08 ;
     RECT  92.915 32.256 93.053 33.048 ;
     RECT  93.017 15.744 93.197 17.544 ;
     RECT  91.753 0.144 93.233 0.552 ;
     RECT  92.339 39.024 93.365 40.296 ;
     RECT  93.233 0.144 93.443 0.504 ;
     RECT  92.005 37.056 93.661 37.08 ;
     RECT  93.365 39.024 93.769 41.016 ;
     RECT  93.769 39.024 93.853 41.592 ;
     RECT  92.617 11.232 93.877 13.56 ;
     RECT  92.945 22.464 93.949 30.888 ;
     RECT  93.877 11.232 93.983 13.944 ;
     RECT  92.675 9.408 94.069 9.528 ;
     RECT  93.337 7.968 94.093 7.992 ;
     RECT  94.069 8.976 94.093 9.528 ;
     RECT  93.017 18.768 94.093 18.84 ;
     RECT  92.945 19.872 94.093 21.432 ;
     RECT  93.052 42.96 94.124 43.08 ;
     RECT  93.836 6.816 94.129 6.84 ;
     RECT  94.093 7.968 94.129 9.528 ;
     RECT  93.661 5.472 94.208 5.496 ;
     RECT  94.129 6.816 94.208 9.528 ;
     RECT  93.983 11.232 94.208 14.136 ;
     RECT  93.197 15.792 94.208 17.544 ;
     RECT  94.093 18.768 94.208 21.432 ;
     RECT  93.949 22.464 94.208 31.704 ;
     RECT  93.053 33.024 94.208 33.048 ;
     RECT  93.017 35.28 94.208 35.304 ;
     RECT  93.661 36.912 94.208 37.08 ;
     RECT  93.853 39.024 94.208 41.052 ;
     RECT  94.124 42.192 94.211 43.08 ;
     RECT  94.208 2.148 94.312 41.052 ;
     RECT  94.312 2.418 94.504 41.016 ;
     RECT  93.443 0.144 94.597 0.312 ;
     RECT  94.504 20.208 94.684 31.704 ;
     RECT  94.684 20.208 94.691 24.504 ;
     RECT  94.597 0.144 94.739 1.176 ;
     RECT  94.504 11.232 94.739 18.168 ;
     RECT  94.739 11.232 94.781 16.584 ;
     RECT  94.691 20.208 94.781 21.24 ;
     RECT  94.504 39.216 94.817 41.016 ;
     RECT  94.781 11.232 94.889 15.192 ;
     RECT  94.684 25.776 94.889 31.704 ;
     RECT  94.781 16.56 94.997 16.584 ;
     RECT  94.781 20.928 94.997 21.24 ;
     RECT  94.739 17.664 95.105 18.168 ;
     RECT  94.504 36.912 95.171 37.848 ;
     RECT  94.997 20.928 95.177 21.192 ;
     RECT  94.691 22.224 95.249 24.504 ;
     RECT  95.177 20.928 95.393 21 ;
     RECT  94.889 25.776 95.573 28.536 ;
     RECT  94.504 7.248 95.605 7.464 ;
     RECT  94.504 8.448 95.605 10.2 ;
     RECT  95.605 7.248 95.651 10.2 ;
     RECT  94.889 11.232 95.651 12.168 ;
     RECT  95.651 9.36 95.677 10.2 ;
     RECT  95.573 25.776 95.677 27.912 ;
     RECT  94.817 40.032 95.717 41.016 ;
     RECT  94.889 13.296 95.747 15.192 ;
     RECT  94.504 33.072 95.749 35.448 ;
     RECT  94.211 42.96 95.756 43.08 ;
     RECT  94.889 29.76 95.821 31.704 ;
     RECT  95.749 32.832 95.821 35.448 ;
     RECT  95.756 42.192 95.843 43.08 ;
     RECT  95.747 13.296 95.857 14.136 ;
     RECT  95.821 29.76 95.929 35.448 ;
     RECT  95.717 40.032 95.929 40.872 ;
     RECT  95.677 25.44 95.933 27.912 ;
     RECT  95.393 20.928 96.037 20.952 ;
     RECT  94.739 0.144 96.041 0.552 ;
     RECT  96.037 20.592 96.077 20.952 ;
     RECT  95.929 29.088 96.113 35.448 ;
     RECT  95.929 39.312 96.181 40.872 ;
     RECT  95.171 37.008 96.185 37.848 ;
     RECT  96.113 29.328 96.217 35.448 ;
     RECT  95.249 22.224 96.253 24.216 ;
     RECT  95.933 25.44 96.253 26.52 ;
     RECT  95.747 15.168 96.284 15.192 ;
     RECT  96.145 16.512 96.284 16.536 ;
     RECT  95.857 13.104 96.293 14.136 ;
     RECT  95.651 7.248 96.361 8.088 ;
     RECT  96.284 15.168 96.371 16.536 ;
     RECT  96.253 22.224 96.4 26.52 ;
     RECT  96.4 22.176 96.401 26.52 ;
     RECT  96.293 13.104 96.445 13.128 ;
     RECT  94.504 3.408 96.473 5.688 ;
     RECT  96.401 22.176 96.508 24.552 ;
     RECT  96.181 39.024 96.611 40.872 ;
     RECT  96.185 37.008 96.617 37.608 ;
     RECT  96.361 6.912 96.793 8.088 ;
     RECT  95.933 27.6 96.821 27.912 ;
     RECT  96.473 3.408 96.833 3.96 ;
     RECT  96.473 5.664 96.833 5.688 ;
     RECT  95.677 9.36 96.851 10.44 ;
     RECT  96.851 9.552 97.009 10.44 ;
     RECT  95.105 18.144 97.009 18.168 ;
     RECT  96.293 14.112 97.153 14.136 ;
     RECT  96.371 15.168 97.153 15.192 ;
     RECT  97.153 14.112 97.193 15.192 ;
     RECT  97.193 14.112 97.229 15.048 ;
     RECT  97.009 17.616 97.253 18.168 ;
     RECT  96.217 29.328 97.297 35.88 ;
     RECT  96.617 37.008 97.297 37.56 ;
     RECT  96.821 27.6 97.381 28.008 ;
     RECT  97.297 29.328 97.381 37.56 ;
     RECT  96.371 16.512 97.441 16.536 ;
     RECT  97.253 17.616 97.441 18.312 ;
     RECT  96.793 6.864 97.573 8.088 ;
     RECT  96.401 26.496 97.585 26.52 ;
     RECT  97.585 26.208 97.625 26.52 ;
     RECT  95.843 43.056 97.657 43.08 ;
     RECT  96.611 39.024 97.693 39.336 ;
     RECT  97.381 27.6 97.697 37.56 ;
     RECT  96.041 0.144 97.801 0.456 ;
     RECT  97.697 27.6 97.805 32.952 ;
     RECT  97.801 0.144 97.885 1.176 ;
     RECT  96.833 3.84 97.909 3.96 ;
     RECT  96.077 20.592 97.909 20.616 ;
     RECT  96.508 22.416 98.003 24.552 ;
     RECT  97.909 3.408 98.053 3.96 ;
     RECT  97.441 16.512 98.053 18.696 ;
     RECT  97.573 6.672 98.089 8.424 ;
     RECT  97.009 9.552 98.089 10.92 ;
     RECT  98.053 3.408 98.125 4.488 ;
     RECT  98.089 6.672 98.125 10.92 ;
     RECT  95.651 12.048 98.125 12.072 ;
     RECT  97.981 13.056 98.161 13.08 ;
     RECT  98.053 16.272 98.161 18.696 ;
     RECT  97.909 20.256 98.161 20.616 ;
     RECT  97.625 26.208 98.161 26.232 ;
     RECT  98.161 13.056 98.197 13.128 ;
     RECT  97.229 14.208 98.197 15.048 ;
     RECT  97.657 42.192 98.197 43.08 ;
     RECT  97.885 0.144 98.281 0.6 ;
     RECT  98.161 16.272 98.305 20.616 ;
     RECT  98.003 22.992 98.381 24.552 ;
     RECT  98.197 13.056 98.483 15.048 ;
     RECT  98.483 14.976 98.492 15.048 ;
     RECT  98.305 16.272 98.492 21.144 ;
     RECT  98.125 6.672 98.521 12.072 ;
     RECT  98.492 14.976 98.593 21.144 ;
     RECT  98.593 14.976 98.633 21.768 ;
     RECT  97.729 37.632 98.633 37.752 ;
     RECT  98.197 42.144 98.713 43.08 ;
     RECT  97.805 32.496 98.732 32.952 ;
     RECT  97.697 33.936 98.732 36.6 ;
     RECT  98.125 3.408 99.013 4.536 ;
     RECT  99.013 3.408 99.025 4.872 ;
     RECT  97.805 27.6 99.241 31.368 ;
     RECT  99.025 3.408 99.349 5.112 ;
     RECT  98.521 6.24 99.349 12.072 ;
     RECT  98.381 22.992 99.385 23.592 ;
     RECT  96.611 40.56 99.397 40.872 ;
     RECT  97.693 39.024 99.493 39.528 ;
     RECT  99.493 38.736 99.565 39.528 ;
     RECT  99.397 40.56 99.565 41.016 ;
     RECT  98.629 1.728 99.608 1.752 ;
     RECT  99.349 3.408 99.608 12.072 ;
     RECT  98.483 13.056 99.608 13.608 ;
     RECT  98.633 14.976 99.608 17.88 ;
     RECT  98.633 19.488 99.608 21.768 ;
     RECT  99.385 22.752 99.608 23.592 ;
     RECT  98.845 24.624 99.608 24.648 ;
     RECT  98.161 25.776 99.608 26.232 ;
     RECT  99.241 27.6 99.608 31.416 ;
     RECT  98.732 32.496 99.608 36.6 ;
     RECT  98.633 37.632 99.608 37.656 ;
     RECT  99.565 38.736 99.608 41.016 ;
     RECT  99.608 1.728 99.712 41.052 ;
     RECT  98.713 42.192 99.829 43.08 ;
     RECT  99.712 1.728 99.904 40.872 ;
     RECT  99.904 1.728 99.965 2.232 ;
     RECT  99.829 42.144 100.037 43.08 ;
     RECT  99.904 13.008 100.115 24.648 ;
     RECT  100.115 13.008 100.145 14.424 ;
     RECT  99.904 25.68 100.325 37.512 ;
     RECT  99.904 10.08 100.541 11.784 ;
     RECT  99.904 38.736 100.649 40.872 ;
     RECT  100.145 13.008 100.721 14.28 ;
     RECT  100.649 38.736 100.721 39.336 ;
     RECT  100.115 15.792 100.757 24.648 ;
     RECT  100.325 25.68 100.793 31.896 ;
     RECT  100.793 25.68 100.829 27.288 ;
     RECT  99.904 6.24 100.897 8.808 ;
     RECT  100.897 6.24 100.924 9.528 ;
     RECT  100.924 6.864 100.937 9.528 ;
     RECT  100.757 23.28 100.937 24.648 ;
     RECT  100.793 28.464 100.937 31.896 ;
     RECT  100.325 33.072 100.937 37.512 ;
     RECT  100.541 10.8 100.969 11.784 ;
     RECT  100.721 13.008 100.969 14.232 ;
     RECT  100.757 15.84 101.009 21.72 ;
     RECT  100.649 40.56 101.185 40.872 ;
     RECT  101.009 15.84 101.189 21.672 ;
     RECT  99.965 2.208 101.225 2.232 ;
     RECT  101.189 15.84 101.261 19.848 ;
     RECT  100.937 28.704 101.329 31.896 ;
     RECT  100.969 10.8 101.333 14.232 ;
     RECT  99.904 3.408 101.405 5.16 ;
     RECT  101.333 11.424 101.411 14.232 ;
     RECT  101.411 11.424 101.459 13.704 ;
     RECT  101.185 40.56 101.459 41.064 ;
     RECT  100.721 39.024 101.513 39.336 ;
     RECT  101.459 13.248 101.549 13.704 ;
     RECT  100.937 7.344 101.621 9.528 ;
     RECT  100.829 25.68 101.621 27.096 ;
     RECT  100.937 23.328 101.653 24.648 ;
     RECT  101.621 25.68 101.653 26.808 ;
     RECT  101.261 18.432 101.657 19.848 ;
     RECT  101.189 20.88 101.801 21.672 ;
     RECT  101.405 3.84 101.869 5.16 ;
     RECT  100.937 33.072 101.891 36.552 ;
     RECT  101.549 13.248 101.909 13.56 ;
     RECT  101.801 21.648 101.977 21.672 ;
     RECT  101.977 21.648 101.989 22.296 ;
     RECT  101.653 23.328 101.989 26.808 ;
     RECT  101.621 9.12 102.013 9.528 ;
     RECT  101.329 28.704 102.053 31.944 ;
     RECT  101.261 15.84 102.125 16.68 ;
     RECT  101.621 7.344 102.157 8.04 ;
     RECT  101.657 18.72 102.157 19.848 ;
     RECT  102.053 29.088 102.157 31.944 ;
     RECT  101.891 33.072 102.157 36.456 ;
     RECT  102.013 9.12 102.161 9.864 ;
     RECT  101.869 3.84 102.193 5.256 ;
     RECT  102.229 1.728 102.313 1.752 ;
     RECT  102.193 3.84 102.341 5.832 ;
     RECT  102.341 4.128 102.409 5.832 ;
     RECT  102.157 6.816 102.409 8.04 ;
     RECT  102.157 29.088 102.485 36.456 ;
     RECT  101.513 39.312 102.517 39.336 ;
     RECT  101.459 40.56 102.517 41.016 ;
     RECT  101.459 11.424 102.553 12.216 ;
     RECT  102.409 4.128 102.629 8.04 ;
     RECT  98.281 0.144 102.659 0.552 ;
     RECT  100.037 42.96 102.659 43.08 ;
     RECT  102.629 8.016 102.661 8.04 ;
     RECT  102.161 9.12 102.661 9.72 ;
     RECT  102.125 15.984 102.661 16.68 ;
     RECT  102.517 39.312 102.665 41.016 ;
     RECT  102.485 29.28 102.701 36.456 ;
     RECT  101.989 21.648 102.773 26.808 ;
     RECT  102.701 31.152 102.773 36.456 ;
     RECT  102.665 39.312 102.773 39.336 ;
     RECT  102.773 21.648 102.809 24.648 ;
     RECT  102.157 18.72 102.877 20.664 ;
     RECT  102.809 21.648 102.877 24.024 ;
     RECT  102.773 31.344 103.025 36.456 ;
     RECT  102.661 8.016 103.129 9.72 ;
     RECT  102.553 11.136 103.129 12.552 ;
     RECT  102.629 4.128 103.205 6.84 ;
     RECT  102.661 15.984 103.237 17.16 ;
     RECT  102.773 25.824 103.237 26.808 ;
     RECT  102.665 40.56 103.277 41.016 ;
     RECT  103.025 31.392 103.313 36.456 ;
     RECT  102.193 37.872 103.313 37.896 ;
     RECT  103.313 31.392 103.331 35.304 ;
     RECT  103.237 15.984 103.417 17.688 ;
     RECT  103.409 2.928 103.493 2.952 ;
     RECT  103.331 31.392 103.529 34.632 ;
     RECT  103.313 36.432 103.529 36.456 ;
     RECT  103.277 40.944 103.601 41.016 ;
     RECT  102.701 29.28 103.669 29.64 ;
     RECT  103.237 25.824 103.705 27.144 ;
     RECT  103.705 25.824 103.709 27.912 ;
     RECT  103.669 29.28 103.709 30.216 ;
     RECT  103.417 37.632 103.715 37.656 ;
     RECT  103.417 15.984 103.741 17.736 ;
     RECT  102.877 18.72 103.741 24.024 ;
     RECT  102.659 43.056 103.772 43.08 ;
     RECT  103.205 5.232 103.781 6.84 ;
     RECT  103.709 29.472 103.781 30.216 ;
     RECT  102.659 0.144 103.805 0.168 ;
     RECT  103.781 5.232 103.853 5.544 ;
     RECT  103.129 8.016 103.861 12.552 ;
     RECT  103.861 8.016 103.868 13.128 ;
     RECT  103.805 0.144 103.889 0.264 ;
     RECT  103.436 3.936 103.907 3.96 ;
     RECT  103.853 5.52 103.925 5.544 ;
     RECT  103.781 6.816 103.955 6.84 ;
     RECT  103.868 7.824 103.955 13.128 ;
     RECT  103.741 15.984 103.997 24.024 ;
     RECT  103.529 31.392 103.997 34.44 ;
     RECT  103.997 31.392 104.005 34.344 ;
     RECT  103.997 15.984 104.029 22.488 ;
     RECT  103.955 8.304 104.033 13.128 ;
     RECT  103.781 30.192 104.06 30.216 ;
     RECT  104.005 31.296 104.06 34.344 ;
     RECT  103.709 25.824 104.209 25.848 ;
     RECT  104.033 11.952 104.281 13.128 ;
     RECT  102.697 14.304 104.281 14.328 ;
     RECT  104.281 11.952 104.605 14.328 ;
     RECT  104.029 15.504 104.605 22.488 ;
     RECT  103.772 42.192 104.675 43.08 ;
     RECT  104.209 25.056 104.725 25.848 ;
     RECT  103.709 27.072 104.725 27.912 ;
     RECT  104.033 8.304 105.008 10.92 ;
     RECT  104.605 11.952 105.008 22.488 ;
     RECT  103.997 23.568 105.008 23.928 ;
     RECT  104.725 25.056 105.008 27.912 ;
     RECT  104.06 30.192 105.008 34.344 ;
     RECT  103.601 40.992 105.008 41.016 ;
     RECT  105.008 2.148 105.112 41.052 ;
     RECT  105.112 2.418 105.304 40.782 ;
     RECT  103.889 0.144 106.013 0.168 ;
     RECT  104.675 43.056 106.013 43.08 ;
    LAYER M5 ;
     RECT  1.392 0.016 104.664 0.131 ;
     RECT  1.776 0.131 15.864 0.179 ;
     RECT  17.04 0.131 32.328 0.179 ;
     RECT  33.504 0.131 51.24 0.179 ;
     RECT  52.416 0.131 104.664 0.179 ;
     RECT  1.776 0.179 15.48 0.227 ;
     RECT  17.04 0.179 21.096 0.227 ;
     RECT  33.936 0.179 44.856 0.227 ;
     RECT  45.984 0.179 50.808 0.227 ;
     RECT  7.008 0.227 15.48 0.275 ;
     RECT  22.128 0.179 32.328 0.275 ;
     RECT  52.416 0.179 66.504 0.275 ;
     RECT  69.696 0.179 104.664 0.275 ;
     RECT  69.696 0.275 96.216 0.323 ;
     RECT  69.696 0.323 72.936 0.371 ;
     RECT  74.496 0.323 75.336 0.371 ;
     RECT  82.56 0.323 87 0.371 ;
     RECT  88.176 0.323 96.216 0.371 ;
     RECT  97.392 0.275 104.664 0.371 ;
     RECT  70.08 0.371 72.936 0.419 ;
     RECT  74.496 0.371 75.144 0.419 ;
     RECT  82.56 0.371 86.424 0.419 ;
     RECT  88.176 0.371 89.304 0.419 ;
     RECT  90.576 0.371 96.216 0.419 ;
     RECT  34.32 0.227 44.856 0.515 ;
     RECT  52.416 0.275 61.656 0.515 ;
     RECT  90.576 0.419 96.024 0.515 ;
     RECT  17.04 0.227 19.896 0.563 ;
     RECT  25.872 0.275 32.328 0.563 ;
     RECT  34.32 0.515 34.344 0.563 ;
     RECT  35.52 0.515 44.856 0.563 ;
     RECT  52.416 0.515 55.656 0.563 ;
     RECT  56.832 0.515 61.656 0.563 ;
     RECT  62.832 0.275 66.504 0.563 ;
     RECT  76.512 0.323 81.48 0.563 ;
     RECT  82.56 0.419 83.352 0.563 ;
     RECT  88.56 0.419 89.304 0.563 ;
     RECT  91.392 0.515 92.568 0.563 ;
     RECT  94.08 0.515 96.024 0.563 ;
     RECT  97.392 0.371 100.632 0.563 ;
     RECT  101.856 0.371 104.664 0.563 ;
     RECT  7.392 0.275 15.48 0.611 ;
     RECT  36.48 0.563 40.392 0.611 ;
     RECT  70.512 0.419 72.936 0.659 ;
     RECT  7.392 0.611 9.048 1.139 ;
     RECT  94.08 0.563 94.728 1.187 ;
     RECT  8.256 1.139 8.616 1.763 ;
     RECT  10.224 0.611 10.632 1.763 ;
     RECT  12.24 0.611 15.48 1.763 ;
     RECT  22.128 0.275 24.696 1.763 ;
     RECT  41.568 0.563 43.176 1.763 ;
     RECT  52.416 0.563 55.224 1.763 ;
     RECT  71.712 0.659 72.936 1.763 ;
     RECT  82.56 0.563 83.304 1.763 ;
     RECT  84.576 0.419 86.424 1.763 ;
     RECT  102.24 0.563 104.664 1.763 ;
     RECT  55.056 1.763 55.224 1.859 ;
     RECT  8.256 1.763 8.376 2.137 ;
     RECT  29.136 0.563 29.16 2.137 ;
     RECT  30.336 0.563 32.328 2.137 ;
     RECT  36.48 0.611 40.056 2.137 ;
     RECT  44.352 0.563 44.856 2.137 ;
     RECT  46.08 0.227 50.808 2.137 ;
     RECT  56.832 0.563 57.672 2.137 ;
     RECT  58.848 0.563 61.656 2.137 ;
     RECT  63.072 0.563 66.504 2.137 ;
     RECT  67.632 0.179 68.52 2.137 ;
     RECT  82.944 1.763 83.304 2.137 ;
     RECT  103.056 1.763 104.664 2.137 ;
     RECT  34.8 2.137 34.92 2.151 ;
     RECT  36.48 2.137 40.32 2.151 ;
     RECT  44.352 2.137 51.12 2.151 ;
     RECT  58.848 2.137 61.92 2.151 ;
     RECT  63.072 2.137 68.52 2.151 ;
     RECT  82.944 2.137 83.52 2.151 ;
     RECT  103.056 2.137 105.12 2.151 ;
     RECT  21.072 0.227 21.096 2.245 ;
     RECT  22.128 1.763 22.152 2.245 ;
     RECT  70.512 0.659 70.536 2.245 ;
     RECT  10.608 1.763 10.632 2.291 ;
     RECT  27.072 0.563 27.912 2.629 ;
     RECT  44.352 2.151 51.312 2.773 ;
     RECT  103.056 2.151 105.312 2.963 ;
     RECT  85.008 1.763 86.424 3.155 ;
     RECT  17.424 0.563 19.896 3.299 ;
     RECT  58.848 2.151 68.52 3.349 ;
     RECT  69.552 2.245 70.536 3.397 ;
     RECT  71.712 1.763 72.912 3.397 ;
     RECT  95.856 0.563 96.024 3.397 ;
     RECT  97.392 0.563 100.152 3.397 ;
     RECT  21.072 2.245 22.152 3.443 ;
     RECT  4.176 0.227 5.832 3.733 ;
     RECT  69.552 3.397 72.912 3.827 ;
     RECT  4.08 3.733 5.832 3.829 ;
     RECT  17.424 3.299 19.848 3.925 ;
     RECT  29.136 2.137 32.328 3.925 ;
     RECT  56.4 2.137 57.672 3.925 ;
     RECT  58.752 3.349 68.52 3.925 ;
     RECT  70.512 3.827 72.912 3.925 ;
     RECT  74.832 0.419 75.144 3.925 ;
     RECT  76.896 0.563 81.48 3.925 ;
     RECT  82.944 2.151 83.712 3.925 ;
     RECT  88.608 0.563 89.304 3.925 ;
     RECT  94.08 1.187 94.632 3.925 ;
     RECT  95.712 3.397 96.024 3.925 ;
     RECT  103.056 2.963 103.08 3.925 ;
     RECT  104.256 2.963 105.312 3.925 ;
     RECT  26.832 2.629 27.912 3.971 ;
     RECT  10.752 2.821 10.776 4.019 ;
     RECT  41.568 1.763 41.592 4.261 ;
     RECT  43.968 2.773 51.312 4.307 ;
     RECT  94.08 3.925 96.024 4.403 ;
     RECT  85.776 3.155 86.424 4.405 ;
     RECT  55.056 1.859 55.08 4.501 ;
     RECT  56.4 3.925 68.52 4.501 ;
     RECT  88.608 3.925 89.736 4.501 ;
     RECT  70.512 3.925 73.704 4.595 ;
     RECT  55.056 4.501 68.52 4.885 ;
     RECT  25.632 3.925 25.656 4.931 ;
     RECT  85.776 4.405 87.24 4.931 ;
     RECT  94.08 4.403 94.776 4.931 ;
     RECT  54.576 4.885 68.52 4.981 ;
     RECT  28.944 3.925 32.328 5.075 ;
     RECT  44.304 4.307 51.312 5.075 ;
     RECT  74.832 3.925 81.48 5.075 ;
     RECT  16.608 3.925 19.848 5.077 ;
     RECT  22.128 3.443 22.152 5.077 ;
     RECT  23.184 1.763 24.456 5.077 ;
     RECT  95.856 4.403 96.024 5.077 ;
     RECT  74.832 5.075 81.384 5.219 ;
     RECT  70.512 4.595 71.112 5.363 ;
     RECT  21.072 3.443 21.096 5.461 ;
     RECT  22.128 5.077 24.456 5.461 ;
     RECT  95.856 5.077 96.072 5.699 ;
     RECT  72.6 4.595 73.704 5.701 ;
     RECT  4.08 3.829 6.792 5.747 ;
     RECT  27.072 3.971 27.912 5.747 ;
     RECT  29.04 5.075 32.328 5.747 ;
     RECT  72.48 5.701 73.704 5.843 ;
     RECT  4.176 5.747 6.792 6.133 ;
     RECT  7.8 2.137 8.376 6.133 ;
     RECT  97.392 3.397 100.296 6.229 ;
     RECT  41.568 4.261 41.64 6.323 ;
     RECT  16.608 5.077 20.088 6.325 ;
     RECT  21.072 5.461 24.456 6.325 ;
     RECT  54.528 4.981 68.52 6.419 ;
     RECT  82.944 3.925 84.12 6.661 ;
     RECT  74.832 5.219 75.144 6.805 ;
     RECT  94.08 4.931 94.632 6.805 ;
     RECT  44.352 5.075 51.312 6.853 ;
     RECT  52.656 1.763 53.544 6.853 ;
     RECT  41.616 6.323 41.64 6.899 ;
     RECT  55.056 6.419 68.52 6.899 ;
     RECT  4.176 6.133 8.376 7.043 ;
     RECT  16.608 6.325 24.456 7.091 ;
     RECT  34.8 2.151 35.112 7.093 ;
     RECT  97.392 6.229 100.872 7.379 ;
     RECT  7.8 7.043 8.376 7.381 ;
     RECT  12.672 1.763 15.48 7.381 ;
     RECT  70.512 5.363 70.536 7.475 ;
     RECT  44.112 6.853 51.312 7.619 ;
     RECT  52.416 6.853 53.544 7.619 ;
     RECT  74.832 6.805 75.288 7.619 ;
     RECT  67.2 6.899 68.52 7.765 ;
     RECT  82.416 6.661 84.12 7.811 ;
     RECT  67.2 7.765 69 7.907 ;
     RECT  76.896 5.219 81.384 8.003 ;
     RECT  93.888 6.805 94.632 8.003 ;
     RECT  95.856 5.699 96.024 8.053 ;
     RECT  82.608 7.811 84.12 8.147 ;
     RECT  97.392 7.379 100.296 8.341 ;
     RECT  7.8 7.381 9.048 8.435 ;
     RECT  34.128 7.093 35.112 8.435 ;
     RECT  55.056 6.899 66.072 8.579 ;
     RECT  97.392 8.341 101.16 8.675 ;
     RECT  85.776 4.931 86.424 8.773 ;
     RECT  88.368 4.501 89.736 8.819 ;
     RECT  94.08 8.003 94.632 8.965 ;
     RECT  95.616 8.053 96.024 8.965 ;
     RECT  69.792 7.909 69.816 9.011 ;
     RECT  55.056 8.579 55.08 9.061 ;
     RECT  12.48 7.381 15.48 9.107 ;
     RECT  92.544 0.563 92.568 9.109 ;
     RECT  16.608 7.091 21.096 9.155 ;
     RECT  92.544 9.109 92.664 9.155 ;
     RECT  94.08 8.965 96.024 9.203 ;
     RECT  41.616 8.389 41.64 9.251 ;
     RECT  82.608 8.147 84.072 9.253 ;
     RECT  4.176 7.043 6.792 9.301 ;
     RECT  7.8 8.435 8.376 9.301 ;
     RECT  4.176 9.301 8.376 9.347 ;
     RECT  56.112 8.579 66.072 9.347 ;
     RECT  95.616 9.203 96.024 9.349 ;
     RECT  97.392 8.675 100.152 9.349 ;
     RECT  82.512 9.253 84.072 9.491 ;
     RECT  82.608 9.491 84.072 9.539 ;
     RECT  22.128 7.091 24.456 9.637 ;
     RECT  83.232 9.539 84.072 9.637 ;
     RECT  85.632 8.773 86.424 9.637 ;
     RECT  54.72 9.061 55.08 9.731 ;
     RECT  44.352 7.619 51.312 9.781 ;
     RECT  67.2 7.907 68.52 10.213 ;
     RECT  69.696 9.061 69.72 10.213 ;
     RECT  12.672 9.107 15.48 10.307 ;
     RECT  56.112 9.347 60.072 10.307 ;
     RECT  95.616 9.349 100.152 10.355 ;
     RECT  83.232 9.637 86.424 10.501 ;
     RECT  22.128 9.637 25.32 10.595 ;
     RECT  56.4 10.307 60.072 10.595 ;
     RECT  67.2 10.213 69.72 10.597 ;
     RECT  36.48 2.151 40.512 10.741 ;
     RECT  55.056 9.731 55.08 10.741 ;
     RECT  72.6 5.843 73.704 10.837 ;
     RECT  76.896 8.003 81.336 10.837 ;
     RECT  43.536 9.781 51.312 10.883 ;
     RECT  1.776 0.227 3 10.981 ;
     RECT  4.176 9.347 6.168 10.981 ;
     RECT  72.384 10.837 73.704 11.221 ;
     RECT  91.392 0.563 91.416 11.221 ;
     RECT  92.64 9.155 92.664 11.221 ;
     RECT  54.96 10.741 55.08 11.365 ;
     RECT  67.2 10.597 70.632 11.411 ;
     RECT  88.464 8.819 89.736 11.413 ;
     RECT  83.232 10.501 87.192 11.459 ;
     RECT  59.04 10.595 60.072 11.603 ;
     RECT  76.128 10.837 81.48 11.651 ;
     RECT  59.232 11.603 60.072 11.749 ;
     RECT  61.152 9.347 66.072 11.749 ;
     RECT  72.384 11.221 73.752 11.893 ;
     RECT  16.608 9.155 20.52 11.941 ;
     RECT  22.128 10.595 24.456 11.941 ;
     RECT  29.136 5.747 32.328 11.941 ;
     RECT  101.136 8.675 101.16 11.941 ;
     RECT  1.776 10.981 3.144 11.987 ;
     RECT  36.432 10.741 40.512 11.989 ;
     RECT  36.432 11.989 41.112 12.035 ;
     RECT  69.696 11.411 70.632 12.035 ;
     RECT  76.272 11.651 81.48 12.035 ;
     RECT  91.392 11.221 92.664 12.035 ;
     RECT  95.616 10.355 96.024 12.037 ;
     RECT  33.6 10.981 33.624 12.083 ;
     RECT  95.616 12.037 96.408 12.179 ;
     RECT  101.136 11.941 101.832 12.227 ;
     RECT  44.352 10.883 51.312 12.517 ;
     RECT  83.232 11.459 84.264 12.517 ;
     RECT  4.176 10.981 6.312 12.563 ;
     RECT  71.808 11.893 73.752 12.563 ;
     RECT  88.464 11.413 89.928 12.755 ;
     RECT  12.912 10.307 15.48 12.853 ;
     RECT  34.8 8.435 35.112 13.045 ;
     RECT  10.896 11.941 10.92 13.091 ;
     RECT  29.088 11.941 32.328 13.099 ;
     RECT  43.968 12.517 51.312 13.139 ;
     RECT  95.856 12.179 96.408 13.139 ;
     RECT  16.608 11.941 24.456 13.187 ;
     RECT  69.696 12.035 69.72 13.187 ;
     RECT  97.392 10.355 100.152 13.189 ;
     RECT  101.136 12.227 101.448 13.189 ;
     RECT  12.864 12.853 15.48 13.331 ;
     RECT  52.656 7.619 53.544 13.477 ;
     RECT  54.72 11.365 55.08 13.477 ;
     RECT  67.2 11.411 68.52 13.573 ;
     RECT  72.6 12.563 73.752 13.573 ;
     RECT  74.832 7.619 75.144 13.573 ;
     RECT  36.48 12.035 38.76 13.621 ;
     RECT  39.936 12.035 41.112 13.621 ;
     RECT  97.392 13.189 101.448 13.715 ;
     RECT  76.272 12.035 81.336 13.763 ;
     RECT  36.48 13.621 41.112 13.907 ;
     RECT  88.464 12.755 89.736 13.957 ;
     RECT  95.856 13.139 96.024 13.957 ;
     RECT  20.448 13.187 24.456 14.099 ;
     RECT  56.4 10.595 58.008 14.101 ;
     RECT  85.776 11.459 87.192 14.101 ;
     RECT  88.368 13.957 89.736 14.101 ;
     RECT  94.08 9.203 94.632 14.101 ;
     RECT  34.8 13.045 35.304 14.147 ;
     RECT  59.232 11.749 66.072 14.291 ;
     RECT  72.6 13.573 75.144 14.291 ;
     RECT  20.448 14.099 21.144 14.293 ;
     RECT  60.048 14.291 66.072 14.339 ;
     RECT  20.112 14.293 21.144 14.483 ;
     RECT  20.112 14.483 20.52 14.675 ;
     RECT  29.136 13.099 32.328 14.773 ;
     RECT  67.2 13.573 69.24 14.819 ;
     RECT  95.712 13.957 96.024 14.819 ;
     RECT  85.776 14.101 89.736 14.867 ;
     RECT  43.968 13.139 46.104 14.963 ;
     RECT  52.656 13.477 55.08 15.155 ;
     RECT  95.856 14.819 96.024 15.157 ;
     RECT  83.232 12.517 84.696 15.203 ;
     RECT  22.128 14.099 24.456 15.397 ;
     RECT  47.184 13.139 51.312 15.443 ;
     RECT  60.048 14.339 65.304 15.443 ;
     RECT  27.072 5.747 27.864 15.445 ;
     RECT  7.44 9.347 8.376 15.587 ;
     RECT  95.856 15.157 96.36 15.683 ;
     RECT  20.448 14.675 20.52 15.733 ;
     RECT  12.912 13.331 15.48 15.829 ;
     RECT  16.608 13.187 18.912 15.829 ;
     RECT  83.232 15.203 84.264 15.925 ;
     RECT  97.392 13.715 101.4 15.971 ;
     RECT  21.648 15.397 24.456 16.019 ;
     RECT  26.832 15.445 27.864 16.019 ;
     RECT  44.352 14.963 46.104 16.019 ;
     RECT  56.304 14.101 58.008 16.019 ;
     RECT  103.056 3.925 105.312 16.019 ;
     RECT  9.984 14.869 10.008 16.307 ;
     RECT  34.8 14.147 35.112 16.453 ;
     RECT  20.208 15.733 20.52 16.595 ;
     RECT  29.136 14.773 32.76 16.885 ;
     RECT  36.48 13.907 40.512 16.933 ;
     RECT  67.2 14.819 68.856 16.933 ;
     RECT  49.968 15.443 51.312 16.981 ;
     RECT  52.656 15.155 53.544 16.981 ;
     RECT  83.136 15.925 84.264 16.981 ;
     RECT  85.776 14.867 89.304 16.981 ;
     RECT  72.6 14.291 73.752 17.027 ;
     RECT  22.128 16.019 24.456 17.029 ;
     RECT  44.352 16.019 45.912 17.029 ;
     RECT  47.184 15.443 48.264 17.029 ;
     RECT  94.032 14.101 94.632 17.029 ;
     RECT  12.912 15.829 18.912 17.075 ;
     RECT  29.088 16.885 32.76 17.075 ;
     RECT  54.624 15.155 55.08 17.075 ;
     RECT  59.52 16.069 59.544 17.075 ;
     RECT  60.528 15.443 64.824 17.075 ;
     RECT  56.4 16.019 58.008 17.077 ;
     RECT  92.304 12.035 92.664 17.077 ;
     RECT  94.032 17.029 94.728 17.077 ;
     RECT  29.088 17.075 32.328 17.123 ;
     RECT  22.128 17.029 24.504 17.171 ;
     RECT  83.136 16.981 89.304 17.171 ;
     RECT  36.48 16.933 40.92 17.219 ;
     RECT  84.912 17.171 89.304 17.219 ;
     RECT  93.984 17.077 94.728 17.219 ;
     RECT  92.304 17.077 92.952 17.267 ;
     RECT  1.776 11.987 3 17.461 ;
     RECT  64.08 17.075 64.824 17.461 ;
     RECT  23.184 17.171 24.504 17.507 ;
     RECT  7.68 15.587 8.376 17.509 ;
     RECT  93.984 17.219 94.632 17.509 ;
     RECT  16.608 17.075 18.912 17.605 ;
     RECT  92.304 17.267 92.568 17.605 ;
     RECT  97.392 15.971 100.152 17.605 ;
     RECT  49.968 16.981 53.544 17.651 ;
     RECT  20.496 16.595 20.52 17.653 ;
     RECT  85.776 17.219 89.304 17.747 ;
     RECT  56.4 17.077 58.872 17.891 ;
     RECT  16.608 17.605 19.368 18.035 ;
     RECT  34.8 16.453 35.208 18.133 ;
     RECT  97.296 17.605 100.152 18.179 ;
     RECT  1.776 17.461 3.192 18.227 ;
     RECT  91.968 17.605 92.568 18.227 ;
     RECT  44.352 17.029 48.264 18.275 ;
     RECT  76.896 13.763 81.336 18.275 ;
     RECT  97.296 18.179 100.056 18.323 ;
     RECT  36.48 17.219 40.512 18.419 ;
     RECT  52.752 17.651 53.544 18.419 ;
     RECT  101.376 15.971 101.4 18.563 ;
     RECT  53.28 18.419 53.544 18.709 ;
     RECT  55.056 17.075 55.08 18.709 ;
     RECT  72.6 17.027 73.704 18.757 ;
     RECT  74.832 14.291 75.144 18.757 ;
     RECT  87.552 17.747 89.304 18.757 ;
     RECT  44.352 18.275 46.728 18.803 ;
     RECT  64.08 17.461 65.592 18.803 ;
     RECT  4.176 12.563 6.168 18.851 ;
     RECT  36.48 18.419 37.416 18.851 ;
     RECT  48 18.275 48.264 18.851 ;
     RECT  93.648 17.509 94.632 18.851 ;
     RECT  103.488 16.019 105.312 18.851 ;
     RECT  67.2 16.933 68.952 18.947 ;
     RECT  11.712 18.181 11.736 18.995 ;
     RECT  7.248 17.509 8.376 19.043 ;
     RECT  39.024 18.419 40.512 19.091 ;
     RECT  53.28 18.709 55.08 19.091 ;
     RECT  16.608 18.035 19.032 19.139 ;
     RECT  40.08 19.091 40.512 19.237 ;
     RECT  22.128 17.171 22.152 19.285 ;
     RECT  23.184 17.507 24.456 19.285 ;
     RECT  40.08 19.237 40.728 19.379 ;
     RECT  76.896 18.275 81.048 19.379 ;
     RECT  4.176 18.851 5.016 19.427 ;
     RECT  16.608 19.139 16.632 19.427 ;
     RECT  25.776 18.757 25.8 19.427 ;
     RECT  85.776 17.747 86.424 19.427 ;
     RECT  83.136 17.171 83.712 19.429 ;
     RECT  33.984 18.133 35.208 19.475 ;
     RECT  97.392 18.323 100.056 19.477 ;
     RECT  53.28 19.091 53.544 19.523 ;
     RECT  27.072 16.019 27.864 19.621 ;
     RECT  42.864 17.605 42.888 19.621 ;
     RECT  48 18.851 48.024 19.621 ;
     RECT  49.968 17.651 51.312 19.621 ;
     RECT  60.528 17.075 63.096 19.621 ;
     RECT  64.08 18.803 65.256 19.621 ;
     RECT  42.864 19.621 43.272 19.667 ;
     RECT  20.496 17.653 20.808 19.763 ;
     RECT  85.776 19.427 85.8 19.765 ;
     RECT  92.304 18.227 92.568 19.861 ;
     RECT  29.136 17.123 32.328 19.909 ;
     RECT  26.208 19.621 27.864 19.955 ;
     RECT  12.912 17.075 15.48 19.957 ;
     RECT  72.6 18.757 75.144 19.957 ;
     RECT  92.304 19.861 92.952 20.003 ;
     RECT  67.2 18.947 68.856 20.005 ;
     RECT  67.2 20.005 69.672 20.147 ;
     RECT  39.024 19.091 39.048 20.149 ;
     RECT  40.08 19.379 40.512 20.149 ;
     RECT  70.704 19.909 70.728 20.197 ;
     RECT  72.6 19.957 75.288 20.197 ;
     RECT  97.392 19.477 100.488 20.291 ;
     RECT  27.072 19.955 27.864 20.293 ;
     RECT  29.136 19.909 33.048 20.293 ;
     RECT  82.656 19.429 83.712 20.293 ;
     RECT  43.248 19.667 43.272 20.339 ;
     RECT  9.696 17.605 9.72 20.341 ;
     RECT  77.856 19.379 81.048 20.341 ;
     RECT  87.552 18.757 89.448 20.437 ;
     RECT  47.808 19.621 48.024 20.579 ;
     RECT  60.528 19.621 65.256 20.579 ;
     RECT  70.704 20.197 75.288 20.579 ;
     RECT  53.28 19.523 53.304 20.581 ;
     RECT  77.232 20.341 81.048 20.581 ;
     RECT  82.656 20.293 83.928 20.581 ;
     RECT  60.528 20.579 64.824 20.627 ;
     RECT  82.656 20.581 84.216 20.627 ;
     RECT  61.152 20.627 64.824 20.723 ;
     RECT  85.488 19.765 85.8 20.819 ;
     RECT  12.912 19.957 15.576 20.867 ;
     RECT  59.424 20.437 59.448 20.915 ;
     RECT  85.776 20.819 85.8 21.013 ;
     RECT  93.984 18.851 94.632 21.013 ;
     RECT  74.784 20.579 75.288 21.059 ;
     RECT  18.336 19.139 19.032 21.061 ;
     RECT  20.496 19.763 20.568 21.061 ;
     RECT  83.184 20.627 84.216 21.061 ;
     RECT  103.968 18.851 105.312 21.061 ;
     RECT  39.024 20.149 40.512 21.155 ;
     RECT  48 20.579 48.024 21.155 ;
     RECT  49.056 19.621 51.312 21.155 ;
     RECT  67.2 20.147 69.192 21.155 ;
     RECT  85.776 21.013 86.04 21.155 ;
     RECT  92.544 20.003 92.952 21.155 ;
     RECT  93.984 21.013 94.728 21.155 ;
     RECT  9.504 20.341 9.72 21.251 ;
     RECT  61.152 20.723 63.096 21.251 ;
     RECT  34.8 19.475 35.208 21.253 ;
     RECT  22.128 19.285 24.456 21.397 ;
     RECT  56.4 17.891 58.008 21.541 ;
     RECT  67.2 21.155 68.856 21.541 ;
     RECT  12.912 20.867 15.48 21.637 ;
     RECT  27.072 20.293 33.048 21.637 ;
     RECT  83.184 21.061 84.312 21.637 ;
     RECT  103.872 21.061 105.312 21.637 ;
     RECT  4.176 19.427 4.968 21.683 ;
     RECT  9.504 21.251 9.672 21.683 ;
     RECT  12.672 21.637 15.48 21.683 ;
     RECT  18.336 21.061 20.568 21.683 ;
     RECT  53.232 20.581 53.304 21.683 ;
     RECT  87.552 20.437 90.36 21.683 ;
     RECT  103.488 21.637 105.312 21.683 ;
     RECT  34.8 21.253 35.256 21.685 ;
     RECT  9.648 21.683 9.672 21.731 ;
     RECT  39.024 21.155 39.048 21.731 ;
     RECT  67.104 21.541 68.856 21.731 ;
     RECT  22.128 21.397 25.224 21.923 ;
     RECT  70.704 20.579 73.704 21.923 ;
     RECT  7.584 19.043 8.376 21.925 ;
     RECT  67.104 21.731 68.52 22.069 ;
     RECT  93.984 21.155 94.632 22.117 ;
     RECT  27.072 21.637 33.144 22.165 ;
     RECT  36.48 18.851 37.176 22.165 ;
     RECT  40.08 21.155 40.512 22.165 ;
     RECT  74.784 21.059 75.144 22.165 ;
     RECT  95.856 15.683 96.024 22.165 ;
     RECT  97.392 20.291 100.056 22.165 ;
     RECT  18.336 21.683 20.52 22.211 ;
     RECT  36.48 22.165 37.368 22.259 ;
     RECT  56.4 21.541 58.296 22.307 ;
     RECT  11.136 21.973 11.16 22.451 ;
     RECT  103.488 21.683 103.512 22.499 ;
     RECT  53.232 21.683 53.256 22.547 ;
     RECT  44.352 18.803 46.344 22.693 ;
     RECT  64.08 20.723 64.824 22.741 ;
     RECT  66.672 22.069 68.52 22.741 ;
     RECT  93.984 22.117 94.68 22.789 ;
     RECT  6.144 18.851 6.168 22.835 ;
     RECT  40.08 22.165 41.4 22.835 ;
     RECT  66.672 22.741 69.384 22.835 ;
     RECT  76.992 20.581 81.048 22.835 ;
     RECT  85.776 21.155 85.8 22.835 ;
     RECT  26.16 22.165 33.144 22.979 ;
     RECT  102 21.637 102.024 23.027 ;
     RECT  83.184 21.637 84.36 23.075 ;
     RECT  61.392 21.251 63.096 23.125 ;
     RECT  7.296 21.925 8.376 23.173 ;
     RECT  95.856 22.165 100.056 23.173 ;
     RECT  61.344 23.125 63.096 23.269 ;
     RECT  4.944 21.683 4.968 23.317 ;
     RECT  40.08 22.835 41.16 23.317 ;
     RECT  26.16 22.979 33.048 23.363 ;
     RECT  72.288 21.923 73.704 23.363 ;
     RECT  74.688 22.165 75.144 23.363 ;
     RECT  26.16 23.363 27.864 23.411 ;
     RECT  64.08 22.741 65.352 23.411 ;
     RECT  70.704 21.923 70.728 23.411 ;
     RECT  103.92 23.269 103.944 23.411 ;
     RECT  67.104 22.835 69.384 23.555 ;
     RECT  95.856 23.173 100.392 23.603 ;
     RECT  56.4 22.307 58.008 23.605 ;
     RECT  18.336 22.211 19.128 23.701 ;
     RECT  20.496 22.211 20.52 23.701 ;
     RECT  7.296 23.173 8.664 23.891 ;
     RECT  22.128 21.923 24.456 23.893 ;
     RECT  105 21.683 105.312 23.893 ;
     RECT  61.2 23.269 63.096 23.939 ;
     RECT  29.136 23.363 33.048 23.987 ;
     RECT  34.8 21.685 35.352 23.987 ;
     RECT  76.992 22.835 80.568 23.987 ;
     RECT  43.68 22.693 46.344 24.179 ;
     RECT  93.6 22.789 94.68 24.179 ;
     RECT  55.056 19.091 55.08 24.181 ;
     RECT  56.4 23.605 58.536 24.181 ;
     RECT  79.584 23.987 80.568 24.277 ;
     RECT  44.352 24.179 46.344 24.325 ;
     RECT  55.056 24.181 58.536 24.325 ;
     RECT  64.8 23.411 65.352 24.371 ;
     RECT  64.8 24.371 64.824 24.469 ;
     RECT  48.432 23.893 48.456 24.515 ;
     RECT  97.392 23.603 100.392 24.563 ;
     RECT  85.536 23.029 85.56 24.611 ;
     RECT  10.512 23.557 10.536 24.659 ;
     RECT  18.336 23.701 20.52 24.659 ;
     RECT  39.936 23.317 41.16 24.659 ;
     RECT  101.568 23.845 101.592 24.659 ;
     RECT  48.384 24.757 48.408 24.947 ;
     RECT  90.96 24.469 90.984 24.947 ;
     RECT  4.176 23.317 4.968 25.043 ;
     RECT  7.296 23.891 8.376 25.045 ;
     RECT  22.128 23.893 24.696 25.045 ;
     RECT  104.736 23.893 105.312 25.091 ;
     RECT  67.104 23.555 68.52 25.139 ;
     RECT  83.232 23.075 84.36 25.141 ;
     RECT  61.344 23.939 63.096 25.187 ;
     RECT  87.552 21.683 89.448 25.285 ;
     RECT  83.184 25.141 84.36 25.475 ;
     RECT  72.6 23.363 73.704 25.573 ;
     RECT  55.056 24.325 59.352 25.619 ;
     RECT  18.336 24.659 19.224 25.621 ;
     RECT  33.024 23.987 33.048 25.621 ;
     RECT  36.528 22.259 37.368 25.621 ;
     RECT  4.56 25.043 4.968 25.715 ;
     RECT  18.336 25.621 19.32 25.715 ;
     RECT  41.52 24.757 41.544 25.715 ;
     RECT  61.632 25.187 63.096 25.715 ;
     RECT  64.464 24.469 64.824 25.861 ;
     RECT  67.104 25.139 67.8 25.907 ;
     RECT  72.384 25.573 73.704 26.053 ;
     RECT  74.784 23.363 75.144 26.053 ;
     RECT  39.936 24.659 40.512 26.101 ;
     RECT  92.544 21.155 92.568 26.149 ;
     RECT  64.464 25.861 64.872 26.195 ;
     RECT  34.8 23.987 35.112 26.197 ;
     RECT  72.384 26.053 75.144 26.197 ;
     RECT  79.584 24.277 80.712 26.197 ;
     RECT  21.648 25.045 24.696 26.243 ;
     RECT  43.056 25.189 43.08 26.243 ;
     RECT  64.8 26.195 64.872 26.243 ;
     RECT  79.488 26.197 80.712 26.243 ;
     RECT  56.4 25.619 59.352 26.245 ;
     RECT  83.232 25.475 84.36 26.389 ;
     RECT  34.8 26.197 35.304 26.437 ;
     RECT  17.136 25.429 17.16 26.483 ;
     RECT  33.024 25.621 33.528 26.531 ;
     RECT  36.528 25.621 37.704 26.579 ;
     RECT  80.544 26.243 80.712 26.579 ;
     RECT  29.136 23.987 31.512 26.581 ;
     RECT  68.928 25.477 68.952 26.675 ;
     RECT  72.384 26.197 75.864 26.675 ;
     RECT  76.992 23.987 78.456 26.675 ;
     RECT  93.6 24.179 94.632 26.677 ;
     RECT  95.856 23.603 96.024 26.677 ;
     RECT  39.936 26.101 41.256 26.723 ;
     RECT  105 25.091 105.312 26.725 ;
     RECT  11.664 25.045 11.688 26.819 ;
     RECT  21.648 26.243 24.456 26.819 ;
     RECT  36.528 26.579 37.368 26.819 ;
     RECT  61.632 25.715 62.112 26.819 ;
     RECT  56.4 26.245 59.832 26.821 ;
     RECT  12.672 21.683 14.664 27.011 ;
     RECT  72.6 26.675 75.864 27.059 ;
     RECT  87.552 25.285 89.592 27.059 ;
     RECT  29.088 26.581 31.512 27.107 ;
     RECT  53.616 25.045 53.64 27.205 ;
     RECT  55.056 25.619 55.176 27.205 ;
     RECT  87.552 27.059 89.448 27.205 ;
     RECT  4.56 25.715 4.584 27.347 ;
     RECT  44.352 24.325 46.44 27.395 ;
     RECT  91.728 26.149 92.568 27.395 ;
     RECT  34.8 26.437 35.352 27.635 ;
     RECT  29.136 27.107 31.512 27.781 ;
     RECT  33.024 26.531 33.048 27.781 ;
     RECT  29.136 27.781 33.048 27.827 ;
     RECT  37.104 26.819 37.368 27.829 ;
     RECT  21.648 26.819 24.312 27.877 ;
     RECT  76.992 26.675 78.312 27.877 ;
     RECT  93.6 26.677 96.024 27.877 ;
     RECT  97.392 24.563 100.248 27.877 ;
     RECT  87.12 27.205 89.448 27.923 ;
     RECT  104.736 26.725 105.312 27.923 ;
     RECT  29.136 27.827 32.28 27.971 ;
     RECT  83.232 26.389 85.272 28.019 ;
     RECT  93.6 27.877 100.248 28.019 ;
     RECT  30.768 27.971 32.28 28.115 ;
     RECT  53.616 27.205 55.176 28.163 ;
     RECT  79.488 26.243 79.512 28.163 ;
     RECT  29.136 27.971 29.712 28.211 ;
     RECT  61.8 26.819 62.112 28.261 ;
     RECT  50.448 21.155 51.312 28.309 ;
     RECT  72.6 27.059 75.144 28.309 ;
     RECT  76.368 27.877 78.312 28.309 ;
     RECT  54.672 28.163 55.176 28.453 ;
     RECT  72.6 28.309 78.312 28.453 ;
     RECT  1.776 18.227 3 28.547 ;
     RECT  12.672 27.011 14.424 28.547 ;
     RECT  38.736 27.349 38.76 28.691 ;
     RECT  87.12 27.923 87.144 28.739 ;
     RECT  97.392 28.019 100.248 28.739 ;
     RECT  40.08 26.723 41.256 28.789 ;
     RECT  83.232 28.019 84.36 28.789 ;
     RECT  34.8 27.635 35.208 28.885 ;
     RECT  82.032 23.317 82.056 28.933 ;
     RECT  7.296 25.045 8.472 28.979 ;
     RECT  17.184 27.877 17.208 28.981 ;
     RECT  17.088 28.981 17.208 29.027 ;
     RECT  18.6 25.715 19.32 29.029 ;
     RECT  20.496 24.659 20.52 29.029 ;
     RECT  36.576 27.829 37.368 29.077 ;
     RECT  98.16 28.739 100.248 29.077 ;
     RECT  17.088 29.027 17.112 29.123 ;
     RECT  83.088 28.789 84.36 29.123 ;
     RECT  88.32 27.923 89.448 29.123 ;
     RECT  72.432 28.453 79.224 29.171 ;
     RECT  42.576 28.789 42.6 29.219 ;
     RECT  68.928 27.829 68.952 29.219 ;
     RECT  88.32 29.123 89.112 29.221 ;
     RECT  98.16 29.077 100.92 29.267 ;
     RECT  56.4 26.821 60.408 29.315 ;
     RECT  53.616 28.163 53.64 29.317 ;
     RECT  54.672 28.453 55.272 29.317 ;
     RECT  61.68 28.261 62.112 29.411 ;
     RECT  88.224 29.221 89.112 29.459 ;
     RECT  21.648 27.877 24.84 29.509 ;
     RECT  92.544 27.395 92.568 29.509 ;
     RECT  93.6 28.019 96.024 29.509 ;
     RECT  18.6 29.029 20.52 29.605 ;
     RECT  34.8 28.885 35.304 29.605 ;
     RECT  56.4 29.315 59.352 29.605 ;
     RECT  81.888 28.933 82.056 29.605 ;
     RECT  7.296 28.979 8.424 29.653 ;
     RECT  40.08 28.789 41.544 29.699 ;
     RECT  44.784 27.395 46.44 29.699 ;
     RECT  81.696 29.605 82.056 29.699 ;
     RECT  92.544 29.509 96.024 29.699 ;
     RECT  10.224 28.453 10.248 29.747 ;
     RECT  53.616 29.317 55.272 29.747 ;
     RECT  45.504 29.699 46.44 29.795 ;
     RECT  92.544 29.699 95.88 29.795 ;
     RECT  13.104 28.547 14.424 29.843 ;
     RECT  18.384 29.605 20.52 29.843 ;
     RECT  34.704 29.605 35.304 29.893 ;
     RECT  72.432 29.171 75.96 30.035 ;
     RECT  29.28 28.211 29.712 30.179 ;
     RECT  76.992 29.171 79.224 30.179 ;
     RECT  72.48 30.035 75.96 30.181 ;
     RECT  76.992 30.179 78.744 30.181 ;
     RECT  31.2 28.115 32.28 30.229 ;
     RECT  64.848 26.243 64.872 30.229 ;
     RECT  64.656 30.229 64.872 30.275 ;
     RECT  98.16 29.267 100.248 30.275 ;
     RECT  6.912 29.653 8.424 30.371 ;
     RECT  31.2 30.229 33.144 30.371 ;
     RECT  21.648 29.509 24.984 30.373 ;
     RECT  88.32 29.459 89.112 30.419 ;
     RECT  105 27.923 105.312 30.421 ;
     RECT  11.904 29.653 11.928 30.611 ;
     RECT  56.304 29.605 59.352 30.611 ;
     RECT  27.072 23.411 27.864 30.661 ;
     RECT  72.48 30.181 78.744 30.755 ;
     RECT  21.648 30.373 25.464 30.803 ;
     RECT  26.736 30.661 27.864 30.803 ;
     RECT  50.448 28.309 51.768 30.803 ;
     RECT  97.056 29.941 97.08 30.805 ;
     RECT  34.656 29.893 35.304 30.851 ;
     RECT  36.576 29.077 38.184 30.851 ;
     RECT  41.52 29.699 41.544 30.851 ;
     RECT  45.6 29.795 46.44 30.851 ;
     RECT  53.616 29.747 55.224 30.899 ;
     RECT  94.08 29.795 95.88 30.899 ;
     RECT  96.912 30.805 97.128 30.947 ;
     RECT  94.08 30.899 94.512 30.995 ;
     RECT  83.184 29.123 84.36 30.997 ;
     RECT  53.616 30.899 54.744 31.187 ;
     RECT  18.6 29.843 20.52 31.285 ;
     RECT  104.112 30.421 105.312 31.285 ;
     RECT  3.984 30.661 4.008 31.331 ;
     RECT  81.696 29.699 81.912 31.333 ;
     RECT  83.04 30.997 84.36 31.333 ;
     RECT  18.6 31.285 20.952 31.379 ;
     RECT  59.328 30.611 59.352 31.379 ;
     RECT  80.544 26.579 80.568 31.379 ;
     RECT  92.544 29.795 92.904 31.379 ;
     RECT  98.256 30.275 100.248 31.379 ;
     RECT  81.696 31.333 84.36 31.427 ;
     RECT  88.464 30.419 89.112 31.525 ;
     RECT  47.856 29.605 47.88 31.571 ;
     RECT  54.72 31.187 54.744 31.619 ;
     RECT  87.984 31.525 89.112 31.667 ;
     RECT  95.856 30.899 95.88 31.669 ;
     RECT  5.76 30.469 5.784 31.765 ;
     RECT  4.944 31.765 5.784 31.811 ;
     RECT  92.88 31.379 92.904 31.907 ;
     RECT  97.056 30.947 97.128 31.907 ;
     RECT  27.072 30.803 27.864 31.909 ;
     RECT  95.856 31.669 96.024 31.909 ;
     RECT  97.056 31.907 97.08 31.909 ;
     RECT  1.776 28.547 2.712 31.955 ;
     RECT  6.912 30.371 8.328 31.955 ;
     RECT  13.2 29.843 14.424 31.955 ;
     RECT  21.984 30.803 25.464 31.955 ;
     RECT  36.576 30.851 37.368 31.955 ;
     RECT  40.08 29.699 40.512 31.955 ;
     RECT  56.304 30.611 58.008 31.955 ;
     RECT  67.2 25.907 67.8 31.955 ;
     RECT  88.464 31.667 89.112 31.955 ;
     RECT  95.856 31.909 97.08 31.955 ;
     RECT  98.688 31.379 100.248 31.955 ;
     RECT  2.16 31.955 2.712 32.003 ;
     RECT  56.304 31.955 57.048 32.003 ;
     RECT  76.512 30.755 78.744 32.003 ;
     RECT  81.696 31.427 84.072 32.099 ;
     RECT  56.304 32.003 57 32.293 ;
     RECT  72.48 30.755 75.144 32.339 ;
     RECT  4.944 31.811 5.688 32.341 ;
     RECT  104.016 31.285 105.312 32.341 ;
     RECT  15.408 30.229 15.432 32.435 ;
     RECT  60.384 29.315 60.408 32.437 ;
     RECT  86.016 30.709 86.04 32.437 ;
     RECT  41.568 31.045 41.592 32.483 ;
     RECT  29.4 30.179 29.712 32.485 ;
     RECT  3.984 32.341 5.688 32.531 ;
     RECT  72.6 32.339 75.144 32.531 ;
     RECT  98.688 31.955 100.056 32.531 ;
     RECT  26.688 31.909 27.864 32.725 ;
     RECT  45.6 30.851 46.104 32.771 ;
     RECT  103.68 32.341 105.312 32.771 ;
     RECT  103.68 32.771 103.848 32.773 ;
     RECT  26.544 32.725 27.864 32.821 ;
     RECT  29.4 32.485 30.264 32.821 ;
     RECT  34.8 30.851 35.304 32.915 ;
     RECT  82.704 32.099 84.072 32.963 ;
     RECT  85.44 32.437 86.04 33.011 ;
     RECT  88.704 31.955 89.112 33.013 ;
     RECT  26.544 32.821 28.152 33.059 ;
     RECT  21.984 31.955 24.312 33.107 ;
     RECT  60.336 32.437 60.408 33.107 ;
     RECT  75.072 32.531 75.096 33.107 ;
     RECT  81.552 32.245 81.576 33.107 ;
     RECT  103.2 32.773 103.848 33.107 ;
     RECT  99.6 32.531 100.056 33.299 ;
     RECT  13.2 31.955 13.656 33.445 ;
     RECT  34.8 32.915 35.208 33.539 ;
     RECT  29.28 32.821 30.264 33.587 ;
     RECT  96 31.955 97.08 33.587 ;
     RECT  45.6 32.771 45.912 33.589 ;
     RECT  99.6 33.299 99.912 33.589 ;
     RECT  85.44 33.011 85.464 33.635 ;
     RECT  88.704 33.013 89.736 33.635 ;
     RECT  55.824 32.293 57 33.683 ;
     RECT  64.656 30.275 64.68 33.683 ;
     RECT  10.704 33.013 10.728 33.827 ;
     RECT  60.384 33.107 60.408 33.827 ;
     RECT  26.688 33.059 28.152 33.973 ;
     RECT  101.856 30.997 101.88 34.021 ;
     RECT  6.912 31.955 8.112 34.069 ;
     RECT  36.576 31.955 36.6 34.115 ;
     RECT  18.6 31.379 19.848 34.117 ;
     RECT  20.928 31.379 20.952 34.117 ;
     RECT  94.2 30.995 94.512 34.117 ;
     RECT  21.984 33.107 22.296 34.163 ;
     RECT  31.296 30.371 33.144 34.213 ;
     RECT  31.296 34.213 33.624 34.259 ;
     RECT  76.512 32.003 76.536 34.259 ;
     RECT  83.04 32.963 84.072 34.259 ;
     RECT  26.688 33.973 28.392 34.307 ;
     RECT  59.856 34.069 60.12 34.355 ;
     RECT  103.2 33.107 103.752 34.355 ;
     RECT  96.768 33.587 97.08 34.403 ;
     RECT  2.4 32.003 2.712 34.501 ;
     RECT  3.984 32.531 4.968 34.501 ;
     RECT  25.44 31.955 25.464 34.501 ;
     RECT  2.4 34.501 5.112 34.547 ;
     RECT  18.6 34.117 20.952 34.741 ;
     RECT  55.824 33.683 56.712 34.789 ;
     RECT  18.048 34.741 20.952 34.835 ;
     RECT  74.112 34.165 74.136 34.835 ;
     RECT  97.056 34.403 97.08 34.835 ;
     RECT  23.712 33.107 24.312 34.883 ;
     RECT  33.12 34.259 33.624 34.883 ;
     RECT  27.84 34.307 28.392 34.931 ;
     RECT  101.328 34.021 101.88 35.173 ;
     RECT  67.2 31.955 67.512 35.269 ;
     RECT  101.088 35.173 101.88 35.269 ;
     RECT  103.2 34.355 103.704 35.269 ;
     RECT  98.784 33.589 99.912 35.315 ;
     RECT  101.088 35.269 103.704 35.315 ;
     RECT  2.4 34.547 3.432 35.363 ;
     RECT  18.048 34.835 19.944 35.363 ;
     RECT  21.984 34.163 22.008 35.363 ;
     RECT  44.688 33.589 45.912 35.363 ;
     RECT  6.288 34.069 8.112 35.411 ;
     RECT  101.088 35.315 102.648 35.651 ;
     RECT  75.312 34.741 75.336 35.699 ;
     RECT  51 30.803 51.312 35.701 ;
     RECT  53.616 31.187 53.64 35.701 ;
     RECT  55.824 34.789 56.856 35.747 ;
     RECT  18.6 35.363 19.944 35.843 ;
     RECT  4.944 34.547 5.112 35.939 ;
     RECT  15.984 35.317 16.008 35.939 ;
     RECT  92.688 34.501 92.712 35.939 ;
     RECT  25.44 34.501 26.136 35.987 ;
     RECT  85.584 35.317 85.608 35.987 ;
     RECT  40.2 31.955 40.512 35.989 ;
     RECT  38.592 34.597 38.616 36.035 ;
     RECT  23.904 34.883 24.312 36.083 ;
     RECT  29.4 33.587 30.264 36.083 ;
     RECT  67.2 35.269 68.28 36.083 ;
     RECT  72.6 32.531 72.912 36.085 ;
     RECT  24 36.083 24.312 36.229 ;
     RECT  31.296 34.259 31.32 36.275 ;
     RECT  76.896 35.029 76.92 36.275 ;
     RECT  42.768 35.845 42.792 36.323 ;
     RECT  33.12 34.883 33.144 36.421 ;
     RECT  34.8 33.539 35.112 36.421 ;
     RECT  83.04 34.259 83.712 36.421 ;
     RECT  88.704 33.635 89.112 36.421 ;
     RECT  101.856 35.651 102.648 36.467 ;
     RECT  18.6 35.843 19.848 36.515 ;
     RECT  28.368 34.931 28.392 36.515 ;
     RECT  40.2 35.989 41.4 36.515 ;
     RECT  53.616 35.701 53.832 36.515 ;
     RECT  87.744 36.421 89.112 36.515 ;
     RECT  50.88 35.701 51.312 36.563 ;
     RECT  101.856 36.467 101.88 36.563 ;
     RECT  97.44 35.077 97.464 36.611 ;
     RECT  24 36.229 24.408 36.613 ;
     RECT  25.44 35.987 25.464 36.613 ;
     RECT  72.48 36.085 72.912 36.757 ;
     RECT  47.952 35.989 47.976 36.803 ;
     RECT  71.568 36.757 72.912 36.803 ;
     RECT  94.2 34.117 94.632 36.901 ;
     RECT  6.864 35.411 8.112 36.947 ;
     RECT  2.4 35.363 2.712 36.949 ;
     RECT  78 32.003 78.744 36.997 ;
     RECT  10.8 36.421 10.824 37.043 ;
     RECT  70.032 36.085 70.056 37.043 ;
     RECT  20.928 34.835 20.952 37.045 ;
     RECT  37.92 36.517 37.944 37.091 ;
     RECT  99.6 35.315 99.912 37.477 ;
     RECT  74.112 37.333 74.136 37.525 ;
     RECT  71.568 36.803 71.592 37.571 ;
     RECT  66.048 37.525 66.072 37.573 ;
     RECT  77.712 36.997 78.744 37.573 ;
     RECT  79.728 36.997 80.424 37.573 ;
     RECT  83.04 36.421 84.168 37.573 ;
     RECT  87.744 36.515 87.768 37.619 ;
     RECT  99.6 37.477 100.248 37.621 ;
     RECT  103.68 35.315 103.704 37.667 ;
     RECT  94.2 36.901 95.16 37.859 ;
     RECT  74.112 37.525 74.52 37.861 ;
     RECT  12.96 33.445 13.656 37.907 ;
     RECT  15.36 36.853 15.384 37.907 ;
     RECT  6.576 36.997 6.6 38.005 ;
     RECT  13.2 37.907 13.656 38.005 ;
     RECT  65.76 37.573 66.072 38.005 ;
     RECT  4.944 35.939 5.016 38.149 ;
     RECT  67.2 36.083 68.088 38.149 ;
     RECT  83.04 37.573 84.6 38.195 ;
     RECT  24 36.613 25.464 38.243 ;
     RECT  77.712 37.573 80.424 38.339 ;
     RECT  20.928 37.045 21 38.435 ;
     RECT  43.872 36.229 43.896 38.435 ;
     RECT  20.928 38.435 20.952 38.675 ;
     RECT  6.24 38.005 6.6 38.677 ;
     RECT  7.8 36.947 8.112 38.677 ;
     RECT  77.712 38.339 79.752 38.677 ;
     RECT  77.568 38.677 79.752 38.723 ;
     RECT  1.776 36.949 2.712 38.773 ;
     RECT  4.752 38.149 5.016 38.819 ;
     RECT  13.2 38.005 13.752 38.819 ;
     RECT  18.6 36.515 19.752 38.819 ;
     RECT  47.328 38.197 47.352 38.819 ;
     RECT  96.576 37.573 96.6 39.013 ;
     RECT  96.192 39.013 96.6 39.157 ;
     RECT  60.096 34.355 60.12 39.251 ;
     RECT  88.8 36.515 89.112 39.301 ;
     RECT  92.304 38.581 92.328 39.347 ;
     RECT  6.24 38.677 8.112 39.395 ;
     RECT  83.04 38.195 84.552 39.395 ;
     RECT  72.6 36.803 72.912 39.397 ;
     RECT  65.568 38.005 66.072 39.539 ;
     RECT  1.776 38.773 3.48 39.731 ;
     RECT  33.12 36.421 35.112 39.829 ;
     RECT  31.776 39.061 31.8 39.875 ;
     RECT  88.8 39.301 89.256 39.875 ;
     RECT  33.12 39.829 35.208 39.923 ;
     RECT  55.824 35.747 56.712 39.923 ;
     RECT  58.8 38.725 58.824 40.019 ;
     RECT  88.8 39.875 89.112 40.021 ;
     RECT  83.4 39.395 84.552 40.259 ;
     RECT  18.6 38.819 18.912 40.405 ;
     RECT  64.08 36.997 64.104 40.405 ;
     RECT  66.048 39.539 66.072 40.453 ;
     RECT  67.2 38.149 68.904 40.453 ;
     RECT  77.568 38.723 78.312 40.499 ;
     RECT  33.936 39.923 35.208 40.547 ;
     RECT  96.192 39.157 97.032 40.549 ;
     RECT  9.36 39.877 9.384 40.883 ;
     RECT  72.288 39.397 72.912 40.933 ;
     RECT  74.112 37.861 75.336 40.933 ;
     RECT  1.776 39.731 2.712 40.981 ;
     RECT  4.992 38.819 5.016 40.981 ;
     RECT  6.576 39.395 8.112 40.981 ;
     RECT  13.2 38.819 13.608 40.981 ;
     RECT  18.24 40.405 18.912 40.981 ;
     RECT  20.448 39.781 20.472 40.981 ;
     RECT  24 38.243 24.504 40.981 ;
     RECT  38.352 40.405 38.376 40.981 ;
     RECT  45.6 35.363 45.912 40.981 ;
     RECT  51 36.563 51.312 40.981 ;
     RECT  53.616 36.515 53.64 40.981 ;
     RECT  55.2 40.933 55.224 40.981 ;
     RECT  63.264 40.405 64.104 40.981 ;
     RECT  66.048 40.453 68.904 40.981 ;
     RECT  77.712 40.499 78.312 40.981 ;
     RECT  79.728 38.723 79.752 40.981 ;
     RECT  86.16 40.933 86.184 40.981 ;
     RECT  94.2 37.859 94.512 40.981 ;
     RECT  96.192 40.549 97.416 40.981 ;
     RECT  99.504 37.621 100.248 40.981 ;
     RECT  103.44 40.933 103.464 40.981 ;
     RECT  102.24 40.981 103.464 41.029 ;
     RECT  4.992 40.981 8.112 41.049 ;
     RECT  17.04 40.981 21.096 41.049 ;
     RECT  29.4 36.083 29.712 41.049 ;
     RECT  33.936 40.547 35.112 41.049 ;
     RECT  40.2 36.515 40.512 41.049 ;
     RECT  44.784 40.981 45.912 41.049 ;
     RECT  50.016 40.981 51.312 41.049 ;
     RECT  56.4 39.923 56.712 41.049 ;
     RECT  61.8 29.411 62.112 41.049 ;
     RECT  88.176 40.021 89.112 41.049 ;
     RECT  105 32.771 105.312 41.049 ;
     RECT  1.776 40.981 3.816 41.063 ;
     RECT  4.992 41.049 7.92 41.063 ;
     RECT  17.04 41.049 18.72 41.063 ;
     RECT  24 40.981 25.08 41.063 ;
     RECT  29.4 41.049 29.52 41.063 ;
     RECT  33.936 41.049 34.92 41.063 ;
     RECT  40.2 41.049 40.32 41.063 ;
     RECT  44.784 41.049 45.72 41.063 ;
     RECT  50.016 41.049 51.24 41.063 ;
     RECT  56.4 41.049 56.52 41.063 ;
     RECT  61.8 41.049 61.92 41.063 ;
     RECT  83.4 40.259 84.168 41.063 ;
     RECT  88.176 41.049 88.92 41.063 ;
     RECT  105 41.049 105.12 41.063 ;
     RECT  72.096 40.933 72.912 41.125 ;
     RECT  27.888 37.573 27.912 41.557 ;
     RECT  52.416 40.981 52.44 41.557 ;
     RECT  53.616 40.981 55.224 41.557 ;
     RECT  66.048 40.981 69.288 41.557 ;
     RECT  77.712 40.981 79.752 41.557 ;
     RECT  83.76 41.063 84.168 41.557 ;
     RECT  85.344 40.981 86.568 41.557 ;
     RECT  36.336 41.557 36.36 41.605 ;
     RECT  37.92 40.981 38.376 41.605 ;
     RECT  1.776 41.063 2.184 42.085 ;
     RECT  3.36 41.063 3.816 42.085 ;
     RECT  1.776 42.085 3.816 42.133 ;
     RECT  12.24 40.981 13.608 42.133 ;
     RECT  17.04 41.063 18.504 42.133 ;
     RECT  19.872 41.049 21.096 42.133 ;
     RECT  25.056 41.063 25.08 42.133 ;
     RECT  30.72 40.981 30.744 42.133 ;
     RECT  32.736 40.405 32.76 42.133 ;
     RECT  33.936 41.063 34.728 42.133 ;
     RECT  41.952 40.981 41.976 42.133 ;
     RECT  43.152 40.981 43.176 42.133 ;
     RECT  44.784 41.063 44.808 42.133 ;
     RECT  46.8 41.557 46.824 42.133 ;
     RECT  48.384 41.605 48.408 42.133 ;
     RECT  50.016 41.063 50.04 42.133 ;
     RECT  51.216 41.063 51.24 42.133 ;
     RECT  52.416 41.557 55.224 42.133 ;
     RECT  59.232 40.981 59.256 42.133 ;
     RECT  63.264 40.981 64.872 42.133 ;
     RECT  66.048 41.557 70.536 42.133 ;
     RECT  74.112 40.933 75.72 42.133 ;
     RECT  77.328 41.557 79.752 42.133 ;
     RECT  82.56 41.557 82.584 42.133 ;
     RECT  83.76 41.557 86.568 42.133 ;
     RECT  88.176 41.063 88.2 42.133 ;
     RECT  90.576 40.837 90.6 42.133 ;
     RECT  93.408 40.981 97.416 42.133 ;
     RECT  99.408 40.981 100.248 42.133 ;
     RECT  4.992 41.063 7.032 42.181 ;
     RECT  10.224 42.133 10.632 42.181 ;
     RECT  23.472 42.133 25.08 42.181 ;
     RECT  36.336 41.605 38.76 42.181 ;
     RECT  41.136 42.133 41.976 42.181 ;
     RECT  46.368 42.133 47.208 42.181 ;
     RECT  48.384 42.133 48.792 42.181 ;
     RECT  60.864 42.133 61.272 42.181 ;
     RECT  62.832 42.133 64.872 42.181 ;
     RECT  66.048 42.133 70.92 42.181 ;
     RECT  72.096 41.125 72.936 42.181 ;
     RECT  74.112 42.133 79.752 42.181 ;
     RECT  88.176 42.133 91.416 42.181 ;
     RECT  93.408 42.133 100.248 42.181 ;
     RECT  101.424 41.029 103.464 42.181 ;
     RECT  52.416 42.133 56.04 42.901 ;
     RECT  58.416 42.133 59.256 42.901 ;
     RECT  60.864 42.181 70.92 42.901 ;
     RECT  81.36 42.181 81.384 42.901 ;
     RECT  82.56 42.133 87 42.901 ;
     RECT  88.176 42.181 100.248 42.901 ;
     RECT  50.016 42.133 51.24 42.949 ;
     RECT  52.416 42.901 59.256 42.949 ;
     RECT  60.432 42.901 70.92 42.949 ;
     RECT  72.096 42.181 79.752 42.949 ;
     RECT  80.928 42.901 100.248 42.949 ;
     RECT  101.424 42.181 104.664 42.949 ;
     RECT  11.808 42.133 13.608 42.997 ;
     RECT  15.84 40.981 15.864 42.997 ;
     RECT  17.04 42.133 21.912 42.997 ;
     RECT  23.472 42.181 26.328 42.997 ;
     RECT  27.888 41.557 28.728 42.997 ;
     RECT  40.368 42.181 41.976 42.997 ;
     RECT  43.152 42.133 45.192 42.997 ;
     RECT  46.368 42.181 48.792 42.997 ;
     RECT  1.392 42.133 3.816 43.045 ;
     RECT  4.992 42.181 10.632 43.045 ;
     RECT  11.808 42.997 14.232 43.045 ;
     RECT  15.84 42.997 21.912 43.045 ;
     RECT  23.472 42.997 28.728 43.045 ;
     RECT  29.904 42.133 34.728 43.045 ;
     RECT  35.952 42.181 38.76 43.045 ;
     RECT  39.936 42.997 48.792 43.045 ;
     RECT  50.016 42.949 104.664 43.045 ;
     RECT  1.392 43.045 104.664 43.152 ;
  END
END qfd_c_ring516
END LIBRARY
